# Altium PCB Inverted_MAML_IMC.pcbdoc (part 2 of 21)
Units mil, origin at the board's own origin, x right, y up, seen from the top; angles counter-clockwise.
Board outline 7677.1 x 6771.6 mil, 6 copper layers (Top Layer, Inner1, Inner2, Inner3, Inner4, Bottom Layer), stack 60.7 mil thick; 2732 components, 1531 nets, 7765 pads, 3699 vias.

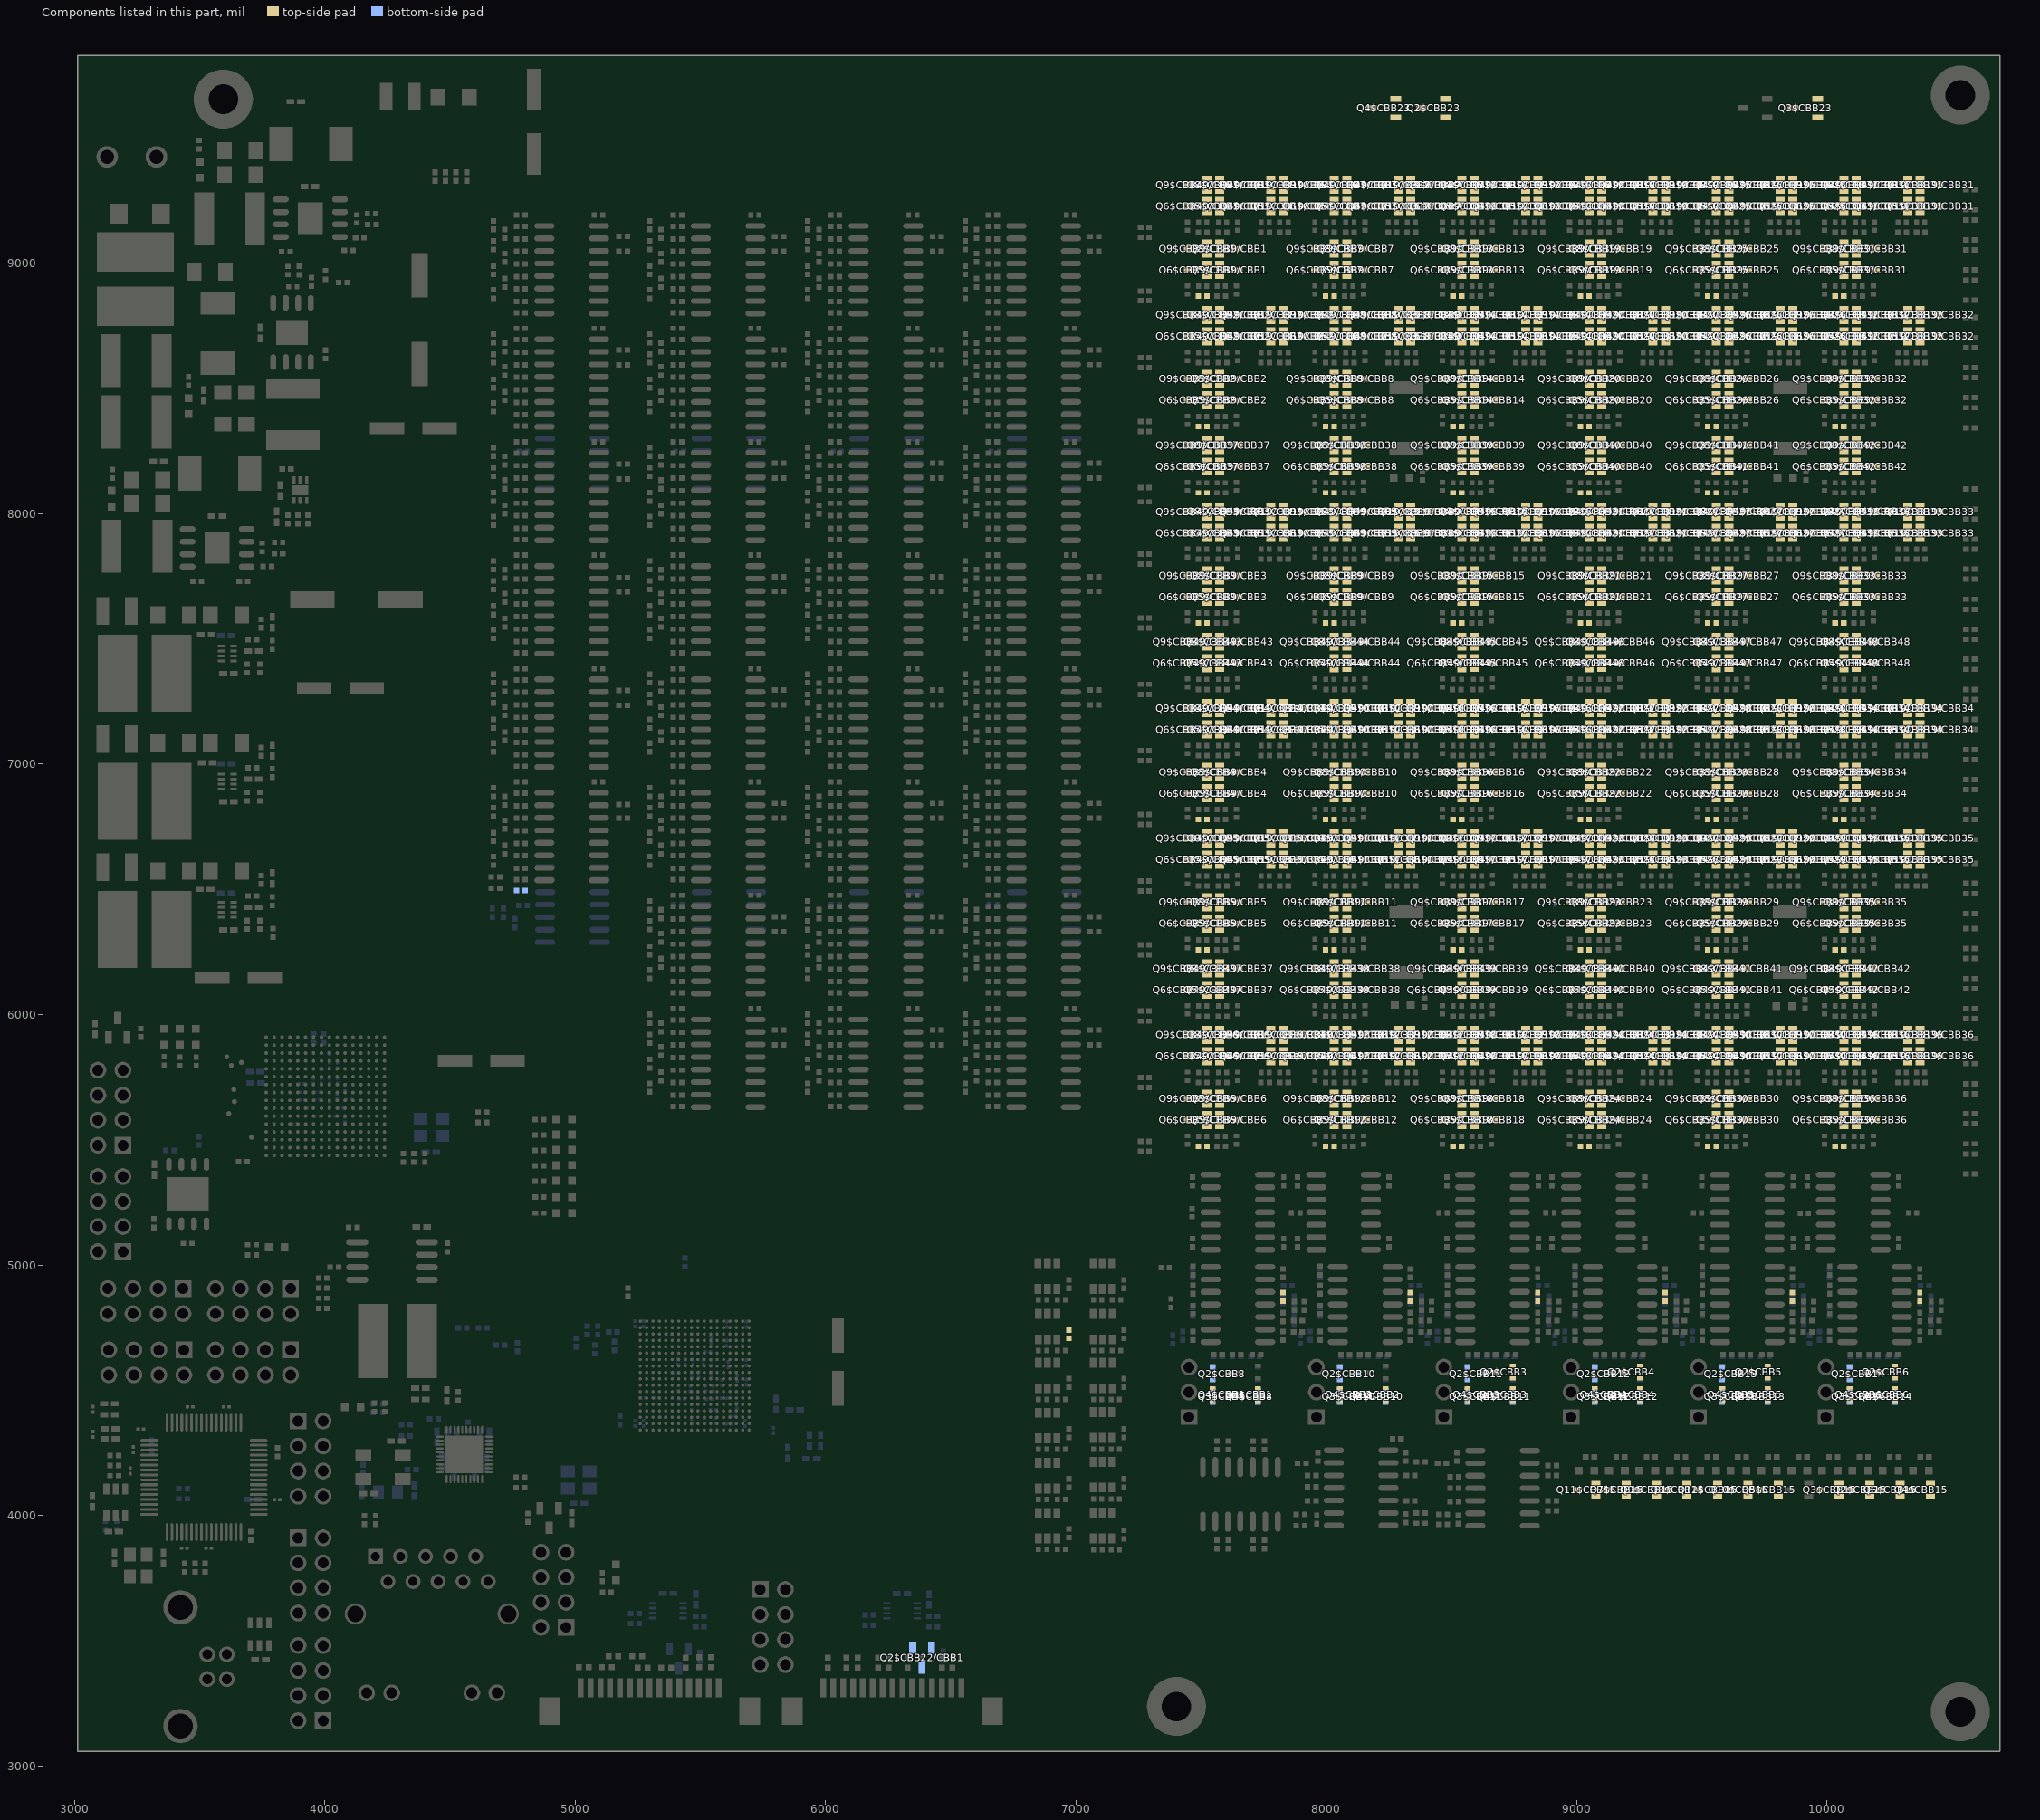
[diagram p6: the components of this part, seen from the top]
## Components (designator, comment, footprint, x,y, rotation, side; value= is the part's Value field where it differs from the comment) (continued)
Q2$CBB3 "MMBT3904WT1G" SC-70-3_L2.1-W1.3-P1.30-LS2.1-BR#2 8709.3,4572.2 r0 top
Q2$CBB4 "MMBT3904WT1G" SC-70-3_L2.1-W1.3-P1.30-LS2.1-BR#2 9218,4572.2 r0 top
Q2$CBB5 "MMBT3904WT1G" SC-70-3_L2.1-W1.3-P1.30-LS2.1-BR#2 9726.7,4572.2 r0 top
Q2$CBB6 "MMBT3904WT1G" SC-70-3_L2.1-W1.3-P1.30-LS2.1-BR#2 10235.4,4572.2 r0 top
Q2$CBB8 "MMBT3904WT1G" SC-70-3_L2.1-W1.3-P1.30-LS2.1-BR#3 7581.9,4565.4 r180 bottom
Q2$CBB10 "MMBT3904WT1G" SC-70-3_L2.1-W1.3-P1.30-LS2.1-BR#3 8090.6,4565.4 r180 bottom
Q2$CBB11 "MMBT3904WT1G" SC-70-3_L2.1-W1.3-P1.30-LS2.1-BR#3 8599.3,4565.4 r180 bottom
Q2$CBB12 "MMBT3904WT1G" SC-70-3_L2.1-W1.3-P1.30-LS2.1-BR#3 9108,4565.4 r180 bottom
Q2$CBB13 "MMBT3904WT1G" SC-70-3_L2.1-W1.3-P1.30-LS2.1-BR#3 9616.7,4565.4 r180 bottom
Q2$CBB14 "MMBT3904WT1G" SC-70-3_L2.1-W1.3-P1.30-LS2.1-BR#3 10125.4,4565.4 r180 bottom
Q2$CBB15 "DOX3134A" SOT-323-3_L2.1-W1.3-P1.30-LS2.3-BR#1 10132.5,4101.7 r0 top
Q2$CBB22/CBB1 "BSS138" SOT-23-3_L2.9-W1.3-P1.90-LS2.4-BR-1#2 6386.1,3431.7 r90 bottom
Q2$CBB23 "DO2320AA" SOT-23-3_L2.9-W1.6-P1.90-LS2.8-BR#2 8428.1,9619.9 r0 top
Q3$CBB1 "MMBT3904WT1G" SC-70-3_L2.1-W1.3-P1.30-LS2.1-BR#2 7691.9,4482.2 r0 top
Q3$CBB2 "MMBT3904WT1G" SC-70-3_L2.1-W1.3-P1.30-LS2.1-BR#2 8200.6,4482.2 r0 top
Q3$CBB3 "MMBT3904WT1G" SC-70-3_L2.1-W1.3-P1.30-LS2.1-BR#2 8709.3,4482.2 r0 top
Q3$CBB4 "MMBT3904WT1G" SC-70-3_L2.1-W1.3-P1.30-LS2.1-BR#2 9218,4482.2 r0 top
Q3$CBB5 "MMBT3904WT1G" SC-70-3_L2.1-W1.3-P1.30-LS2.1-BR#2 9726.7,4482.2 r0 top
Q3$CBB6 "MMBT3904WT1G" SC-70-3_L2.1-W1.3-P1.30-LS2.1-BR#2 10235.4,4482.2 r0 top
Q3$CBB8 "MMBT3904WT1G" SC-70-3_L2.1-W1.3-P1.30-LS2.1-BR#3 7581.9,4475.4 r180 bottom
Q3$CBB10 "MMBT3904WT1G" SC-70-3_L2.1-W1.3-P1.30-LS2.1-BR#3 8090.6,4475.4 r180 bottom
Q3$CBB11 "MMBT3904WT1G" SC-70-3_L2.1-W1.3-P1.30-LS2.1-BR#3 8599.3,4475.4 r180 bottom
Q3$CBB12 "MMBT3904WT1G" SC-70-3_L2.1-W1.3-P1.30-LS2.1-BR#3 9108,4475.4 r180 bottom
Q3$CBB13 "MMBT3904WT1G" SC-70-3_L2.1-W1.3-P1.30-LS2.1-BR#3 9616.7,4475.4 r180 bottom
Q3$CBB14 "MMBT3904WT1G" SC-70-3_L2.1-W1.3-P1.30-LS2.1-BR#3 10125.4,4475.4 r180 bottom
Q3$CBB15 "DOX3134A" SOT-323-3_L2.1-W1.3-P1.30-LS2.3-BR#1 10011,4101.7 r0 top
Q3$CBB23 "DO2320AA" SOT-23-3_L2.9-W1.6-P1.90-LS2.8-BR#1 9913.9,9619.9 r0 top
Q4$CBB1 "MMBT3904WT1G" SC-70-3_L2.1-W1.3-P1.30-LS2.1-BR#1 7582.4,4482.2 r180 top
Q4$CBB2 "MMBT3904WT1G" SC-70-3_L2.1-W1.3-P1.30-LS2.1-BR#1 8091.1,4482.2 r180 top
Q4$CBB3 "MMBT3904WT1G" SC-70-3_L2.1-W1.3-P1.30-LS2.1-BR#1 8599.8,4482.2 r180 top
Q4$CBB4 "MMBT3904WT1G" SC-70-3_L2.1-W1.3-P1.30-LS2.1-BR#1 9108.5,4482.2 r180 top
Q4$CBB5 "MMBT3904WT1G" SC-70-3_L2.1-W1.3-P1.30-LS2.1-BR#1 9617.2,4482.2 r180 top
Q4$CBB6 "MMBT3904WT1G" SC-70-3_L2.1-W1.3-P1.30-LS2.1-BR#1 10125.9,4482.2 r180 top
Q4$CBB8 "MMBT3904WT1G" SC-70-3_L2.1-W1.3-P1.30-LS2.1-BR#1 7691.9,4475.4 r0 bottom
Q4$CBB10 "MMBT3904WT1G" SC-70-3_L2.1-W1.3-P1.30-LS2.1-BR#1 8200.6,4475.4 r0 bottom
Q4$CBB11 "MMBT3904WT1G" SC-70-3_L2.1-W1.3-P1.30-LS2.1-BR#1 8709.3,4475.4 r0 bottom
Q4$CBB12 "MMBT3904WT1G" SC-70-3_L2.1-W1.3-P1.30-LS2.1-BR#1 9218,4475.4 r0 bottom
Q4$CBB13 "MMBT3904WT1G" SC-70-3_L2.1-W1.3-P1.30-LS2.1-BR#1 9726.7,4475.4 r0 bottom
Q4$CBB14 "MMBT3904WT1G" SC-70-3_L2.1-W1.3-P1.30-LS2.1-BR#1 10235.4,4475.4 r0 bottom
Q4$CBB15 "DOX3134A" SOT-323-3_L2.1-W1.3-P1.30-LS2.3-BR#1 10375.4,4101.7 r0 top
Q4$CBB23 "DO2320AA" SOT-23-3_L2.9-W1.6-P1.90-LS2.8-BR#2 8229.3,9619.9 r0 top
Q5$CBB9/CBB1 "DOX3134A" SOT-323-3_L2.1-W1.3-P1.30-LS2.3-BR#2 7611.2,8973.7 r180 top
Q5$CBB9/CBB2 "DOX3134A" SOT-323-3_L2.1-W1.3-P1.30-LS2.3-BR#2 7611.2,8453.7 r180 top
Q5$CBB9/CBB3 "DOX3134A" SOT-323-3_L2.1-W1.3-P1.30-LS2.3-BR#2 7611.2,7668.7 r180 top
Q5$CBB9/CBB4 "DOX3134A" SOT-323-3_L2.1-W1.3-P1.30-LS2.3-BR#2 7611.2,6883.7 r180 top
Q5$CBB9/CBB5 "DOX3134A" SOT-323-3_L2.1-W1.3-P1.30-LS2.3-BR#2 7611.2,6363.7 r180 top
Q5$CBB9/CBB6 "DOX3134A" SOT-323-3_L2.1-W1.3-P1.30-LS2.3-BR#2 7611.2,5578.7 r180 top
Q5$CBB9/CBB7 "DOX3134A" SOT-323-3_L2.1-W1.3-P1.30-LS2.3-BR#2 8119.9,8973.7 r180 top
Q5$CBB9/CBB8 "DOX3134A" SOT-323-3_L2.1-W1.3-P1.30-LS2.3-BR#2 8119.9,8453.7 r180 top
Q5$CBB9/CBB9 "DOX3134A" SOT-323-3_L2.1-W1.3-P1.30-LS2.3-BR#2 8119.9,7668.7 r180 top
Q5$CBB9/CBB10 "DOX3134A" SOT-323-3_L2.1-W1.3-P1.30-LS2.3-BR#2 8119.9,6883.7 r180 top
Q5$CBB9/CBB11 "DOX3134A" SOT-323-3_L2.1-W1.3-P1.30-LS2.3-BR#2 8119.9,6363.7 r180 top
Q5$CBB9/CBB12 "DOX3134A" SOT-323-3_L2.1-W1.3-P1.30-LS2.3-BR#2 8119.9,5578.7 r180 top
Q5$CBB9/CBB13 "DOX3134A" SOT-323-3_L2.1-W1.3-P1.30-LS2.3-BR#2 8628.6,8973.7 r180 top
Q5$CBB9/CBB14 "DOX3134A" SOT-323-3_L2.1-W1.3-P1.30-LS2.3-BR#2 8628.6,8453.7 r180 top
Q5$CBB9/CBB15 "DOX3134A" SOT-323-3_L2.1-W1.3-P1.30-LS2.3-BR#2 8628.6,7668.7 r180 top
Q5$CBB9/CBB16 "DOX3134A" SOT-323-3_L2.1-W1.3-P1.30-LS2.3-BR#2 8628.6,6883.7 r180 top
Q5$CBB9/CBB17 "DOX3134A" SOT-323-3_L2.1-W1.3-P1.30-LS2.3-BR#2 8628.6,6363.7 r180 top
Q5$CBB9/CBB18 "DOX3134A" SOT-323-3_L2.1-W1.3-P1.30-LS2.3-BR#2 8628.6,5578.7 r180 top
Q5$CBB9/CBB19 "DOX3134A" SOT-323-3_L2.1-W1.3-P1.30-LS2.3-BR#2 9137.3,8973.7 r180 top
Q5$CBB9/CBB20 "DOX3134A" SOT-323-3_L2.1-W1.3-P1.30-LS2.3-BR#2 9137.3,8453.7 r180 top
Q5$CBB9/CBB21 "DOX3134A" SOT-323-3_L2.1-W1.3-P1.30-LS2.3-BR#2 9137.3,7668.7 r180 top
Q5$CBB9/CBB22 "DOX3134A" SOT-323-3_L2.1-W1.3-P1.30-LS2.3-BR#2 9137.3,6883.7 r180 top
Q5$CBB9/CBB23 "DOX3134A" SOT-323-3_L2.1-W1.3-P1.30-LS2.3-BR#2 9137.3,6363.7 r180 top
Q5$CBB9/CBB24 "DOX3134A" SOT-323-3_L2.1-W1.3-P1.30-LS2.3-BR#2 9137.3,5578.7 r180 top
Q5$CBB9/CBB25 "DOX3134A" SOT-323-3_L2.1-W1.3-P1.30-LS2.3-BR#2 9646,8973.7 r180 top
Q5$CBB9/CBB26 "DOX3134A" SOT-323-3_L2.1-W1.3-P1.30-LS2.3-BR#2 9646,8453.7 r180 top
Q5$CBB9/CBB27 "DOX3134A" SOT-323-3_L2.1-W1.3-P1.30-LS2.3-BR#2 9646,7668.7 r180 top
Q5$CBB9/CBB28 "DOX3134A" SOT-323-3_L2.1-W1.3-P1.30-LS2.3-BR#2 9646,6883.7 r180 top
Q5$CBB9/CBB29 "DOX3134A" SOT-323-3_L2.1-W1.3-P1.30-LS2.3-BR#2 9646,6363.7 r180 top
Q5$CBB9/CBB30 "DOX3134A" SOT-323-3_L2.1-W1.3-P1.30-LS2.3-BR#2 9646,5578.7 r180 top
Q5$CBB9/CBB31 "DOX3134A" SOT-323-3_L2.1-W1.3-P1.30-LS2.3-BR#2 10154.7,8973.7 r180 top
Q5$CBB9/CBB32 "DOX3134A" SOT-323-3_L2.1-W1.3-P1.30-LS2.3-BR#2 10154.7,8453.7 r180 top
Q5$CBB9/CBB33 "DOX3134A" SOT-323-3_L2.1-W1.3-P1.30-LS2.3-BR#2 10154.7,7668.7 r180 top
Q5$CBB9/CBB34 "DOX3134A" SOT-323-3_L2.1-W1.3-P1.30-LS2.3-BR#2 10154.7,6883.7 r180 top
Q5$CBB9/CBB35 "DOX3134A" SOT-323-3_L2.1-W1.3-P1.30-LS2.3-BR#2 10154.7,6363.7 r180 top
Q5$CBB9/CBB36 "DOX3134A" SOT-323-3_L2.1-W1.3-P1.30-LS2.3-BR#2 10154.7,5578.7 r180 top
Q5$CBB9/CBB37 "DOX3134A" SOT-323-3_L2.1-W1.3-P1.30-LS2.3-BR#2 7611.2,8188.7 r180 top
Q5$CBB9/CBB38 "DOX3134A" SOT-323-3_L2.1-W1.3-P1.30-LS2.3-BR#2 8119.9,8188.7 r180 top
Q5$CBB9/CBB39 "DOX3134A" SOT-323-3_L2.1-W1.3-P1.30-LS2.3-BR#2 8628.6,8188.7 r180 top
Q5$CBB9/CBB40 "DOX3134A" SOT-323-3_L2.1-W1.3-P1.30-LS2.3-BR#2 9137.3,8188.7 r180 top
Q5$CBB9/CBB41 "DOX3134A" SOT-323-3_L2.1-W1.3-P1.30-LS2.3-BR#2 9646,8188.7 r180 top
Q5$CBB9/CBB42 "DOX3134A" SOT-323-3_L2.1-W1.3-P1.30-LS2.3-BR#2 10154.7,8188.7 r180 top
Q5$CBB15 "DOX3134A" SOT-323-3_L2.1-W1.3-P1.30-LS2.3-BR#1 9768.1,4101.7 r0 top
Q5$CBB19/CBB1 "DOX3134A" SOT-323-3_L2.1-W1.3-P1.30-LS2.3-BR#2 7866.2,9228.7 r180 top
Q5$CBB19/CBB2 "DOX3134A" SOT-323-3_L2.1-W1.3-P1.30-LS2.3-BR#1 7866.2,8708.7 r180 top
Q5$CBB19/CBB3 "DOX3134A" SOT-323-3_L2.1-W1.3-P1.30-LS2.3-BR#1 7866.2,7923.7 r180 top
Q5$CBB19/CBB4 "DOX3134A" SOT-323-3_L2.1-W1.3-P1.30-LS2.3-BR#1 7866.2,7138.7 r180 top
Q5$CBB19/CBB5 "DOX3134A" SOT-323-3_L2.1-W1.3-P1.30-LS2.3-BR#1 7866.2,6618.7 r180 top
Q5$CBB19/CBB6 "DOX3134A" SOT-323-3_L2.1-W1.3-P1.30-LS2.3-BR#1 7866.2,5833.7 r180 top
Q5$CBB19/CBB7 "DOX3134A" SOT-323-3_L2.1-W1.3-P1.30-LS2.3-BR#1 8374.9,9228.7 r180 top
Q5$CBB19/CBB8 "DOX3134A" SOT-323-3_L2.1-W1.3-P1.30-LS2.3-BR#1 8374.9,8708.7 r180 top
Q5$CBB19/CBB9 "DOX3134A" SOT-323-3_L2.1-W1.3-P1.30-LS2.3-BR#1 8374.9,7923.7 r180 top
Q5$CBB19/CBB10 "DOX3134A" SOT-323-3_L2.1-W1.3-P1.30-LS2.3-BR#1 8374.9,7138.7 r180 top
Q5$CBB19/CBB11 "DOX3134A" SOT-323-3_L2.1-W1.3-P1.30-LS2.3-BR#1 8374.9,6618.7 r180 top
Q5$CBB19/CBB12 "DOX3134A" SOT-323-3_L2.1-W1.3-P1.30-LS2.3-BR#1 8374.9,5833.7 r180 top
Q5$CBB19/CBB13 "DOX3134A" SOT-323-3_L2.1-W1.3-P1.30-LS2.3-BR#1 8883.6,9228.7 r180 top
Q5$CBB19/CBB14 "DOX3134A" SOT-323-3_L2.1-W1.3-P1.30-LS2.3-BR#1 8883.6,8708.7 r180 top
Q5$CBB19/CBB15 "DOX3134A" SOT-323-3_L2.1-W1.3-P1.30-LS2.3-BR#1 8883.6,7923.7 r180 top
Q5$CBB19/CBB16 "DOX3134A" SOT-323-3_L2.1-W1.3-P1.30-LS2.3-BR#1 8883.6,7138.7 r180 top
Q5$CBB19/CBB17 "DOX3134A" SOT-323-3_L2.1-W1.3-P1.30-LS2.3-BR#1 8883.6,6618.7 r180 top
Q5$CBB19/CBB18 "DOX3134A" SOT-323-3_L2.1-W1.3-P1.30-LS2.3-BR#1 8883.6,5833.7 r180 top
Q5$CBB19/CBB19 "DOX3134A" SOT-323-3_L2.1-W1.3-P1.30-LS2.3-BR#1 9392.3,9228.7 r180 top
Q5$CBB19/CBB20 "DOX3134A" SOT-323-3_L2.1-W1.3-P1.30-LS2.3-BR#1 9392.3,8708.7 r180 top
Q5$CBB19/CBB21 "DOX3134A" SOT-323-3_L2.1-W1.3-P1.30-LS2.3-BR#1 9392.3,7923.7 r180 top
Q5$CBB19/CBB22 "DOX3134A" SOT-323-3_L2.1-W1.3-P1.30-LS2.3-BR#1 9392.3,7138.7 r180 top
Q5$CBB19/CBB23 "DOX3134A" SOT-323-3_L2.1-W1.3-P1.30-LS2.3-BR#1 9392.3,6618.7 r180 top
Q5$CBB19/CBB24 "DOX3134A" SOT-323-3_L2.1-W1.3-P1.30-LS2.3-BR#1 9392.3,5833.7 r180 top
Q5$CBB19/CBB25 "DOX3134A" SOT-323-3_L2.1-W1.3-P1.30-LS2.3-BR#1 9901,9228.7 r180 top
Q5$CBB19/CBB26 "DOX3134A" SOT-323-3_L2.1-W1.3-P1.30-LS2.3-BR#1 9901,8708.7 r180 top
Q5$CBB19/CBB27 "DOX3134A" SOT-323-3_L2.1-W1.3-P1.30-LS2.3-BR#1 9901,7923.7 r180 top
Q5$CBB19/CBB28 "DOX3134A" SOT-323-3_L2.1-W1.3-P1.30-LS2.3-BR#1 9901,7138.7 r180 top
Q5$CBB19/CBB29 "DOX3134A" SOT-323-3_L2.1-W1.3-P1.30-LS2.3-BR#1 9901,6618.7 r180 top
Q5$CBB19/CBB30 "DOX3134A" SOT-323-3_L2.1-W1.3-P1.30-LS2.3-BR#1 9901,5833.7 r180 top
Q5$CBB19/CBB31 "DOX3134A" SOT-323-3_L2.1-W1.3-P1.30-LS2.3-BR#1 10409.7,9228.7 r180 top
Q5$CBB19/CBB32 "DOX3134A" SOT-323-3_L2.1-W1.3-P1.30-LS2.3-BR#1 10409.7,8708.7 r180 top
Q5$CBB19/CBB33 "DOX3134A" SOT-323-3_L2.1-W1.3-P1.30-LS2.3-BR#1 10409.7,7923.7 r180 top
Q5$CBB19/CBB34 "DOX3134A" SOT-323-3_L2.1-W1.3-P1.30-LS2.3-BR#1 10409.7,7138.7 r180 top
Q5$CBB19/CBB35 "DOX3134A" SOT-323-3_L2.1-W1.3-P1.30-LS2.3-BR#1 10409.7,6618.7 r180 top
Q5$CBB19/CBB36 "DOX3134A" SOT-323-3_L2.1-W1.3-P1.30-LS2.3-BR#1 10409.7,5833.7 r180 top
Q5$CBB49/CBB1 "DOX3134A" SOT-323-3_L2.1-W1.3-P1.30-LS2.3-BR#2 7611.2,9228.7 r180 top
Q5$CBB49/CBB2 "DOX3134A" SOT-323-3_L2.1-W1.3-P1.30-LS2.3-BR#2 7611.2,8708.7 r180 top
Q5$CBB49/CBB3 "DOX3134A" SOT-323-3_L2.1-W1.3-P1.30-LS2.3-BR#2 7611.2,7923.7 r180 top
Q5$CBB49/CBB4 "DOX3134A" SOT-323-3_L2.1-W1.3-P1.30-LS2.3-BR#2 7611.2,7138.7 r180 top
Q5$CBB49/CBB5 "DOX3134A" SOT-323-3_L2.1-W1.3-P1.30-LS2.3-BR#2 7611.2,6618.7 r180 top
Q5$CBB49/CBB6 "DOX3134A" SOT-323-3_L2.1-W1.3-P1.30-LS2.3-BR#2 7611.2,5833.7 r180 top
Q5$CBB49/CBB7 "DOX3134A" SOT-323-3_L2.1-W1.3-P1.30-LS2.3-BR#2 8119.9,9228.7 r180 top
Q5$CBB49/CBB8 "DOX3134A" SOT-323-3_L2.1-W1.3-P1.30-LS2.3-BR#2 8119.9,8708.7 r180 top
Q5$CBB49/CBB9 "DOX3134A" SOT-323-3_L2.1-W1.3-P1.30-LS2.3-BR#2 8119.9,7923.7 r180 top
Q5$CBB49/CBB10 "DOX3134A" SOT-323-3_L2.1-W1.3-P1.30-LS2.3-BR#2 8119.9,7138.7 r180 top
Q5$CBB49/CBB11 "DOX3134A" SOT-323-3_L2.1-W1.3-P1.30-LS2.3-BR#2 8119.9,6618.7 r180 top
Q5$CBB49/CBB12 "DOX3134A" SOT-323-3_L2.1-W1.3-P1.30-LS2.3-BR#2 8119.9,5833.7 r180 top
Q5$CBB49/CBB13 "DOX3134A" SOT-323-3_L2.1-W1.3-P1.30-LS2.3-BR#2 8628.6,9228.7 r180 top
Q5$CBB49/CBB14 "DOX3134A" SOT-323-3_L2.1-W1.3-P1.30-LS2.3-BR#2 8628.6,8708.7 r180 top
Q5$CBB49/CBB15 "DOX3134A" SOT-323-3_L2.1-W1.3-P1.30-LS2.3-BR#2 8628.6,7923.7 r180 top
Q5$CBB49/CBB16 "DOX3134A" SOT-323-3_L2.1-W1.3-P1.30-LS2.3-BR#2 8628.6,7138.7 r180 top
Q5$CBB49/CBB17 "DOX3134A" SOT-323-3_L2.1-W1.3-P1.30-LS2.3-BR#2 8628.6,6618.7 r180 top
Q5$CBB49/CBB18 "DOX3134A" SOT-323-3_L2.1-W1.3-P1.30-LS2.3-BR#2 8628.6,5833.7 r180 top
Q5$CBB49/CBB19 "DOX3134A" SOT-323-3_L2.1-W1.3-P1.30-LS2.3-BR#2 9137.3,9228.7 r180 top
Q5$CBB49/CBB20 "DOX3134A" SOT-323-3_L2.1-W1.3-P1.30-LS2.3-BR#2 9137.3,8708.7 r180 top
Q5$CBB49/CBB21 "DOX3134A" SOT-323-3_L2.1-W1.3-P1.30-LS2.3-BR#2 9137.3,7923.7 r180 top
Q5$CBB49/CBB22 "DOX3134A" SOT-323-3_L2.1-W1.3-P1.30-LS2.3-BR#2 9137.3,7138.7 r180 top
Q5$CBB49/CBB23 "DOX3134A" SOT-323-3_L2.1-W1.3-P1.30-LS2.3-BR#2 9137.3,6618.7 r180 top
Q5$CBB49/CBB24 "DOX3134A" SOT-323-3_L2.1-W1.3-P1.30-LS2.3-BR#2 9137.3,5833.7 r180 top
Q5$CBB49/CBB25 "DOX3134A" SOT-323-3_L2.1-W1.3-P1.30-LS2.3-BR#2 9646,9228.7 r180 top
Q5$CBB49/CBB26 "DOX3134A" SOT-323-3_L2.1-W1.3-P1.30-LS2.3-BR#2 9646,8708.7 r180 top
Q5$CBB49/CBB27 "DOX3134A" SOT-323-3_L2.1-W1.3-P1.30-LS2.3-BR#2 9646,7923.7 r180 top
Q5$CBB49/CBB28 "DOX3134A" SOT-323-3_L2.1-W1.3-P1.30-LS2.3-BR#2 9646,7138.7 r180 top
Q5$CBB49/CBB29 "DOX3134A" SOT-323-3_L2.1-W1.3-P1.30-LS2.3-BR#2 9646,6618.7 r180 top
Q5$CBB49/CBB30 "DOX3134A" SOT-323-3_L2.1-W1.3-P1.30-LS2.3-BR#2 9646,5833.7 r180 top
Q5$CBB49/CBB31 "DOX3134A" SOT-323-3_L2.1-W1.3-P1.30-LS2.3-BR#2 10154.7,9228.7 r180 top
Q5$CBB49/CBB32 "DOX3134A" SOT-323-3_L2.1-W1.3-P1.30-LS2.3-BR#2 10154.7,8708.7 r180 top
Q5$CBB49/CBB33 "DOX3134A" SOT-323-3_L2.1-W1.3-P1.30-LS2.3-BR#2 10154.7,7923.7 r180 top
Q5$CBB49/CBB34 "DOX3134A" SOT-323-3_L2.1-W1.3-P1.30-LS2.3-BR#2 10154.7,7138.7 r180 top
Q5$CBB49/CBB35 "DOX3134A" SOT-323-3_L2.1-W1.3-P1.30-LS2.3-BR#2 10154.7,6618.7 r180 top
Q5$CBB49/CBB36 "DOX3134A" SOT-323-3_L2.1-W1.3-P1.30-LS2.3-BR#2 10154.7,5833.7 r180 top
Q5$CBB49/CBB37 "DOX3134A" SOT-323-3_L2.1-W1.3-P1.30-LS2.3-BR#2 7611.2,6098.7 r180 top
Q5$CBB49/CBB38 "DOX3134A" SOT-323-3_L2.1-W1.3-P1.30-LS2.3-BR#2 8119.9,6098.7 r180 top
Q5$CBB49/CBB39 "DOX3134A" SOT-323-3_L2.1-W1.3-P1.30-LS2.3-BR#2 8628.6,6098.7 r180 top
Q5$CBB49/CBB40 "DOX3134A" SOT-323-3_L2.1-W1.3-P1.30-LS2.3-BR#2 9137.3,6098.7 r180 top
Q5$CBB49/CBB41 "DOX3134A" SOT-323-3_L2.1-W1.3-P1.30-LS2.3-BR#2 9646,6098.7 r180 top
Q5$CBB49/CBB42 "DOX3134A" SOT-323-3_L2.1-W1.3-P1.30-LS2.3-BR#2 10154.7,6098.7 r180 top
Q5$CBB49/CBB43 "DOX3134A" SOT-323-3_L2.1-W1.3-P1.30-LS2.3-BR#2 7611.2,7403.7 r180 top
Q5$CBB49/CBB44 "DOX3134A" SOT-323-3_L2.1-W1.3-P1.30-LS2.3-BR#2 8119.9,7403.7 r180 top
Q5$CBB49/CBB45 "DOX3134A" SOT-323-3_L2.1-W1.3-P1.30-LS2.3-BR#2 8628.6,7403.7 r180 top
Q5$CBB49/CBB46 "DOX3134A" SOT-323-3_L2.1-W1.3-P1.30-LS2.3-BR#2 9137.3,7403.7 r180 top
Q5$CBB49/CBB47 "DOX3134A" SOT-323-3_L2.1-W1.3-P1.30-LS2.3-BR#2 9646,7403.7 r180 top
Q5$CBB49/CBB48 "DOX3134A" SOT-323-3_L2.1-W1.3-P1.30-LS2.3-BR#2 10154.7,7403.7 r180 top
Q6$CBB9/CBB1 "DOX3134A" SOT-323-3_L2.1-W1.3-P1.30-LS2.3-BR#1 7486.2,8973.7 r0 top
Q6$CBB9/CBB2 "DOX3134A" SOT-323-3_L2.1-W1.3-P1.30-LS2.3-BR#1 7486.2,8453.7 r0 top
Q6$CBB9/CBB3 "DOX3134A" SOT-323-3_L2.1-W1.3-P1.30-LS2.3-BR#1 7486.2,7668.7 r0 top
Q6$CBB9/CBB4 "DOX3134A" SOT-323-3_L2.1-W1.3-P1.30-LS2.3-BR#1 7486.2,6883.7 r0 top
Q6$CBB9/CBB5 "DOX3134A" SOT-323-3_L2.1-W1.3-P1.30-LS2.3-BR#1 7486.2,6363.7 r0 top
Q6$CBB9/CBB6 "DOX3134A" SOT-323-3_L2.1-W1.3-P1.30-LS2.3-BR#1 7486.2,5578.7 r0 top
Q6$CBB9/CBB7 "DOX3134A" SOT-323-3_L2.1-W1.3-P1.30-LS2.3-BR#1 7994.9,8973.7 r0 top
Q6$CBB9/CBB8 "DOX3134A" SOT-323-3_L2.1-W1.3-P1.30-LS2.3-BR#1 7994.9,8453.7 r0 top
Q6$CBB9/CBB9 "DOX3134A" SOT-323-3_L2.1-W1.3-P1.30-LS2.3-BR#1 7994.9,7668.7 r0 top
Q6$CBB9/CBB10 "DOX3134A" SOT-323-3_L2.1-W1.3-P1.30-LS2.3-BR#1 7994.9,6883.7 r0 top
Q6$CBB9/CBB11 "DOX3134A" SOT-323-3_L2.1-W1.3-P1.30-LS2.3-BR#1 7994.9,6363.7 r0 top
Q6$CBB9/CBB12 "DOX3134A" SOT-323-3_L2.1-W1.3-P1.30-LS2.3-BR#1 7994.9,5578.7 r0 top
Q6$CBB9/CBB13 "DOX3134A" SOT-323-3_L2.1-W1.3-P1.30-LS2.3-BR#1 8503.6,8973.7 r0 top
Q6$CBB9/CBB14 "DOX3134A" SOT-323-3_L2.1-W1.3-P1.30-LS2.3-BR#1 8503.6,8453.7 r0 top
Q6$CBB9/CBB15 "DOX3134A" SOT-323-3_L2.1-W1.3-P1.30-LS2.3-BR#1 8503.6,7668.7 r0 top
Q6$CBB9/CBB16 "DOX3134A" SOT-323-3_L2.1-W1.3-P1.30-LS2.3-BR#1 8503.6,6883.7 r0 top
Q6$CBB9/CBB17 "DOX3134A" SOT-323-3_L2.1-W1.3-P1.30-LS2.3-BR#1 8503.6,6363.7 r0 top
Q6$CBB9/CBB18 "DOX3134A" SOT-323-3_L2.1-W1.3-P1.30-LS2.3-BR#1 8503.6,5578.7 r0 top
Q6$CBB9/CBB19 "DOX3134A" SOT-323-3_L2.1-W1.3-P1.30-LS2.3-BR#1 9012.3,8973.7 r0 top
Q6$CBB9/CBB20 "DOX3134A" SOT-323-3_L2.1-W1.3-P1.30-LS2.3-BR#1 9012.3,8453.7 r0 top
Q6$CBB9/CBB21 "DOX3134A" SOT-323-3_L2.1-W1.3-P1.30-LS2.3-BR#1 9012.3,7668.7 r0 top
Q6$CBB9/CBB22 "DOX3134A" SOT-323-3_L2.1-W1.3-P1.30-LS2.3-BR#1 9012.3,6883.7 r0 top
Q6$CBB9/CBB23 "DOX3134A" SOT-323-3_L2.1-W1.3-P1.30-LS2.3-BR#1 9012.3,6363.7 r0 top
Q6$CBB9/CBB24 "DOX3134A" SOT-323-3_L2.1-W1.3-P1.30-LS2.3-BR#1 9012.3,5578.7 r0 top
Q6$CBB9/CBB25 "DOX3134A" SOT-323-3_L2.1-W1.3-P1.30-LS2.3-BR#1 9521,8973.7 r0 top
Q6$CBB9/CBB26 "DOX3134A" SOT-323-3_L2.1-W1.3-P1.30-LS2.3-BR#1 9521,8453.7 r0 top
Q6$CBB9/CBB27 "DOX3134A" SOT-323-3_L2.1-W1.3-P1.30-LS2.3-BR#1 9521,7668.7 r0 top
Q6$CBB9/CBB28 "DOX3134A" SOT-323-3_L2.1-W1.3-P1.30-LS2.3-BR#1 9521,6883.7 r0 top
Q6$CBB9/CBB29 "DOX3134A" SOT-323-3_L2.1-W1.3-P1.30-LS2.3-BR#1 9521,6363.7 r0 top
Q6$CBB9/CBB30 "DOX3134A" SOT-323-3_L2.1-W1.3-P1.30-LS2.3-BR#1 9521,5578.7 r0 top
Q6$CBB9/CBB31 "DOX3134A" SOT-323-3_L2.1-W1.3-P1.30-LS2.3-BR#1 10029.7,8973.7 r0 top
Q6$CBB9/CBB32 "DOX3134A" SOT-323-3_L2.1-W1.3-P1.30-LS2.3-BR#1 10029.7,8453.7 r0 top
Q6$CBB9/CBB33 "DOX3134A" SOT-323-3_L2.1-W1.3-P1.30-LS2.3-BR#1 10029.7,7668.7 r0 top
Q6$CBB9/CBB34 "DOX3134A" SOT-323-3_L2.1-W1.3-P1.30-LS2.3-BR#1 10029.7,6883.7 r0 top
Q6$CBB9/CBB35 "DOX3134A" SOT-323-3_L2.1-W1.3-P1.30-LS2.3-BR#1 10029.7,6363.7 r0 top
Q6$CBB9/CBB36 "DOX3134A" SOT-323-3_L2.1-W1.3-P1.30-LS2.3-BR#1 10029.7,5578.7 r0 top
Q6$CBB9/CBB37 "DOX3134A" SOT-323-3_L2.1-W1.3-P1.30-LS2.3-BR#1 7486.2,8188.7 r0 top
Q6$CBB9/CBB38 "DOX3134A" SOT-323-3_L2.1-W1.3-P1.30-LS2.3-BR#1 7994.9,8188.7 r0 top
Q6$CBB9/CBB39 "DOX3134A" SOT-323-3_L2.1-W1.3-P1.30-LS2.3-BR#1 8503.6,8188.7 r0 top
Q6$CBB9/CBB40 "DOX3134A" SOT-323-3_L2.1-W1.3-P1.30-LS2.3-BR#1 9012.3,8188.7 r0 top
Q6$CBB9/CBB41 "DOX3134A" SOT-323-3_L2.1-W1.3-P1.30-LS2.3-BR#1 9521,8188.7 r0 top
Q6$CBB9/CBB42 "DOX3134A" SOT-323-3_L2.1-W1.3-P1.30-LS2.3-BR#1 10029.7,8188.7 r0 top
Q6$CBB15 "DOX3134A" SOT-323-3_L2.1-W1.3-P1.30-LS2.3-BR#1 10253.9,4101.7 r0 top
Q6$CBB19/CBB1 "DOX3134A" SOT-323-3_L2.1-W1.3-P1.30-LS2.3-BR#1 7741.2,9228.7 r0 top
Q6$CBB19/CBB2 "DOX3134A" SOT-323-3_L2.1-W1.3-P1.30-LS2.3-BR#1 7741.2,8708.7 r0 top
Q6$CBB19/CBB3 "DOX3134A" SOT-323-3_L2.1-W1.3-P1.30-LS2.3-BR#1 7741.2,7923.7 r0 top
Q6$CBB19/CBB4 "DOX3134A" SOT-323-3_L2.1-W1.3-P1.30-LS2.3-BR#1 7741.2,7138.7 r0 top
Q6$CBB19/CBB5 "DOX3134A" SOT-323-3_L2.1-W1.3-P1.30-LS2.3-BR#1 7741.2,6618.7 r0 top
Q6$CBB19/CBB6 "DOX3134A" SOT-323-3_L2.1-W1.3-P1.30-LS2.3-BR#1 7741.2,5833.7 r0 top
Q6$CBB19/CBB7 "DOX3134A" SOT-323-3_L2.1-W1.3-P1.30-LS2.3-BR#1 8249.9,9228.7 r0 top
Q6$CBB19/CBB8 "DOX3134A" SOT-323-3_L2.1-W1.3-P1.30-LS2.3-BR#1 8249.9,8708.7 r0 top
Q6$CBB19/CBB9 "DOX3134A" SOT-323-3_L2.1-W1.3-P1.30-LS2.3-BR#1 8249.9,7923.7 r0 top
Q6$CBB19/CBB10 "DOX3134A" SOT-323-3_L2.1-W1.3-P1.30-LS2.3-BR#1 8249.9,7138.7 r0 top
Q6$CBB19/CBB11 "DOX3134A" SOT-323-3_L2.1-W1.3-P1.30-LS2.3-BR#1 8249.9,6618.7 r0 top
Q6$CBB19/CBB12 "DOX3134A" SOT-323-3_L2.1-W1.3-P1.30-LS2.3-BR#1 8249.9,5833.7 r0 top
Q6$CBB19/CBB13 "DOX3134A" SOT-323-3_L2.1-W1.3-P1.30-LS2.3-BR#1 8758.6,9228.7 r0 top
Q6$CBB19/CBB14 "DOX3134A" SOT-323-3_L2.1-W1.3-P1.30-LS2.3-BR#1 8758.6,8708.7 r0 top
Q6$CBB19/CBB15 "DOX3134A" SOT-323-3_L2.1-W1.3-P1.30-LS2.3-BR#1 8758.6,7923.7 r0 top
Q6$CBB19/CBB16 "DOX3134A" SOT-323-3_L2.1-W1.3-P1.30-LS2.3-BR#1 8758.6,7138.7 r0 top
Q6$CBB19/CBB17 "DOX3134A" SOT-323-3_L2.1-W1.3-P1.30-LS2.3-BR#1 8758.6,6618.7 r0 top
Q6$CBB19/CBB18 "DOX3134A" SOT-323-3_L2.1-W1.3-P1.30-LS2.3-BR#1 8758.6,5833.7 r0 top
Q6$CBB19/CBB19 "DOX3134A" SOT-323-3_L2.1-W1.3-P1.30-LS2.3-BR#1 9267.3,9228.7 r0 top
Q6$CBB19/CBB20 "DOX3134A" SOT-323-3_L2.1-W1.3-P1.30-LS2.3-BR#1 9267.3,8708.7 r0 top
Q6$CBB19/CBB21 "DOX3134A" SOT-323-3_L2.1-W1.3-P1.30-LS2.3-BR#1 9267.3,7923.7 r0 top
Q6$CBB19/CBB22 "DOX3134A" SOT-323-3_L2.1-W1.3-P1.30-LS2.3-BR#1 9267.3,7138.7 r0 top
Q6$CBB19/CBB23 "DOX3134A" SOT-323-3_L2.1-W1.3-P1.30-LS2.3-BR#1 9267.3,6618.7 r0 top
Q6$CBB19/CBB24 "DOX3134A" SOT-323-3_L2.1-W1.3-P1.30-LS2.3-BR#1 9267.3,5833.7 r0 top
Q6$CBB19/CBB25 "DOX3134A" SOT-323-3_L2.1-W1.3-P1.30-LS2.3-BR#1 9776,9228.7 r0 top
Q6$CBB19/CBB26 "DOX3134A" SOT-323-3_L2.1-W1.3-P1.30-LS2.3-BR#1 9776,8708.7 r0 top
Q6$CBB19/CBB27 "DOX3134A" SOT-323-3_L2.1-W1.3-P1.30-LS2.3-BR#1 9776,7923.7 r0 top
Q6$CBB19/CBB28 "DOX3134A" SOT-323-3_L2.1-W1.3-P1.30-LS2.3-BR#1 9776,7138.7 r0 top
Q6$CBB19/CBB29 "DOX3134A" SOT-323-3_L2.1-W1.3-P1.30-LS2.3-BR#1 9776,6618.7 r0 top
Q6$CBB19/CBB30 "DOX3134A" SOT-323-3_L2.1-W1.3-P1.30-LS2.3-BR#1 9776,5833.7 r0 top
Q6$CBB19/CBB31 "DOX3134A" SOT-323-3_L2.1-W1.3-P1.30-LS2.3-BR#1 10284.7,9228.7 r0 top
Q6$CBB19/CBB32 "DOX3134A" SOT-323-3_L2.1-W1.3-P1.30-LS2.3-BR#1 10284.7,8708.7 r0 top
Q6$CBB19/CBB33 "DOX3134A" SOT-323-3_L2.1-W1.3-P1.30-LS2.3-BR#1 10284.7,7923.7 r0 top
Q6$CBB19/CBB34 "DOX3134A" SOT-323-3_L2.1-W1.3-P1.30-LS2.3-BR#1 10284.7,7138.7 r0 top
Q6$CBB19/CBB35 "DOX3134A" SOT-323-3_L2.1-W1.3-P1.30-LS2.3-BR#1 10284.7,6618.7 r0 top
Q6$CBB19/CBB36 "DOX3134A" SOT-323-3_L2.1-W1.3-P1.30-LS2.3-BR#1 10284.7,5833.7 r0 top
Q6$CBB49/CBB1 "DOX3134A" SOT-323-3_L2.1-W1.3-P1.30-LS2.3-BR#1 7486.2,9228.7 r0 top
Q6$CBB49/CBB2 "DOX3134A" SOT-323-3_L2.1-W1.3-P1.30-LS2.3-BR#1 7486.2,8708.7 r0 top
Q6$CBB49/CBB3 "DOX3134A" SOT-323-3_L2.1-W1.3-P1.30-LS2.3-BR#1 7486.2,7923.7 r0 top
Q6$CBB49/CBB4 "DOX3134A" SOT-323-3_L2.1-W1.3-P1.30-LS2.3-BR#1 7486.2,7138.7 r0 top
Q6$CBB49/CBB5 "DOX3134A" SOT-323-3_L2.1-W1.3-P1.30-LS2.3-BR#1 7486.2,6618.7 r0 top
Q6$CBB49/CBB6 "DOX3134A" SOT-323-3_L2.1-W1.3-P1.30-LS2.3-BR#1 7486.2,5833.7 r0 top
Q6$CBB49/CBB7 "DOX3134A" SOT-323-3_L2.1-W1.3-P1.30-LS2.3-BR#1 7994.9,9228.7 r0 top
Q6$CBB49/CBB8 "DOX3134A" SOT-323-3_L2.1-W1.3-P1.30-LS2.3-BR#1 7994.9,8708.7 r0 top
Q6$CBB49/CBB9 "DOX3134A" SOT-323-3_L2.1-W1.3-P1.30-LS2.3-BR#1 7994.9,7923.7 r0 top
Q6$CBB49/CBB10 "DOX3134A" SOT-323-3_L2.1-W1.3-P1.30-LS2.3-BR#1 7994.9,7138.7 r0 top
Q6$CBB49/CBB11 "DOX3134A" SOT-323-3_L2.1-W1.3-P1.30-LS2.3-BR#1 7994.9,6618.7 r0 top
Q6$CBB49/CBB12 "DOX3134A" SOT-323-3_L2.1-W1.3-P1.30-LS2.3-BR#1 7994.9,5833.7 r0 top
Q6$CBB49/CBB13 "DOX3134A" SOT-323-3_L2.1-W1.3-P1.30-LS2.3-BR#1 8503.6,9228.7 r0 top
Q6$CBB49/CBB14 "DOX3134A" SOT-323-3_L2.1-W1.3-P1.30-LS2.3-BR#1 8503.6,8708.7 r0 top
Q6$CBB49/CBB15 "DOX3134A" SOT-323-3_L2.1-W1.3-P1.30-LS2.3-BR#1 8503.6,7923.7 r0 top
Q6$CBB49/CBB16 "DOX3134A" SOT-323-3_L2.1-W1.3-P1.30-LS2.3-BR#1 8503.6,7138.7 r0 top
Q6$CBB49/CBB17 "DOX3134A" SOT-323-3_L2.1-W1.3-P1.30-LS2.3-BR#1 8503.6,6618.7 r0 top
Q6$CBB49/CBB18 "DOX3134A" SOT-323-3_L2.1-W1.3-P1.30-LS2.3-BR#1 8503.6,5833.7 r0 top
Q6$CBB49/CBB19 "DOX3134A" SOT-323-3_L2.1-W1.3-P1.30-LS2.3-BR#1 9012.3,9228.7 r0 top
Q6$CBB49/CBB20 "DOX3134A" SOT-323-3_L2.1-W1.3-P1.30-LS2.3-BR#1 9012.3,8708.7 r0 top
Q6$CBB49/CBB21 "DOX3134A" SOT-323-3_L2.1-W1.3-P1.30-LS2.3-BR#1 9012.3,7923.7 r0 top
Q6$CBB49/CBB22 "DOX3134A" SOT-323-3_L2.1-W1.3-P1.30-LS2.3-BR#1 9012.3,7138.7 r0 top
Q6$CBB49/CBB23 "DOX3134A" SOT-323-3_L2.1-W1.3-P1.30-LS2.3-BR#1 9012.3,6618.7 r0 top
Q6$CBB49/CBB24 "DOX3134A" SOT-323-3_L2.1-W1.3-P1.30-LS2.3-BR#1 9012.3,5833.7 r0 top
Q6$CBB49/CBB25 "DOX3134A" SOT-323-3_L2.1-W1.3-P1.30-LS2.3-BR#1 9521,9228.7 r0 top
Q6$CBB49/CBB26 "DOX3134A" SOT-323-3_L2.1-W1.3-P1.30-LS2.3-BR#1 9521,8708.7 r0 top
Q6$CBB49/CBB27 "DOX3134A" SOT-323-3_L2.1-W1.3-P1.30-LS2.3-BR#1 9521,7923.7 r0 top
Q6$CBB49/CBB28 "DOX3134A" SOT-323-3_L2.1-W1.3-P1.30-LS2.3-BR#1 9521,7138.7 r0 top
Q6$CBB49/CBB29 "DOX3134A" SOT-323-3_L2.1-W1.3-P1.30-LS2.3-BR#1 9521,6618.7 r0 top
Q6$CBB49/CBB30 "DOX3134A" SOT-323-3_L2.1-W1.3-P1.30-LS2.3-BR#1 9521,5833.7 r0 top
Q6$CBB49/CBB31 "DOX3134A" SOT-323-3_L2.1-W1.3-P1.30-LS2.3-BR#1 10029.7,9228.7 r0 top
Q6$CBB49/CBB32 "DOX3134A" SOT-323-3_L2.1-W1.3-P1.30-LS2.3-BR#1 10029.7,8708.7 r0 top
Q6$CBB49/CBB33 "DOX3134A" SOT-323-3_L2.1-W1.3-P1.30-LS2.3-BR#1 10029.7,7923.7 r0 top
Q6$CBB49/CBB34 "DOX3134A" SOT-323-3_L2.1-W1.3-P1.30-LS2.3-BR#1 10029.7,7138.7 r0 top
Q6$CBB49/CBB35 "DOX3134A" SOT-323-3_L2.1-W1.3-P1.30-LS2.3-BR#1 10029.7,6618.7 r0 top
Q6$CBB49/CBB36 "DOX3134A" SOT-323-3_L2.1-W1.3-P1.30-LS2.3-BR#1 10029.7,5833.7 r0 top
Q6$CBB49/CBB37 "DOX3134A" SOT-323-3_L2.1-W1.3-P1.30-LS2.3-BR#1 7486.2,6098.7 r0 top
Q6$CBB49/CBB38 "DOX3134A" SOT-323-3_L2.1-W1.3-P1.30-LS2.3-BR#1 7994.9,6098.7 r0 top
Q6$CBB49/CBB39 "DOX3134A" SOT-323-3_L2.1-W1.3-P1.30-LS2.3-BR#1 8503.6,6098.7 r0 top
Q6$CBB49/CBB40 "DOX3134A" SOT-323-3_L2.1-W1.3-P1.30-LS2.3-BR#1 9012.3,6098.7 r0 top
Q6$CBB49/CBB41 "DOX3134A" SOT-323-3_L2.1-W1.3-P1.30-LS2.3-BR#1 9521,6098.7 r0 top
Q6$CBB49/CBB42 "DOX3134A" SOT-323-3_L2.1-W1.3-P1.30-LS2.3-BR#1 10029.7,6098.7 r0 top
Q6$CBB49/CBB43 "DOX3134A" SOT-323-3_L2.1-W1.3-P1.30-LS2.3-BR#1 7486.2,7403.7 r0 top
Q6$CBB49/CBB44 "DOX3134A" SOT-323-3_L2.1-W1.3-P1.30-LS2.3-BR#1 7994.9,7403.7 r0 top
Q6$CBB49/CBB45 "DOX3134A" SOT-323-3_L2.1-W1.3-P1.30-LS2.3-BR#1 8503.6,7403.7 r0 top
Q6$CBB49/CBB46 "DOX3134A" SOT-323-3_L2.1-W1.3-P1.30-LS2.3-BR#1 9012.3,7403.7 r0 top
Q6$CBB49/CBB47 "DOX3134A" SOT-323-3_L2.1-W1.3-P1.30-LS2.3-BR#1 9521,7403.7 r0 top
Q6$CBB49/CBB48 "DOX3134A" SOT-323-3_L2.1-W1.3-P1.30-LS2.3-BR#1 10029.7,7403.7 r0 top
Q7$CBB15 "DOX3134A" SOT-323-3_L2.1-W1.3-P1.30-LS2.3-BR#1 9160.8,4101.7 r0 top
Q8$CBB9/CBB1 "DOX3134A" SOT-323-3_L2.1-W1.3-P1.30-LS2.3-BR#2 7611.2,9058.7 r180 top
Q8$CBB9/CBB2 "DOX3134A" SOT-323-3_L2.1-W1.3-P1.30-LS2.3-BR#2 7611.2,8538.7 r180 top
Q8$CBB9/CBB3 "DOX3134A" SOT-323-3_L2.1-W1.3-P1.30-LS2.3-BR#2 7611.2,7753.7 r180 top
Q8$CBB9/CBB4 "DOX3134A" SOT-323-3_L2.1-W1.3-P1.30-LS2.3-BR#2 7611.2,6968.7 r180 top
Q8$CBB9/CBB5 "DOX3134A" SOT-323-3_L2.1-W1.3-P1.30-LS2.3-BR#2 7611.2,6448.7 r180 top
Q8$CBB9/CBB6 "DOX3134A" SOT-323-3_L2.1-W1.3-P1.30-LS2.3-BR#2 7611.2,5663.7 r180 top
Q8$CBB9/CBB7 "DOX3134A" SOT-323-3_L2.1-W1.3-P1.30-LS2.3-BR#2 8119.9,9058.7 r180 top
Q8$CBB9/CBB8 "DOX3134A" SOT-323-3_L2.1-W1.3-P1.30-LS2.3-BR#2 8119.9,8538.7 r180 top
Q8$CBB9/CBB9 "DOX3134A" SOT-323-3_L2.1-W1.3-P1.30-LS2.3-BR#2 8119.9,7753.7 r180 top
Q8$CBB9/CBB10 "DOX3134A" SOT-323-3_L2.1-W1.3-P1.30-LS2.3-BR#2 8119.9,6968.7 r180 top
Q8$CBB9/CBB11 "DOX3134A" SOT-323-3_L2.1-W1.3-P1.30-LS2.3-BR#2 8119.9,6448.7 r180 top
Q8$CBB9/CBB12 "DOX3134A" SOT-323-3_L2.1-W1.3-P1.30-LS2.3-BR#2 8119.9,5663.7 r180 top
Q8$CBB9/CBB13 "DOX3134A" SOT-323-3_L2.1-W1.3-P1.30-LS2.3-BR#2 8628.6,9058.7 r180 top
Q8$CBB9/CBB14 "DOX3134A" SOT-323-3_L2.1-W1.3-P1.30-LS2.3-BR#2 8628.6,8538.7 r180 top
Q8$CBB9/CBB15 "DOX3134A" SOT-323-3_L2.1-W1.3-P1.30-LS2.3-BR#2 8628.6,7753.7 r180 top
Q8$CBB9/CBB16 "DOX3134A" SOT-323-3_L2.1-W1.3-P1.30-LS2.3-BR#2 8628.6,6968.7 r180 top
Q8$CBB9/CBB17 "DOX3134A" SOT-323-3_L2.1-W1.3-P1.30-LS2.3-BR#2 8628.6,6448.7 r180 top
Q8$CBB9/CBB18 "DOX3134A" SOT-323-3_L2.1-W1.3-P1.30-LS2.3-BR#2 8628.6,5663.7 r180 top
Q8$CBB9/CBB19 "DOX3134A" SOT-323-3_L2.1-W1.3-P1.30-LS2.3-BR#2 9137.3,9058.7 r180 top
Q8$CBB9/CBB20 "DOX3134A" SOT-323-3_L2.1-W1.3-P1.30-LS2.3-BR#2 9137.3,8538.7 r180 top
Q8$CBB9/CBB21 "DOX3134A" SOT-323-3_L2.1-W1.3-P1.30-LS2.3-BR#2 9137.3,7753.7 r180 top
Q8$CBB9/CBB22 "DOX3134A" SOT-323-3_L2.1-W1.3-P1.30-LS2.3-BR#2 9137.3,6968.7 r180 top
Q8$CBB9/CBB23 "DOX3134A" SOT-323-3_L2.1-W1.3-P1.30-LS2.3-BR#2 9137.3,6448.7 r180 top
Q8$CBB9/CBB24 "DOX3134A" SOT-323-3_L2.1-W1.3-P1.30-LS2.3-BR#2 9137.3,5663.7 r180 top
Q8$CBB9/CBB25 "DOX3134A" SOT-323-3_L2.1-W1.3-P1.30-LS2.3-BR#2 9646,9058.7 r180 top
Q8$CBB9/CBB26 "DOX3134A" SOT-323-3_L2.1-W1.3-P1.30-LS2.3-BR#2 9646,8538.7 r180 top
Q8$CBB9/CBB27 "DOX3134A" SOT-323-3_L2.1-W1.3-P1.30-LS2.3-BR#2 9646,7753.7 r180 top
Q8$CBB9/CBB28 "DOX3134A" SOT-323-3_L2.1-W1.3-P1.30-LS2.3-BR#2 9646,6968.7 r180 top
Q8$CBB9/CBB29 "DOX3134A" SOT-323-3_L2.1-W1.3-P1.30-LS2.3-BR#2 9646,6448.7 r180 top
Q8$CBB9/CBB30 "DOX3134A" SOT-323-3_L2.1-W1.3-P1.30-LS2.3-BR#2 9646,5663.7 r180 top
Q8$CBB9/CBB31 "DOX3134A" SOT-323-3_L2.1-W1.3-P1.30-LS2.3-BR#2 10154.7,9058.7 r180 top
Q8$CBB9/CBB32 "DOX3134A" SOT-323-3_L2.1-W1.3-P1.30-LS2.3-BR#2 10154.7,8538.7 r180 top
Q8$CBB9/CBB33 "DOX3134A" SOT-323-3_L2.1-W1.3-P1.30-LS2.3-BR#2 10154.7,7753.7 r180 top
Q8$CBB9/CBB34 "DOX3134A" SOT-323-3_L2.1-W1.3-P1.30-LS2.3-BR#2 10154.7,6968.7 r180 top
Q8$CBB9/CBB35 "DOX3134A" SOT-323-3_L2.1-W1.3-P1.30-LS2.3-BR#2 10154.7,6448.7 r180 top
Q8$CBB9/CBB36 "DOX3134A" SOT-323-3_L2.1-W1.3-P1.30-LS2.3-BR#2 10154.7,5663.7 r180 top
Q8$CBB9/CBB37 "DOX3134A" SOT-323-3_L2.1-W1.3-P1.30-LS2.3-BR#2 7611.2,8273.7 r180 top
Q8$CBB9/CBB38 "DOX3134A" SOT-323-3_L2.1-W1.3-P1.30-LS2.3-BR#2 8119.9,8273.7 r180 top
Q8$CBB9/CBB39 "DOX3134A" SOT-323-3_L2.1-W1.3-P1.30-LS2.3-BR#2 8628.6,8273.7 r180 top
Q8$CBB9/CBB40 "DOX3134A" SOT-323-3_L2.1-W1.3-P1.30-LS2.3-BR#2 9137.3,8273.7 r180 top
Q8$CBB9/CBB41 "DOX3134A" SOT-323-3_L2.1-W1.3-P1.30-LS2.3-BR#2 9646,8273.7 r180 top
Q8$CBB9/CBB42 "DOX3134A" SOT-323-3_L2.1-W1.3-P1.30-LS2.3-BR#2 10154.7,8273.7 r180 top
Q8$CBB15 "DOX3134A" SOT-323-3_L2.1-W1.3-P1.30-LS2.3-BR#1 9403.7,4101.7 r0 top
Q8$CBB19/CBB1 "DOX3134A" SOT-323-3_L2.1-W1.3-P1.30-LS2.3-BR#2 7866.2,9313.7 r180 top
Q8$CBB19/CBB2 "DOX3134A" SOT-323-3_L2.1-W1.3-P1.30-LS2.3-BR#1 7866.2,8793.7 r180 top
Q8$CBB19/CBB3 "DOX3134A" SOT-323-3_L2.1-W1.3-P1.30-LS2.3-BR#1 7866.2,8008.7 r180 top
Q8$CBB19/CBB4 "DOX3134A" SOT-323-3_L2.1-W1.3-P1.30-LS2.3-BR#1 7866.2,7223.7 r180 top
Q8$CBB19/CBB5 "DOX3134A" SOT-323-3_L2.1-W1.3-P1.30-LS2.3-BR#1 7866.2,6703.7 r180 top
Q8$CBB19/CBB6 "DOX3134A" SOT-323-3_L2.1-W1.3-P1.30-LS2.3-BR#1 7866.2,5918.7 r180 top
Q8$CBB19/CBB7 "DOX3134A" SOT-323-3_L2.1-W1.3-P1.30-LS2.3-BR#1 8374.9,9313.7 r180 top
Q8$CBB19/CBB8 "DOX3134A" SOT-323-3_L2.1-W1.3-P1.30-LS2.3-BR#1 8374.9,8793.7 r180 top
Q8$CBB19/CBB9 "DOX3134A" SOT-323-3_L2.1-W1.3-P1.30-LS2.3-BR#1 8374.9,8008.7 r180 top
Q8$CBB19/CBB10 "DOX3134A" SOT-323-3_L2.1-W1.3-P1.30-LS2.3-BR#1 8374.9,7223.7 r180 top
Q8$CBB19/CBB11 "DOX3134A" SOT-323-3_L2.1-W1.3-P1.30-LS2.3-BR#1 8374.9,6703.7 r180 top
Q8$CBB19/CBB12 "DOX3134A" SOT-323-3_L2.1-W1.3-P1.30-LS2.3-BR#1 8374.9,5918.7 r180 top
Q8$CBB19/CBB13 "DOX3134A" SOT-323-3_L2.1-W1.3-P1.30-LS2.3-BR#1 8883.6,9313.7 r180 top
Q8$CBB19/CBB14 "DOX3134A" SOT-323-3_L2.1-W1.3-P1.30-LS2.3-BR#1 8883.6,8793.7 r180 top
Q8$CBB19/CBB15 "DOX3134A" SOT-323-3_L2.1-W1.3-P1.30-LS2.3-BR#1 8883.6,8008.7 r180 top
Q8$CBB19/CBB16 "DOX3134A" SOT-323-3_L2.1-W1.3-P1.30-LS2.3-BR#1 8883.6,7223.7 r180 top
Q8$CBB19/CBB17 "DOX3134A" SOT-323-3_L2.1-W1.3-P1.30-LS2.3-BR#1 8883.6,6703.7 r180 top
Q8$CBB19/CBB18 "DOX3134A" SOT-323-3_L2.1-W1.3-P1.30-LS2.3-BR#1 8883.6,5918.7 r180 top
Q8$CBB19/CBB19 "DOX3134A" SOT-323-3_L2.1-W1.3-P1.30-LS2.3-BR#1 9392.3,9313.7 r180 top
Q8$CBB19/CBB20 "DOX3134A" SOT-323-3_L2.1-W1.3-P1.30-LS2.3-BR#1 9392.3,8793.7 r180 top
Q8$CBB19/CBB21 "DOX3134A" SOT-323-3_L2.1-W1.3-P1.30-LS2.3-BR#1 9392.3,8008.7 r180 top
Q8$CBB19/CBB22 "DOX3134A" SOT-323-3_L2.1-W1.3-P1.30-LS2.3-BR#1 9392.3,7223.7 r180 top
Q8$CBB19/CBB23 "DOX3134A" SOT-323-3_L2.1-W1.3-P1.30-LS2.3-BR#1 9392.3,6703.7 r180 top
Q8$CBB19/CBB24 "DOX3134A" SOT-323-3_L2.1-W1.3-P1.30-LS2.3-BR#1 9392.3,5918.7 r180 top
Q8$CBB19/CBB25 "DOX3134A" SOT-323-3_L2.1-W1.3-P1.30-LS2.3-BR#1 9901,9313.7 r180 top
Q8$CBB19/CBB26 "DOX3134A" SOT-323-3_L2.1-W1.3-P1.30-LS2.3-BR#1 9901,8793.7 r180 top
Q8$CBB19/CBB27 "DOX3134A" SOT-323-3_L2.1-W1.3-P1.30-LS2.3-BR#1 9901,8008.7 r180 top
Q8$CBB19/CBB28 "DOX3134A" SOT-323-3_L2.1-W1.3-P1.30-LS2.3-BR#1 9901,7223.7 r180 top
Q8$CBB19/CBB29 "DOX3134A" SOT-323-3_L2.1-W1.3-P1.30-LS2.3-BR#1 9901,6703.7 r180 top
Q8$CBB19/CBB30 "DOX3134A" SOT-323-3_L2.1-W1.3-P1.30-LS2.3-BR#1 9901,5918.7 r180 top
Q8$CBB19/CBB31 "DOX3134A" SOT-323-3_L2.1-W1.3-P1.30-LS2.3-BR#1 10409.7,9313.7 r180 top
Q8$CBB19/CBB32 "DOX3134A" SOT-323-3_L2.1-W1.3-P1.30-LS2.3-BR#1 10409.7,8793.7 r180 top
Q8$CBB19/CBB33 "DOX3134A" SOT-323-3_L2.1-W1.3-P1.30-LS2.3-BR#1 10409.7,8008.7 r180 top
Q8$CBB19/CBB34 "DOX3134A" SOT-323-3_L2.1-W1.3-P1.30-LS2.3-BR#1 10409.7,7223.7 r180 top
Q8$CBB19/CBB35 "DOX3134A" SOT-323-3_L2.1-W1.3-P1.30-LS2.3-BR#1 10409.7,6703.7 r180 top
Q8$CBB19/CBB36 "DOX3134A" SOT-323-3_L2.1-W1.3-P1.30-LS2.3-BR#1 10409.7,5918.7 r180 top
Q8$CBB49/CBB1 "DOX3134A" SOT-323-3_L2.1-W1.3-P1.30-LS2.3-BR#2 7611.2,9313.7 r180 top
Q8$CBB49/CBB2 "DOX3134A" SOT-323-3_L2.1-W1.3-P1.30-LS2.3-BR#2 7611.2,8793.7 r180 top
Q8$CBB49/CBB3 "DOX3134A" SOT-323-3_L2.1-W1.3-P1.30-LS2.3-BR#2 7611.2,8008.7 r180 top
Q8$CBB49/CBB4 "DOX3134A" SOT-323-3_L2.1-W1.3-P1.30-LS2.3-BR#2 7611.2,7223.7 r180 top
Q8$CBB49/CBB5 "DOX3134A" SOT-323-3_L2.1-W1.3-P1.30-LS2.3-BR#2 7611.2,6703.7 r180 top
Q8$CBB49/CBB6 "DOX3134A" SOT-323-3_L2.1-W1.3-P1.30-LS2.3-BR#2 7611.2,5918.7 r180 top
Q8$CBB49/CBB7 "DOX3134A" SOT-323-3_L2.1-W1.3-P1.30-LS2.3-BR#2 8119.9,9313.7 r180 top
Q8$CBB49/CBB8 "DOX3134A" SOT-323-3_L2.1-W1.3-P1.30-LS2.3-BR#2 8119.9,8793.7 r180 top
Q8$CBB49/CBB9 "DOX3134A" SOT-323-3_L2.1-W1.3-P1.30-LS2.3-BR#2 8119.9,8008.7 r180 top
Q8$CBB49/CBB10 "DOX3134A" SOT-323-3_L2.1-W1.3-P1.30-LS2.3-BR#2 8119.9,7223.7 r180 top
Q8$CBB49/CBB11 "DOX3134A" SOT-323-3_L2.1-W1.3-P1.30-LS2.3-BR#2 8119.9,6703.7 r180 top
Q8$CBB49/CBB12 "DOX3134A" SOT-323-3_L2.1-W1.3-P1.30-LS2.3-BR#2 8119.9,5918.7 r180 top
Q8$CBB49/CBB13 "DOX3134A" SOT-323-3_L2.1-W1.3-P1.30-LS2.3-BR#2 8628.6,9313.7 r180 top
Q8$CBB49/CBB14 "DOX3134A" SOT-323-3_L2.1-W1.3-P1.30-LS2.3-BR#2 8628.6,8793.7 r180 top
Q8$CBB49/CBB15 "DOX3134A" SOT-323-3_L2.1-W1.3-P1.30-LS2.3-BR#2 8628.6,8008.7 r180 top
Q8$CBB49/CBB16 "DOX3134A" SOT-323-3_L2.1-W1.3-P1.30-LS2.3-BR#2 8628.6,7223.7 r180 top
Q8$CBB49/CBB17 "DOX3134A" SOT-323-3_L2.1-W1.3-P1.30-LS2.3-BR#2 8628.6,6703.7 r180 top
Q8$CBB49/CBB18 "DOX3134A" SOT-323-3_L2.1-W1.3-P1.30-LS2.3-BR#2 8628.6,5918.7 r180 top
Q8$CBB49/CBB19 "DOX3134A" SOT-323-3_L2.1-W1.3-P1.30-LS2.3-BR#2 9137.3,9313.7 r180 top
Q8$CBB49/CBB20 "DOX3134A" SOT-323-3_L2.1-W1.3-P1.30-LS2.3-BR#2 9137.3,8793.7 r180 top
Q8$CBB49/CBB21 "DOX3134A" SOT-323-3_L2.1-W1.3-P1.30-LS2.3-BR#2 9137.3,8008.7 r180 top
Q8$CBB49/CBB22 "DOX3134A" SOT-323-3_L2.1-W1.3-P1.30-LS2.3-BR#2 9137.3,7223.7 r180 top
Q8$CBB49/CBB23 "DOX3134A" SOT-323-3_L2.1-W1.3-P1.30-LS2.3-BR#2 9137.3,6703.7 r180 top
Q8$CBB49/CBB24 "DOX3134A" SOT-323-3_L2.1-W1.3-P1.30-LS2.3-BR#2 9137.3,5918.7 r180 top
Q8$CBB49/CBB25 "DOX3134A" SOT-323-3_L2.1-W1.3-P1.30-LS2.3-BR#2 9646,9313.7 r180 top
Q8$CBB49/CBB26 "DOX3134A" SOT-323-3_L2.1-W1.3-P1.30-LS2.3-BR#2 9646,8793.7 r180 top
Q8$CBB49/CBB27 "DOX3134A" SOT-323-3_L2.1-W1.3-P1.30-LS2.3-BR#2 9646,8008.7 r180 top
Q8$CBB49/CBB28 "DOX3134A" SOT-323-3_L2.1-W1.3-P1.30-LS2.3-BR#2 9646,7223.7 r180 top
Q8$CBB49/CBB29 "DOX3134A" SOT-323-3_L2.1-W1.3-P1.30-LS2.3-BR#2 9646,6703.7 r180 top
Q8$CBB49/CBB30 "DOX3134A" SOT-323-3_L2.1-W1.3-P1.30-LS2.3-BR#2 9646,5918.7 r180 top
Q8$CBB49/CBB31 "DOX3134A" SOT-323-3_L2.1-W1.3-P1.30-LS2.3-BR#2 10154.7,9313.7 r180 top
Q8$CBB49/CBB32 "DOX3134A" SOT-323-3_L2.1-W1.3-P1.30-LS2.3-BR#2 10154.7,8793.7 r180 top
Q8$CBB49/CBB33 "DOX3134A" SOT-323-3_L2.1-W1.3-P1.30-LS2.3-BR#2 10154.7,8008.7 r180 top
Q8$CBB49/CBB34 "DOX3134A" SOT-323-3_L2.1-W1.3-P1.30-LS2.3-BR#2 10154.7,7223.7 r180 top
Q8$CBB49/CBB35 "DOX3134A" SOT-323-3_L2.1-W1.3-P1.30-LS2.3-BR#2 10154.7,6703.7 r180 top
Q8$CBB49/CBB36 "DOX3134A" SOT-323-3_L2.1-W1.3-P1.30-LS2.3-BR#2 10154.7,5918.7 r180 top
Q8$CBB49/CBB37 "DOX3134A" SOT-323-3_L2.1-W1.3-P1.30-LS2.3-BR#2 7611.2,6183.7 r180 top
Q8$CBB49/CBB38 "DOX3134A" SOT-323-3_L2.1-W1.3-P1.30-LS2.3-BR#2 8119.9,6183.7 r180 top
Q8$CBB49/CBB39 "DOX3134A" SOT-323-3_L2.1-W1.3-P1.30-LS2.3-BR#2 8628.6,6183.7 r180 top
Q8$CBB49/CBB40 "DOX3134A" SOT-323-3_L2.1-W1.3-P1.30-LS2.3-BR#2 9137.3,6183.7 r180 top
Q8$CBB49/CBB41 "DOX3134A" SOT-323-3_L2.1-W1.3-P1.30-LS2.3-BR#2 9646,6183.7 r180 top
Q8$CBB49/CBB42 "DOX3134A" SOT-323-3_L2.1-W1.3-P1.30-LS2.3-BR#2 10154.7,6183.7 r180 top
Q8$CBB49/CBB43 "DOX3134A" SOT-323-3_L2.1-W1.3-P1.30-LS2.3-BR#2 7611.2,7488.7 r180 top
Q8$CBB49/CBB44 "DOX3134A" SOT-323-3_L2.1-W1.3-P1.30-LS2.3-BR#2 8119.9,7488.7 r180 top
Q8$CBB49/CBB45 "DOX3134A" SOT-323-3_L2.1-W1.3-P1.30-LS2.3-BR#2 8628.6,7488.7 r180 top
Q8$CBB49/CBB46 "DOX3134A" SOT-323-3_L2.1-W1.3-P1.30-LS2.3-BR#2 9137.3,7488.7 r180 top
Q8$CBB49/CBB47 "DOX3134A" SOT-323-3_L2.1-W1.3-P1.30-LS2.3-BR#2 9646,7488.7 r180 top
Q8$CBB49/CBB48 "DOX3134A" SOT-323-3_L2.1-W1.3-P1.30-LS2.3-BR#2 10154.7,7488.7 r180 top
Q9$CBB9/CBB1 "DOX3134A" SOT-323-3_L2.1-W1.3-P1.30-LS2.3-BR#1 7486.2,9058.7 r0 top
Q9$CBB9/CBB2 "DOX3134A" SOT-323-3_L2.1-W1.3-P1.30-LS2.3-BR#1 7486.2,8538.7 r0 top
Q9$CBB9/CBB3 "DOX3134A" SOT-323-3_L2.1-W1.3-P1.30-LS2.3-BR#1 7486.2,7753.7 r0 top
Q9$CBB9/CBB4 "DOX3134A" SOT-323-3_L2.1-W1.3-P1.30-LS2.3-BR#1 7486.2,6968.7 r0 top
Q9$CBB9/CBB5 "DOX3134A" SOT-323-3_L2.1-W1.3-P1.30-LS2.3-BR#1 7486.2,6448.7 r0 top
Q9$CBB9/CBB6 "DOX3134A" SOT-323-3_L2.1-W1.3-P1.30-LS2.3-BR#1 7486.2,5663.7 r0 top
Q9$CBB9/CBB7 "DOX3134A" SOT-323-3_L2.1-W1.3-P1.30-LS2.3-BR#1 7994.9,9058.7 r0 top
Q9$CBB9/CBB8 "DOX3134A" SOT-323-3_L2.1-W1.3-P1.30-LS2.3-BR#1 7994.9,8538.7 r0 top
Q9$CBB9/CBB9 "DOX3134A" SOT-323-3_L2.1-W1.3-P1.30-LS2.3-BR#1 7994.9,7753.7 r0 top
Q9$CBB9/CBB10 "DOX3134A" SOT-323-3_L2.1-W1.3-P1.30-LS2.3-BR#1 7994.9,6968.7 r0 top
Q9$CBB9/CBB11 "DOX3134A" SOT-323-3_L2.1-W1.3-P1.30-LS2.3-BR#1 7994.9,6448.7 r0 top
Q9$CBB9/CBB12 "DOX3134A" SOT-323-3_L2.1-W1.3-P1.30-LS2.3-BR#1 7994.9,5663.7 r0 top
Q9$CBB9/CBB13 "DOX3134A" SOT-323-3_L2.1-W1.3-P1.30-LS2.3-BR#1 8503.6,9058.7 r0 top
Q9$CBB9/CBB14 "DOX3134A" SOT-323-3_L2.1-W1.3-P1.30-LS2.3-BR#1 8503.6,8538.7 r0 top
Q9$CBB9/CBB15 "DOX3134A" SOT-323-3_L2.1-W1.3-P1.30-LS2.3-BR#1 8503.6,7753.7 r0 top
Q9$CBB9/CBB16 "DOX3134A" SOT-323-3_L2.1-W1.3-P1.30-LS2.3-BR#1 8503.6,6968.7 r0 top
Q9$CBB9/CBB17 "DOX3134A" SOT-323-3_L2.1-W1.3-P1.30-LS2.3-BR#1 8503.6,6448.7 r0 top
Q9$CBB9/CBB18 "DOX3134A" SOT-323-3_L2.1-W1.3-P1.30-LS2.3-BR#1 8503.6,5663.7 r0 top
Q9$CBB9/CBB19 "DOX3134A" SOT-323-3_L2.1-W1.3-P1.30-LS2.3-BR#1 9012.3,9058.7 r0 top
Q9$CBB9/CBB20 "DOX3134A" SOT-323-3_L2.1-W1.3-P1.30-LS2.3-BR#1 9012.3,8538.7 r0 top
Q9$CBB9/CBB21 "DOX3134A" SOT-323-3_L2.1-W1.3-P1.30-LS2.3-BR#1 9012.3,7753.7 r0 top
Q9$CBB9/CBB22 "DOX3134A" SOT-323-3_L2.1-W1.3-P1.30-LS2.3-BR#1 9012.3,6968.7 r0 top
Q9$CBB9/CBB23 "DOX3134A" SOT-323-3_L2.1-W1.3-P1.30-LS2.3-BR#1 9012.3,6448.7 r0 top
Q9$CBB9/CBB24 "DOX3134A" SOT-323-3_L2.1-W1.3-P1.30-LS2.3-BR#1 9012.3,5663.7 r0 top
Q9$CBB9/CBB25 "DOX3134A" SOT-323-3_L2.1-W1.3-P1.30-LS2.3-BR#1 9521,9058.7 r0 top
Q9$CBB9/CBB26 "DOX3134A" SOT-323-3_L2.1-W1.3-P1.30-LS2.3-BR#1 9521,8538.7 r0 top
Q9$CBB9/CBB27 "DOX3134A" SOT-323-3_L2.1-W1.3-P1.30-LS2.3-BR#1 9521,7753.7 r0 top
Q9$CBB9/CBB28 "DOX3134A" SOT-323-3_L2.1-W1.3-P1.30-LS2.3-BR#1 9521,6968.7 r0 top
Q9$CBB9/CBB29 "DOX3134A" SOT-323-3_L2.1-W1.3-P1.30-LS2.3-BR#1 9521,6448.7 r0 top
Q9$CBB9/CBB30 "DOX3134A" SOT-323-3_L2.1-W1.3-P1.30-LS2.3-BR#1 9521,5663.7 r0 top
Q9$CBB9/CBB31 "DOX3134A" SOT-323-3_L2.1-W1.3-P1.30-LS2.3-BR#1 10029.7,9058.7 r0 top
Q9$CBB9/CBB32 "DOX3134A" SOT-323-3_L2.1-W1.3-P1.30-LS2.3-BR#1 10029.7,8538.7 r0 top
Q9$CBB9/CBB33 "DOX3134A" SOT-323-3_L2.1-W1.3-P1.30-LS2.3-BR#1 10029.7,7753.7 r0 top
Q9$CBB9/CBB34 "DOX3134A" SOT-323-3_L2.1-W1.3-P1.30-LS2.3-BR#1 10029.7,6968.7 r0 top
Q9$CBB9/CBB35 "DOX3134A" SOT-323-3_L2.1-W1.3-P1.30-LS2.3-BR#1 10029.7,6448.7 r0 top
Q9$CBB9/CBB36 "DOX3134A" SOT-323-3_L2.1-W1.3-P1.30-LS2.3-BR#1 10029.7,5663.7 r0 top
Q9$CBB9/CBB37 "DOX3134A" SOT-323-3_L2.1-W1.3-P1.30-LS2.3-BR#1 7486.2,8273.7 r0 top
Q9$CBB9/CBB38 "DOX3134A" SOT-323-3_L2.1-W1.3-P1.30-LS2.3-BR#1 7994.9,8273.7 r0 top
Q9$CBB9/CBB39 "DOX3134A" SOT-323-3_L2.1-W1.3-P1.30-LS2.3-BR#1 8503.6,8273.7 r0 top
Q9$CBB9/CBB40 "DOX3134A" SOT-323-3_L2.1-W1.3-P1.30-LS2.3-BR#1 9012.3,8273.7 r0 top
Q9$CBB9/CBB41 "DOX3134A" SOT-323-3_L2.1-W1.3-P1.30-LS2.3-BR#1 9521,8273.7 r0 top
Q9$CBB9/CBB42 "DOX3134A" SOT-323-3_L2.1-W1.3-P1.30-LS2.3-BR#1 10029.7,8273.7 r0 top
Q9$CBB15 "DOX3134A" SOT-323-3_L2.1-W1.3-P1.30-LS2.3-BR#1 9282.2,4101.7 r0 top
Q9$CBB19/CBB1 "DOX3134A" SOT-323-3_L2.1-W1.3-P1.30-LS2.3-BR#1 7741.2,9313.7 r0 top
Q9$CBB19/CBB2 "DOX3134A" SOT-323-3_L2.1-W1.3-P1.30-LS2.3-BR#1 7741.2,8793.7 r0 top
Q9$CBB19/CBB3 "DOX3134A" SOT-323-3_L2.1-W1.3-P1.30-LS2.3-BR#1 7741.2,8008.7 r0 top
Q9$CBB19/CBB4 "DOX3134A" SOT-323-3_L2.1-W1.3-P1.30-LS2.3-BR#1 7741.2,7223.7 r0 top
Q9$CBB19/CBB5 "DOX3134A" SOT-323-3_L2.1-W1.3-P1.30-LS2.3-BR#1 7741.2,6703.7 r0 top
Q9$CBB19/CBB6 "DOX3134A" SOT-323-3_L2.1-W1.3-P1.30-LS2.3-BR#1 7741.2,5918.7 r0 top
Q9$CBB19/CBB7 "DOX3134A" SOT-323-3_L2.1-W1.3-P1.30-LS2.3-BR#1 8249.9,9313.7 r0 top
Q9$CBB19/CBB8 "DOX3134A" SOT-323-3_L2.1-W1.3-P1.30-LS2.3-BR#1 8249.9,8793.7 r0 top
Q9$CBB19/CBB9 "DOX3134A" SOT-323-3_L2.1-W1.3-P1.30-LS2.3-BR#1 8249.9,8008.7 r0 top
Q9$CBB19/CBB10 "DOX3134A" SOT-323-3_L2.1-W1.3-P1.30-LS2.3-BR#1 8249.9,7223.7 r0 top
Q9$CBB19/CBB11 "DOX3134A" SOT-323-3_L2.1-W1.3-P1.30-LS2.3-BR#1 8249.9,6703.7 r0 top
Q9$CBB19/CBB12 "DOX3134A" SOT-323-3_L2.1-W1.3-P1.30-LS2.3-BR#1 8249.9,5918.7 r0 top
Q9$CBB19/CBB13 "DOX3134A" SOT-323-3_L2.1-W1.3-P1.30-LS2.3-BR#1 8758.6,9313.7 r0 top
Q9$CBB19/CBB14 "DOX3134A" SOT-323-3_L2.1-W1.3-P1.30-LS2.3-BR#1 8758.6,8793.7 r0 top
Q9$CBB19/CBB15 "DOX3134A" SOT-323-3_L2.1-W1.3-P1.30-LS2.3-BR#1 8758.6,8008.7 r0 top
Q9$CBB19/CBB16 "DOX3134A" SOT-323-3_L2.1-W1.3-P1.30-LS2.3-BR#1 8758.6,7223.7 r0 top
Q9$CBB19/CBB17 "DOX3134A" SOT-323-3_L2.1-W1.3-P1.30-LS2.3-BR#1 8758.6,6703.7 r0 top
Q9$CBB19/CBB18 "DOX3134A" SOT-323-3_L2.1-W1.3-P1.30-LS2.3-BR#1 8758.6,5918.7 r0 top
Q9$CBB19/CBB19 "DOX3134A" SOT-323-3_L2.1-W1.3-P1.30-LS2.3-BR#1 9267.3,9313.7 r0 top
Q9$CBB19/CBB20 "DOX3134A" SOT-323-3_L2.1-W1.3-P1.30-LS2.3-BR#1 9267.3,8793.7 r0 top
Q9$CBB19/CBB21 "DOX3134A" SOT-323-3_L2.1-W1.3-P1.30-LS2.3-BR#1 9267.3,8008.7 r0 top
Q9$CBB19/CBB22 "DOX3134A" SOT-323-3_L2.1-W1.3-P1.30-LS2.3-BR#1 9267.3,7223.7 r0 top
Q9$CBB19/CBB23 "DOX3134A" SOT-323-3_L2.1-W1.3-P1.30-LS2.3-BR#1 9267.3,6703.7 r0 top
Q9$CBB19/CBB24 "DOX3134A" SOT-323-3_L2.1-W1.3-P1.30-LS2.3-BR#1 9267.3,5918.7 r0 top
Q9$CBB19/CBB25 "DOX3134A" SOT-323-3_L2.1-W1.3-P1.30-LS2.3-BR#1 9776,9313.7 r0 top
Q9$CBB19/CBB26 "DOX3134A" SOT-323-3_L2.1-W1.3-P1.30-LS2.3-BR#1 9776,8793.7 r0 top
Q9$CBB19/CBB27 "DOX3134A" SOT-323-3_L2.1-W1.3-P1.30-LS2.3-BR#1 9776,8008.7 r0 top
Q9$CBB19/CBB28 "DOX3134A" SOT-323-3_L2.1-W1.3-P1.30-LS2.3-BR#1 9776,7223.7 r0 top
Q9$CBB19/CBB29 "DOX3134A" SOT-323-3_L2.1-W1.3-P1.30-LS2.3-BR#1 9776,6703.7 r0 top
Q9$CBB19/CBB30 "DOX3134A" SOT-323-3_L2.1-W1.3-P1.30-LS2.3-BR#1 9776,5918.7 r0 top
Q9$CBB19/CBB31 "DOX3134A" SOT-323-3_L2.1-W1.3-P1.30-LS2.3-BR#1 10284.7,9313.7 r0 top
Q9$CBB19/CBB32 "DOX3134A" SOT-323-3_L2.1-W1.3-P1.30-LS2.3-BR#1 10284.7,8793.7 r0 top
Q9$CBB19/CBB33 "DOX3134A" SOT-323-3_L2.1-W1.3-P1.30-LS2.3-BR#1 10284.7,8008.7 r0 top
Q9$CBB19/CBB34 "DOX3134A" SOT-323-3_L2.1-W1.3-P1.30-LS2.3-BR#1 10284.7,7223.7 r0 top
Q9$CBB19/CBB35 "DOX3134A" SOT-323-3_L2.1-W1.3-P1.30-LS2.3-BR#1 10284.7,6703.7 r0 top
Q9$CBB19/CBB36 "DOX3134A" SOT-323-3_L2.1-W1.3-P1.30-LS2.3-BR#1 10284.7,5918.7 r0 top
Q9$CBB49/CBB1 "DOX3134A" SOT-323-3_L2.1-W1.3-P1.30-LS2.3-BR#1 7486.2,9313.7 r0 top
Q9$CBB49/CBB2 "DOX3134A" SOT-323-3_L2.1-W1.3-P1.30-LS2.3-BR#1 7486.2,8793.7 r0 top
Q9$CBB49/CBB3 "DOX3134A" SOT-323-3_L2.1-W1.3-P1.30-LS2.3-BR#1 7486.2,8008.7 r0 top
Q9$CBB49/CBB4 "DOX3134A" SOT-323-3_L2.1-W1.3-P1.30-LS2.3-BR#1 7486.2,7223.7 r0 top
Q9$CBB49/CBB5 "DOX3134A" SOT-323-3_L2.1-W1.3-P1.30-LS2.3-BR#1 7486.2,6703.7 r0 top
Q9$CBB49/CBB6 "DOX3134A" SOT-323-3_L2.1-W1.3-P1.30-LS2.3-BR#1 7486.2,5918.7 r0 top
Q9$CBB49/CBB7 "DOX3134A" SOT-323-3_L2.1-W1.3-P1.30-LS2.3-BR#1 7994.9,9313.7 r0 top
Q9$CBB49/CBB8 "DOX3134A" SOT-323-3_L2.1-W1.3-P1.30-LS2.3-BR#1 7994.9,8793.7 r0 top
Q9$CBB49/CBB9 "DOX3134A" SOT-323-3_L2.1-W1.3-P1.30-LS2.3-BR#1 7994.9,8008.7 r0 top
Q9$CBB49/CBB10 "DOX3134A" SOT-323-3_L2.1-W1.3-P1.30-LS2.3-BR#1 7994.9,7223.7 r0 top
Q9$CBB49/CBB11 "DOX3134A" SOT-323-3_L2.1-W1.3-P1.30-LS2.3-BR#1 7994.9,6703.7 r0 top
Q9$CBB49/CBB12 "DOX3134A" SOT-323-3_L2.1-W1.3-P1.30-LS2.3-BR#1 7994.9,5918.7 r0 top
Q9$CBB49/CBB13 "DOX3134A" SOT-323-3_L2.1-W1.3-P1.30-LS2.3-BR#1 8503.6,9313.7 r0 top
Q9$CBB49/CBB14 "DOX3134A" SOT-323-3_L2.1-W1.3-P1.30-LS2.3-BR#1 8503.6,8793.7 r0 top
Q9$CBB49/CBB15 "DOX3134A" SOT-323-3_L2.1-W1.3-P1.30-LS2.3-BR#1 8503.6,8008.7 r0 top
Q9$CBB49/CBB16 "DOX3134A" SOT-323-3_L2.1-W1.3-P1.30-LS2.3-BR#1 8503.6,7223.7 r0 top
Q9$CBB49/CBB17 "DOX3134A" SOT-323-3_L2.1-W1.3-P1.30-LS2.3-BR#1 8503.6,6703.7 r0 top
Q9$CBB49/CBB18 "DOX3134A" SOT-323-3_L2.1-W1.3-P1.30-LS2.3-BR#1 8503.6,5918.7 r0 top
Q9$CBB49/CBB19 "DOX3134A" SOT-323-3_L2.1-W1.3-P1.30-LS2.3-BR#1 9012.3,9313.7 r0 top
Q9$CBB49/CBB20 "DOX3134A" SOT-323-3_L2.1-W1.3-P1.30-LS2.3-BR#1 9012.3,8793.7 r0 top
Q9$CBB49/CBB21 "DOX3134A" SOT-323-3_L2.1-W1.3-P1.30-LS2.3-BR#1 9012.3,8008.7 r0 top
Q9$CBB49/CBB22 "DOX3134A" SOT-323-3_L2.1-W1.3-P1.30-LS2.3-BR#1 9012.3,7223.7 r0 top
Q9$CBB49/CBB23 "DOX3134A" SOT-323-3_L2.1-W1.3-P1.30-LS2.3-BR#1 9012.3,6703.7 r0 top
Q9$CBB49/CBB24 "DOX3134A" SOT-323-3_L2.1-W1.3-P1.30-LS2.3-BR#1 9012.3,5918.7 r0 top
Q9$CBB49/CBB25 "DOX3134A" SOT-323-3_L2.1-W1.3-P1.30-LS2.3-BR#1 9521,9313.7 r0 top
Q9$CBB49/CBB26 "DOX3134A" SOT-323-3_L2.1-W1.3-P1.30-LS2.3-BR#1 9521,8793.7 r0 top
Q9$CBB49/CBB27 "DOX3134A" SOT-323-3_L2.1-W1.3-P1.30-LS2.3-BR#1 9521,8008.7 r0 top
Q9$CBB49/CBB28 "DOX3134A" SOT-323-3_L2.1-W1.3-P1.30-LS2.3-BR#1 9521,7223.7 r0 top
Q9$CBB49/CBB29 "DOX3134A" SOT-323-3_L2.1-W1.3-P1.30-LS2.3-BR#1 9521,6703.7 r0 top
Q9$CBB49/CBB30 "DOX3134A" SOT-323-3_L2.1-W1.3-P1.30-LS2.3-BR#1 9521,5918.7 r0 top
Q9$CBB49/CBB31 "DOX3134A" SOT-323-3_L2.1-W1.3-P1.30-LS2.3-BR#1 10029.7,9313.7 r0 top
Q9$CBB49/CBB32 "DOX3134A" SOT-323-3_L2.1-W1.3-P1.30-LS2.3-BR#1 10029.7,8793.7 r0 top
Q9$CBB49/CBB33 "DOX3134A" SOT-323-3_L2.1-W1.3-P1.30-LS2.3-BR#1 10029.7,8008.7 r0 top
Q9$CBB49/CBB34 "DOX3134A" SOT-323-3_L2.1-W1.3-P1.30-LS2.3-BR#1 10029.7,7223.7 r0 top
Q9$CBB49/CBB35 "DOX3134A" SOT-323-3_L2.1-W1.3-P1.30-LS2.3-BR#1 10029.7,6703.7 r0 top
Q9$CBB49/CBB36 "DOX3134A" SOT-323-3_L2.1-W1.3-P1.30-LS2.3-BR#1 10029.7,5918.7 r0 top
Q9$CBB49/CBB37 "DOX3134A" SOT-323-3_L2.1-W1.3-P1.30-LS2.3-BR#1 7486.2,6183.7 r0 top
Q9$CBB49/CBB38 "DOX3134A" SOT-323-3_L2.1-W1.3-P1.30-LS2.3-BR#1 7994.9,6183.7 r0 top
Q9$CBB49/CBB39 "DOX3134A" SOT-323-3_L2.1-W1.3-P1.30-LS2.3-BR#1 8503.6,6183.7 r0 top
Q9$CBB49/CBB40 "DOX3134A" SOT-323-3_L2.1-W1.3-P1.30-LS2.3-BR#1 9012.3,6183.7 r0 top
Q9$CBB49/CBB41 "DOX3134A" SOT-323-3_L2.1-W1.3-P1.30-LS2.3-BR#1 9521,6183.7 r0 top
Q9$CBB49/CBB42 "DOX3134A" SOT-323-3_L2.1-W1.3-P1.30-LS2.3-BR#1 10029.7,6183.7 r0 top
Q9$CBB49/CBB43 "DOX3134A" SOT-323-3_L2.1-W1.3-P1.30-LS2.3-BR#1 7486.2,7488.7 r0 top
Q9$CBB49/CBB44 "DOX3134A" SOT-323-3_L2.1-W1.3-P1.30-LS2.3-BR#1 7994.9,7488.7 r0 top
Q9$CBB49/CBB45 "DOX3134A" SOT-323-3_L2.1-W1.3-P1.30-LS2.3-BR#1 8503.6,7488.7 r0 top
Q9$CBB49/CBB46 "DOX3134A" SOT-323-3_L2.1-W1.3-P1.30-LS2.3-BR#1 9012.3,7488.7 r0 top
Q9$CBB49/CBB47 "DOX3134A" SOT-323-3_L2.1-W1.3-P1.30-LS2.3-BR#1 9521,7488.7 r0 top
Q9$CBB49/CBB48 "DOX3134A" SOT-323-3_L2.1-W1.3-P1.30-LS2.3-BR#1 10029.7,7488.7 r0 top
Q10$CBB15 "DOX3134A" SOT-323-3_L2.1-W1.3-P1.30-LS2.3-BR#1 9646.6,4101.7 r0 top
Q11$CBB15 "DOX3134A" SOT-323-3_L2.1-W1.3-P1.30-LS2.3-BR#1 9039.3,4101.7 r0 top
Q12$CBB15 "DOX3134A" SOT-323-3_L2.1-W1.3-P1.30-LS2.3-BR#1 9525.2,4101.7 r0 top
R1 "20kΩ" R0402#1 4783.8,6495.7 r180 bottom
R1$CBB1 "300Ω" R0402#1 7827.1,4872.2 r90 top
R1$CBB2 "300Ω" R0402#1 8335.8,4872.2 r90 top
R1$CBB3 "300Ω" R0402#1 8844.5,4872.2 r90 top
R1$CBB4 "300Ω" R0402#1 9353.2,4872.2 r90 top
R1$CBB5 "300Ω" R0402#1 9861.9,4872.2 r90 top
R1$CBB6 "300Ω" R0402#1 10370.6,4872.2 r90 top
R1$CBB7 "100Ω" R0402#2 6972.1,4723.7 r90 top
R1$CBB9/CBB1 "1MΩ" R0402#2 7506.2,8868.7 r180 top
R1$CBB9/CBB2 "1MΩ" R0402#2 7506.2,8348.7 r180 top
R1$CBB9/CBB3 "1MΩ" R0402#2 7506.2,7563.7 r180 top
R1$CBB9/CBB4 "1MΩ" R0402#2 7506.2,6778.7 r180 top
R1$CBB9/CBB5 "1MΩ" R0402#2 7506.2,6258.7 r180 top
R1$CBB9/CBB6 "1MΩ" R0402#2 7506.2,5473.7 r180 top
R1$CBB9/CBB7 "1MΩ" R0402#2 8014.9,8868.7 r180 top
R1$CBB9/CBB8 "1MΩ" R0402#2 8014.9,8348.7 r180 top
R1$CBB9/CBB9 "1MΩ" R0402#2 8014.9,7563.7 r180 top
R1$CBB9/CBB10 "1MΩ" R0402#2 8014.9,6778.7 r180 top
R1$CBB9/CBB11 "1MΩ" R0402#2 8014.9,6258.7 r180 top
R1$CBB9/CBB12 "1MΩ" R0402#2 8014.9,5473.7 r180 top
R1$CBB9/CBB13 "1MΩ" R0402#2 8523.6,8868.7 r180 top
R1$CBB9/CBB14 "1MΩ" R0402#2 8523.6,8348.7 r180 top
R1$CBB9/CBB15 "1MΩ" R0402#2 8523.6,7563.7 r180 top
R1$CBB9/CBB16 "1MΩ" R0402#2 8523.6,6778.7 r180 top
R1$CBB9/CBB17 "1MΩ" R0402#2 8523.6,6258.7 r180 top
R1$CBB9/CBB18 "1MΩ" R0402#2 8523.6,5473.7 r180 top
R1$CBB9/CBB19 "1MΩ" R0402#2 9032.3,8868.7 r180 top
R1$CBB9/CBB20 "1MΩ" R0402#2 9032.3,8348.7 r180 top
R1$CBB9/CBB21 "1MΩ" R0402#2 9032.3,7563.7 r180 top
R1$CBB9/CBB22 "1MΩ" R0402#2 9032.3,6778.7 r180 top
R1$CBB9/CBB23 "1MΩ" R0402#2 9032.3,6258.7 r180 top
R1$CBB9/CBB24 "1MΩ" R0402#2 9032.3,5473.7 r180 top
R1$CBB9/CBB25 "1MΩ" R0402#2 9541,8868.7 r180 top
R1$CBB9/CBB26 "1MΩ" R0402#2 9541,8348.7 r180 top
R1$CBB9/CBB27 "1MΩ" R0402#2 9541,7563.7 r180 top
R1$CBB9/CBB28 "1MΩ" R0402#2 9541,6778.7 r180 top
R1$CBB9/CBB29 "1MΩ" R0402#2 9541,6258.7 r180 top
R1$CBB9/CBB30 "1MΩ" R0402#2 9541,5473.7 r180 top
R1$CBB9/CBB31 "1MΩ" R0402#2 10049.7,8868.7 r180 top
R1$CBB9/CBB32 "1MΩ" R0402#2 10049.7,8348.7 r180 top
R1$CBB9/CBB33 "1MΩ" R0402#2 10049.7,7563.7 r180 top
R1$CBB9/CBB34 "1MΩ" R0402#2 10049.7,6778.7 r180 top
R1$CBB9/CBB35 "1MΩ" R0402#2 10049.7,6258.7 r180 top
R1$CBB9/CBB36 "1MΩ" R0402#2 10049.7,5473.7 r180 top
R1$CBB9/CBB37 "1MΩ" R0402#2 7506.2,8083.7 r180 top
R1$CBB9/CBB38 "1MΩ" R0402#2 8014.9,8083.7 r180 top
R1$CBB9/CBB39 "1MΩ" R0402#2 8523.6,8083.7 r180 top
R1$CBB9/CBB40 "1MΩ" R0402#2 9032.3,8083.7 r180 top
R1$CBB9/CBB41 "1MΩ" R0402#2 9541,8083.7 r180 top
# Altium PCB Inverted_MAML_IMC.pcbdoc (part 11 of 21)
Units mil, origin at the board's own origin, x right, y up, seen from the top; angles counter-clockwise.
Board outline 7677.1 x 6771.6 mil, 6 copper layers (Top Layer, Inner1, Inner2, Inner3, Inner4, Bottom Layer), stack 60.7 mil thick; 2732 components, 1531 nets, 7765 pads, 3699 vias.

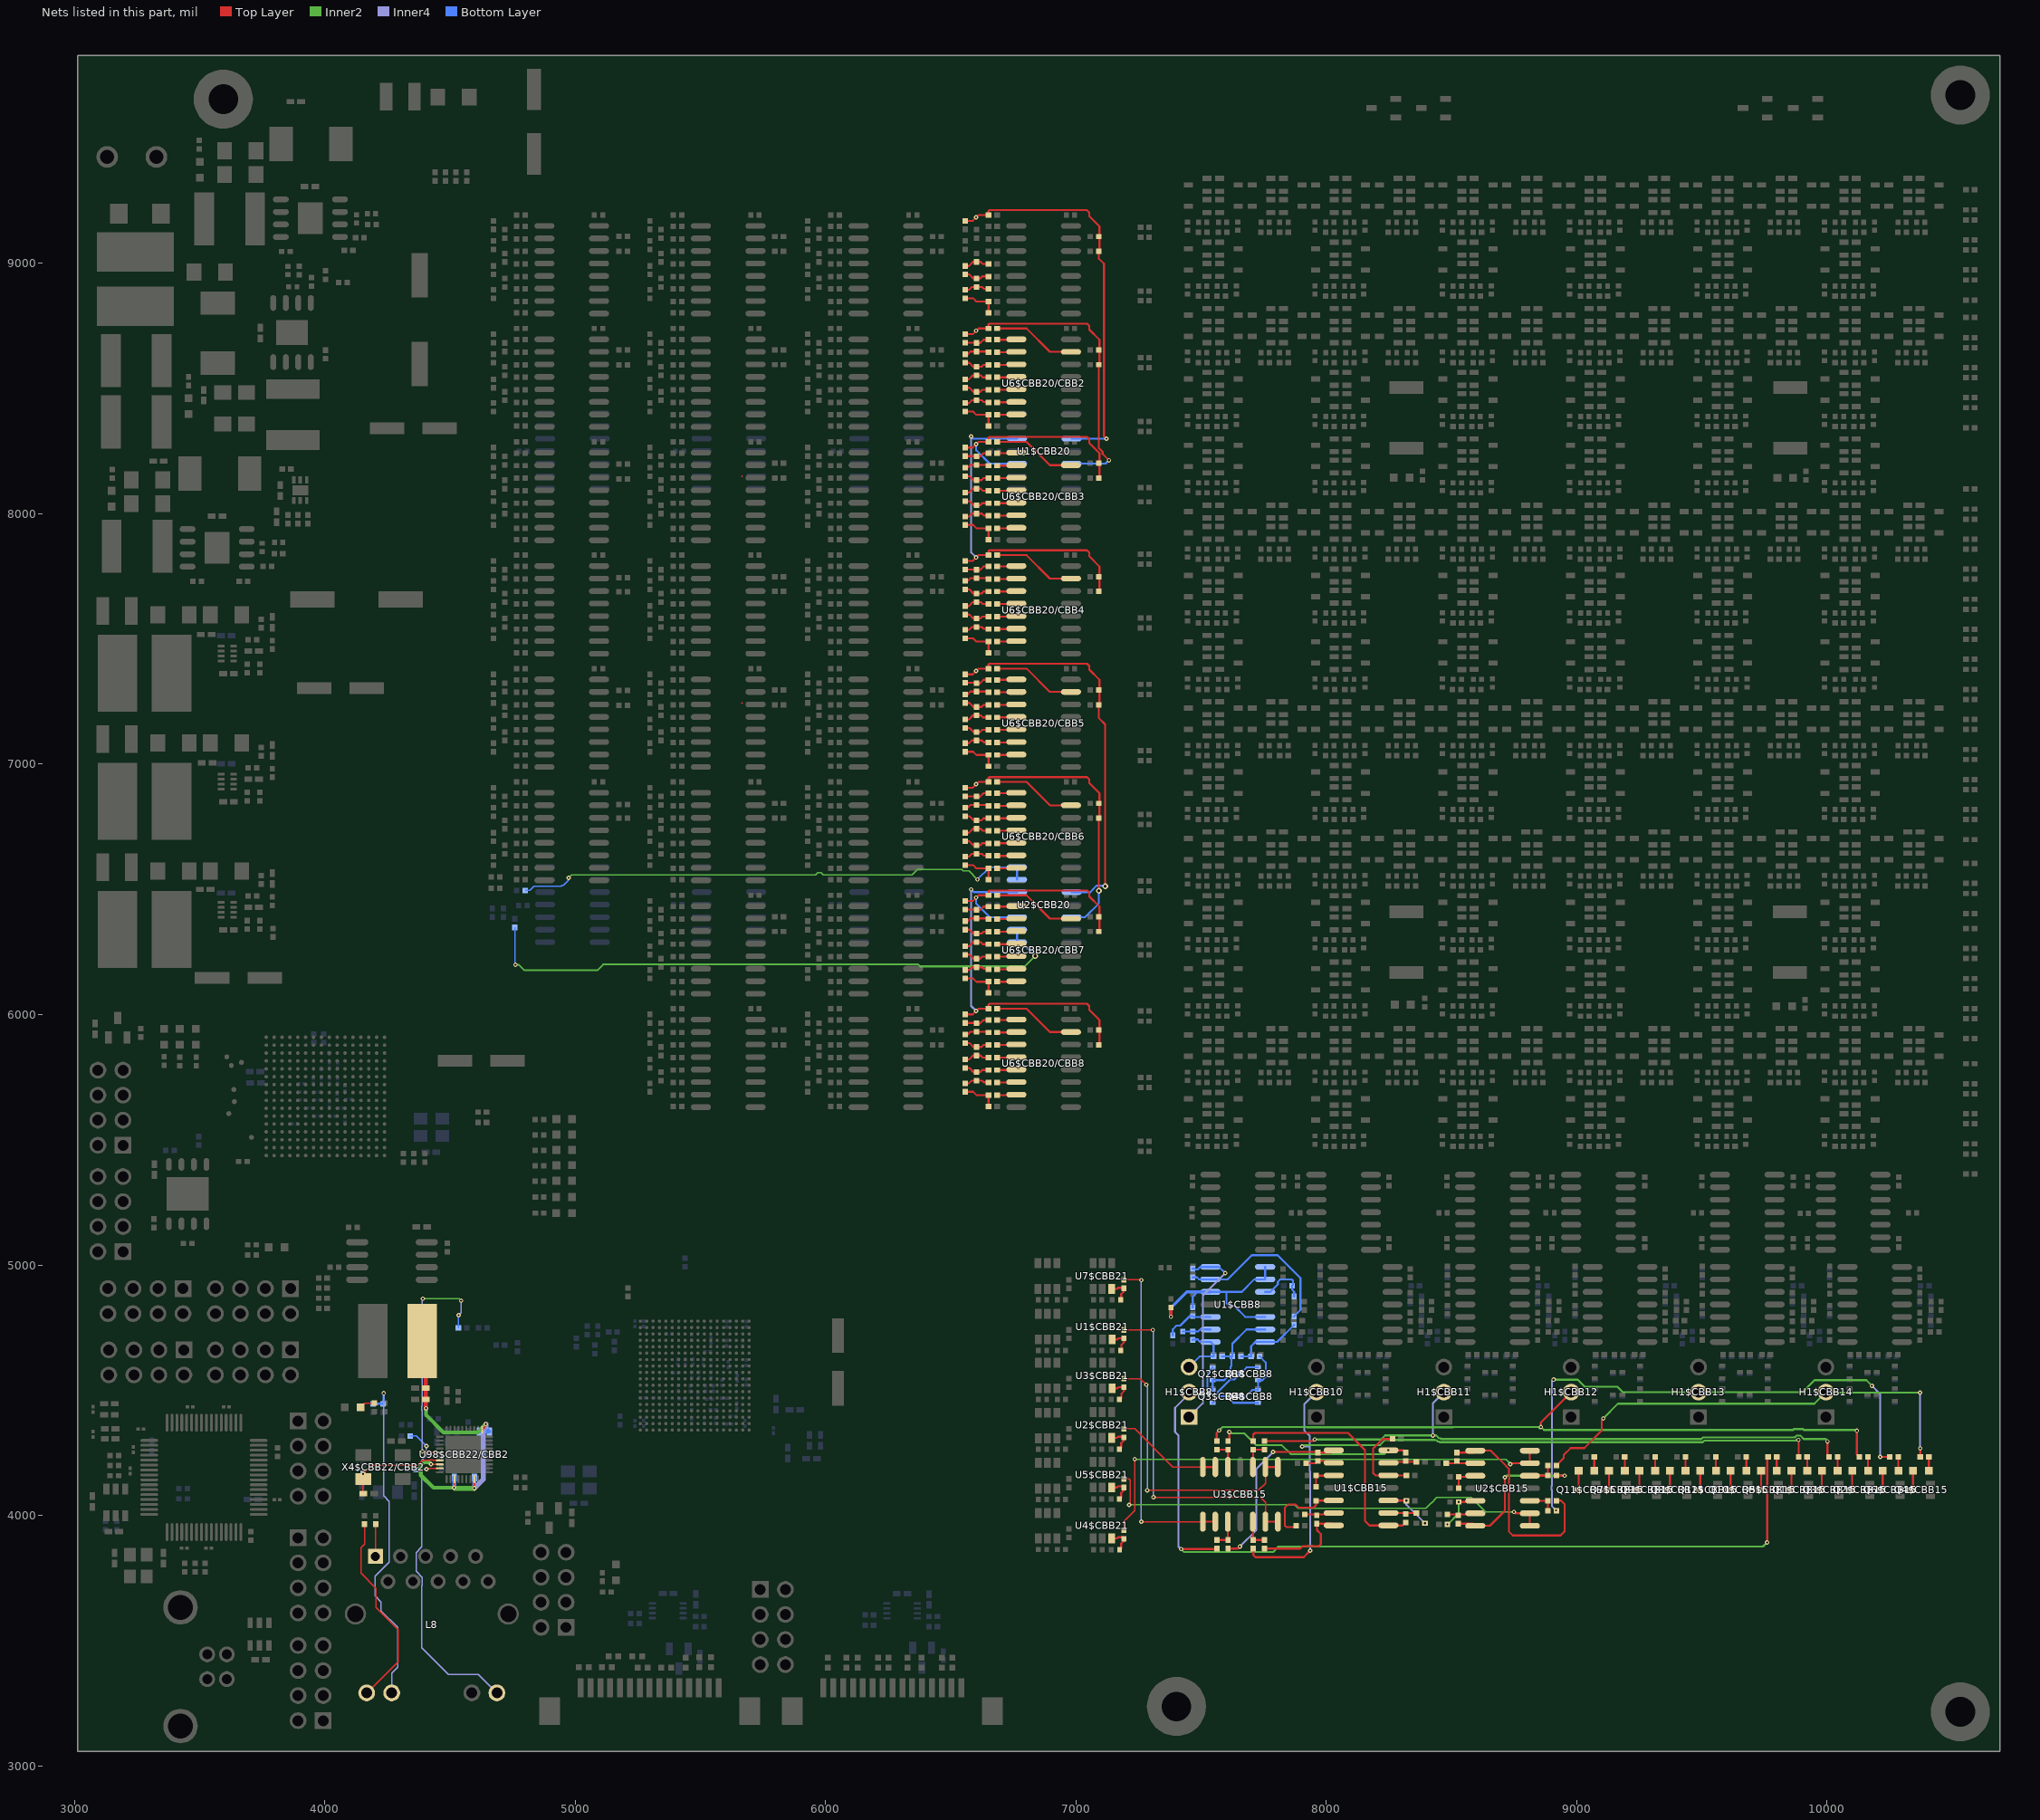
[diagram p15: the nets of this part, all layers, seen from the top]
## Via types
v1: diameter 17.7, hole 7.9, Top Layer to Bottom Layer, 3367 vias
v2: diameter 13.8, hole 7.9, Top Layer to Bottom Layer, 287 vias
v3: diameter 23.6, hole 11.8, Top Layer to Bottom Layer, 45 vias

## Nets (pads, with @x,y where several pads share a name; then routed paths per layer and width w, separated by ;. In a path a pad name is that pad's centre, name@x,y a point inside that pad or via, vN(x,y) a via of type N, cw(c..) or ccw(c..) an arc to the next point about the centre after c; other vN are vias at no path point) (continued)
$1I38\$1I15\$1N14: R4$CBB20/CBB1.2 R13$CBB20/CBB1.1 R14$CBB20/CBB1.2 | length 102.8
  Top Layer w7.9: R13$CBB20/CBB1.1@6558.6,8955.8 6574.9,8955.8 6590.8,8939.9 R14$CBB20/CBB1.2@6603.6,8939.9 6618.1,8939.9 6626.1,8947.8 R4$CBB20/CBB1.2@6651.6,8947.8
$1I38\$1I15\$1N15: R5$CBB20/CBB1.2 R12$CBB20/CBB1.1 R13$CBB20/CBB1.2 | length 102.9
  Top Layer w7.9: R13$CBB20/CBB1.2@6558.6,8989.9 6573.1,8989.9 6589,9005.8 R12$CBB20/CBB1.1@6603.6,9005.8 6619.9,9005.8 6627.9,8997.8 R5$CBB20/CBB1.2@6651.6,8997.8
$1I38\$1I15\$1N16: R1$CBB20/CBB1.2 R15$CBB20/CBB1.1 R16$CBB20/CBB1.2 | length 143.4
  Top Layer w7.9: R15$CBB20/CBB1.1@6558.6,8860.8 6589.9,8860.8 6602.9,8847.8 R1$CBB20/CBB1.2@6651.6,8847.8 R16$CBB20/CBB1.2@6651.6,8802.8
$1I38\$1I15\$1N17: R3$CBB20/CBB1.2 R14$CBB20/CBB1.1 R15$CBB20/CBB1.2 | length 100.8
  Top Layer w7.9: R15$CBB20/CBB1.2@6558.6,8894.9 6573.1,8894.9 6584,8905.8 R14$CBB20/CBB1.1@6603.6,8905.8 6624.9,8905.8 6632,8898.7 6650.7,8898.7 R3$CBB20/CBB1.2@6651.6,8897.8
$1I38\$1I15\DAC_LAD_OUT: R2$CBB20/CBB1.2 R9$CBB20/CBB1.2 R16$CBB20.1 R32$CBB20.2 U1$CBB20.3 | length 1596.8
  Top Layer w7.9: R2$CBB20/CBB1.2@6558.6,9169.9 6588.1,9169.9 v1(6602,9183.7) 6611.1,9192.8 R9$CBB20/CBB1.2@6651.6,9192.8 6651.6,9209.4 6654.6,9212.4 7044.3,9212.4 7053.3,9203.4 7053.3,9188.4 7094,9147.7 R32$CBB20.2@7094,9048.7 ; R32$CBB20.2@7091.8,9048.1 7092.1,9047.9 7092.1,9018.7 7112.1,8998.7 7112.1,8310.1 v1(7122.1,8300.1)
  Bottom Layer w7.9: U1$CBB20.3@6983.2,8300.1 v1(7122.1,8300.1)
$1I38\$1I19\$1N1: R9$CBB20/CBB2.1 U6$CBB20/CBB2.15 | length 333.5
  Top Layer w7.9: R9$CBB20/CBB2.1@6685.7,8740.1 6802.9,8740.1 6896.1,8646.8 U6$CBB20/CBB2.15@6980.5,8646.8
$1I38\$1I19\$1N2: R8$CBB20/CBB2.1 U6$CBB20/CBB2.1 | length 77.5
  Top Layer w7.9: R8$CBB20/CBB2.1@6685.7,8695.1 6760.7,8695.1 U6$CBB20/CBB2.1@6762.5,8696.8
$1I38\$1I19\$1N3: R7$CBB20/CBB2.1 U6$CBB20/CBB2.2 | length 77.5
  Top Layer w7.9: R7$CBB20/CBB2.1@6685.7,8645.1 6760.7,8645.1 U6$CBB20/CBB2.2@6762.5,8646.8
$1I38\$1I19\$1N4: R6$CBB20/CBB2.1 U6$CBB20/CBB2.3 | length 77.5
  Top Layer w7.9: R6$CBB20/CBB2.1@6685.7,8595.1 6760.7,8595.1 U6$CBB20/CBB2.3@6762.5,8596.8
$1I38\$1I19\$1N5: R5$CBB20/CBB2.1 U6$CBB20/CBB2.4 | length 77.5
  Top Layer w7.9: R5$CBB20/CBB2.1@6685.7,8545.1 6760.7,8545.1 U6$CBB20/CBB2.4@6762.5,8546.8
$1I38\$1I19\$1N6: R4$CBB20/CBB2.1 U6$CBB20/CBB2.5 | length 77.5
  Top Layer w7.9: R4$CBB20/CBB2.1@6685.7,8495.1 6760.7,8495.1 U6$CBB20/CBB2.5@6762.5,8496.8
$1I38\$1I19\$1N7: R3$CBB20/CBB2.1 U6$CBB20/CBB2.6 | length 77.5
  Top Layer w7.9: R3$CBB20/CBB2.1@6685.7,8445.1 6760.7,8445.1 U6$CBB20/CBB2.6@6762.5,8446.8
$1I38\$1I19\$1N8: R1$CBB20/CBB2.1 U6$CBB20/CBB2.7 | length 77.5
  Top Layer w7.9: R1$CBB20/CBB2.1@6685.7,8395.1 6760.7,8395.1 U6$CBB20/CBB2.7@6762.5,8396.8
$1I38\$1I19\$1N11: R2$CBB20/CBB2.1 R8$CBB20/CBB2.2 R10$CBB20/CBB2.2 | length 99.6
  Top Layer w7.9: R2$CBB20/CBB2.1@6558.6,8683 6602.7,8683 R10$CBB20/CBB2.2@6603.6,8682.1 6604.8,8681 6617,8681 6631.1,8695.1 R8$CBB20/CBB2.2@6651.6,8695.1
$1I38\$1I19\$1N12: R6$CBB20/CBB2.2 R11$CBB20/CBB2.1 R12$CBB20/CBB2.2 | length 102.9
  Top Layer w7.9: R11$CBB20/CBB2.1@6558.6,8603 6574.9,8603 6590.8,8587.1 R12$CBB20/CBB2.2@6603.6,8587.1 6623.1,8587.1 6631.1,8595.1 R6$CBB20/CBB2.2@6651.6,8595.1
$1I38\$1I19\$1N13: R7$CBB20/CBB2.2 R10$CBB20/CBB2.1 R11$CBB20/CBB2.2 | length 98.7
  Top Layer w7.9: R11$CBB20/CBB2.2@6558.6,8637.1 6568.1,8637.1 6579,8648 R10$CBB20/CBB2.1@6603.6,8648 6648.6,8648 R7$CBB20/CBB2.2@6651.6,8645.1
$1I38\$1I19\$1N14: R4$CBB20/CBB2.2 R13$CBB20/CBB2.1 R14$CBB20/CBB2.2 | length 102.9
  Top Layer w7.9: R13$CBB20/CBB2.1@6558.6,8503 6574.9,8503 6590.8,8487.1 R14$CBB20/CBB2.2@6603.6,8487.1 6618.1,8487.1 6626.1,8495.1 R4$CBB20/CBB2.2@6651.6,8495.1
$1I38\$1I19\$1N15: R5$CBB20/CBB2.2 R12$CBB20/CBB2.1 R13$CBB20/CBB2.2 | length 102.8
  Top Layer w7.9: R13$CBB20/CBB2.2@6558.6,8537.1 6573.1,8537.1 6589,8553 R12$CBB20/CBB2.1@6603.6,8553 6619.9,8553 6627.9,8545.1 R5$CBB20/CBB2.2@6651.6,8545.1
$1I38\$1I19\$1N16: R1$CBB20/CBB2.2 R15$CBB20/CBB2.1 R16$CBB20/CBB2.2 | length 143.3
  Top Layer w7.9: R15$CBB20/CBB2.1@6558.6,8408 6589.9,8408 6602.9,8395.1 R1$CBB20/CBB2.2@6651.6,8395.1 R16$CBB20/CBB2.2@6651.6,8350.1
$1I38\$1I19\$1N17: R3$CBB20/CBB2.2 R14$CBB20/CBB2.1 R15$CBB20/CBB2.2 | length 100.8
  Top Layer w7.9: R15$CBB20/CBB2.2@6558.6,8442.1 6573.1,8442.1 6584,8453 R14$CBB20/CBB2.1@6603.6,8453 6624.9,8453 6632,8446 6650.7,8446 R3$CBB20/CBB2.2@6651.6,8445.1
$1I38\$1I19\DAC_LAD_OUT: R2$CBB20/CBB2.2 R9$CBB20/CBB2.2 R48$CBB20.1 R64$CBB20.2 U1$CBB20.5 | length 1250.1
  Top Layer w7.9: R2$CBB20/CBB2.2@6558.6,8717.1 6588.1,8717.1 v1(6602,8731) 6611.1,8740.1 R9$CBB20/CBB2.2@6651.6,8740.1 6651.6,8756.6 6654.6,8759.6 7044.3,8759.6 7053.3,8750.7 7053.3,8735.7 7094,8695 R64$CBB20.2@7094,8596 ; R64$CBB20.2@7091.8,8595.4 7091.8,8262.6 7106.9,8247.5 7106.9,8239 v1(7132.1,8213.7)
  Bottom Layer w7.9: U1$CBB20.5@6983.2,8200.1 7118.5,8200.1 v1(7132.1,8213.7)
$1I38\$1I21\$1N1: R9$CBB20/CBB3.1 U6$CBB20/CBB3.15 | length 333.4
  Top Layer w7.9: R9$CBB20/CBB3.1@6685.7,8287.3 6802.9,8287.3 6896.1,8194.1 U6$CBB20/CBB3.15@6980.5,8194.1
$1I38\$1I21\$1N2: R8$CBB20/CBB3.1 U6$CBB20/CBB3.1 | length 77.5
  Top Layer w7.9: R8$CBB20/CBB3.1@6685.7,8242.3 6760.7,8242.3 U6$CBB20/CBB3.1@6762.5,8244.1
$1I38\$1I21\$1N3: R7$CBB20/CBB3.1 U6$CBB20/CBB3.2 | length 77.5
  Top Layer w7.9: R7$CBB20/CBB3.1@6685.7,8192.3 6760.7,8192.3 U6$CBB20/CBB3.2@6762.5,8194.1
$1I38\$1I21\$1N4: R6$CBB20/CBB3.1 U6$CBB20/CBB3.3 | length 77.5
  Top Layer w7.9: R6$CBB20/CBB3.1@6685.7,8142.3 6760.7,8142.3 U6$CBB20/CBB3.3@6762.5,8144.1
$1I38\$1I21\$1N5: R5$CBB20/CBB3.1 U6$CBB20/CBB3.4 | length 77.5
  Top Layer w7.9: R5$CBB20/CBB3.1@6685.7,8092.3 6760.7,8092.3 U6$CBB20/CBB3.4@6762.5,8094.1
$1I38\$1I21\$1N6: R4$CBB20/CBB3.1 U6$CBB20/CBB3.5 | length 77.5
  Top Layer w7.9: R4$CBB20/CBB3.1@6685.7,8042.3 6760.7,8042.3 U6$CBB20/CBB3.5@6762.5,8044.1
$1I38\$1I21\$1N7: R3$CBB20/CBB3.1 U6$CBB20/CBB3.6 | length 77.5
  Top Layer w7.9: R3$CBB20/CBB3.1@6685.7,7992.3 6760.7,7992.3 U6$CBB20/CBB3.6@6762.5,7994.1
$1I38\$1I21\$1N8: R1$CBB20/CBB3.1 U6$CBB20/CBB3.7 | length 77.5
  Top Layer w7.9: R1$CBB20/CBB3.1@6685.7,7942.3 6760.7,7942.3 U6$CBB20/CBB3.7@6762.5,7944.1
$1I38\$1I21\$1N11: R2$CBB20/CBB3.1 R8$CBB20/CBB3.2 R10$CBB20/CBB3.2 | length 99.7
  Top Layer w7.9: R2$CBB20/CBB3.1@6558.6,8230.3 6602.7,8230.3 R10$CBB20/CBB3.2@6603.6,8229.4 6604.8,8228.2 6617,8228.2 6631.1,8242.3 R8$CBB20/CBB3.2@6651.6,8242.3
$1I38\$1I21\$1N12: R6$CBB20/CBB3.2 R11$CBB20/CBB3.1 R12$CBB20/CBB3.2 | length 102.8
  Top Layer w7.9: R11$CBB20/CBB3.1@6558.6,8150.3 6574.9,8150.3 6590.8,8134.4 R12$CBB20/CBB3.2@6603.6,8134.4 6623.1,8134.4 6631.1,8142.3 R6$CBB20/CBB3.2@6651.6,8142.3
$1I38\$1I21\$1N13: R7$CBB20/CBB3.2 R10$CBB20/CBB3.1 R11$CBB20/CBB3.2 | length 98.8
  Top Layer w7.9: R11$CBB20/CBB3.2@6558.6,8184.4 6568.1,8184.4 6579,8195.3 R10$CBB20/CBB3.1@6603.6,8195.3 6648.6,8195.3 R7$CBB20/CBB3.2@6651.6,8192.3
$1I38\$1I21\$1N14: R4$CBB20/CBB3.2 R13$CBB20/CBB3.1 R14$CBB20/CBB3.2 | length 102.8
  Top Layer w7.9: R13$CBB20/CBB3.1@6558.6,8050.3 6574.9,8050.3 6590.8,8034.4 R14$CBB20/CBB3.2@6603.6,8034.4 6618.1,8034.4 6626.1,8042.3 R4$CBB20/CBB3.2@6651.6,8042.3
$1I38\$1I21\$1N15: R5$CBB20/CBB3.2 R12$CBB20/CBB3.1 R13$CBB20/CBB3.2 | length 102.9
  Top Layer w7.9: R13$CBB20/CBB3.2@6558.6,8084.4 6573.1,8084.4 6589,8100.3 R12$CBB20/CBB3.1@6603.6,8100.3 6619.9,8100.3 6627.9,8092.3 R5$CBB20/CBB3.2@6651.6,8092.3
$1I38\$1I21\$1N16: R1$CBB20/CBB3.2 R15$CBB20/CBB3.1 R16$CBB20/CBB3.2 | length 143.4
  Top Layer w7.9: R15$CBB20/CBB3.1@6558.6,7955.3 6589.9,7955.3 6602.9,7942.3 R1$CBB20/CBB3.2@6651.6,7942.3 R16$CBB20/CBB3.2@6651.6,7897.3
$1I38\$1I21\$1N17: R3$CBB20/CBB3.2 R14$CBB20/CBB3.1 R15$CBB20/CBB3.2 | length 100.8
  Top Layer w7.9: R15$CBB20/CBB3.2@6558.6,7989.4 6573.1,7989.4 6584,8000.3 R14$CBB20/CBB3.1@6603.6,8000.3 6624.9,8000.3 6632,7993.2 6650.7,7993.2 R3$CBB20/CBB3.2@6651.6,7992.3
$1I38\$1I21\DAC_LAD_OUT: R2$CBB20/CBB3.2 R9$CBB20/CBB3.2 R80$CBB20.1 R96$CBB20.2 U1$CBB20.10 | length 907.2
  Top Layer w7.9: R2$CBB20/CBB3.2@6558.6,8264.4 6588.1,8264.4 v1(6602,8278.2) 6611.1,8287.3 R9$CBB20/CBB3.2@6651.6,8287.3 6651.6,8303.9 6654.6,8306.9 7044.3,8306.9 7053.3,8297.9 7053.3,8282.9 7094,8242.2 R96$CBB20.2@7094,8143.2
  Bottom Layer w7.9: v1(6602,8278.2) 6602,8253.7 6655.6,8200.1 U1$CBB20.10@6765.2,8200.1
$1I38\$1I23\$1N1: R9$CBB20/CBB4.1 U6$CBB20/CBB4.15 | length 333.5
  Top Layer w7.9: R9$CBB20/CBB4.1@6685.7,7834.6 6802.9,7834.6 6896.1,7741.3 U6$CBB20/CBB4.15@6980.5,7741.3
$1I38\$1I23\$1N2: R8$CBB20/CBB4.1 U6$CBB20/CBB4.1 | length 77.5
  Top Layer w7.9: R8$CBB20/CBB4.1@6685.7,7789.6 6760.7,7789.6 U6$CBB20/CBB4.1@6762.5,7791.3
$1I38\$1I23\$1N3: R7$CBB20/CBB4.1 U6$CBB20/CBB4.2 | length 77.5
  Top Layer w7.9: R7$CBB20/CBB4.1@6685.7,7739.6 6760.7,7739.6 U6$CBB20/CBB4.2@6762.5,7741.3
$1I38\$1I23\$1N4: R6$CBB20/CBB4.1 U6$CBB20/CBB4.3 | length 77.5
  Top Layer w7.9: R6$CBB20/CBB4.1@6685.7,7689.6 6760.7,7689.6 U6$CBB20/CBB4.3@6762.5,7691.3
$1I38\$1I23\$1N5: R5$CBB20/CBB4.1 U6$CBB20/CBB4.4 | length 77.5
  Top Layer w7.9: R5$CBB20/CBB4.1@6685.7,7639.6 6760.7,7639.6 U6$CBB20/CBB4.4@6762.5,7641.3
$1I38\$1I23\$1N6: R4$CBB20/CBB4.1 U6$CBB20/CBB4.5 | length 77.5
  Top Layer w7.9: R4$CBB20/CBB4.1@6685.7,7589.6 6760.7,7589.6 U6$CBB20/CBB4.5@6762.5,7591.3
$1I38\$1I23\$1N7: R3$CBB20/CBB4.1 U6$CBB20/CBB4.6 | length 77.5
  Top Layer w7.9: R3$CBB20/CBB4.1@6685.7,7539.6 6760.7,7539.6 U6$CBB20/CBB4.6@6762.5,7541.3
$1I38\$1I23\$1N8: R1$CBB20/CBB4.1 U6$CBB20/CBB4.7 | length 77.5
  Top Layer w7.9: R1$CBB20/CBB4.1@6685.7,7489.6 6760.7,7489.6 U6$CBB20/CBB4.7@6762.5,7491.3
$1I38\$1I23\$1N11: R2$CBB20/CBB4.1 R8$CBB20/CBB4.2 R10$CBB20/CBB4.2 | length 99.6
  Top Layer w7.9: R2$CBB20/CBB4.1@6558.6,7777.5 6602.7,7777.5 R10$CBB20/CBB4.2@6603.6,7776.6 6604.8,7775.5 6617,7775.5 6631.1,7789.6 R8$CBB20/CBB4.2@6651.6,7789.6
$1I38\$1I23\$1N12: R6$CBB20/CBB4.2 R11$CBB20/CBB4.1 R12$CBB20/CBB4.2 | length 102.9
  Top Layer w7.9: R11$CBB20/CBB4.1@6558.6,7697.5 6574.9,7697.5 6590.8,7681.6 R12$CBB20/CBB4.2@6603.6,7681.6 6623.1,7681.6 6631.1,7689.6 R6$CBB20/CBB4.2@6651.6,7689.6
$1I38\$1I23\$1N13: R7$CBB20/CBB4.2 R10$CBB20/CBB4.1 R11$CBB20/CBB4.2 | length 98.7
  Top Layer w7.9: R11$CBB20/CBB4.2@6558.6,7731.6 6568.1,7731.6 6579,7742.5 R10$CBB20/CBB4.1@6603.6,7742.5 6648.6,7742.5 R7$CBB20/CBB4.2@6651.6,7739.6
$1I38\$1I23\$1N14: R4$CBB20/CBB4.2 R13$CBB20/CBB4.1 R14$CBB20/CBB4.2 | length 102.9
  Top Layer w7.9: R13$CBB20/CBB4.1@6558.6,7597.5 6574.9,7597.5 6590.8,7581.6 R14$CBB20/CBB4.2@6603.6,7581.6 6618.1,7581.6 6626.1,7589.6 R4$CBB20/CBB4.2@6651.6,7589.6
$1I38\$1I23\$1N15: R5$CBB20/CBB4.2 R12$CBB20/CBB4.1 R13$CBB20/CBB4.2 | length 102.8
  Top Layer w7.9: R13$CBB20/CBB4.2@6558.6,7631.6 6573.1,7631.6 6589,7647.5 R12$CBB20/CBB4.1@6603.6,7647.5 6619.9,7647.5 6627.9,7639.6 R5$CBB20/CBB4.2@6651.6,7639.6
$1I38\$1I23\$1N16: R1$CBB20/CBB4.2 R15$CBB20/CBB4.1 R16$CBB20/CBB4.2 | length 143.3
  Top Layer w7.9: R15$CBB20/CBB4.1@6558.6,7502.5 6589.9,7502.5 6602.9,7489.6 R1$CBB20/CBB4.2@6651.6,7489.6 R16$CBB20/CBB4.2@6651.6,7444.6
$1I38\$1I23\$1N17: R3$CBB20/CBB4.2 R14$CBB20/CBB4.1 R15$CBB20/CBB4.2 | length 100.8
  Top Layer w7.9: R15$CBB20/CBB4.2@6558.6,7536.6 6573.1,7536.6 6584,7547.5 R14$CBB20/CBB4.1@6603.6,7547.5 6624.9,7547.5 6632,7540.5 6650.7,7540.5 R3$CBB20/CBB4.2@6651.6,7539.6
$1I38\$1I23\DAC_LAD_OUT: R2$CBB20/CBB4.2 R9$CBB20/CBB4.2 R112$CBB20.1 R128$CBB20.2 U1$CBB20.12 | length 1375.5
  Top Layer w7.9: R2$CBB20/CBB4.2@6558.6,7811.6 6588.1,7811.6 v1(6602,7825.5) 6611.1,7834.6 R9$CBB20/CBB4.2@6651.6,7834.6 6651.6,7851.1 6654.6,7854.1 7044.3,7854.1 7053.3,7845.1 7053.3,7830.1 7094,7789.4 R128$CBB20.2@7094,7690.4
  Inner4 w7.9: v1(6582,8308.7) 6582.1,8308.6 6582.1,7845.3 v1(6602,7825.5)
  Bottom Layer w7.9: v1(6582,8308.7) 6590.6,8300.1 U1$CBB20.12@6765.2,8300.1
$1I38\$1I33\$1N1: R9$CBB20/CBB5.1 U6$CBB20/CBB5.15 | length 333.4
  Top Layer w7.9: R9$CBB20/CBB5.1@6685.7,7381.8 6802.9,7381.8 6896.1,7288.6 U6$CBB20/CBB5.15@6980.5,7288.6
$1I38\$1I33\$1N2: R8$CBB20/CBB5.1 U6$CBB20/CBB5.1 | length 77.5
  Top Layer w7.9: R8$CBB20/CBB5.1@6685.7,7336.8 6760.7,7336.8 U6$CBB20/CBB5.1@6762.5,7338.6
$1I38\$1I33\$1N3: R7$CBB20/CBB5.1 U6$CBB20/CBB5.2 | length 77.5
  Top Layer w7.9: R7$CBB20/CBB5.1@6685.7,7286.8 6760.7,7286.8 U6$CBB20/CBB5.2@6762.5,7288.6
$1I38\$1I33\$1N4: R6$CBB20/CBB5.1 U6$CBB20/CBB5.3 | length 77.5
  Top Layer w7.9: R6$CBB20/CBB5.1@6685.7,7236.8 6760.7,7236.8 U6$CBB20/CBB5.3@6762.5,7238.6
$1I38\$1I33\$1N5: R5$CBB20/CBB5.1 U6$CBB20/CBB5.4 | length 77.5
  Top Layer w7.9: R5$CBB20/CBB5.1@6685.7,7186.8 6760.7,7186.8 U6$CBB20/CBB5.4@6762.5,7188.6
$1I38\$1I33\$1N6: R4$CBB20/CBB5.1 U6$CBB20/CBB5.5 | length 77.5
  Top Layer w7.9: R4$CBB20/CBB5.1@6685.7,7136.8 6760.7,7136.8 U6$CBB20/CBB5.5@6762.5,7138.6
$1I38\$1I33\$1N7: R3$CBB20/CBB5.1 U6$CBB20/CBB5.6 | length 77.5
  Top Layer w7.9: R3$CBB20/CBB5.1@6685.7,7086.8 6760.7,7086.8 U6$CBB20/CBB5.6@6762.5,7088.6
$1I38\$1I33\$1N8: R1$CBB20/CBB5.1 U6$CBB20/CBB5.7 | length 77.5
  Top Layer w7.9: R1$CBB20/CBB5.1@6685.7,7036.8 6760.7,7036.8 U6$CBB20/CBB5.7@6762.5,7038.6
$1I38\$1I33\$1N11: R2$CBB20/CBB5.1 R8$CBB20/CBB5.2 R10$CBB20/CBB5.2 | length 99.7
  Top Layer w7.9: R2$CBB20/CBB5.1@6558.6,7324.8 6602.7,7324.8 R10$CBB20/CBB5.2@6603.6,7323.8 6604.8,7322.7 6617,7322.7 6631.1,7336.8 R8$CBB20/CBB5.2@6651.6,7336.8
$1I38\$1I33\$1N12: R6$CBB20/CBB5.2 R11$CBB20/CBB5.1 R12$CBB20/CBB5.2 | length 103
  Top Layer w7.9: R11$CBB20/CBB5.1@6558.6,7244.8 6574.9,7244.8 6590.8,7228.8 R12$CBB20/CBB5.2@6603.6,7228.8 6623.1,7228.8 6631.1,7236.8 R6$CBB20/CBB5.2@6651.6,7236.8
$1I38\$1I33\$1N13: R7$CBB20/CBB5.2 R10$CBB20/CBB5.1 R11$CBB20/CBB5.2 | length 98.8
  Top Layer w7.9: R11$CBB20/CBB5.2@6558.6,7278.8 6568.1,7278.8 6579,7289.8 R10$CBB20/CBB5.1@6603.6,7289.8 6648.6,7289.8 R7$CBB20/CBB5.2@6651.6,7286.8
$1I38\$1I33\$1N14: R4$CBB20/CBB5.2 R13$CBB20/CBB5.1 R14$CBB20/CBB5.2 | length 103
  Top Layer w7.9: R13$CBB20/CBB5.1@6558.6,7144.8 6574.9,7144.8 6590.8,7128.8 R14$CBB20/CBB5.2@6603.6,7128.8 6618.1,7128.8 6626.1,7136.8 R4$CBB20/CBB5.2@6651.6,7136.8
$1I38\$1I33\$1N15: R5$CBB20/CBB5.2 R12$CBB20/CBB5.1 R13$CBB20/CBB5.2 | length 103
  Top Layer w7.9: R13$CBB20/CBB5.2@6558.6,7178.8 6573.1,7178.8 6589,7194.8 R12$CBB20/CBB5.1@6603.6,7194.8 6619.9,7194.8 6627.9,7186.8 R5$CBB20/CBB5.2@6651.6,7186.8
$1I38\$1I33\$1N16: R1$CBB20/CBB5.2 R15$CBB20/CBB5.1 R16$CBB20/CBB5.2 | length 143.4
  Top Layer w7.9: R15$CBB20/CBB5.1@6558.6,7049.8 6589.9,7049.8 6602.9,7036.8 R1$CBB20/CBB5.2@6651.6,7036.8 R16$CBB20/CBB5.2@6651.6,6991.8
$1I38\$1I33\$1N17: R3$CBB20/CBB5.2 R14$CBB20/CBB5.1 R15$CBB20/CBB5.2 | length 100.9
  Top Layer w7.9: R15$CBB20/CBB5.2@6558.6,7083.8 6573.1,7083.8 6584,7094.8 R14$CBB20/CBB5.1@6603.6,7094.8 6624.9,7094.8 6632,7087.7 6650.7,7087.7 R3$CBB20/CBB5.2@6651.6,7086.8
$1I38\$1I33\DAC_LAD_OUT: R2$CBB20/CBB5.2 R9$CBB20/CBB5.2 R129$CBB20.1 R130$CBB20.2 U2$CBB20.3 | length 1578.8
  Top Layer w7.9: R2$CBB20/CBB5.2@6558.6,7358.8 6588.1,7358.8 v1(6602,7372.7) 6611.1,7381.8 R9$CBB20/CBB5.2@6651.6,7381.8 6651.6,7398.4 6654.6,7401.4 7044.3,7401.4 7053.3,7392.4 7053.3,7377.4 7094,7336.7 R130$CBB20.2@7094,7237.7 ; R130$CBB20.2@7091.8,7237.1 7092,7236.9 7092,7183.7 7117,7158.7 v3(7117,6512.6)
  Bottom Layer w7.9: U2$CBB20.3@6983.2,6489.1 7058,6489.1 7071.3,6502.3 7071.3,6503.4 7083.5,6515.5 7100.6,6515.5 7101.7,6514.5 7115.2,6514.5 v3(7117,6512.6)
$1I38\$1I34\$1N1: R9$CBB20/CBB6.1 U6$CBB20/CBB6.15 | length 333.4
  Top Layer w7.9: R9$CBB20/CBB6.1@6685.7,6929 6802.9,6929 6896.1,6835.8 U6$CBB20/CBB6.15@6980.5,6835.8
$1I38\$1I34\$1N2: R8$CBB20/CBB6.1 U6$CBB20/CBB6.1 | length 77.5
  Top Layer w7.9: R8$CBB20/CBB6.1@6685.7,6884 6760.7,6884 U6$CBB20/CBB6.1@6762.5,6885.8
$1I38\$1I34\$1N3: R7$CBB20/CBB6.1 U6$CBB20/CBB6.2 | length 77.5
  Top Layer w7.9: R7$CBB20/CBB6.1@6685.7,6834 6760.7,6834 U6$CBB20/CBB6.2@6762.5,6835.8
$1I38\$1I34\$1N4: R6$CBB20/CBB6.1 U6$CBB20/CBB6.3 | length 77.5
  Top Layer w7.9: R6$CBB20/CBB6.1@6685.7,6784 6760.7,6784 U6$CBB20/CBB6.3@6762.5,6785.8
$1I38\$1I34\$1N5: R5$CBB20/CBB6.1 U6$CBB20/CBB6.4 | length 77.5
  Top Layer w7.9: R5$CBB20/CBB6.1@6685.7,6734 6760.7,6734 U6$CBB20/CBB6.4@6762.5,6735.8
$1I38\$1I34\$1N6: R4$CBB20/CBB6.1 U6$CBB20/CBB6.5 | length 77.5
  Top Layer w7.9: R4$CBB20/CBB6.1@6685.7,6684 6760.7,6684 U6$CBB20/CBB6.5@6762.5,6685.8
$1I38\$1I34\$1N7: R3$CBB20/CBB6.1 U6$CBB20/CBB6.6 | length 77.5
  Top Layer w7.9: R3$CBB20/CBB6.1@6685.7,6634 6760.7,6634 U6$CBB20/CBB6.6@6762.5,6635.8
$1I38\$1I34\$1N8: R1$CBB20/CBB6.1 U6$CBB20/CBB6.7 | length 77.5
  Top Layer w7.9: R1$CBB20/CBB6.1@6685.7,6584 6760.7,6584 U6$CBB20/CBB6.7@6762.5,6585.8
$1I38\$1I34\$1N11: R2$CBB20/CBB6.1 R8$CBB20/CBB6.2 R10$CBB20/CBB6.2 | length 99.6
  Top Layer w7.9: R2$CBB20/CBB6.1@6558.6,6872 6602.7,6872 R10$CBB20/CBB6.2@6603.6,6871.1 6604.8,6870 6617,6870 6631.1,6884 R8$CBB20/CBB6.2@6651.6,6884
$1I38\$1I34\$1N12: R6$CBB20/CBB6.2 R11$CBB20/CBB6.1 R12$CBB20/CBB6.2 | length 102.8
  Top Layer w7.9: R11$CBB20/CBB6.1@6558.6,6792 6574.9,6792 6590.8,6776.1 R12$CBB20/CBB6.2@6603.6,6776.1 6623.1,6776.1 6631.1,6784 R6$CBB20/CBB6.2@6651.6,6784
$1I38\$1I34\$1N13: R7$CBB20/CBB6.2 R10$CBB20/CBB6.1 R11$CBB20/CBB6.2 | length 98.8
  Top Layer w7.9: R11$CBB20/CBB6.2@6558.6,6826.1 6568.1,6826.1 6579,6837 R10$CBB20/CBB6.1@6603.6,6837 6648.6,6837 R7$CBB20/CBB6.2@6651.6,6834
$1I38\$1I34\$1N14: R4$CBB20/CBB6.2 R13$CBB20/CBB6.1 R14$CBB20/CBB6.2 | length 102.8
  Top Layer w7.9: R13$CBB20/CBB6.1@6558.6,6692 6574.9,6692 6590.8,6676.1 R14$CBB20/CBB6.2@6603.6,6676.1 6618.1,6676.1 6626.1,6684 R4$CBB20/CBB6.2@6651.6,6684
$1I38\$1I34\$1N15: R5$CBB20/CBB6.2 R12$CBB20/CBB6.1 R13$CBB20/CBB6.2 | length 102.9
  Top Layer w7.9: R13$CBB20/CBB6.2@6558.6,6726.1 6573.1,6726.1 6589,6742 R12$CBB20/CBB6.1@6603.6,6742 6619.9,6742 6627.9,6734 R5$CBB20/CBB6.2@6651.6,6734
$1I38\$1I34\$1N16: R1$CBB20/CBB6.2 R15$CBB20/CBB6.1 R16$CBB20/CBB6.2 | length 143.4
  Top Layer w7.9: R15$CBB20/CBB6.1@6558.6,6597 6589.9,6597 6602.9,6584 R1$CBB20/CBB6.2@6651.6,6584 R16$CBB20/CBB6.2@6651.6,6539
$1I38\$1I34\$1N17: R3$CBB20/CBB6.2 R14$CBB20/CBB6.1 R15$CBB20/CBB6.2 | length 100.8
  Top Layer w7.9: R15$CBB20/CBB6.2@6558.6,6631.1 6573.1,6631.1 6584,6642 R14$CBB20/CBB6.1@6603.6,6642 6624.9,6642 6632,6635 6650.7,6635 R3$CBB20/CBB6.2@6651.6,6634
$1I38\$1I34\DAC_LAD_OUT: R2$CBB20/CBB6.2 R9$CBB20/CBB6.2 R131$CBB20.1 R132$CBB20.2 U2$CBB20.5 | length 1169.4
  Top Layer w7.9: R2$CBB20/CBB6.2@6558.6,6906.1 6588.1,6906.1 v1(6602,6920) 6611.1,6929 R9$CBB20/CBB6.2@6651.6,6929 6651.6,6945.6 6654.6,6948.6 7044.3,6948.6 7053.3,6939.6 7053.3,6924.6 7094,6883.9 R132$CBB20.2@7094,6785 ; R132$CBB20.2@7091.8,6784.4 7091.8,6495 v3(7092,6494.8)
  Bottom Layer w7.9: U2$CBB20.5@6983.2,6389.1 7037.4,6389.1 7092,6443.7 v3(7092,6494.8)
$1I38\$1I35\$1N1: R9$CBB20/CBB7.1 U6$CBB20/CBB7.15 | length 333.4
  Top Layer w7.9: R9$CBB20/CBB7.1@6685.7,6476.3 6802.9,6476.3 6896.1,6383.1 U6$CBB20/CBB7.15@6980.5,6383.1
$1I38\$1I35\$1N2: R8$CBB20/CBB7.1 U6$CBB20/CBB7.1 | length 77.5
  Top Layer w7.9: R8$CBB20/CBB7.1@6685.7,6431.3 6760.7,6431.3 U6$CBB20/CBB7.1@6762.5,6433.1
$1I38\$1I35\$1N3: R7$CBB20/CBB7.1 U6$CBB20/CBB7.2 | length 77.5
  Top Layer w7.9: R7$CBB20/CBB7.1@6685.7,6381.3 6760.7,6381.3 U6$CBB20/CBB7.2@6762.5,6383.1
$1I38\$1I35\$1N4: R6$CBB20/CBB7.1 U6$CBB20/CBB7.3 | length 77.5
  Top Layer w7.9: R6$CBB20/CBB7.1@6685.7,6331.3 6760.7,6331.3 U6$CBB20/CBB7.3@6762.5,6333.1
$1I38\$1I35\$1N5: R5$CBB20/CBB7.1 U6$CBB20/CBB7.4 | length 77.5
  Top Layer w7.9: R5$CBB20/CBB7.1@6685.7,6281.3 6760.7,6281.3 U6$CBB20/CBB7.4@6762.5,6283.1
$1I38\$1I35\$1N6: R4$CBB20/CBB7.1 U6$CBB20/CBB7.5 | length 77.5
  Top Layer w7.9: R4$CBB20/CBB7.1@6685.7,6231.3 6760.7,6231.3 U6$CBB20/CBB7.5@6762.5,6233.1
$1I38\$1I35\$1N7: R3$CBB20/CBB7.1 U6$CBB20/CBB7.6 | length 77.5
  Top Layer w7.9: R3$CBB20/CBB7.1@6685.7,6181.3 6760.7,6181.3 U6$CBB20/CBB7.6@6762.5,6183.1
$1I38\$1I35\$1N8: R1$CBB20/CBB7.1 U6$CBB20/CBB7.7 | length 77.5
  Top Layer w7.9: R1$CBB20/CBB7.1@6685.7,6131.3 6760.7,6131.3 U6$CBB20/CBB7.7@6762.5,6133.1
$1I38\$1I35\$1N11: R2$CBB20/CBB7.1 R8$CBB20/CBB7.2 R10$CBB20/CBB7.2 | length 99.6
  Top Layer w7.9: R2$CBB20/CBB7.1@6558.6,6419.2 6602.7,6419.2 R10$CBB20/CBB7.2@6603.6,6418.3 6604.8,6417.2 6617,6417.2 6631.1,6431.3 R8$CBB20/CBB7.2@6651.6,6431.3
$1I38\$1I35\$1N12: R6$CBB20/CBB7.2 R11$CBB20/CBB7.1 R12$CBB20/CBB7.2 | length 102.9
  Top Layer w7.9: R11$CBB20/CBB7.1@6558.6,6339.2 6574.9,6339.2 6590.8,6323.3 R12$CBB20/CBB7.2@6603.6,6323.3 6623.1,6323.3 6631.1,6331.3 R6$CBB20/CBB7.2@6651.6,6331.3
$1I38\$1I35\$1N13: R7$CBB20/CBB7.2 R10$CBB20/CBB7.1 R11$CBB20/CBB7.2 | length 98.7
  Top Layer w7.9: R11$CBB20/CBB7.2@6558.6,6373.3 6568.1,6373.3 6579,6384.2 R10$CBB20/CBB7.1@6603.6,6384.2 6648.6,6384.2 R7$CBB20/CBB7.2@6651.6,6381.3
$1I38\$1I35\$1N14: R4$CBB20/CBB7.2 R13$CBB20/CBB7.1 R14$CBB20/CBB7.2 | length 102.9
  Top Layer w7.9: R13$CBB20/CBB7.1@6558.6,6239.2 6574.9,6239.2 6590.8,6223.3 R14$CBB20/CBB7.2@6603.6,6223.3 6618.1,6223.3 6626.1,6231.3 R4$CBB20/CBB7.2@6651.6,6231.3
$1I38\$1I35\$1N15: R5$CBB20/CBB7.2 R12$CBB20/CBB7.1 R13$CBB20/CBB7.2 | length 102.8
  Top Layer w7.9: R13$CBB20/CBB7.2@6558.6,6273.3 6573.1,6273.3 6589,6289.2 R12$CBB20/CBB7.1@6603.6,6289.2 6619.9,6289.2 6627.9,6281.3 R5$CBB20/CBB7.2@6651.6,6281.3
$1I38\$1I35\$1N16: R1$CBB20/CBB7.2 R15$CBB20/CBB7.1 R16$CBB20/CBB7.2 | length 143.3
  Top Layer w7.9: R15$CBB20/CBB7.1@6558.6,6144.2 6589.9,6144.2 6602.9,6131.3 R1$CBB20/CBB7.2@6651.6,6131.3 R16$CBB20/CBB7.2@6651.6,6086.3
$1I38\$1I35\$1N17: R3$CBB20/CBB7.2 R14$CBB20/CBB7.1 R15$CBB20/CBB7.2 | length 100.8
  Top Layer w7.9: R15$CBB20/CBB7.2@6558.6,6178.3 6573.1,6178.3 6584,6189.2 R14$CBB20/CBB7.1@6603.6,6189.2 6624.9,6189.2 6632,6182.2 6650.7,6182.2 R3$CBB20/CBB7.2@6651.6,6181.3
$1I38\$1I35\DAC_LAD_OUT: R2$CBB20/CBB7.2 R9$CBB20/CBB7.2 R133$CBB20.1 R134$CBB20.2 U2$CBB20.10 | length 907.2
  Top Layer w7.9: R2$CBB20/CBB7.2@6558.6,6453.3 6588.1,6453.3 v1(6602,6467.2) 6611.1,6476.3 R9$CBB20/CBB7.2@6651.6,6476.3 6651.6,6492.8 6654.6,6495.9 7044.3,6495.9 7053.3,6486.9 7053.3,6471.9 7094,6431.2 R134$CBB20.2@7094,6332.2
  Bottom Layer w7.9: v1(6602,6467.2) 6602,6442.7 6655.6,6389.1 U2$CBB20.10@6765.2,6389.1
$1I38\$1I36\$1N1: R9$CBB20/CBB8.1 U6$CBB20/CBB8.15 | length 333.4
  Top Layer w7.9: R9$CBB20/CBB8.1@6685.7,6023.5 6802.9,6023.5 6896.1,5930.3 U6$CBB20/CBB8.15@6980.5,5930.3
$1I38\$1I36\$1N2: R8$CBB20/CBB8.1 U6$CBB20/CBB8.1 | length 77.5
  Top Layer w7.9: R8$CBB20/CBB8.1@6685.7,5978.5 6760.7,5978.5 U6$CBB20/CBB8.1@6762.5,5980.3
$1I38\$1I36\$1N3: R7$CBB20/CBB8.1 U6$CBB20/CBB8.2 | length 77.5
  Top Layer w7.9: R7$CBB20/CBB8.1@6685.7,5928.5 6760.7,5928.5 U6$CBB20/CBB8.2@6762.5,5930.3
$1I38\$1I36\$1N4: R6$CBB20/CBB8.1 U6$CBB20/CBB8.3 | length 77.5
  Top Layer w7.9: R6$CBB20/CBB8.1@6685.7,5878.5 6760.7,5878.5 U6$CBB20/CBB8.3@6762.5,5880.3
$1I38\$1I36\$1N5: R5$CBB20/CBB8.1 U6$CBB20/CBB8.4 | length 77.5
  Top Layer w7.9: R5$CBB20/CBB8.1@6685.7,5828.5 6760.7,5828.5 U6$CBB20/CBB8.4@6762.5,5830.3
$1I38\$1I36\$1N6: R4$CBB20/CBB8.1 U6$CBB20/CBB8.5 | length 77.5
  Top Layer w7.9: R4$CBB20/CBB8.1@6685.7,5778.5 6760.7,5778.5 U6$CBB20/CBB8.5@6762.5,5780.3
$1I38\$1I36\$1N7: R3$CBB20/CBB8.1 U6$CBB20/CBB8.6 | length 77.5
  Top Layer w7.9: R3$CBB20/CBB8.1@6685.7,5728.5 6760.7,5728.5 U6$CBB20/CBB8.6@6762.5,5730.3
$1I38\$1I36\$1N8: R1$CBB20/CBB8.1 U6$CBB20/CBB8.7 | length 77.5
  Top Layer w7.9: R1$CBB20/CBB8.1@6685.7,5678.5 6760.7,5678.5 U6$CBB20/CBB8.7@6762.5,5680.3
$1I38\$1I36\$1N11: R2$CBB20/CBB8.1 R8$CBB20/CBB8.2 R10$CBB20/CBB8.2 | length 99.7
  Top Layer w7.9: R2$CBB20/CBB8.1@6558.6,5966.5 6602.7,5966.5 R10$CBB20/CBB8.2@6603.6,5965.6 6604.8,5964.4 6617,5964.4 6631.1,5978.5 R8$CBB20/CBB8.2@6651.6,5978.5
$1I38\$1I36\$1N12: R6$CBB20/CBB8.2 R11$CBB20/CBB8.1 R12$CBB20/CBB8.2 | length 102.8
  Top Layer w7.9: R11$CBB20/CBB8.1@6558.6,5886.5 6574.9,5886.5 6590.8,5870.6 R12$CBB20/CBB8.2@6603.6,5870.6 6623.1,5870.6 6631.1,5878.5 R6$CBB20/CBB8.2@6651.6,5878.5
$1I38\$1I36\$1N13: R7$CBB20/CBB8.2 R10$CBB20/CBB8.1 R11$CBB20/CBB8.2 | length 98.8
  Top Layer w7.9: R11$CBB20/CBB8.2@6558.6,5920.6 6568.1,5920.6 6579,5931.5 R10$CBB20/CBB8.1@6603.6,5931.5 6648.6,5931.5 R7$CBB20/CBB8.2@6651.6,5928.5
$1I38\$1I36\$1N14: R4$CBB20/CBB8.2 R13$CBB20/CBB8.1 R14$CBB20/CBB8.2 | length 102.8
  Top Layer w7.9: R13$CBB20/CBB8.1@6558.6,5786.5 6574.9,5786.5 6590.8,5770.6 R14$CBB20/CBB8.2@6603.6,5770.6 6618.1,5770.6 6626.1,5778.5 R4$CBB20/CBB8.2@6651.6,5778.5
$1I38\$1I36\$1N15: R5$CBB20/CBB8.2 R12$CBB20/CBB8.1 R13$CBB20/CBB8.2 | length 102.9
  Top Layer w7.9: R13$CBB20/CBB8.2@6558.6,5820.6 6573.1,5820.6 6589,5836.5 R12$CBB20/CBB8.1@6603.6,5836.5 6619.9,5836.5 6627.9,5828.5 R5$CBB20/CBB8.2@6651.6,5828.5
$1I38\$1I36\$1N16: R1$CBB20/CBB8.2 R15$CBB20/CBB8.1 R16$CBB20/CBB8.2 | length 143.4
  Top Layer w7.9: R15$CBB20/CBB8.1@6558.6,5691.5 6589.9,5691.5 6602.9,5678.5 R1$CBB20/CBB8.2@6651.6,5678.5 R16$CBB20/CBB8.2@6651.6,5633.5
$1I38\$1I36\$1N17: R3$CBB20/CBB8.2 R14$CBB20/CBB8.1 R15$CBB20/CBB8.2 | length 100.8
  Top Layer w7.9: R15$CBB20/CBB8.2@6558.6,5725.6 6573.1,5725.6 6584,5736.5 R14$CBB20/CBB8.1@6603.6,5736.5 6624.9,5736.5 6632,5729.4 6650.7,5729.4 R3$CBB20/CBB8.2@6651.6,5728.5
$1I38\$1I36\DAC_LAD_OUT: R2$CBB20/CBB8.2 R9$CBB20/CBB8.2 R135$CBB20.1 R136$CBB20.2 U2$CBB20.12 | length 1378.7
  Top Layer w7.9: R2$CBB20/CBB8.2@6558.6,6000.6 6588.1,6000.6 v1(6602,6014.4) 6611.1,6023.5 R9$CBB20/CBB8.2@6651.6,6023.5 6651.6,6040.1 6654.6,6043.1 7044.3,6043.1 7053.3,6034.1 7053.3,6019.1 7094,5978.4 R136$CBB20.2@7094,5879.4
  Inner4 w7.9: v1(6581.9,6499.8) 6581.9,6034.5 v1(6602,6014.4)
  Bottom Layer w7.9: v1(6581.9,6499.8) 6592.6,6489.1 U2$CBB20.12@6765.2,6489.1
$1I38\DAC_W_ROW7: R64.1 U2$CBB20.8 U2$CBB20.9 | length 2409.6
  Inner2 w7.3: v1(4761.7,6198.5) 4775.8,6198.5 4797.9,6176.4 5089,6176.4 5112.4,6199.8 6370.7,6199.8 6378.1,6192.5 6795.9,6192.5 v3(6837.1,6233.7)
  Bottom Layer w4.7: R64.1@4759.7,6348.1 4759.7,6200.5 v1(4761.7,6198.5)
  Bottom Layer w7.9: U2$CBB20.9@6765.2,6339.1 U2$CBB20.8@6765.2,6289.1 6781.8,6289.1 v3(6837.1,6233.7)
$1I38\DAC_W_ROW8: R1.1 U2$CBB20.13 U2$CBB20.14 | length 2098.4
  Inner2 w4.7: v1(4974,6546) 4985.8,6557.9 5961.5,6557.9 5969.8,6566.1 5983.2,6566.1 5991.4,6557.9 6346.2,6557.9 6368,6579.7 6544.7,6579.7 6550.4,6574 6572.8,6574 v1(6607,6539.8)
  Bottom Layer w4.7: R1.1@4800.9,6495.7 4820,6495.7 4836,6511.7 4944.4,6511.7 4948.5,6515.7 4953.2,6515.7 4974,6536.5 v1(4974,6546) ; v1(6607,6539.8) 6656.2,6589.1 U2$CBB20.14@6765.2,6589.1
  Bottom Layer w7.9: U2$CBB20.13@6765.2,6539.1 U2$CBB20.14@6765.2,6589.1
$1I39\$1N22: C5$CBB21.2 R6$CBB21.1 U7$CBB21.3 | length 102.8
  Top Layer w7.9: U7$CBB21.3@7143.3,4904.5 7164.3,4904.5 7168.5,4908.6 7190.9,4908.6 7190.9,4892.9 7181.1,4883.2 7181.1,4864.4 C5$CBB21.2@7177.4,4860.7
$1I39\$1N27: C6$CBB21.2 R1$CBB21.1 U1$CBB21.3 | length 102.9
  Top Layer w7.9: U1$CBB21.3@7144.5,4702.5 7165.5,4702.5 7169.7,4706.7 R1$CBB21.1@7192.1,4706.7 7192.1,4691 7182.4,4681.2 7182.4,4662.4 C6$CBB21.2@7178.7,4658.7
$1I39\$1N36: C8$CBB21.2 R3$CBB21.1 U3$CBB21.3 | length 102.9
  Top Layer w7.9: U3$CBB21.3@7144.5,4507.5 7165.5,4507.5 7169.7,4511.7 R3$CBB21.1@7192.1,4511.7 7192.1,4496 7182.4,4486.2 7182.4,4467.4 C8$CBB21.2@7178.7,4463.7
$1I39\$1N38: C9$CBB21.2 R2$CBB21.1 U2$CBB21.3 | length 102.8
  Top Layer w7.9: U2$CBB21.3@7143.3,4309.8 7164.3,4309.8 7168.5,4313.9 7190.9,4313.9 7190.9,4298.2 7181.1,4288.4 7181.1,4269.7 C9$CBB21.2@7177.4,4266
$1I39\$1N48: C10$CBB21.2 R5$CBB21.1 U5$CBB21.3 | length 102.9
  Top Layer w7.9: U5$CBB21.3@7143.3,4111.5 7164.3,4111.5 7168.5,4115.7 7190.9,4115.7 7190.9,4100 7181.1,4090.2 7181.1,4071.4 C10$CBB21.2@7177.4,4067.7
$1I39\$1N50: C11$CBB21.2 R4$CBB21.1 U4$CBB21.3 | length 102.8
  Top Layer w7.9: U4$CBB21.3@7143.3,3908.3 7164.3,3908.3 7168.5,3912.4 7190.9,3912.4 7190.9,3896.7 7181.1,3887 7181.1,3868.2 C11$CBB21.2@7177.4,3864.5
$1I111\$1N292: R86$CBB15.1 R87$CBB15.2 U1$CBB15.2 | length 117.3
  Top Layer w7.9: R86$CBB15.1@7919.2,4208.7 7959.2,4208.7 R87$CBB15.2@7967.1,4216.7 8023.3,4216.7 U1$CBB15.2@8030.3,4209.7
$1I111\$1N297: R85$CBB15.1 R88$CBB15.2 U1$CBB15.3 | length 116.5
  Top Layer w7.9: R85$CBB15.1@7959.2,4113.7 R88$CBB15.2@7959.2,4158.7 8029.4,4158.7 U1$CBB15.3@8030.3,4159.7
$1I111\$1N300: R89$CBB15.1 R92$CBB15.2 U1$CBB15.5 | length 351.2
  Top Layer w7.9: R89$CBB15.1@7880.1,3958.7 7875,3953.7 7839.8,3953.7 7834.2,3959.3 7834.2,4030.5 7847.8,4044.1 7876.9,4044.1 7889.6,4031.3 7949.5,4031.3 7959.8,4041.6 7959.8,4058.1 R92$CBB15.2@7959.2,4058.7 8029.4,4058.7 U1$CBB15.5@8030.3,4059.7
$1I111\$1N301: R90$CBB15.1 R91$CBB15.2 U1$CBB15.6 | length 118.6
  Top Layer w7.9: R90$CBB15.1@7914.2,4003.7 8024.4,4003.7 U1$CBB15.6@8030.3,4009.7
$1I111\$1N308: R93$CBB15.1 R96$CBB15.2 U1$CBB15.10 | length 192.8
  Top Layer w7.9: U1$CBB15.10@8248.4,4059.7 8249.3,4058.7 v1(8320.1,4058.7)
  Inner4 w7.9: v1(8320.1,4058.7) 8320.1,4042.8 v1(8394.2,3968.7)
$1I111\$1N309: R94$CBB15.1 R95$CBB15.2 U1$CBB15.9 | length 112.1
  Top Layer w7.9: U1$CBB15.9@8248.4,4009.7 8249.3,4008.7 R94$CBB15.1@8360.1,4008.7
$1I111\$1N314: R97$CBB15.1 R100$CBB15.2 U1$CBB15.12 | length 328.5
  Top Layer w7.9: R97$CBB15.1@8264.5,4305.1 8225.3,4305.1 8187.2,4266.9 8187.2,4168.5 8196,4159.7 U1$CBB15.12@8248.4,4159.7 8319.1,4159.7 R100$CBB15.2@8320.1,4158.7
$1I111\$1N315: R98$CBB15.1 R99$CBB15.2 U1$CBB15.13 | length 113.4
  Top Layer w7.9: U1$CBB15.13@8248.4,4209.7 8252.4,4213.7 R98$CBB15.1@8360.1,4213.7
$1I111\$1N323: R8$CBB15.1 R113$CBB15.1 U2$CBB15.12 | length 111.8
  Top Layer w7.9: U2$CBB15.12@8813.4,4158.3 8884.6,4158.3 R113$CBB15.1@8885.1,4158.7 R8$CBB15.1@8885.1,4198.7
$1I111\$1N324: R105$CBB15.1 R108$CBB15.2 U2$CBB15.5 | length 176.7
  Top Layer w7.9: v1(8529.2,4053.7) 8590.8,4053.7 U2$CBB15.5@8595.3,4058.3
  Inner2 w7.9: v1(8484.2,3963.7) 8529.2,4008.7 v1(8529.2,4053.7)
$1I111\$1N325: R7$CBB15.1 R109$CBB15.1 U2$CBB15.10 | length 111.8
  Top Layer w7.9: U2$CBB15.10@8813.4,4058.3 8884.6,4058.3 R109$CBB15.1@8885.1,4058.7 R7$CBB15.1@8885.1,4018.7
$1I111\$1N326: R101$CBB15.1 R104$CBB15.2 U2$CBB15.3 | length 113
  Top Layer w7.9: R101$CBB15.1@8529.2,4108.7 R104$CBB15.2@8529.2,4153.7 8590.8,4153.7 U2$CBB15.3@8595.3,4158.3
$1I111\$1N327: R102$CBB15.1 R103$CBB15.2 U2$CBB15.2 | length 122.9
  Top Layer w7.9: R102$CBB15.1@8479.2,4208.7 8514.2,4208.7 R103$CBB15.2@8522.1,4216.7 8530.5,4208.3 U2$CBB15.2@8595.3,4208.3
$1I111\$1N328: R106$CBB15.1 R107$CBB15.2 U2$CBB15.6 | length 113
  Top Layer w7.9: R106$CBB15.1@8484.2,4003.7 8590.8,4003.7 U2$CBB15.6@8595.3,4008.3
$1I111\$1N353: R4$CBB15.1 R9$CBB15.1 U3$CBB15.10 | length 115
  Top Layer w7.9: U3$CBB15.10@7707,4192.9 7707.9,4193.8 R9$CBB15.1@7707.9,4262.5 R4$CBB15.1@7752.9,4262.5
$1I111\$1N354: R6$CBB15.1 R13$CBB15.1 U3$CBB15.12 | length 115
  Top Layer w7.9: R6$CBB15.1@7562.9,4262.5 R13$CBB15.1@7607.9,4262.5 7607.9,4193.8 U3$CBB15.12@7607,4192.9
$1I111\$1N355: R1$CBB15.1 R2$CBB15.1 U3$CBB15.3 | length 118.6
  Top Layer w7.9: R2$CBB15.1@7562.9,3901.6 R1$CBB15.1@7607.9,3901.6 7607,3902.5 U3$CBB15.3@7607,3974.8
$1I111\$1N356: R3$CBB15.1 R5$CBB15.1 U3$CBB15.5 | length 118.6
  Top Layer w7.9: U3$CBB15.5@7707,3974.8 7707.9,3973.9 R3$CBB15.1@7707.9,3901.6 R5$CBB15.1@7752.9,3901.6
$1I111\$1N385: LED1$CBB15.2 R20$CBB15.1 | length 55.1
  Top Layer w7.9: R20$CBB15.1@9798.9,4233.3 9799.3,4232.9 LED1$CBB15.2@9799.3,4178.4
$1I111\$1N388: LED1$CBB15.1 Q5$CBB15.3 | length 79
  Top Layer w7.9: Q5$CBB15.3@9730.4,4101.7 9736.3,4107.6 LED1$CBB15.1@9736.3,4178.3
$1I111\$1N389: LED2$CBB15.1 Q1$CBB15.3 | length 79.1
  Top Layer w7.9: Q1$CBB15.3@9851.8,4101.7 9857.8,4107.6 LED2$CBB15.1@9857.8,4178.3
$1I111\$1N391: LED2$CBB15.2 R10$CBB15.1 | length 55.1
  Top Layer w7.9: R10$CBB15.1@9920.3,4233.3 9920.7,4232.9 LED2$CBB15.2@9920.7,4178.4
$1I111\$1N397: LED3$CBB15.1 Q3$CBB15.3 | length 79
  Top Layer w7.9: Q3$CBB15.3@9973.3,4101.7 9979.2,4107.6 LED3$CBB15.1@9979.2,4178.3
$1I111\$1N398: LED4$CBB15.1 Q2$CBB15.3 | length 79
  Top Layer w7.9: Q2$CBB15.3@10094.8,4101.7 10100.7,4107.6 LED4$CBB15.1@10100.7,4178.3
$1I111\$1N401: LED3$CBB15.2 R12$CBB15.1 | length 55.1
  Top Layer w7.9: R12$CBB15.1@10041.8,4233.3 10042.2,4232.9 LED3$CBB15.2@10042.2,4178.4
$1I111\$1N402: LED4$CBB15.2 R11$CBB15.1 | length 55
  Top Layer w7.9: R11$CBB15.1@10163.3,4233.3 10163.6,4232.9 LED4$CBB15.2@10163.6,4178.4
$1I111\$1N405: LED5$CBB15.1 Q6$CBB15.3 | length 79
  Top Layer w7.9: Q6$CBB15.3@10216.2,4101.7 10222.1,4107.6 LED5$CBB15.1@10222.1,4178.3
$1I111\$1N406: LED6$CBB15.1 Q4$CBB15.3 | length 79
  Top Layer w7.9: Q4$CBB15.3@10337.7,4101.7 10343.6,4107.6 LED6$CBB15.1@10343.6,4178.3
$1I111\$1N409: LED5$CBB15.2 R15$CBB15.1 | length 55.1
  Top Layer w7.9: R15$CBB15.1@10284.7,4233.3 10285.1,4232.9 LED5$CBB15.2@10285.1,4178.4
$1I111\$1N410: LED6$CBB15.2 R14$CBB15.1 | length 55.1
  Top Layer w7.9: R14$CBB15.1@10406.2,4233.3 10406.6,4232.9 LED6$CBB15.2@10406.6,4178.4
$1I111\$1N424: LED7$CBB15.1 Q11$CBB15.3 | length 79.1
  Top Layer w7.9: Q11$CBB15.3@9001.9,4101.7 9007.9,4107.6 LED7$CBB15.1@9007.9,4178.3
$1I111\$1N425: LED9$CBB15.1 Q9$CBB15.3 | length 79.1
  Top Layer w7.9: Q9$CBB15.3@9244.8,4101.7 9250.8,4107.6 LED9$CBB15.1@9250.8,4178.3
$1I111\$1N426: LED11$CBB15.1 Q12$CBB15.3 | length 79
  Top Layer w7.9: Q12$CBB15.3@9487.5,4101.7 9493.4,4107.6 LED11$CBB15.1@9493.4,4178.3
$1I111\$1N427: LED10$CBB15.1 Q8$CBB15.3 | length 79
  Top Layer w7.9: Q8$CBB15.3@9366.3,4101.7 9372.2,4107.6 LED10$CBB15.1@9372.2,4178.3
$1I111\$1N428: LED8$CBB15.1 Q7$CBB15.3 | length 79
  Top Layer w7.9: Q7$CBB15.3@9123.4,4101.7 9129.3,4107.6 LED8$CBB15.1@9129.3,4178.3
$1I111\$1N429: LED12$CBB15.1 Q10$CBB15.3 | length 79.1
  Top Layer w7.9: Q10$CBB15.3@9608.9,4101.7 9614.9,4107.6 LED12$CBB15.1@9614.9,4178.3
$1I111\$1N436: LED7$CBB15.2 R22$CBB15.1 | length 55.1
  Top Layer w7.9: R22$CBB15.1@9070.4,4233.3 9070.8,4232.9 LED7$CBB15.2@9070.8,4178.4
$1I111\$1N437: LED12$CBB15.2 R19$CBB15.1 | length 55.1
  Top Layer w7.9: R19$CBB15.1@9677.4,4233.3 9677.8,4232.9 LED12$CBB15.2@9677.8,4178.4
$1I111\$1N438: LED11$CBB15.2 R21$CBB15.1 | length 55
  Top Layer w7.9: R21$CBB15.1@9556,4233.3 9556.3,4232.9 LED11$CBB15.2@9556.3,4178.4
$1I111\$1N439: LED8$CBB15.2 R16$CBB15.1 | length 55.1
  Top Layer w7.9: R16$CBB15.1@9191.9,4233.3 9192.3,4232.9 LED8$CBB15.2@9192.3,4178.4
$1I111\$1N440: LED10$CBB15.2 R17$CBB15.1 | length 55.1
  Top Layer w7.9: R17$CBB15.1@9434.8,4233.3 9435.2,4232.9 LED10$CBB15.2@9435.2,4178.4
$1I111\$1N441: LED9$CBB15.2 R18$CBB15.1 | length 55.1
  Top Layer w7.9: R18$CBB15.1@9313.3,4233.3 9313.7,4232.9 LED9$CBB15.2@9313.7,4178.4
$1I111\COLTIA1: R1$CBB15.2 R87$CBB15.1 U1$CBB15.1 | length 730.1
  Top Layer w7.9: R1$CBB15.2@7607.9,3867.5 7647.2,3867.5 v1(7655.1,3875.4) ; v1(7787.6,4252.9) 7965,4252.9 R87$CBB15.1@7967.1,4250.8 8021.4,4250.8 U1$CBB15.1@8030.3,4259.7
  Inner4 w7.9: v1(7655.1,3875.4) 7721.3,3941.7 7721.3,4186.6 v1(7787.6,4252.9)
$1I111\COLTIA2: R5$CBB15.2 R91$CBB15.1 U1$CBB15.7 | length 391.5
  Top Layer w7.9: R5$CBB15.2@7752.9,3867.5 7896.1,3867.5 7906.1,3877.4 7970.5,3877.4 7978.3,3885.3 7978.3,3925.6 7963.3,3940.6 R91$CBB15.1@7963.3,3966.7 ; R91$CBB15.1@7962.1,3966.7 R91$CBB15.1@7963.3,3966.7 ; U1$CBB15.7@8030.3,3959.7 8023.3,3966.7 R91$CBB15.1@7963.3,3966.7
$1I111\COLTIA3: R9$CBB15.2 R95$CBB15.1 U1$CBB15.8 | length 961.4
  Top Layer w7.9: R9$CBB15.2@7707.9,4296.6 7707.9,4321.8 7715.3,4329.2 8086.8,4329.2 8155,4260.9 8155,3977.8 8173.1,3959.7 U1$CBB15.8@8248.4,3959.7 8305.1,3959.7 R95$CBB15.1@8317.1,3971.7
$1I111\COLTIA4: R13$CBB15.2 R99$CBB15.1 U1$CBB15.14 | length 789.1
  Top Layer w7.9: R13$CBB15.2@7607.9,4296.6 7612.9,4301.6 v1(7612.9,4333.2) ; U1$CBB15.14@8248.4,4259.7 8308.2,4259.7 R99$CBB15.1@8317.1,4250.8
  Inner2 w7.9: v1(7612.9,4333.2) 7618.9,4327.2 7673.1,4327.2 7719.3,4281 7821.7,4281 7857.9,4244.8 8232.6,4244.8 v1(8247.9,4260.2)
$1I111\COLTIA7: R103$CBB15.1 R109$CBB15.2 U2$CBB15.1 | length 876
  Top Layer w7.9: R103$CBB15.1@8522.1,4250.8 8587.8,4250.8 U2$CBB15.1@8595.3,4258.3 8657.6,4258.3 8717.5,4198.4 8717.5,4197.3 8729.3,4185.5 8729.3,4161.6 8731,4159.9 8731,4145.1 8729.3,4143.4 8729.3,3935.6 8745.4,3919.6 8936.1,3919.6 8952.2,3935.6 8952.2,4044.1 8937.5,4058.7 R109$CBB15.2@8919.2,4058.7
$1I111\COLTIA8: R107$CBB15.1 R113$CBB15.2 U2$CBB15.7 | length 623.4
  Top Layer w7.9: R107$CBB15.1@8527.1,3966.7 8586.9,3966.7 U2$CBB15.7@8595.3,3958.3 8653.6,3958.3 8713.2,4018 v1(8713.2,4152.5) ; R113$CBB15.2@8919.2,4158.7 8951.9,4158.7 v1(8952.2,4158.5)
  Inner2 w7.9: v1(8713.2,4152.5) 8719.3,4158.5 v1(8952.2,4158.5)
$1I111\COMP_IN1: H1$CBB8.2 R2$CBB15.2 R20$CBB15.2 | length 3510.1
  Top Layer w7.9: v1(7420.2,3865.4) 7560.8,3865.4 R2$CBB15.2@7562.9,3867.5 ; v1(9760.9,3892) 9760.9,4158.5 9761.3,4158.9 9761.3,4197.8 9760.9,4198.1 9760.9,4229.5 R20$CBB15.2@9764.8,4233.3
  Inner2 w7.9: v1(7420.2,3865.4) 7432.2,3853.3 7787.6,3853.3 7809.7,3875.4 7927.1,3875.4 7928.8,3877.1 7943.6,3877.1 7945.3,3875.4 9744.3,3875.4 v1(9760.9,3892)
  Inner4 w7.9: v1@7420.2,3865.3 7410.1,3875.4 7410.1,4319.1 7396.1,4333.2 7396.1,4429.6 7452.1,4485.6 H1$CBB8.2@7452.1,4492.2
$1I111\COMP_IN2: H1$CBB10.2 R3$CBB15.2 R10$CBB15.2 | length 3029.3
  Top Layer w7.9: R3$CBB15.2@7707.9,3867.5 7709.3,3866.1 7709.3,3841.3 7717.3,3833.2 7910.1,3833.2 v1(7936.2,3859.3) ; v1(9885.8,4301.1) 9886.6,4300.3 R10$CBB15.2@9886.6,4233.3
  Inner2 w7.9: v1(7904.1,4275) 7910.1,4281 8215.3,4281 8235.4,4301.1 8432,4301.1 8432.3,4300.8 8439.2,4300.8 8445.5,4294.5 8451.8,4294.5 8454.1,4292.2 9503.4,4292.2 9509.3,4298.1 9875.9,4298.1 9878.9,4301.1 v1(9885.8,4301.1)
  Inner4 w7.9: v1(7904.1,4275) 7933.4,4275 7934.2,4275.7 ; v1(7936.2,3859.3) 7936.2,4174.6 7934.2,4176.6 7934.2,4275.7 ; H1$CBB10.2@7960.8,4492.2 7912.1,4443.4 7912.1,4339.2 7934.2,4317.1 7934.2,4275.7
$1I111\COMP_IN3: H1$CBB11.2 R4$CBB15.2 R12$CBB15.2 | length 2532.2
  Top Layer w7.9: R4$CBB15.2@7752.9,4296.6 7947.7,4296.6 v1(7954.3,4303.1) ; v1(10001.8,4295.6) 10001.8,4239.2 R12$CBB15.2@10007.7,4233.3
  Inner2 w7.9: v1(7954.3,4303.1) 8219.2,4303.1 8235.2,4319.1 v1(8426.1,4319.1) 8439.1,4319.1 8450.9,4307.4 8457.2,4307.4 8459.4,4305.1 9498.1,4305.1 9504,4311 9870.6,4311 9878.5,4318.9 9893.2,4318.9 9907,4305.1 9994.3,4305.1 v1@10000.3,4299.1
  Inner4 w7.9: v1(8426.1,4319.1) 8426.1,4447.6 8469.5,4491.1 H1$CBB11.2@8469.5,4492.2
$1I111\COMP_IN4: H1$CBB12.2 R6$CBB15.2 R11$CBB15.2 | length 2915.2
  Top Layer w7.9: R6$CBB15.2@7562.9,4296.6 7562.9,4329.4 v1(7572.8,4339.2) ; v1(8857.1,4353.3) 8857.1,4371.1 H1$CBB12.2@8978.2,4492.2 ; v1(10119.3,4337.7) 10119.3,4243.2 R11$CBB15.2@10129.2,4233.3
  Inner2 w7.9: v1(7572.8,4339.2) 7586.8,4353.3 7922.6,4353.3 7923.7,4352.2 8506.7,4352.2 8507.7,4353.3 v1(8857.1,4353.3) ; v1@8851.9,4348 v1(8857.1,4353.3) ; v1(10119.3,4337.7) 10115.8,4341.2 9907.2,4341.2 9903.9,4344.6 9867.8,4344.6 9864.4,4341.2 8869.8,4341.2 8857.1,4353.9 v1(8857.1,4353.3)
$1I111\COMP_IN5: H1$CBB13.2 R7$CBB15.2 R15$CBB15.2 | length 2191.4
  Top Layer w7.9: v1(8918,4020) R7$CBB15.2@8919.2,4018.8 ; v1(10212.6,4233.3) R15$CBB15.2@10250.6,4233.3
  Inner2 w7.9: v1(8908,4542) 9004.4,4542 9032.5,4513.9 9163,4513.9 9184.7,4492.2 H1$CBB13.2@9486.9,4492.2 9902.2,4492.2 9950.1,4540 10156.9,4540 v1(10179.2,4517.7)
  Inner4 w7.9: v1(8908,4542) 8902,4536 8902,4118.3 8900.2,4116.6 8900.2,4101.9 8902,4100.1 8902,4036 v1(8918,4020) ; v1(10179.2,4517.7) 10212.6,4484.2 v1(10212.6,4233.3)
$1I111\COMP_IN6: H1$CBB14.2 R8$CBB15.2 R14$CBB15.2 | length 1864.5
  Top Layer w7.9: R8$CBB15.2@8919.2,4198.7 8948.1,4227.7 8948.1,4240.8 8976.3,4268.9 9030.5,4268.9 9100.7,4339.2 9100.7,4381.4 v1(9106.8,4387.4) ; R14$CBB15.2@10372.1,4233.3 10372.2,4233.5 v1(10372.2,4267.5)
  Inner2 w7.9: v1(9106.8,4387.4) 9165,4445.6 9949.1,4445.6 H1$CBB14.2@9995.6,4492.2 9997.6,4490.2 v1(10371.7,4490.2)
  Inner4 w7.9: v1(10371.7,4490.2) 10371.7,4268 v1(10372.2,4267.5)
$1I111\SUM_1: R6$CBB21.2 U3$CBB15.1 U3$CBB15.2 | length 1330.2
  Top Layer w4.7: R6$CBB21.2@7192.1,4940.8 7260.3,4940.8 v1(7261.5,4939.6) ; v1(7261.5,3974.8) U3$CBB15.1@7507,3974.8
  Top Layer w7.9: U3$CBB15.1@7507,3974.8 U3$CBB15.2@7557,3974.8
  Inner4 w4.7: v1(7261.5,3974.8) v1(7261.5,4939.6)
$1I111\SUM_2: R1$CBB21.2 U3$CBB15.6 U3$CBB15.7 | length 1368.2
  Top Layer w4.7: R1$CBB21.2@7192.1,4740.8 v1(7307.7,4740.8) ; v1(7309.7,4072.2) 7737.4,4072.2 7757,4052.6 U3$CBB15.6@7757,3974.8
  Top Layer w7.9: U3$CBB15.6@7757,3974.8 U3$CBB15.7@7807,3974.8
  Inner4 w4.7: v1(7307.7,4740.8) 7309.7,4738.8 v1(7309.7,4072.2)
$1I111\SUM_3: R3$CBB21.2 U3$CBB15.8 U3$CBB15.9 | length 1120.5
  Top Layer w4.7: R3$CBB21.2@7192.1,4545.8 7257.8,4545.8 v1(7281.6,4521.9) ; v1(7285.6,4100.3) 7729.4,4100.3 7757,4127.9 U3$CBB15.9@7757,4192.9
  Top Layer w7.9: U3$CBB15.9@7757,4192.9 U3$CBB15.8@7807,4192.9
  Inner4 w4.7: v1(7281.6,4521.9) 7285.6,4517.9 v1(7285.6,4100.3)
$1I111\SUM_4: R2$CBB21.2 U3$CBB15.13 U3$CBB15.14 | length 428.2
  Top Layer w4.7: R2$CBB21.2@7192.1,4345.8 7234.9,4345.8 7387.8,4192.9 U3$CBB15.14@7507,4192.9
  Top Layer w7.9: U3$CBB15.14@7507,4192.9 U3$CBB15.13@7557,4192.9
$1I111\SUM_5: R5$CBB21.2 U2$CBB15.8 U2$CBB15.9 | length 1829.6
  Top Layer w4.7: R5$CBB21.2@7192.1,4145.8 7212,4145.8 7218.1,4139.7 7218.1,4046.8 v1(7213.3,4042)
  Top Layer w7.9: v1(8749.4,4013.9) 8755,4008.3 U2$CBB15.9@8813.4,4008.3 U2$CBB15.8@8813.4,3958.3
  Inner2 w4.7: v1(7213.3,4042) 7851,4042 7851.2,4042.2 7864.6,4042.2 7866.8,4040 7875.9,4040 7888,4028 8398,4028 8419.9,4049.9 8420.8,4049.9 8430.3,4059.4 8430.3,4060.3 8442.2,4072.2 8578.7,4072.2 8636.9,4013.9 v1(8749.4,4013.9)
$1I111\SUM_6: R4$CBB21.2 U2$CBB15.13 U2$CBB15.14 | length 1939.8
  Top Layer w4.7: R4$CBB21.2@7192.1,3940.8 7192.1,3976.7 7235.4,4020 v1(7235.4,4224.8)
  Top Layer w7.9: v1(8735.3,4204.7) 8738.9,4208.3 U2$CBB15.13@8813.4,4208.3 U2$CBB15.14@8813.4,4258.3
  Inner2 w4.7: v1(7235.4,4224.8) 7237.4,4222.8 8717.2,4222.8 v1(8735.3,4204.7)
$1I229\$1N1: Q3$CBB8.1 Q3$CBB8.3 Q4$CBB8.2 | length 210.9
  Bottom Layer w7.9: Q3$CBB8.1@7546.1,4449.8 7571.7,4475.4 Q3$CBB8.3@7617.8,4475.4 7617.8,4461.8 7629.8,4449.8 Q4$CBB8.2@7727.8,4449.8
$1I229\$1N2: Q1$CBB8.2 Q4$CBB8.1 Q4$CBB8.3 R10$CBB8.2 | length 249.9
  Bottom Layer w7.9: Q4$CBB8.3@7656.1,4475.4 7679.7,4475.4 7705.3,4501 Q4$CBB8.1@7727.8,4501 Q1$CBB8.2@7727.8,4539.8 7745.6,4539.8 7758.4,4552.6 7758.4,4610.9 R10$CBB8.2@7734,4635.4
$1I229\$1N3: Q2$CBB8.1 Q2$CBB8.3 Q3$CBB8.2 R2$CBB8.1 R9$CBB8.1 U1$CBB8.6 | length 439.8
  Bottom Layer w7.9: Q3$CBB8.2@7546.1,4501 Q2$CBB8.1@7546.1,4539.8 7592.2,4539.8 Q2$CBB8.3@7617.8,4565.4 7617.8,4593.5 7621.9,4597.6 7621.9,4632.4 R2$CBB8.1@7624.9,4635.4 ; R9$CBB8.1@7584,4635.4 R2$CBB8.1@7624.9,4635.4 ; U1$CBB8.6@7755.9,4742.6 7681.9,4742.6 7624.9,4685.6 R2$CBB8.1@7624.9,4635.4
$1I229\$1N4: Q1$CBB8.1 Q1$CBB8.3 Q2$CBB8.2 | length 362.2
  Bottom Layer w7.9: Q2$CBB8.2@7546.1,4591 7526.9,4571.8 7526.9,4552.9 7525.4,4551.4 7525.4,4489.4 7530.6,4484.2 7540.4,4484.2 7541.9,4482.6 7560.1,4482.6 7566.8,4489.4 7566.8,4492.6 7616.9,4542.6 7633.4,4542.6 Q1$CBB8.3@7656.1,4565.4 7681.7,4591 Q1$CBB8.1@7727.8,4591
$1I229\$1N10: R2$CBB8.2 R10$CBB8.1 R15$CBB8.1 U1$CBB8.7 | length 288.3
  Bottom Layer w7.9: R2$CBB8.2@7659,4635.4 R10$CBB8.1@7699.9,4635.4 7699.9,4675.6 7716.9,4692.6 7755.9,4692.6 7804,4692.6 R15$CBB8.1@7871.9,4760.6
$1I229\$1N13: R4$CBB8.1 R5$CBB8.2 U1$CBB8.3 | length 207.5
  Bottom Layer w7.9: U1$CBB8.3@7755.9,4892.6 7776.9,4892.6 7806.9,4922.6 7806.9,4932.6 7816.9,4942.6 7861.9,4942.6 7867.5,4937.1 7867.5,4921.2 R5$CBB8.2@7864,4917.6 7864,4900.6 7871.9,4892.6 R4$CBB8.1@7871.9,4874.7
$1I229\$1N15: R3$CBB8.1 R6$CBB8.1 U1$CBB8.9 | length 114.3
  Bottom Layer w7.9: R6$CBB8.1@7426.9,4734.7 R3$CBB8.1@7466.9,4734.7 7489,4734.7 7496.9,4742.6 U1$CBB8.9@7537.9,4742.6
$1I229\$1N16: R7$CBB8.1 R8$CBB8.1 U1$CBB8.10 | length 197.4
  Bottom Layer w7.9: R7$CBB8.1@7387.1,4719.2 7387.1,4742.6 7402.1,4757.6 7416.9,4757.6 7454.9,4795.6 R8$CBB8.1@7466.9,4795.6 7469.9,4792.6 U1$CBB8.10@7537.9,4792.6
$1I229\$1N22: R13$CBB8.1 R15$CBB8.2 U1$CBB8.13 | length 674.1
  Bottom Layer w7.9: R13$CBB8.1@7466.9,4950.6 7484,4950.6 7491.9,4942.6 U1$CBB8.13@7537.9,4942.6 7606.9,4942.6 7703,5038.7 7805.8,5038.7 7896.9,4947.6 7896.9,4819.7 R15$CBB8.2@7871.9,4794.7
$1I229\SIGM: H1$CBB8.1 R13$CBB8.2 U1$CBB8.14 | length 829
  Inner4 w7.9: H1$CBB8.1@7452.1,4392.2 7507.1,4447.2 7507.1,4877.2 v1(7597.1,4967.2)
  Bottom Layer w7.9: U1$CBB8.14@7537.9,4992.6 7496.9,4992.6 7496.4,4992.2 ; v1(7597.1,4967.2) 7572.1,4992.2 7496.4,4992.2 ; R13$CBB8.2@7469.9,4987.6 R13$CBB8.2@7466.9,4984.7 R13$CBB8.2@7469.9,4987.6 ; R13$CBB8.2@7469.9,4987.6 7475.4,4982.2 7486.4,4982.2 7496.4,4992.2
$1I229\SIGM_BYPAS: H1$CBB8.3 R3$CBB8.2 R9$CBB8.2 U1$CBB8.8 | length 253.8
  Bottom Layer w7.9: H1$CBB8.3@7452.1,4592.2 7495.4,4635.4 R9$CBB8.2@7549.9,4635.4 7549.9,4680.7 U1$CBB8.8@7537.9,4692.6 7496.9,4692.6 7486.9,4702.6 7469,4702.6 R3$CBB8.2@7466.9,4700.6
$1I229\VREF_OUT: R8$CBB8.2 R148.1 U1$CBB8.1 U1$CBB8.2 U1$CBB8.5 U1$CBB8.12 | length 840.2
  Top Layer w11.8: v1(7380,4793) R148.1@7380,4830.2
  Bottom Layer w7.9: R8$CBB8.2@7466.9,4829.7 7466.9,4872.6 7486.9,4892.6 ; U1$CBB8.12@7537.9,4892.6 7602.1,4892.6 ; U1$CBB8.2@7755.9,4942.6 U1$CBB8.1@7755.9,4992.6 ; U1$CBB8.5@7756,4792.6 7676.7,4792.6 7632.1,4837.2 7612.1,4837.2 7601.2,4848.1 7601.2,4891.7 7602.1,4892.6 ; U1$CBB8.2@7756,4942.6 7712.6,4942.6 7662.6,4892.6 7602.1,4892.6
  Bottom Layer w11.8: v1(7380,4793) 7380,4829.1 7443.5,4892.6 7486.9,4892.6 U1$CBB8.12@7537.9,4892.6
$4I2\$1I143359\1.0V_RTL8211: C46.1 C121$CBB22/CBB2.1 C127$CBB22/CBB2.1 C128$CBB22/CBB2.1 C315.1 C316.1 L12.2 U98$CBB22/CBB2.3 U98$CBB22/CBB2.8 U98$CBB22/CBB2.21 U98$CBB22/CBB2.38 | length 1478.7
  Top Layer w4.7: v1(4424.4,4204.7) 4425.3,4203.8 U98$CBB22/CBB2.38@4459.5,4203.8 ; v1(4517.4,4110.3) 4518.5,4111.4 U98$CBB22/CBB2.3@4518.5,4144.8
  Top Layer w7.9: U98$CBB22/CBB2.8@4597.3,4144.8 4597.3,4108.6 v1(4597.6,4108.3) ; U98$CBB22/CBB2.21@4628.8,4341.6 4644,4356.8 v1(4644,4364.4)
  Top Layer w15.7: L12.2@4389.1,4696.3 4404.3,4681 C46.1@4404.3,4508.2 C121$CBB22/CBB2.1@4404.3,4463.2 4404.3,4427.7 v1(4404.5,4427.6)
  Inner2 w15.7: v1(4404.5,4427.6) 4404.5,4401.3 4474.6,4331.2 4610.8,4331.2 v1(4644,4364.4) ; v1(4424.4,4204.7) 4417.3,4211.8 4395.4,4211.8 4384.3,4200.7 4384.3,4160.5 4434.4,4110.3 v1(4517.4,4110.3)
  Inner2 w19.7: v1(4517.4,4110.3) 4519.4,4108.3 v1(4597.6,4108.3)
  Inner4 w19.7: v1(4597.6,4108.3) 4633.2,4143.9 4633.2,4343.2 4644,4354 v1(4644,4364.4)
  Bottom Layer w15.7: v1(4517.4,4110.3) 4517.9,4110.8 C316.1@4517.9,4151.7 ; v1(4597.6,4108.3) 4597.6,4151.5 C315.1@4597.9,4151.7 ; C127$CBB22/CBB2.1@4617.9,4334.6 C128$CBB22/CBB2.1@4657.9,4334.6 4644,4348.5 v1(4644,4364.4)
$4I2\$1I143359\$1N116049: L8.P1 R45.2 | length 128.8
  Top Layer w4.7: L8.P1@4202.9,3836.2 4202.9,3964.1 R45.2@4203.5,3964.8
$4I2\$1I143359\$1N116207: C56$CBB22/CBB2.1 R48.1 U98$CBB22/CBB2.37 X4$CBB22/CBB2.1 | length 410.2
  Top Layer w4.7: C56$CBB22/CBB2.1@4154.9,4086.4 4152.9,4088.4 v1(4152.9,4165.9) 4187.7,4200.7 4372.2,4200.7 4391.1,4219.6 4416.4,4219.6 4417.7,4220.9 4431.1,4220.9 4432.4,4219.6 U98$CBB22/CBB2.37@4459.5,4219.6
$4I2\$1I143359\$1N117370: R46.1 U98$CBB22/CBB2.39 | length 96.6
  Top Layer w4.7: v1(4406.3,4184.6) 4409.8,4188.1 U98$CBB22/CBB2.39@4459.5,4188.1
  Bottom Layer w4.7: R46.1@4364.9,4183.2 4404.9,4183.2 v1(4406.3,4184.6)
$4I2\$1I143359\$1N117429: R47.1 U98$CBB22/CBB2.35 | length 953
  Top Layer w4.7: v1(4390.3,4254.9) 4406.3,4254.9 4410.1,4251.1 U98$CBB22/CBB2.35@4459.5,4251.1
  Inner2 w4.7: v1(4392.3,4865.3) 4536.9,4865.3 v1(4544.9,4857.2)
  Inner4 w4.7: v1(4390.3,4254.9) 4390.3,4270.1 4390.1,4270.2 4390.1,4283.7 4390.3,4283.8 4390.3,4418.7 4388.1,4420.8 4388.1,4434.3 4390.3,4436.4 4390.3,4863.3 v1(4392.3,4865.3) ; v1(4534.8,4799) 4544.9,4809.1 v1(4544.9,4857.2)
  Bottom Layer w4.7: R47.1@4533.9,4748.8 4534.8,4749.8 v1(4534.8,4799)
$4I2\$1I143359\$1N124065: L8.12 R50.1 R164$CBB22/CBB2.2 | length 1360.4
  Inner4 w4.7: v1(4235.7,4487.8) 4235.7,4078.2 4257.8,4056.1 4257.8,3813.1 4201.5,3756.9 4201.5,3678.6 4225.6,3654.5 4225.6,3618.4 4291.9,3552.1 4291.9,3393.5 4267.9,3369.5 L8.12@4267.9,3291
  Bottom Layer w7.9: R50.1@4192.6,4445.2 4193,4445.6 R164$CBB22/CBB2.2@4232.7,4445.6 4235.7,4448.6 v1(4235.7,4487.8)
$4I2\$1I143359\$1N124116: L8.11 R49.1 | length 794.2
  Top Layer w4.7: R49.1@4159.4,3964.8 4159.4,3885.4 4145.3,3871.4 4145.3,3769 4205.6,3708.7 4205.6,3632.4 4293.9,3544.1 4293.9,3415.6 4169.3,3291 L8.11@4167.9,3291
$4I2\$1I143359\$1N125378: L8.14 R166$CBB22/CBB2.1 | length 1289.6
  Inner4 w4.7: v1(4406.3,4277) 4406.3,4261.8 4406.5,4261.6 4406.5,4248.2 4406.3,4248 4406.3,4238.8 4388.3,4220.7 4388.3,3874.2 4365.5,3851.5 4365.5,3776.2 4390.2,3751.5 4390.2,3720.5 4388.3,3718.6 4388.3,3471.8 4494.7,3365.4 4613.5,3365.4 L8.14@4687.9,3291
  Bottom Layer w4.7: R166$CBB22/CBB2.1@4341.1,4317.1 4366.2,4317.1 v1(4406.3,4277)
$4I2\$1I143359\$1N125523: ETH-LED1.2 R168$CBB22/CBB2.1 | length 61.8
  Top Layer w4.7: ETH-LED1.2@4143.5,4431.6 4160.5,4448.6 R168$CBB22/CBB2.1@4198.3,4448.6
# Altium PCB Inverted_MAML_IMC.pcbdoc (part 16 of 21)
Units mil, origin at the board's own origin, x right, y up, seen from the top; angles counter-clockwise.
Board outline 7677.1 x 6771.6 mil, 6 copper layers (Top Layer, Inner1, Inner2, Inner3, Inner4, Bottom Layer), stack 60.7 mil thick; 2732 components, 1531 nets, 7765 pads, 3699 vias.

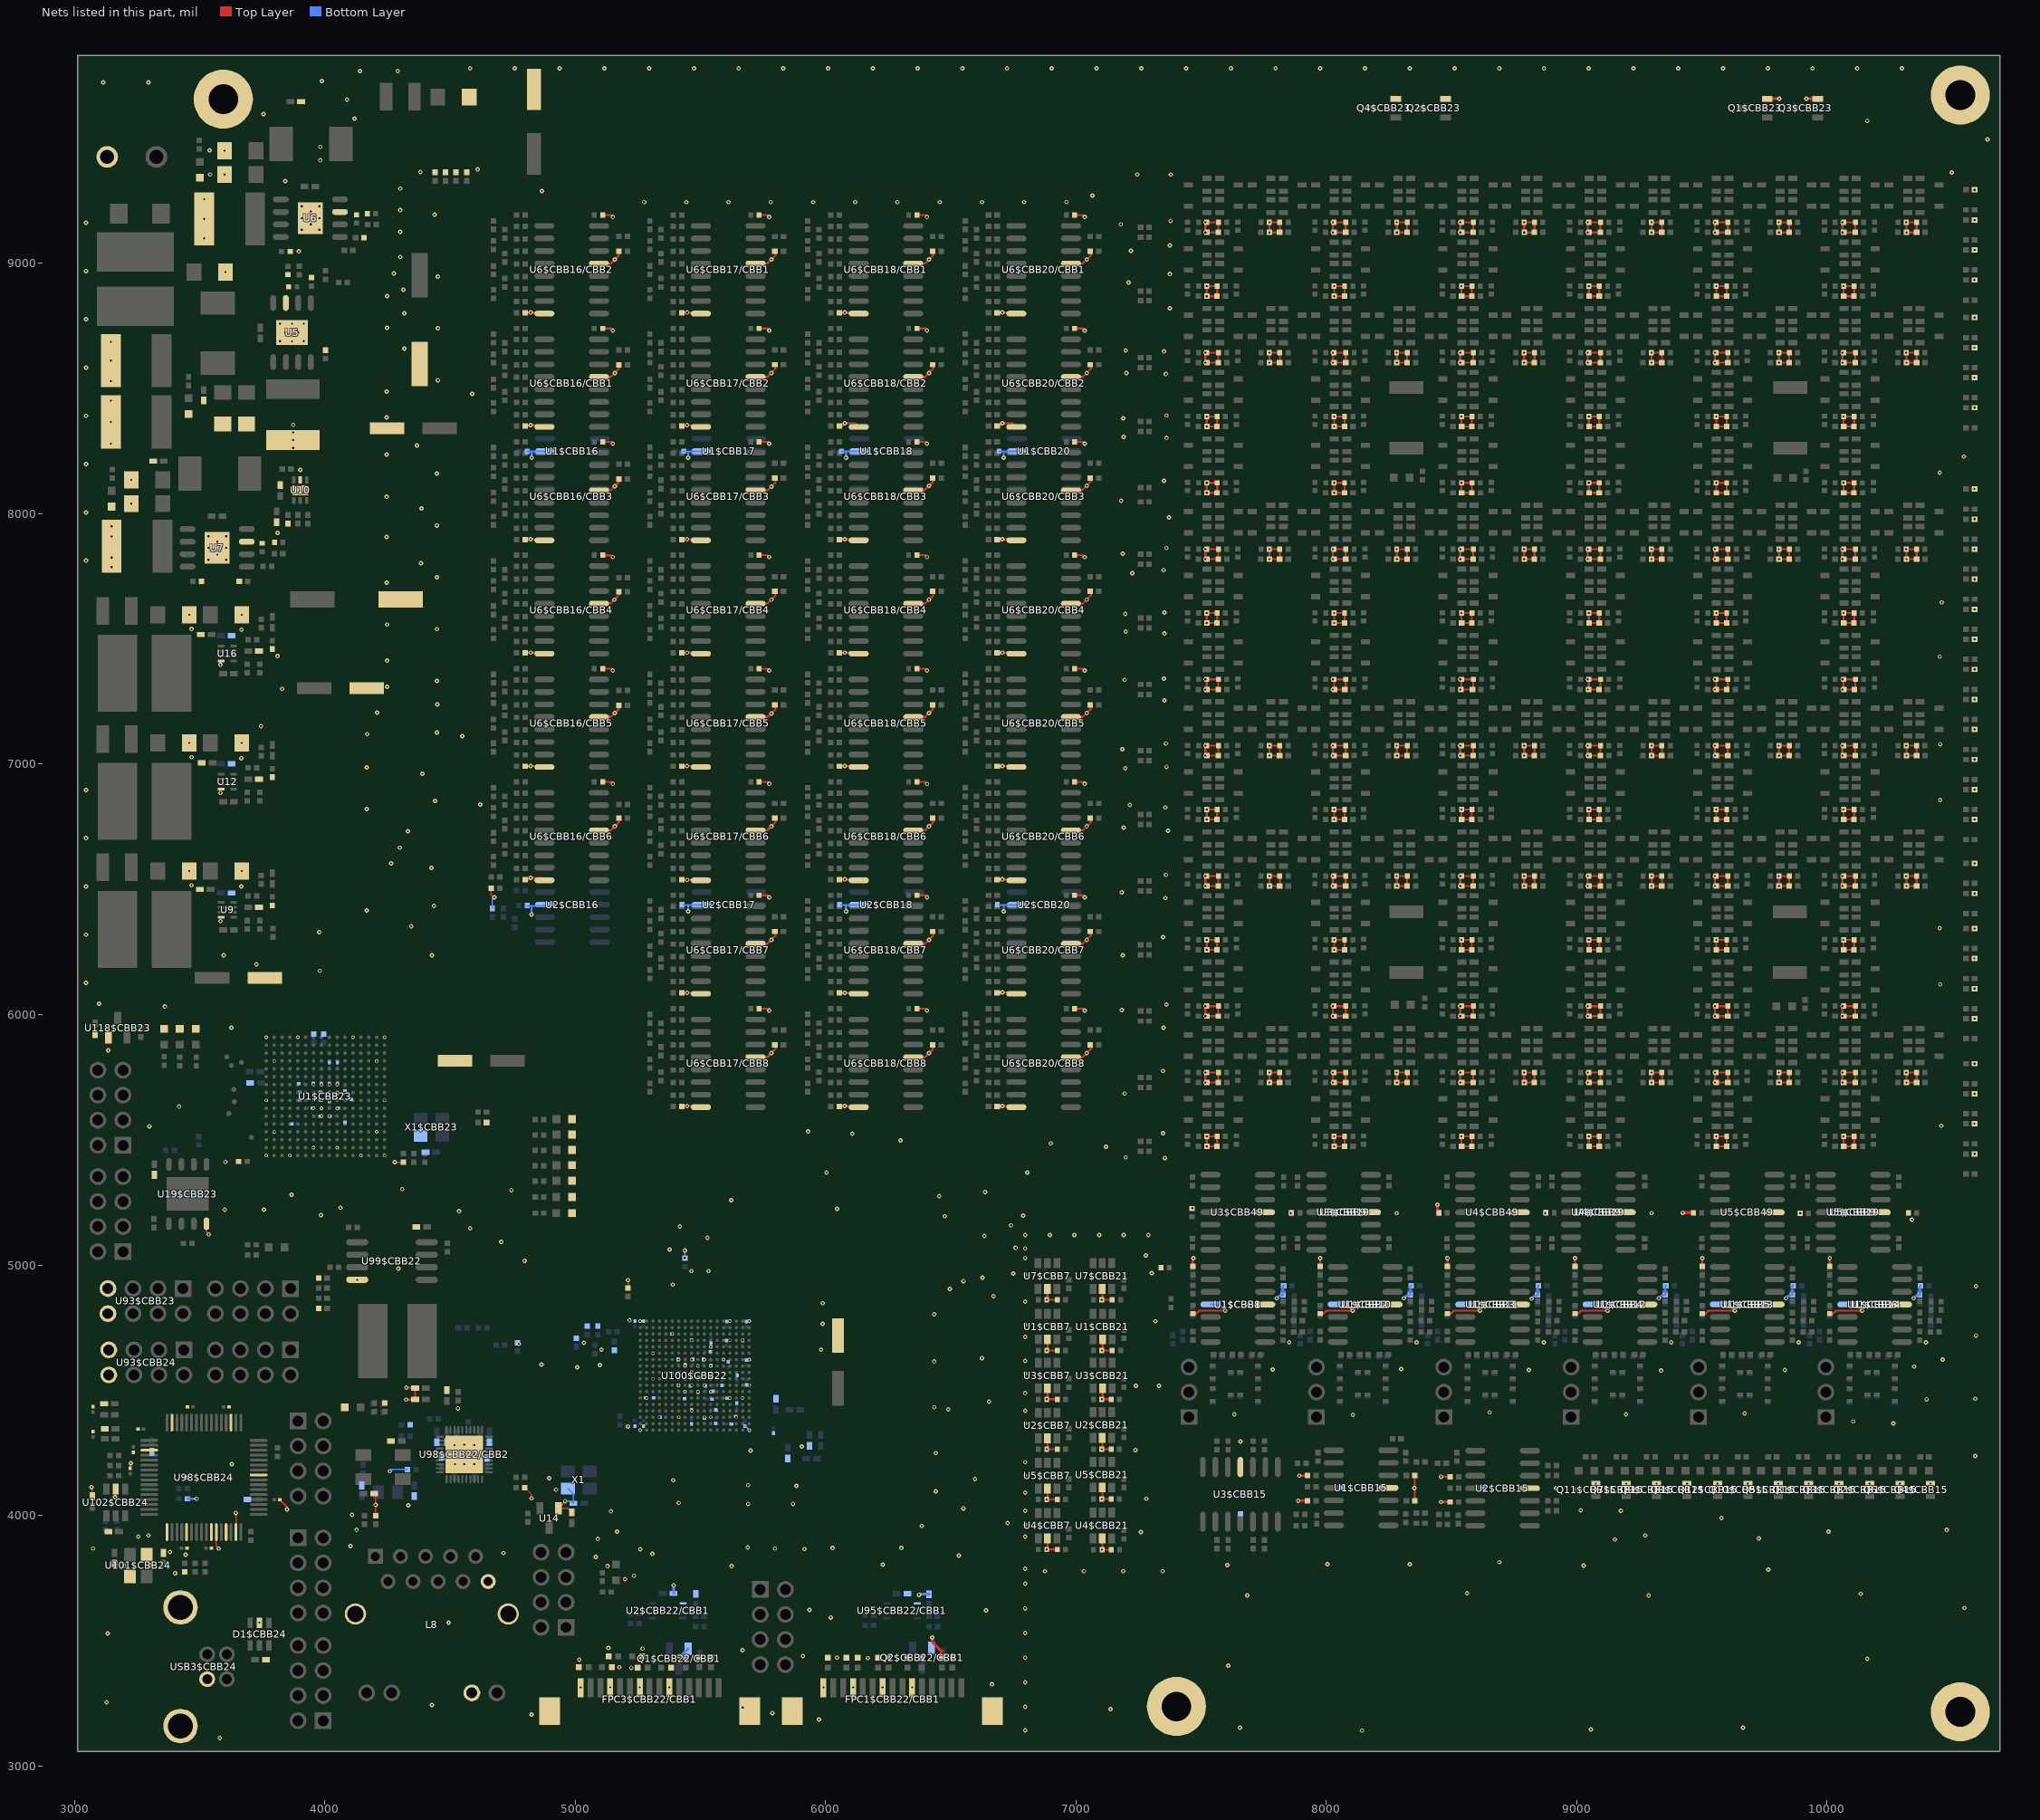
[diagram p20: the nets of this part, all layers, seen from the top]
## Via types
v1: diameter 17.7, hole 7.9, Top Layer to Bottom Layer, 3367 vias
v2: diameter 13.8, hole 7.9, Top Layer to Bottom Layer, 287 vias
v3: diameter 23.6, hole 11.8, Top Layer to Bottom Layer, 45 vias

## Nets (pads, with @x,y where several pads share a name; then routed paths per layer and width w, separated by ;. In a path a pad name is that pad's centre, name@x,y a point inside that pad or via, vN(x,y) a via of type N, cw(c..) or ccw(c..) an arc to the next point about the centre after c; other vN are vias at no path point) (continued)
GND: C1$CBB7.1 C1$CBB9/CBB1.1 C1$CBB9/CBB2.1 C1$CBB9/CBB3.1 C1$CBB9/CBB4.1 C1$CBB9/CBB5.1 C1$CBB9/CBB6.1 C1$CBB9/CBB7.1 C1$CBB9/CBB8.1 C1$CBB9/CBB9.1 C1$CBB9/CBB10.1 C1$CBB9/CBB11.1 C1$CBB9/CBB12.1 C1$CBB9/CBB13.1 C1$CBB9/CBB14.1 C1$CBB9/CBB15.1 C1$CBB9/CBB16.1 C1$CBB9/CBB17.1 C1$CBB9/CBB18.1 C1$CBB9/CBB19.1 C1$CBB9/CBB20.1 C1$CBB9/CBB21.1 C1$CBB9/CBB22.1 C1$CBB9/CBB23.1 C1$CBB9/CBB24.1 C1$CBB9/CBB25.1 C1$CBB9/CBB26.1 C1$CBB9/CBB27.1 C1$CBB9/CBB28.1 C1$CBB9/CBB29.1 C1$CBB9/CBB30.1 C1$CBB9/CBB31.1 C1$CBB9/CBB32.1 C1$CBB9/CBB33.1 C1$CBB9/CBB34.1 C1$CBB9/CBB35.1 C1$CBB9/CBB36.1 C1$CBB9/CBB37.1 C1$CBB9/CBB38.1 C1$CBB9/CBB39.1 C1$CBB9/CBB40.1 C1$CBB9/CBB41.1 C1$CBB9/CBB42.1 C1$CBB16.1 C1$CBB17.1 C1$CBB18.1 C1$CBB19/CBB1.1 C1$CBB19/CBB2.1 C1$CBB19/CBB3.1 C1$CBB19/CBB4.1 C1$CBB19/CBB5.1 C1$CBB19/CBB6.1 C1$CBB19/CBB7.1 C1$CBB19/CBB8.1 C1$CBB19/CBB9.1 C1$CBB19/CBB10.1 C1$CBB19/CBB11.1 C1$CBB19/CBB12.1 C1$CBB19/CBB13.1 C1$CBB19/CBB14.1 C1$CBB19/CBB15.1 C1$CBB19/CBB16.1 C1$CBB19/CBB17.1 C1$CBB19/CBB18.1 C1$CBB19/CBB19.1 C1$CBB19/CBB20.1 C1$CBB19/CBB21.1 C1$CBB19/CBB22.1 C1$CBB19/CBB23.1 C1$CBB19/CBB24.1 C1$CBB19/CBB25.1 C1$CBB19/CBB26.1 C1$CBB19/CBB27.1 C1$CBB19/CBB28.1 C1$CBB19/CBB29.1 C1$CBB19/CBB30.1 C1$CBB19/CBB31.1 C1$CBB19/CBB32.1 C1$CBB19/CBB33.1 C1$CBB19/CBB34.1 C1$CBB19/CBB35.1 C1$CBB19/CBB36.1 C1$CBB20.1 C1$CBB21.1 C1$CBB23.2 C1$CBB49/CBB1.1 C1$CBB49/CBB2.1 C1$CBB49/CBB3.1 C1$CBB49/CBB4.1 C1$CBB49/CBB5.1 C1$CBB49/CBB6.1 C1$CBB49/CBB7.1 C1$CBB49/CBB8.1 C1$CBB49/CBB9.1 C1$CBB49/CBB10.1 C1$CBB49/CBB11.1 C1$CBB49/CBB12.1 C1$CBB49/CBB13.1 C1$CBB49/CBB14.1 C1$CBB49/CBB15.1 C1$CBB49/CBB16.1 C1$CBB49/CBB17.1 C1$CBB49/CBB18.1 C1$CBB49/CBB19.1 C1$CBB49/CBB20.1 C1$CBB49/CBB21.1 C1$CBB49/CBB22.1 C1$CBB49/CBB23.1 C1$CBB49/CBB24.1 C1$CBB49/CBB25.1 C1$CBB49/CBB26.1 C1$CBB49/CBB27.1 C1$CBB49/CBB28.1 C1$CBB49/CBB29.1 C1$CBB49/CBB30.1 C1$CBB49/CBB31.1 C1$CBB49/CBB32.1 C1$CBB49/CBB33.1 C1$CBB49/CBB34.1 C1$CBB49/CBB35.1 C1$CBB49/CBB36.1 C1$CBB49/CBB37.1 C1$CBB49/CBB38.1 C1$CBB49/CBB39.1 C1$CBB49/CBB40.1 C1$CBB49/CBB41.1 C1$CBB49/CBB42.1 C1$CBB49/CBB43.1 C1$CBB49/CBB44.1 C1$CBB49/CBB45.1 C1$CBB49/CBB46.1 C1$CBB49/CBB47.1 C1$CBB49/CBB48.1 C1.1 C2$CBB7.1 C2$CBB15.1 C2$CBB21.1 C2$CBB23.2 C2.1 C3$CBB7.1 C3$CBB9/CBB1.1 C3$CBB9/CBB2.1 C3$CBB9/CBB3.1 C3$CBB9/CBB4.1 C3$CBB9/CBB5.1 C3$CBB9/CBB6.1 C3$CBB9/CBB7.1 C3$CBB9/CBB8.1 C3$CBB9/CBB9.1 C3$CBB9/CBB10.1 C3$CBB9/CBB11.1 C3$CBB9/CBB12.1 C3$CBB9/CBB13.1 C3$CBB9/CBB14.1 C3$CBB9/CBB15.1 C3$CBB9/CBB16.1 C3$CBB9/CBB17.1 C3$CBB9/CBB18.1 C3$CBB9/CBB19.1 C3$CBB9/CBB20.1 C3$CBB9/CBB21.1 C3$CBB9/CBB22.1 C3$CBB9/CBB23.1 C3$CBB9/CBB24.1 C3$CBB9/CBB25.1 C3$CBB9/CBB26.1 C3$CBB9/CBB27.1 C3$CBB9/CBB28.1 C3$CBB9/CBB29.1 C3$CBB9/CBB30.1 C3$CBB9/CBB31.1 C3$CBB9/CBB32.1 C3$CBB9/CBB33.1 C3$CBB9/CBB34.1 C3$CBB9/CBB35.1 C3$CBB9/CBB36.1 C3$CBB9/CBB37.1 C3$CBB9/CBB38.1 C3$CBB9/CBB39.1 C3$CBB9/CBB40.1 C3$CBB9/CBB41.1 C3$CBB9/CBB42.1 C3$CBB19/CBB1.1 C3$CBB19/CBB2.1 C3$CBB19/CBB3.1 C3$CBB19/CBB4.1 C3$CBB19/CBB5.1 C3$CBB19/CBB6.1 C3$CBB19/CBB7.1 C3$CBB19/CBB8.1 C3$CBB19/CBB9.1 C3$CBB19/CBB10.1 C3$CBB19/CBB11.1 C3$CBB19/CBB12.1 C3$CBB19/CBB13.1 C3$CBB19/CBB14.1 C3$CBB19/CBB15.1 C3$CBB19/CBB16.1 C3$CBB19/CBB17.1 C3$CBB19/CBB18.1 C3$CBB19/CBB19.1 C3$CBB19/CBB20.1 C3$CBB19/CBB21.1 C3$CBB19/CBB22.1 C3$CBB19/CBB23.1 C3$CBB19/CBB24.1 C3$CBB19/CBB25.1 C3$CBB19/CBB26.1 C3$CBB19/CBB27.1 C3$CBB19/CBB28.1 C3$CBB19/CBB29.1 C3$CBB19/CBB30.1 C3$CBB19/CBB31.1 C3$CBB19/CBB32.1 C3$CBB19/CBB33.1 C3$CBB19/CBB34.1 C3$CBB19/CBB35.1 C3$CBB19/CBB36.1 C3$CBB21.1 C3$CBB23.2 C3$CBB49/CBB1.1 C3$CBB49/CBB2.1 C3$CBB49/CBB3.1 C3$CBB49/CBB4.1 C3$CBB49/CBB5.1 C3$CBB49/CBB6.1 C3$CBB49/CBB7.1 C3$CBB49/CBB8.1 C3$CBB49/CBB9.1 C3$CBB49/CBB10.1 C3$CBB49/CBB11.1 C3$CBB49/CBB12.1 C3$CBB49/CBB13.1 C3$CBB49/CBB14.1 C3$CBB49/CBB15.1 C3$CBB49/CBB16.1 C3$CBB49/CBB17.1 C3$CBB49/CBB18.1 C3$CBB49/CBB19.1 C3$CBB49/CBB20.1 C3$CBB49/CBB21.1 C3$CBB49/CBB22.1 C3$CBB49/CBB23.1 C3$CBB49/CBB24.1 C3$CBB49/CBB25.1 C3$CBB49/CBB26.1 C3$CBB49/CBB27.1 C3$CBB49/CBB28.1 C3$CBB49/CBB29.1 C3$CBB49/CBB30.1 C3$CBB49/CBB31.1 C3$CBB49/CBB32.1 C3$CBB49/CBB33.1 C3$CBB49/CBB34.1 C3$CBB49/CBB35.1 C3$CBB49/CBB36.1 C3$CBB49/CBB37.1 C3$CBB49/CBB38.1 C3$CBB49/CBB39.1 C3$CBB49/CBB40.1 C3$CBB49/CBB41.1 C3$CBB49/CBB42.1 C3$CBB49/CBB43.1 C3$CBB49/CBB44.1 C3$CBB49/CBB45.1 C3$CBB49/CBB46.1 C3$CBB49/CBB47.1 C3$CBB49/CBB48.1 C3.1 C4$CBB7.1 C4$CBB21.1 C4$CBB23.2 C4.1 C5$CBB7.1 C5$CBB21.1 C5$CBB23.2 C5.2 C6$CBB7.1 C6$CBB21.1 C6$CBB23.2 C6.1 C7$CBB7.1 C7$CBB21.1 C7$CBB23.2 C7.1 C8$CBB7.1 C8$CBB21.1 C8$CBB23.2 C8.2 C9$CBB7.1 C9$CBB21.1 C9$CBB23.2 C9.2 C10$CBB7.1 C10$CBB21.1 C10$CBB23.2 C10.2 C11$CBB7.1 C11$CBB21.1 C11$CBB23.2 C11.2 C12$CBB23.2 C12.2 C13$CBB23.2 C13.2 C14$CBB23.2 C14.2 C15$CBB23.2 C15.2 C16$CBB23.2 C16.2 C17$CBB23.2 C17.2 C18$CBB23.2 C18.2 C19$CBB23.2 C19.2 C20$CBB23.2 C20.2 C21$CBB23.2 C21.2 C22$CBB22/CBB4.2 C22$CBB23.2 C22.2 C23$CBB22/CBB4.2 C23$CBB23.2 C23.2 C24$CBB22/CBB4.2 C24.2 C25$CBB22/CBB4.2 C25.2 C26.2 C27.2 C28.2 C29.1 C30.1 C31.1 C32$CBB23.1 C32.1 C33.1 C35.1 C37.1 C38.1 C39.1 C40.1 C42.2 C43$CBB22/CBB1.1 C43.2 C44.1 C45.1 C46.2 C47.2 C48.1 C50.1 C51.1 C52.2 C53.1 C54.1 C55$CBB22/CBB2.2 C56$CBB22/CBB2.2 C56.1 C57$CBB22.2 C58$CBB22/CBB1.1 C58.1 C59$CBB22/CBB1.1 C60.2 C61.1 C62.1 C63.2 C64.1 C66.1 C67.1 C68.1 C69.1 C71.1 C72.1 C73.1 C74.1 C75.2 C76.2 C77.2 C78.2 C79.2 C80.2 C81.2 C82.2 C83.2 C84.1 C121$CBB22/CBB2.2 C122$CBB22/CBB2.2 C123$CBB22/CBB2.2 C125$CBB22/CBB2.2 C126$CBB22/CBB2.2 C127$CBB22/CBB2.2 C128$CBB22/CBB2.2 C132$CBB22/CBB2.2 C133$CBB22/CBB2.2 C134$CBB22/CBB2.2 C136$CBB22/CBB2.2 C138$CBB22/CBB4.1 C142$CBB22/CBB4.1 C145$CBB15.1 C146$CBB15.1 C147$CBB22/CBB4.1 C147$CBB23.1 C168.1 C169.1 C170.1 C171.1 C172.1 C173.1 C174.1 C175.1 C176.1 C177.1 C178.1 C179.1 C180.1 C181.1 C183$CBB24.1 C184$CBB24.1 C185$CBB24.1 C186$CBB24.2 C188$CBB24.2 C193$CBB1.1 C193$CBB2.1 C193$CBB3.1 C193$CBB4.1 C193$CBB5.1 C193$CBB6.1 C193$CBB7.1 C193$CBB8.1 C193$CBB10.1 C193$CBB11.1 C193$CBB12.1 C193$CBB13.1 C193$CBB14.1 C193$CBB16.1 C193$CBB16/CBB1.1 C193$CBB16/CBB2.1 C193$CBB16/CBB3.1 C193$CBB16/CBB4.1 C193$CBB16/CBB5.1 C193$CBB16/CBB6.1 C193$CBB17.1 C193$CBB17/CBB1.1 C193$CBB17/CBB2.1 C193$CBB17/CBB3.1 C193$CBB17/CBB4.1 C193$CBB17/CBB5.1 C193$CBB17/CBB6.1 C193$CBB17/CBB7.1 C193$CBB17/CBB8.1 C193$CBB18.1 C193$CBB18/CBB1.1 C193$CBB18/CBB2.1 C193$CBB18/CBB3.1 C193$CBB18/CBB4.1 C193$CBB18/CBB5.1 C193$CBB18/CBB6.1 C193$CBB18/CBB7.1 C193$CBB18/CBB8.1 C193$CBB20.1 C193$CBB20/CBB1.1 C193$CBB20/CBB2.1 C193$CBB20/CBB3.1 C193$CBB20/CBB4.1 C193$CBB20/CBB5.1 C193$CBB20/CBB6.1 C193$CBB20/CBB7.1 C193$CBB20/CBB8.1 C193$CBB21.1 C194$CBB9.1 C194$CBB19.1 C195$CBB9.1 C195$CBB19.1 C195$CBB49.1 C196$CBB9.1 C196$CBB19.1 C196$CBB49.1 C197$CBB9.1 C197$CBB19.1 C197$CBB49.1 C212$CBB24.1 C213$CBB24.2 C214$CBB24.2 C215$CBB24.1 C217$CBB24.1 C218$CBB24.2 C219$CBB24.2 C220$CBB24.1 C221$CBB24.2 C222$CBB24.2 C223$CBB24.2 C224$CBB24.2 C225$CBB23.2 C226$CBB24.1 C227$CBB22.2 C248.2 C250.2 C258.2 C313.2 C314.2 C315.2 C316.2 D1$CBB24.2 D1.1 D2.1 D3.1 D4.1 D5.1 D6.1 D7.1 D8.1 D9.1 D10.1 D11.1 D12.1 D13.1 D14.1 D15.1 D16.1 D17.1 D18.1 ETH-LED1.1 FPC1$CBB22/CBB1.1 FPC1$CBB22/CBB1.4 FPC1$CBB22/CBB1.7 FPC1$CBB22/CBB1.10 FPC1$CBB22/CBB1.16 FPC1$CBB22/CBB1.17 FPC3$CBB22/CBB1.1 FPC3$CBB22/CBB1.4 FPC3$CBB22/CBB1.7 FPC3$CBB22/CBB1.10 FPC3$CBB22/CBB1.16 FPC3$CBB22/CBB1.17 L8.13 L8.P10 L8.SHIELD0 L8.SHIELD1 LED1$CBB22.1 LED1$CBB23.1 LED1.1 LED2$CBB23.1 LED2.1 LED3$CBB23.1 LED3.1 LED4$CBB23.1 LED5$CBB23.1 LED6$CBB23.1 LED7$CBB23.1 LED8$CBB23.1 LED9.1 pad.1 Q1$CBB15.2 Q1$CBB22/CBB1.2 Q1$CBB23.2 Q2$CBB15.2 Q2$CBB22/CBB1.2 Q2$CBB23.2 Q3$CBB15.2 Q3$CBB23.2 Q4$CBB15.2 Q4$CBB23.2 Q5$CBB15.2 Q6$CBB15.2 Q7$CBB15.2 Q8$CBB15.2 Q9$CBB15.2 Q10$CBB15.2 Q11$CBB15.2 Q12$CBB15.2 R1$CBB9/CBB1.1 R1$CBB9/CBB2.1 R1$CBB9/CBB3.1 R1$CBB9/CBB4.1 R1$CBB9/CBB5.1 R1$CBB9/CBB6.1 R1$CBB9/CBB7.1 R1$CBB9/CBB8.1 R1$CBB9/CBB9.1 R1$CBB9/CBB10.1 R1$CBB9/CBB11.1 R1$CBB9/CBB12.1 R1$CBB9/CBB13.1 R1$CBB9/CBB14.1 R1$CBB9/CBB15.1 R1$CBB9/CBB16.1 R1$CBB9/CBB17.1 R1$CBB9/CBB18.1 R1$CBB9/CBB19.1 R1$CBB9/CBB20.1 R1$CBB9/CBB21.1 R1$CBB9/CBB22.1 R1$CBB9/CBB23.1 R1$CBB9/CBB24.1 R1$CBB9/CBB25.1 R1$CBB9/CBB26.1 R1$CBB9/CBB27.1 R1$CBB9/CBB28.1 R1$CBB9/CBB29.1 R1$CBB9/CBB30.1 R1$CBB9/CBB31.1 R1$CBB9/CBB32.1 R1$CBB9/CBB33.1 R1$CBB9/CBB34.1 R1$CBB9/CBB35.1 R1$CBB9/CBB36.1 R1$CBB9/CBB37.1 R1$CBB9/CBB38.1 R1$CBB9/CBB39.1 R1$CBB9/CBB40.1 R1$CBB9/CBB41.1 R1$CBB9/CBB42.1 R1$CBB19/CBB1.1 R1$CBB19/CBB2.1 R1$CBB19/CBB3.1 R1$CBB19/CBB4.1 R1$CBB19/CBB5.1 R1$CBB19/CBB6.1 R1$CBB19/CBB7.1 R1$CBB19/CBB8.1 R1$CBB19/CBB9.1 R1$CBB19/CBB10.1 R1$CBB19/CBB11.1 R1$CBB19/CBB12.1 R1$CBB19/CBB13.1 R1$CBB19/CBB14.1 R1$CBB19/CBB15.1 R1$CBB19/CBB16.1 R1$CBB19/CBB17.1 R1$CBB19/CBB18.1 R1$CBB19/CBB19.1 R1$CBB19/CBB20.1 R1$CBB19/CBB21.1 R1$CBB19/CBB22.1 R1$CBB19/CBB23.1 R1$CBB19/CBB24.1 R1$CBB19/CBB25.1 R1$CBB19/CBB26.1 R1$CBB19/CBB27.1 R1$CBB19/CBB28.1 R1$CBB19/CBB29.1 R1$CBB19/CBB30.1 R1$CBB19/CBB31.1 R1$CBB19/CBB32.1 R1$CBB19/CBB33.1 R1$CBB19/CBB34.1 R1$CBB19/CBB35.1 R1$CBB19/CBB36.1 R1$CBB22/CBB2.2 R1$CBB49/CBB1.1 R1$CBB49/CBB2.1 R1$CBB49/CBB3.1 R1$CBB49/CBB4.1 R1$CBB49/CBB5.1 R1$CBB49/CBB6.1 R1$CBB49/CBB7.1 R1$CBB49/CBB8.1 R1$CBB49/CBB9.1 R1$CBB49/CBB10.1 R1$CBB49/CBB11.1 R1$CBB49/CBB12.1 R1$CBB49/CBB13.1 R1$CBB49/CBB14.1 R1$CBB49/CBB15.1 R1$CBB49/CBB16.1 R1$CBB49/CBB17.1 R1$CBB49/CBB18.1 R1$CBB49/CBB19.1 R1$CBB49/CBB20.1 R1$CBB49/CBB21.1 R1$CBB49/CBB22.1 R1$CBB49/CBB23.1 R1$CBB49/CBB24.1 R1$CBB49/CBB25.1 R1$CBB49/CBB26.1 R1$CBB49/CBB27.1 R1$CBB49/CBB28.1 R1$CBB49/CBB29.1 R1$CBB49/CBB30.1 R1$CBB49/CBB31.1 R1$CBB49/CBB32.1 R1$CBB49/CBB33.1 R1$CBB49/CBB34.1 R1$CBB49/CBB35.1 R1$CBB49/CBB36.1 R1$CBB49/CBB37.1 R1$CBB49/CBB38.1 R1$CBB49/CBB39.1 R1$CBB49/CBB40.1 R1$CBB49/CBB41.1 R1$CBB49/CBB42.1 R1$CBB49/CBB43.1 R1$CBB49/CBB44.1 R1$CBB49/CBB45.1 R1$CBB49/CBB46.1 R1$CBB49/CBB47.1 R1$CBB49/CBB48.1 R2$CBB9/CBB1.1 R2$CBB9/CBB2.1 R2$CBB9/CBB3.1 R2$CBB9/CBB4.1 R2$CBB9/CBB5.1 R2$CBB9/CBB6.1 R2$CBB9/CBB7.1 R2$CBB9/CBB8.1 R2$CBB9/CBB9.1 R2$CBB9/CBB10.1 R2$CBB9/CBB11.1 R2$CBB9/CBB12.1 R2$CBB9/CBB13.1 R2$CBB9/CBB14.1 R2$CBB9/CBB15.1 R2$CBB9/CBB16.1 R2$CBB9/CBB17.1 R2$CBB9/CBB18.1 R2$CBB9/CBB19.1 R2$CBB9/CBB20.1 R2$CBB9/CBB21.1 R2$CBB9/CBB22.1 R2$CBB9/CBB23.1 R2$CBB9/CBB24.1 R2$CBB9/CBB25.1 R2$CBB9/CBB26.1 R2$CBB9/CBB27.1 R2$CBB9/CBB28.1 R2$CBB9/CBB29.1 R2$CBB9/CBB30.1 R2$CBB9/CBB31.1 R2$CBB9/CBB32.1 R2$CBB9/CBB33.1 R2$CBB9/CBB34.1 R2$CBB9/CBB35.1 R2$CBB9/CBB36.1 R2$CBB9/CBB37.1 R2$CBB9/CBB38.1 R2$CBB9/CBB39.1 R2$CBB9/CBB40.1 R2$CBB9/CBB41.1 R2$CBB9/CBB42.1 R2$CBB19/CBB1.1 R2$CBB19/CBB2.1 R2$CBB19/CBB3.1 R2$CBB19/CBB4.1 R2$CBB19/CBB5.1 R2$CBB19/CBB6.1 R2$CBB19/CBB7.1 R2$CBB19/CBB8.1 R2$CBB19/CBB9.1 R2$CBB19/CBB10.1 R2$CBB19/CBB11.1 R2$CBB19/CBB12.1 R2$CBB19/CBB13.1 R2$CBB19/CBB14.1 R2$CBB19/CBB15.1 R2$CBB19/CBB16.1 R2$CBB19/CBB17.1 R2$CBB19/CBB18.1 R2$CBB19/CBB19.1 R2$CBB19/CBB20.1 R2$CBB19/CBB21.1 R2$CBB19/CBB22.1 R2$CBB19/CBB23.1 R2$CBB19/CBB24.1 R2$CBB19/CBB25.1 R2$CBB19/CBB26.1 R2$CBB19/CBB27.1 R2$CBB19/CBB28.1 R2$CBB19/CBB29.1 R2$CBB19/CBB30.1 R2$CBB19/CBB31.1 R2$CBB19/CBB32.1 R2$CBB19/CBB33.1 R2$CBB19/CBB34.1 R2$CBB19/CBB35.1 R2$CBB19/CBB36.1 R2$CBB49/CBB1.1 R2$CBB49/CBB2.1 R2$CBB49/CBB3.1 R2$CBB49/CBB4.1 R2$CBB49/CBB5.1 R2$CBB49/CBB6.1 R2$CBB49/CBB7.1 R2$CBB49/CBB8.1 R2$CBB49/CBB9.1 R2$CBB49/CBB10.1 R2$CBB49/CBB11.1 R2$CBB49/CBB12.1 R2$CBB49/CBB13.1 R2$CBB49/CBB14.1 R2$CBB49/CBB15.1 R2$CBB49/CBB16.1 R2$CBB49/CBB17.1 R2$CBB49/CBB18.1 R2$CBB49/CBB19.1 R2$CBB49/CBB20.1 R2$CBB49/CBB21.1 R2$CBB49/CBB22.1 R2$CBB49/CBB23.1 R2$CBB49/CBB24.1 R2$CBB49/CBB25.1 R2$CBB49/CBB26.1 R2$CBB49/CBB27.1 R2$CBB49/CBB28.1 R2$CBB49/CBB29.1 R2$CBB49/CBB30.1 R2$CBB49/CBB31.1 R2$CBB49/CBB32.1 R2$CBB49/CBB33.1 R2$CBB49/CBB34.1 R2$CBB49/CBB35.1 R2$CBB49/CBB36.1 R2$CBB49/CBB37.1 R2$CBB49/CBB38.1 R2$CBB49/CBB39.1 R2$CBB49/CBB40.1 R2$CBB49/CBB41.1 R2$CBB49/CBB42.1 R3$CBB49/CBB43.1 R3$CBB49/CBB44.1 R3$CBB49/CBB45.1 R3$CBB49/CBB46.1 R3$CBB49/CBB47.1 R3$CBB49/CBB48.1 R4.1 R5$CBB1.1 R5$CBB2.1 R5$CBB3.1 R5$CBB4.1 R5$CBB5.1 R5$CBB6.1 R5$CBB8.1 R5$CBB10.1 R5$CBB11.1 R5$CBB12.1 R5$CBB13.1 R5$CBB14.1 R7.1 R8$CBB23.1 R9$CBB23.1 R10$CBB23.1 R10.1 R13.1 R16$CBB16/CBB1.1 R16$CBB16/CBB2.1 R16$CBB16/CBB3.1 R16$CBB16/CBB4.1 R16$CBB16/CBB5.1 R16$CBB16/CBB6.1 R16$CBB17/CBB1.1 R16$CBB17/CBB2.1 R16$CBB17/CBB3.1 R16$CBB17/CBB4.1 R16$CBB17/CBB5.1 R16$CBB17/CBB6.1 R16$CBB17/CBB7.1 R16$CBB17/CBB8.1 R16$CBB18/CBB1.1 R16$CBB18/CBB2.1 R16$CBB18/CBB3.1 R16$CBB18/CBB4.1 R16$CBB18/CBB5.1 R16$CBB18/CBB6.1 R16$CBB18/CBB7.1 R16$CBB18/CBB8.1 R16$CBB20/CBB1.1 R16$CBB20/CBB2.1 R16$CBB20/CBB3.1 R16$CBB20/CBB4.1 R16$CBB20/CBB5.1 R16$CBB20/CBB6.1 R16$CBB20/CBB7.1 R16$CBB20/CBB8.1 R16.1 R19.1 R22.1 R23$CBB23.1 R24$CBB23.1 R25$CBB23.1 R25.1 R26$CBB23.1 R28.1 R31.1 R32$CBB17.1 R32$CBB18.1 R32$CBB20.1 R34.1 R37.1 R40.1 R43.1 R45.1 R46.2 R48$CBB16.1 R51$CBB23.2 R55.1 R59.1 R63.1 R64$CBB17.1 R64$CBB18.1 R64$CBB20.1 R65.1 R72.1 R73.1 R78.1 R80$CBB16.1 R80.1 R83.1 R86.1 R88$CBB15.1 R89.1 R92$CBB15.1 R92.1 R95.1 R96$CBB15.1 R96$CBB17.1 R96$CBB18.1 R96$CBB20.1 R97$CBB16.1 R99$CBB16.1 R99.1 R100$CBB15.1 R101$CBB16.1 R102.1 R103$CBB16.1 R104$CBB15.1 R105$CBB16.1 R105.1 R107$CBB16.1 R108$CBB15.1 R108.1 R111.1 R114.1 R117.1 R120.1 R123.1 R127.1 R128$CBB17.1 R128$CBB18.1 R128$CBB20.1 R130$CBB17.1 R130$CBB18.1 R130$CBB20.1 R132$CBB17.1 R132$CBB18.1 R132$CBB20.1 R133.1 R134$CBB17.1 R134$CBB18.1 R134$CBB20.1 R134.1 R136$CBB17.1 R136$CBB18.1 R136$CBB20.1 R141.1 R142.1 R147.1 R150.1 R151.1 R158$CBB22.1 R158$CBB23.1 R159$CBB23.1 R165$CBB22/CBB2.1 R167$CBB22/CBB2.1 R169$CBB22/CBB2.2 R173$CBB22/CBB2.2 R181$CBB24.1 R183$CBB22.1 R219$CBB24.1 R251$CBB22.1 U1$CBB1.11 U1$CBB2.11 U1$CBB3.11 U1$CBB4.11 U1$CBB5.11 U1$CBB6.11 U1$CBB7.2 U1$CBB8.11 U1$CBB10.11 U1$CBB11.11 U1$CBB12.11 U1$CBB13.11 U1$CBB14.11 U1$CBB15.11 U1$CBB16.11 U1$CBB17.11 U1$CBB18.11 U1$CBB20.11 U1$CBB21.2 U1$CBB23.A1 U1$CBB23.A5 U1$CBB23.A12 U1$CBB23.A16 U1$CBB23.D2 U1$CBB23.D15 U1$CBB23.G7 U1$CBB23.G8 U1$CBB23.G9 U1$CBB23.G10 U1$CBB23.H8 U1$CBB23.H9 U1$CBB23.H10 U1$CBB23.H11 U1$CBB23.J1 U1$CBB23.J8 U1$CBB23.J9 U1$CBB23.J16 U1$CBB23.K7 U1$CBB23.K8 U1$CBB23.K10 U1$CBB23.L8 U1$CBB23.L9 U1$CBB23.N2 U1$CBB23.N15 U1$CBB23.R7 U1$CBB23.R10 U1$CBB23.T1 U1$CBB23.T4 U1$CBB23.T13 U1$CBB23.T16 U2$CBB7.2 U2$CBB15.11 U2$CBB16.11 U2$CBB17.11 U2$CBB18.11 U2$CBB20.11 U2$CBB21.2 U2$CBB22/CBB1.1 U3$CBB7.2 U3$CBB9.11 U3$CBB15.11 U3$CBB19.11 U3$CBB21.2 U3$CBB49.11 U3.2 U4$CBB7.2 U4$CBB9.11 U4$CBB19.11 U4$CBB21.2 U4$CBB49.11 U5$CBB7.2 U5$CBB9.11 U5$CBB19.11 U5$CBB21.2 U5$CBB49.11 U5.7 U5.9 U6$CBB16/CBB1.8 U6$CBB16/CBB1.13 U6$CBB16/CBB2.8 U6$CBB16/CBB2.13 U6$CBB16/CBB3.8 U6$CBB16/CBB3.13 U6$CBB16/CBB4.8 U6$CBB16/CBB4.13 U6$CBB16/CBB5.8 U6$CBB16/CBB5.13 U6$CBB16/CBB6.8 U6$CBB16/CBB6.13 U6$CBB17/CBB1.8 U6$CBB17/CBB1.13 U6$CBB17/CBB2.8 U6$CBB17/CBB2.13 U6$CBB17/CBB3.8 U6$CBB17/CBB3.13 U6$CBB17/CBB4.8 U6$CBB17/CBB4.13 U6$CBB17/CBB5.8 U6$CBB17/CBB5.13 U6$CBB17/CBB6.8 U6$CBB17/CBB6.13 U6$CBB17/CBB7.8 U6$CBB17/CBB7.13 U6$CBB17/CBB8.8 U6$CBB17/CBB8.13 U6$CBB18/CBB1.8 U6$CBB18/CBB1.13 U6$CBB18/CBB2.8 U6$CBB18/CBB2.13 U6$CBB18/CBB3.8 U6$CBB18/CBB3.13 U6$CBB18/CBB4.8 U6$CBB18/CBB4.13 U6$CBB18/CBB5.8 U6$CBB18/CBB5.13 U6$CBB18/CBB6.8 U6$CBB18/CBB6.13 U6$CBB18/CBB7.8 U6$CBB18/CBB7.13 U6$CBB18/CBB8.8 U6$CBB18/CBB8.13 U6$CBB20/CBB1.8 U6$CBB20/CBB1.13 U6$CBB20/CBB2.8 U6$CBB20/CBB2.13 U6$CBB20/CBB3.8 U6$CBB20/CBB3.13 U6$CBB20/CBB4.8 U6$CBB20/CBB4.13 U6$CBB20/CBB5.8 U6$CBB20/CBB5.13 U6$CBB20/CBB6.8 U6$CBB20/CBB6.13 U6$CBB20/CBB7.8 U6$CBB20/CBB7.13 U6$CBB20/CBB8.8 U6$CBB20/CBB8.13 U6.7 U6.9 U7$CBB7.2 U7$CBB21.2 U7.7 U7.9 U9.4 U10.5 U10.7 U12.4 U14.1 U16.4 U19$CBB23.4 U93$CBB23.7 U93$CBB23.8 U93$CBB24.7 U93$CBB24.8 U95$CBB22/CBB1.1 U98$CBB22/CBB2.41 U98$CBB24.1 U98$CBB24.5 U98$CBB24.10 U98$CBB24.11 U98$CBB24.13 U98$CBB24.15 U98$CBB24.25 U98$CBB24.35 U98$CBB24.47 U98$CBB24.51 U99$CBB22.4 U100$CBB22.A1 U100$CBB22.A18 U100$CBB22.C3 U100$CBB22.C7 U100$CBB22.C8 U100$CBB22.C12 U100$CBB22.C15 U100$CBB22.D10 U100$CBB22.F2 U100$CBB22.F4 U100$CBB22.F17 U100$CBB22.G7 U100$CBB22.G9 U100$CBB22.G11 U100$CBB22.H1 U100$CBB22.H8 U100$CBB22.H10 U100$CBB22.H12 U100$CBB22.J7 U100$CBB22.J9 U100$CBB22.J11 U100$CBB22.J16 U100$CBB22.K8 U100$CBB22.K10 U100$CBB22.K12 U100$CBB22.L7 U100$CBB22.L9 U100$CBB22.L11 U100$CBB22.M1 U100$CBB22.M5 U100$CBB22.M8 U100$CBB22.M10 U100$CBB22.M12 U100$CBB22.N16 U100$CBB22.P7 U100$CBB22.R2 U100$CBB22.R4 U100$CBB22.R10 U100$CBB22.T13 U100$CBB22.V1 U100$CBB22.V4 U100$CBB22.V18 U101$CBB24.2 U101$CBB24.4 U102$CBB24.2 U118$CBB23.1 USB3$CBB24.4 USB3$CBB24.5 USB3$CBB24.6 X1$CBB23.2 X1.2 | length 34355.5
  Top Layer w4.7: v1(3069.1,4112.3) 3071.7,4109.7 C183$CBB24.1@3071.7,4077.1 ; v1(3163.1,4072.3) 3165.7,4074.9 U102$CBB24.2@3165.7,4105.5 ; C223$CBB24.2@3223.7,4187.4 3225.7,4189.4 v1(3225.7,4208.7) ; U19$CBB23.4@3527.9,5164.6 3527.9,5131.5 v1(3537.1,5122.3) ; U98$CBB24.11@3567.1,3933.3 3567.1,3877.4 v1(3577.1,3867.4) ; v1(3645.4,4009.9) 3645.8,4009.5 U98$CBB24.15@3645.8,3933.3 ; D1$CBB24.2@3739.7,3571.3 v1(3739.7,3572.2) ; C56$CBB22/CBB2.2@4197.8,4086.4 4203.5,4080.6 v1(4203.5,4042.1) R45.1@4203.5,3998.9 ; v1(4279.8,5410.4) R10$CBB23.1@4314,5410.4 ; R97$CBB16.1@4665.1,6504.2 4665.1,6480.7 v1(4677.6,6468.3)
  Top Layer w5.5: R1$CBB22/CBB2.2@4798.9,4110.3 4799.4,4110.3 4826,4083.7 v1(4826,4068.1) ; v1(4960.9,4056.9) 4960.9,4055.3 U14.1@4934.1,4028.5 4971.4,4028.5 C63.2@4987.6,4012.3 ; R78.1@5211.5,4908.4 v1(5211.5,4939.6)
  Top Layer w7.9: C224$CBB24.2@3820.8,4062.1 3850.2,4032.8 v1(3850.2,4024) ; v1(4325.6,4462.1) 4360.3,4462.1 C121$CBB22/CBB2.2@4361.4,4463.2 C46.2@4361.4,4508.2 4359.7,4509.9 v1(4326,4509.9) ; R16$CBB16/CBB6.1@4800.8,6539.1 4815.2,6539.1 v1(4822.1,6546) 4867.4,6546 U6$CBB16/CBB6.8@4877.6,6535.8 ; R16$CBB16/CBB5.1@4800.8,6991.8 4821.2,6991.8 v1(4822.1,6992.7) 4873.5,6992.7 U6$CBB16/CBB5.8@4877.6,6988.6 ; R16$CBB16/CBB4.1@4800.8,7444.5 4821.2,7444.5 v1(4822.1,7445.5) 4873.5,7445.5 U6$CBB16/CBB4.8@4877.6,7441.3 ; R16$CBB16/CBB3.1@4800.8,7897.3 4821.2,7897.3 v1(4822.1,7898.2) 4873.5,7898.2 U6$CBB16/CBB3.8@4877.6,7894.1 ; R16$CBB16/CBB1.1@4800.8,8350.1 4818.1,8350.1 v1(4822.1,8354.1) 4870.4,8354.1 U6$CBB16/CBB1.8@4877.6,8346.8 ; R16$CBB16/CBB2.1@4800.8,8802.8 4821.2,8802.8 v1(4822.1,8803.7) 4873.5,8803.7 U6$CBB16/CBB2.8@4877.6,8799.6 ; U6$CBB16/CBB6.13@5095.7,6735.8 5143,6735.8 v1(5158.7,6751.5) 5175.1,6767.9 R107$CBB16.1@5175.1,6785 ; U6$CBB16/CBB5.13@5095.7,7188.6 5143,7188.6 v1(5158.7,7204.3) 5175.1,7220.7 R105$CBB16.1@5175.1,7237.7 ; U6$CBB16/CBB4.13@5095.7,7641.3 5141.4,7641.3 v1(5157.1,7657) 5175.1,7675 R103$CBB16.1@5175.1,7690.5 ; U6$CBB16/CBB3.13@5095.7,8094.1 5143,8094.1 v1(5158.7,8109.8) 5175.1,8126.2 R101$CBB16.1@5175.1,8143.2 ; U6$CBB16/CBB1.13@5095.7,8546.8 5143,8546.8 v1(5158.7,8562.5) 5175.1,8578.9 R99$CBB16.1@5175.1,8596 ; U6$CBB16/CBB2.13@5095.7,8999.6 5143,8999.6 v1(5158.7,9015.3) 5175.1,9031.7 R48$CBB16.1@5175.1,9048.7 ; C193$CBB16/CBB6.1@5110.3,6929.1 5143,6929.1 v1(5150.7,6921.4) ; C193$CBB16/CBB5.1@5110.3,7381.8 5143,7381.8 v1(5150.7,7374.1) ; C193$CBB16/CBB4.1@5110.3,7834.5 5143,7834.5 v1(5150.7,7826.9) ; C193$CBB16/CBB3.1@5110.3,8287.3 5143,8287.3 v1(5150.7,8279.7) ; C193$CBB16/CBB1.1@5110.3,8740.1 5143,8740.1 v1(5150.7,8732.4) ; C193$CBB16/CBB2.1@5110.3,9192.8 5143,9192.8 v1(5150.7,9185.2) ; R16$CBB17/CBB8.1@5425.8,5633.5 5446.2,5633.5 v1(5447.1,5634.4) 5498.5,5634.4 U6$CBB17/CBB8.8@5502.6,5630.3 ; R16$CBB17/CBB7.1@5425.8,6086.3 5446.2,6086.3 v1(5447.1,6087.2) 5498.5,6087.2 U6$CBB17/CBB7.8@5502.6,6083.1 ; R16$CBB17/CBB6.1@5425.8,6539 5446.1,6539 v1(5447.1,6538) 5500.5,6538 U6$CBB17/CBB6.8@5502.6,6535.8 ; R16$CBB17/CBB5.1@5425.8,6991.8 5446.2,6991.8 v1(5447.1,6992.7) 5498.5,6992.7 U6$CBB17/CBB5.8@5502.6,6988.6 ; R16$CBB17/CBB4.1@5425.8,7444.6 5446.2,7444.6 v1(5447.1,7445.5) 5498.5,7445.5 U6$CBB17/CBB4.8@5502.6,7441.3 ; R16$CBB17/CBB3.1@5425.8,7897.3 5446.2,7897.3 v1(5447.1,7898.2) 5498.5,7898.2 U6$CBB17/CBB3.8@5502.6,7894.1 ; R16$CBB17/CBB2.1@5425.8,8350.1 5443.1,8350.1 v1(5447.1,8354.1) 5495.4,8354.1 U6$CBB17/CBB2.8@5502.6,8346.8 ; R16$CBB17/CBB1.1@5425.8,8802.8 5446.2,8802.8 v1(5447.1,8803.7) 5498.5,8803.7 U6$CBB17/CBB1.8@5502.6,8799.6 ; U6$CBB17/CBB8.13@5720.7,5830.3 5768,5830.3 v1(5783.7,5846) 5800.1,5862.4 R136$CBB17.1@5800.1,5879.4 ; U6$CBB17/CBB7.13@5720.7,6283.1 5768,6283.1 v1(5783.7,6298.8) 5800.1,6315.2 R134$CBB17.1@5800.1,6332.2 ; U6$CBB17/CBB6.13@5720.7,6735.8 5768,6735.8 v1(5783.7,6751.5) 5800.1,6767.9 R132$CBB17.1@5800.1,6785 ; U6$CBB17/CBB5.13@5720.7,7188.6 5770,7188.6 v1(5783.7,7202.3) 5800.1,7218.7 R130$CBB17.1@5800.1,7237.7 ; U6$CBB17/CBB4.13@5720.7,7641.3 5768,7641.3 v1(5783.7,7657) 5800.1,7673.4 R128$CBB17.1@5800.1,7690.5 ; U6$CBB17/CBB3.13@5720.7,8094.1 5769.9,8094.1 v1(5783.7,8107.8) 5800.1,8124.2 R96$CBB17.1@5800.1,8143.2 ; U6$CBB17/CBB2.13@5720.7,8546.8 5768,8546.8 v1(5783.7,8562.5) 5800.1,8578.9 R64$CBB17.1@5800.1,8596 ; U6$CBB17/CBB1.13@5720.7,8999.6 5768,8999.6 v1(5783.7,9015.3) 5800.1,9031.7 R32$CBB17.1@5800.1,9048.7 ; C193$CBB17/CBB8.1@5735.3,6023.5 5768.2,6023.5 v1(5775.9,6015.9) ; C193$CBB17/CBB7.1@5735.3,6476.3 5768.2,6476.3 v1(5775.9,6468.6) ; C193$CBB17/CBB6.1@5735.3,6929 5768.2,6929 v1(5775.9,6921.4) ; C193$CBB17/CBB5.1@5735.3,7381.8 5768.2,7381.8 v1(5775.9,7374.1) ; C193$CBB17/CBB4.1@5735.3,7834.6 5768,7834.6 v1(5775.7,7826.9) ; C193$CBB17/CBB3.1@5735.3,8287.3 5768,8287.3 v1(5775.7,8279.7) ; C193$CBB17/CBB2.1@5735.3,8740.1 5768,8740.1 v1(5775.7,8732.4) ; C193$CBB17/CBB1.1@5735.3,9192.8 5768,9192.8 v1(5775.7,9185.2) ; R16$CBB18/CBB8.1@6055.7,5633.5 6076.1,5633.5 v1(6077,5634.4) 6128.4,5634.4 U6$CBB18/CBB8.8@6132.6,5630.3 ; R16$CBB18/CBB7.1@6055.7,6086.3 6076.1,6086.3 v1(6077,6087.2) 6128.4,6087.2 U6$CBB18/CBB7.8@6132.6,6083.1 ; R16$CBB18/CBB6.1@6055.7,6539 6076.1,6539 v1(6077,6540) 6128.4,6540 U6$CBB18/CBB6.8@6132.6,6535.8 ; R16$CBB18/CBB5.1@6055.7,6991.8 6076.1,6991.8 v1(6077,6992.7) 6128.4,6992.7 U6$CBB18/CBB5.8@6132.6,6988.6 ; R16$CBB18/CBB4.1@6055.7,7444.6 6076.1,7444.6 v1(6077,7445.5) 6128.4,7445.5 U6$CBB18/CBB4.8@6132.6,7441.3 ; R16$CBB18/CBB3.1@6055.7,7897.3 6076.1,7897.3 v1(6077,7898.2) 6128.4,7898.2 U6$CBB18/CBB3.8@6132.6,7894.1 ; R16$CBB18/CBB2.1@6055.7,8350.1 6066.3,8350.1 v1(6077,8360.8) 6118.6,8360.8 U6$CBB18/CBB2.8@6132.6,8346.8 ; R16$CBB18/CBB1.1@6055.7,8802.8 6076.1,8802.8 v1(6077,8803.7) 6128.4,8803.7 U6$CBB18/CBB1.8@6132.6,8799.6 ; U6$CBB18/CBB8.13@6350.6,5830.3 6397.9,5830.3 v1(6413.6,5846) 6430,5862.4 R136$CBB18.1@6430,5879.4 ; U6$CBB18/CBB7.13@6350.6,6283.1 6397.9,6283.1 v1(6413.6,6298.7) 6430,6315.2 R134$CBB18.1@6430,6332.2 ; U6$CBB18/CBB6.13@6350.6,6735.8 6397.9,6735.8 v1(6413.6,6751.5) 6430,6767.9 R132$CBB18.1@6430,6785 ; U6$CBB18/CBB5.13@6350.6,7188.6 6397.9,7188.6 v1(6413.6,7204.3) 6430,7220.7 R130$CBB18.1@6430,7237.7 ; U6$CBB18/CBB4.13@6350.6,7641.3 6397.9,7641.3 v1(6413.6,7657) 6430,7673.4 R128$CBB18.1@6430,7690.5 ; U6$CBB18/CBB3.13@6350.6,8094.1 6395.8,8094.1 v1(6413.6,8111.9) 6430,8128.3 R96$CBB18.1@6430,8143.2 ; U6$CBB18/CBB2.13@6350.6,8546.8 6397.9,8546.8 v1(6413.6,8562.5) 6430,8578.9 R64$CBB18.1@6430,8596 ; U6$CBB18/CBB1.13@6350.6,8999.6 6397.9,8999.6 v1(6413.6,9015.3) 6430,9031.7 R32$CBB18.1@6430,9048.7 ; C193$CBB18/CBB8.1@6365.2,6023.5 6397.9,6023.5 v1(6405.6,6015.9) ; C193$CBB18/CBB7.1@6365.2,6476.3 6397.9,6476.3 v1(6405.6,6468.6) ; C193$CBB18/CBB6.1@6365.2,6929 6397.6,6929 v1(6405.4,6921.2) ; C193$CBB18/CBB5.1@6365.2,7381.8 6397.9,7381.8 v1(6405.6,7374.1) ; C193$CBB18/CBB4.1@6365.2,7834.6 6397.9,7834.6 v1(6405.6,7826.9) ; C193$CBB18/CBB3.1@6365.2,8287.3 6397.9,8287.3 v1(6405.6,8279.7) ; C193$CBB18/CBB2.1@6365.2,8740.1 6397.9,8740.1 v1(6405.6,8732.4) ; C193$CBB18/CBB1.1@6365.2,9192.8 6397.9,9192.8 v1(6405.6,9185.2) ; R16$CBB20/CBB8.1@6685.7,5633.5 6706.1,5633.5 v1(6707,5634.4) 6758.3,5634.4 U6$CBB20/CBB8.8@6762.5,5630.3 ; R16$CBB20/CBB7.1@6685.7,6086.3 6704.5,6086.3 v1(6707,6088.7) 6756.8,6088.7 U6$CBB20/CBB7.8@6762.5,6083.1 ; R16$CBB20/CBB6.1@6685.7,6539 6706.1,6539 v1(6707,6540) 6758.3,6540 U6$CBB20/CBB6.8@6762.5,6535.8 ; R16$CBB20/CBB5.1@6685.7,6991.8 6706.1,6991.8 v1(6707,6992.7) 6758.3,6992.7 U6$CBB20/CBB5.8@6762.5,6988.6 ; R16$CBB20/CBB4.1@6685.7,7444.6 6706.1,7444.6 v1(6707,7445.5) 6758.3,7445.5 U6$CBB20/CBB4.8@6762.5,7441.3 ; R16$CBB20/CBB3.1@6685.7,7897.3 6706.1,7897.3 v1(6707,7898.2) 6758.3,7898.2 U6$CBB20/CBB3.8@6762.5,7894.1 ; R16$CBB20/CBB2.1@6685.7,8350.1 6696.2,8350.1 v1(6707,8360.8) 6748.5,8360.8 U6$CBB20/CBB2.8@6762.5,8346.8 ; R16$CBB20/CBB1.1@6685.7,8802.8 6706.1,8802.8 v1(6707,8803.7) 6758.3,8803.7 U6$CBB20/CBB1.8@6762.5,8799.6 ; U7$CBB7.2@6886.6,4904.5 6886.6,4864.1 v1(6883.1,4860.7) C5$CBB7.1@6925,4860.7 ; U4$CBB7.2@6887.1,3907.5 6887.1,3867.2 v1(6883.7,3863.7) C11$CBB7.1@6925.6,3863.7 ; U5$CBB7.2@6887.1,4107.5 6887.1,4067.2 v1(6883.7,4063.7) C10$CBB7.1@6925.6,4063.7 ; U2$CBB7.2@6887.1,4307.5 6887.1,4267.2 v1(6883.7,4263.7) C9$CBB7.1@6925.6,4263.7 ; U3$CBB7.2@6887.1,4507.5 6887.1,4467.2 v1(6883.7,4463.7) C8$CBB7.1@6925.6,4463.7 ; U1$CBB7.2@6887.1,4702.5 6887.1,4662.2 v1(6883.7,4658.7) C6$CBB7.1@6925.6,4658.7 ; U6$CBB20/CBB8.13@6980.5,5830.3 7027.8,5830.3 v1(7043.5,5846) 7059.9,5862.4 R136$CBB20.1@7059.9,5879.4 ; U6$CBB20/CBB7.13@6980.5,6283.1 7027.8,6283.1 v1(7043.5,6298.7) 7059.9,6315.2 R134$CBB20.1@7059.9,6332.2 ; U6$CBB20/CBB6.13@6980.5,6735.8 7027.8,6735.8 v1(7043.5,6751.5) 7059.9,6767.9 R132$CBB20.1@7059.9,6785 ; U6$CBB20/CBB5.13@6980.5,7188.6 7027.8,7188.6 v1(7043.5,7204.3) 7059.9,7220.7 R130$CBB20.1@7059.9,7237.7 ; U6$CBB20/CBB4.13@6980.5,7641.3 7027.8,7641.3 v1(7043.5,7657) 7059.9,7673.4 R128$CBB20.1@7059.9,7690.5 ; U6$CBB20/CBB3.13@6980.5,8094.1 7025.4,8094.1 v1(7043.5,8112.2) 7059.9,8128.6 R96$CBB20.1@7059.9,8143.2 ; U6$CBB20/CBB2.13@6980.5,8546.8 7027.8,8546.8 v1(7043.5,8562.5) 7059.9,8578.9 R64$CBB20.1@7059.9,8596 ; U6$CBB20/CBB1.13@6980.5,8999.6 7027.8,8999.6 v1(7043.5,9015.3) 7059.9,9031.7 R32$CBB20.1@7059.9,9048.7 ; C193$CBB20/CBB8.1@6995.2,6023.5 7027.8,6023.5 v1(7035.5,6015.9) ; C193$CBB20/CBB7.1@6995.2,6476.3 7027.8,6476.3 v1(7035.5,6468.6) ; C193$CBB20/CBB6.1@6995.2,6929 7027.8,6929 v1(7035.5,6921.4) ; C193$CBB20/CBB5.1@6995.2,7381.8 7027.8,7381.8 v1(7035.5,7374.1) ; C193$CBB20/CBB4.1@6995.2,7834.6 7027.8,7834.6 v1(7035.5,7826.9) ; C193$CBB20/CBB3.1@6995.2,8287.3 7027.8,8287.3 v1(7035.5,8279.7) ; C193$CBB20/CBB2.1@6995.2,8740.1 7027.8,8740.1 v1(7035.5,8732.4) ; C193$CBB20/CBB1.1@6995.2,9192.8 7027.8,9192.8 v1(7035.5,9185.2) ; U4$CBB21.2@7105.9,3908.3 7105.9,3863.9 v1(7104.4,3862.5) 7142.4,3862.5 C11$CBB21.1@7144.4,3864.5 ; U5$CBB21.2@7105.9,4111.5 7105.9,4067.2 v1(7104.4,4065.7) 7142.4,4065.7 C10$CBB21.1@7144.4,4067.7 ; U2$CBB21.2@7105.9,4309.8 7105.9,4265.4 v1(7104.4,4263.9) 7142.4,4263.9 C9$CBB21.1@7144.4,4266 ; U7$CBB21.2@7105.9,4904.5 7105.9,4863.1 v1(7103.5,4860.7) C5$CBB21.1@7144.4,4860.7 ; U3$CBB21.2@7107.1,4507.5 7107.1,4467.2 v1(7103.7,4463.7) C8$CBB21.1@7145.6,4463.7 ; U1$CBB21.2@7107.1,4702.5 7107.1,4662.2 v1(7103.7,4658.7) C6$CBB21.1@7145.6,4658.7 ; C193$CBB1.1@7467.1,4805.6 7480.6,4805.6 7492.1,4817.2 v1(7597.1,4817.2) ; R5$CBB1.1@7467.1,4994.2 7467.1,5024.3 v1(7470,5027.2) ; v1(7517.7,7298.7) 7522.7,7303.8 C1$CBB49/CBB43.1@7522.7,7338.7 ; v1(7517.7,7338.7) C1$CBB49/CBB43.1@7522.7,7338.7 ; R3$CBB49/CBB43.1@7523.2,7298.7 R1$CBB49/CBB43.1@7569.1,7298.7 7569.1,7338.2 C3$CBB49/CBB43.1@7569.6,7338.7 C1$CBB49/CBB43.1@7522.7,7338.7 ; v1(7657.1,4295) v1@7657.4,4295 ; v1(7689.9,4839) 7693.1,4842.2 U1$CBB1.11@7756.1,4842.2 ; v1(7888,4058.1) 7888.6,4058.7 R92$CBB15.1@7925.1,4058.7 ; v1(7892,4158.5) 7892.2,4158.7 R88$CBB15.1@7925.1,4158.7 ; C193$CBB2.1@7975.8,4805.6 7989.3,4805.6 8000.8,4817.2 v1(8105.8,4817.2) ; R5$CBB2.1@7975.8,4994.2 v1(7975.8,5027.2) ; v1(8026.4,7298.7) 8031.4,7303.8 C1$CBB49/CBB44.1@8031.4,7338.7 ; v1(8026.4,7338.7) C1$CBB49/CBB44.1@8031.4,7338.7 ; R3$CBB49/CBB44.1@8031.9,7298.7 8077.8,7298.7 8077.8,7338.2 C3$CBB49/CBB44.1@8078.3,7338.7 C1$CBB49/CBB44.1@8031.4,7338.7 ; v1(8198.6,4839) 8201.8,4842.2 U1$CBB2.11@8264.8,4842.2 ; v1(8351.8,4109.2) v1@8354.2,4109.2 ; R96$CBB15.1@8354.2,4058.7 v1@8354.2,4109.2 ; R100$CBB15.1@8354.2,4158.7 v1@8354.2,4109.2 ; v1(8458.2,4053.7) R108$CBB15.1@8495.1,4053.7 ; v1(8458.2,4154.5) 8459,4153.7 R104$CBB15.1@8495.1,4153.7 ; C193$CBB3.1@8484.5,4805.6 8498,4805.6 8509.5,4817.2 v1(8614.5,4817.2) ; R5$CBB3.1@8484.5,4994.2 v1(8484.5,5027.2) ; v1(8535.1,7298.7) 8540.1,7303.8 C1$CBB49/CBB45.1@8540.1,7338.7 ; v1(8535.1,7338.7) C1$CBB49/CBB45.1@8540.1,7338.7 ; R3$CBB49/CBB45.1@8540.6,7298.7 8586.5,7298.7 8586.5,7338.2 C3$CBB49/CBB45.1@8587,7338.7 C1$CBB49/CBB45.1@8540.1,7338.7 ; v1(8707.3,4839) 8710.5,4842.2 U1$CBB3.11@8773.5,4842.2 ; v1@8917.6,4109.2 v1(8918,4109.2) ; C193$CBB4.1@8993.2,4805.6 9006.7,4805.6 9018.2,4817.2 v1(9123.2,4817.2) ; R5$CBB4.1@8993.2,4994.2 v1(8993.2,5027.2) ; v1(9043.8,7298.7) 9048.8,7303.8 C1$CBB49/CBB46.1@9048.8,7338.7 ; v1(9043.8,7338.7) C1$CBB49/CBB46.1@9048.8,7338.7 ; R3$CBB49/CBB46.1@9049.3,7298.7 9095.2,7298.7 9095.2,7338.2 C3$CBB49/CBB46.1@9095.7,7338.7 C1$CBB49/CBB46.1@9048.8,7338.7 ; v1(9216,4839) 9219.2,4842.2 U1$CBB4.11@9282.3,4842.2 ; C193$CBB5.1@9501.9,4805.6 9515.4,4805.6 9526.9,4817.2 v1(9631.9,4817.2) ; R5$CBB5.1@9501.9,4994.2 v1(9501.9,5027.2) ; v1(9552.5,7298.7) 9557.5,7303.8 C1$CBB49/CBB47.1@9557.5,7338.7 ; v1(9552.5,7338.7) C1$CBB49/CBB47.1@9557.5,7338.7 ; R3$CBB49/CBB47.1@9558,7298.7 9603.9,7298.7 9603.9,7338.2 C3$CBB49/CBB47.1@9604.4,7338.7 C1$CBB49/CBB47.1@9557.5,7338.7 ; v1(9724.7,4839) 9727.9,4842.2 U1$CBB5.11@9791,4842.2 ; C193$CBB6.1@10010.6,4805.6 10024.1,4805.6 10035.6,4817.2 v1(10140.6,4817.2) ; R5$CBB6.1@10010.6,4994.2 v1(10010.6,5027.2) ; v1(10061.2,7298.7) 10066.2,7303.8 C1$CBB49/CBB48.1@10066.2,7338.7 ; v1(10061.2,7338.7) C1$CBB49/CBB48.1@10066.2,7338.7 ; R3$CBB49/CBB48.1@10066.7,7298.7 10112.6,7298.7 10112.6,7338.2 C3$CBB49/CBB48.1@10113.1,7338.7 C1$CBB49/CBB48.1@10066.2,7338.7 ; v1(10233.4,4839) 10236.6,4842.2 U1$CBB6.11@10299.7,4842.2 ; v1(7517.7,5728.7) v1(7517.7,5768.7) C3$CBB49/CBB6.1@7569.6,5768.7 7569.1,5768.2 R2$CBB49/CBB6.1@7569.1,5728.7 v1(7517.7,5728.7) ; v1(7517.7,5993.7) v1(7517.7,6033.7) C3$CBB49/CBB37.1@7569.6,6033.7 7569.1,6033.2 R2$CBB49/CBB37.1@7569.1,5993.7 v1(7517.7,5993.7) ; v1(7517.7,6513.7) v1(7517.7,6553.7) C3$CBB49/CBB5.1@7569.6,6553.7 7569.1,6553.2 R2$CBB49/CBB5.1@7569.1,6513.7 v1(7517.7,6513.7) ; v1(7517.7,7033.7) v1(7517.7,7073.7) C3$CBB49/CBB4.1@7569.6,7073.7 7569.1,7073.2 R2$CBB49/CBB4.1@7569.1,7033.7 v1(7517.7,7033.7) ; v1(7517.7,7818.7) v1(7517.7,7858.7) C3$CBB49/CBB3.1@7569.6,7858.7 7569.1,7858.2 R2$CBB49/CBB3.1@7569.1,7818.7 v1(7517.7,7818.7) ; v1(7517.7,8603.7) v1(7517.7,8643.7) C3$CBB49/CBB2.1@7569.6,8643.7 7569.1,8643.2 R2$CBB49/CBB2.1@7569.1,8603.7 v1(7517.7,8603.7) ; v1(7517.7,9123.7) v1(7517.7,9163.7) C3$CBB49/CBB1.1@7569.6,9163.7 7569.1,9163.2 R2$CBB49/CBB1.1@7569.1,9123.7 v1(7517.7,9123.7) ; R1$CBB9/CBB6.1@7522.7,5473.9 v1(7522.7,5513.7) C3$CBB9/CBB6.1@7564.6,5513.7 7564.6,5474.2 R2$CBB9/CBB6.1@7564.1,5473.7 v1(7522.9,5473.7) R1$CBB9/CBB6.1@7522.7,5473.9 ; R1$CBB9/CBB5.1@7522.7,6258.9 v1(7522.7,6298.7) C3$CBB9/CBB5.1@7564.6,6298.7 7564.6,6259.2 R2$CBB9/CBB5.1@7564.1,6258.7 v1(7522.9,6258.7) R1$CBB9/CBB5.1@7522.7,6258.9 ; R1$CBB9/CBB4.1@7522.7,6778.9 v1(7522.7,6818.7) C3$CBB9/CBB4.1@7564.6,6818.7 7564.6,6779.2 R2$CBB9/CBB4.1@7564.1,6778.7 v1(7522.9,6778.7) R1$CBB9/CBB4.1@7522.7,6778.9 ; R1$CBB9/CBB3.1@7522.7,7563.9 v1(7522.7,7603.7) C3$CBB9/CBB3.1@7564.6,7603.7 7564.6,7564.2 R2$CBB9/CBB3.1@7564.1,7563.7 v1(7522.9,7563.7) R1$CBB9/CBB3.1@7522.7,7563.9 ; R1$CBB9/CBB37.1@7522.7,8083.9 v1(7522.7,8123.7) C3$CBB9/CBB37.1@7564.6,8123.7 7564.6,8084.2 R2$CBB9/CBB37.1@7564.1,8083.7 v1(7522.9,8083.7) R1$CBB9/CBB37.1@7522.7,8083.9 ; R1$CBB9/CBB2.1@7522.7,8348.9 v1(7522.7,8388.7) C3$CBB9/CBB2.1@7564.6,8388.7 7564.6,8349.2 R2$CBB9/CBB2.1@7564.1,8348.7 v1(7522.9,8348.7) R1$CBB9/CBB2.1@7522.7,8348.9 ; R1$CBB9/CBB1.1@7522.7,8868.9 v1(7522.7,8908.7) C3$CBB9/CBB1.1@7564.6,8908.7 7564.6,8869.2 R2$CBB9/CBB1.1@7564.1,8868.7 v1(7522.9,8868.7) R1$CBB9/CBB1.1@7522.7,8868.9 ; v1(7772.7,5768.7) C3$CBB19/CBB6.1@7814.6,5768.7 7814.6,5729.2 R2$CBB19/CBB6.1@7814.1,5728.7 v1(7773.2,5728.7) 7773.2,5768.2 v1(7772.7,5768.7) ; v1(7772.7,6553.7) C3$CBB19/CBB5.1@7814.6,6553.7 7814.6,6514.2 R2$CBB19/CBB5.1@7814.1,6513.7 v1(7773.2,6513.7) 7773.2,6553.2 v1(7772.7,6553.7) ; v1(7772.7,7073.7) C3$CBB19/CBB4.1@7814.6,7073.7 7814.6,7034.2 R2$CBB19/CBB4.1@7814.1,7033.7 v1(7773.2,7033.7) 7773.2,7073.2 v1(7772.7,7073.7) ; v1(7772.7,7858.7) C3$CBB19/CBB3.1@7814.6,7858.7 7814.6,7819.2 R2$CBB19/CBB3.1@7814.1,7818.7 v1(7773.2,7818.7) 7773.2,7858.2 v1(7772.7,7858.7) ; v1(7772.7,8643.7) C3$CBB19/CBB2.1@7814.6,8643.7 7814.6,8604.2 R2$CBB19/CBB2.1@7814.1,8603.7 v1(7773.2,8603.7) 7773.2,8643.2 v1(7772.7,8643.7) ; v1(7772.7,9163.7) C3$CBB19/CBB1.1@7814.6,9163.7 7814.6,9124.2 R2$CBB19/CBB1.1@7814.1,9123.7 v1(7773.2,9123.7) 7773.2,9163.2 v1(7772.7,9163.7) ; v1(8026.4,5728.7) v1(8026.4,5768.7) C3$CBB49/CBB12.1@8078.3,5768.7 8077.8,5768.2 R2$CBB49/CBB12.1@8077.8,5728.7 v1(8026.4,5728.7) ; v1(8026.4,5993.7) v1(8026.4,6033.7) C3$CBB49/CBB38.1@8078.3,6033.7 8077.8,6033.2 R2$CBB49/CBB38.1@8077.8,5993.7 v1(8026.4,5993.7) ; v1(8026.4,6513.7) v1(8026.4,6553.7) C3$CBB49/CBB11.1@8078.3,6553.7 8077.8,6553.2 R2$CBB49/CBB11.1@8077.8,6513.7 v1(8026.4,6513.7) ; v1(8026.4,7033.7) v1(8026.4,7073.7) C3$CBB49/CBB10.1@8078.3,7073.7 8077.8,7073.2 R2$CBB49/CBB10.1@8077.8,7033.7 v1(8026.4,7033.7) ; v1(8026.4,7818.7) v1(8026.4,7858.7) C3$CBB49/CBB9.1@8078.3,7858.7 8077.8,7858.2 R2$CBB49/CBB9.1@8077.8,7818.7 v1(8026.4,7818.7) ; v1(8026.4,8603.7) v1(8026.4,8643.7) C3$CBB49/CBB8.1@8078.3,8643.7 8077.8,8643.2 R2$CBB49/CBB8.1@8077.8,8603.7 v1(8026.4,8603.7) ; v1(8026.4,9123.7) v1(8026.4,9163.7) C3$CBB49/CBB7.1@8078.3,9163.7 8077.8,9163.2 R2$CBB49/CBB7.1@8077.8,9123.7 v1(8026.4,9123.7) ; R1$CBB9/CBB12.1@8031.4,5473.9 v1(8031.4,5513.7) C3$CBB9/CBB12.1@8073.3,5513.7 8073.3,5474.2 R2$CBB9/CBB12.1@8072.8,5473.7 v1(8031.6,5473.7) R1$CBB9/CBB12.1@8031.4,5473.9 ; R1$CBB9/CBB11.1@8031.4,6258.9 v1(8031.4,6298.7) C3$CBB9/CBB11.1@8073.3,6298.7 8073.3,6259.2 R2$CBB9/CBB11.1@8072.8,6258.7 v1(8031.6,6258.7) R1$CBB9/CBB11.1@8031.4,6258.9 ; R1$CBB9/CBB10.1@8031.4,6778.9 v1(8031.4,6818.7) C3$CBB9/CBB10.1@8073.3,6818.7 8073.3,6779.2 R2$CBB9/CBB10.1@8072.8,6778.7 v1(8031.6,6778.7) R1$CBB9/CBB10.1@8031.4,6778.9 ; R1$CBB9/CBB9.1@8031.4,7563.9 v1(8031.4,7603.7) C3$CBB9/CBB9.1@8073.3,7603.7 8073.3,7564.2 R2$CBB9/CBB9.1@8072.8,7563.7 v1(8031.6,7563.7) R1$CBB9/CBB9.1@8031.4,7563.9 ; R1$CBB9/CBB38.1@8031.4,8083.9 v1(8031.4,8123.7) C3$CBB9/CBB38.1@8073.3,8123.7 8073.3,8084.2 R2$CBB9/CBB38.1@8072.8,8083.7 v1(8031.6,8083.7) R1$CBB9/CBB38.1@8031.4,8083.9 ; R1$CBB9/CBB8.1@8031.4,8348.9 v1(8031.4,8388.7) C3$CBB9/CBB8.1@8073.3,8388.7 8073.3,8349.2 R2$CBB9/CBB8.1@8072.8,8348.7 v1(8031.6,8348.7) R1$CBB9/CBB8.1@8031.4,8348.9 ; R1$CBB9/CBB7.1@8031.4,8868.9 v1(8031.4,8908.7) C3$CBB9/CBB7.1@8073.3,8908.7 8073.3,8869.2 R2$CBB9/CBB7.1@8072.8,8868.7 v1(8031.6,8868.7) R1$CBB9/CBB7.1@8031.4,8868.9 ; v1(8281.4,5768.7) 8281.9,5768.2 v1(8281.9,5728.7) R2$CBB19/CBB12.1@8322.8,5728.7 8323.3,5729.2 C3$CBB19/CBB12.1@8323.3,5768.7 v1(8281.4,5768.7) ; v1(8281.4,6553.7) 8281.9,6553.2 v1(8281.9,6513.7) R2$CBB19/CBB11.1@8322.8,6513.7 8323.3,6514.2 C3$CBB19/CBB11.1@8323.3,6553.7 v1(8281.4,6553.7) ; v1(8281.4,7073.7) 8281.9,7073.2 v1(8281.9,7033.7) R2$CBB19/CBB10.1@8322.8,7033.7 8323.3,7034.2 C3$CBB19/CBB10.1@8323.3,7073.7 v1(8281.4,7073.7) ; v1(8281.4,7858.7) 8281.9,7858.2 v1(8281.9,7818.7) R2$CBB19/CBB9.1@8322.8,7818.7 8323.3,7819.2 C3$CBB19/CBB9.1@8323.3,7858.7 v1(8281.4,7858.7) ; v1(8281.4,8643.7) 8281.9,8643.2 v1(8281.9,8603.7) R2$CBB19/CBB8.1@8322.8,8603.7 8323.3,8604.2 C3$CBB19/CBB8.1@8323.3,8643.7 v1(8281.4,8643.7) ; v1(8281.4,9163.7) 8281.9,9163.2 v1(8281.9,9123.7) R2$CBB19/CBB7.1@8322.8,9123.7 8323.3,9124.2 C3$CBB19/CBB7.1@8323.3,9163.7 v1(8281.4,9163.7) ; v1(8535.1,5728.7) v1(8535.1,5768.7) C3$CBB49/CBB18.1@8587,5768.7 8586.5,5768.2 R2$CBB49/CBB18.1@8586.5,5728.7 v1(8535.1,5728.7) ; v1(8535.1,5993.7) v1(8535.1,6033.7) C3$CBB49/CBB39.1@8587,6033.7 8586.5,6033.2 R2$CBB49/CBB39.1@8586.5,5993.7 v1(8535.1,5993.7) ; v1(8535.1,6513.7) v1(8535.1,6553.7) C3$CBB49/CBB17.1@8587,6553.7 8586.5,6553.2 R2$CBB49/CBB17.1@8586.5,6513.7 v1(8535.1,6513.7) ; v1(8535.1,7033.7) v1(8535.1,7073.7) C3$CBB49/CBB16.1@8587,7073.7 8586.5,7073.2 R2$CBB49/CBB16.1@8586.5,7033.7 v1(8535.1,7033.7) ; v1(8535.1,7818.7) v1(8535.1,7858.7) C3$CBB49/CBB15.1@8587,7858.7 8586.5,7858.2 R2$CBB49/CBB15.1@8586.5,7818.7 v1(8535.1,7818.7) ; v1(8535.1,8603.7) v1(8535.1,8643.7) C3$CBB49/CBB14.1@8587,8643.7 8586.5,8643.2 R2$CBB49/CBB14.1@8586.5,8603.7 v1(8535.1,8603.7) ; v1(8535.1,9123.7) v1(8535.1,9163.7) C3$CBB49/CBB13.1@8587,9163.7 8586.5,9163.2 R2$CBB49/CBB13.1@8586.5,9123.7 v1(8535.1,9123.7) ; R1$CBB9/CBB18.1@8540.1,5473.9 v1(8540.1,5513.7) C3$CBB9/CBB18.1@8582,5513.7 8582,5474.2 R2$CBB9/CBB18.1@8581.5,5473.7 8540.3,5473.7 R1$CBB9/CBB18.1@8540.1,5473.9 ; R1$CBB9/CBB17.1@8540.1,6258.9 v1(8540.1,6298.7) C3$CBB9/CBB17.1@8582,6298.7 8582,6259.2 R2$CBB9/CBB17.1@8581.5,6258.7 8540.3,6258.7 R1$CBB9/CBB17.1@8540.1,6258.9 ; R1$CBB9/CBB16.1@8540.1,6778.9 v1(8540.1,6818.7) C3$CBB9/CBB16.1@8582,6818.7 8582,6779.2 R2$CBB9/CBB16.1@8581.5,6778.7 8540.3,6778.7 R1$CBB9/CBB16.1@8540.1,6778.9 ; R1$CBB9/CBB15.1@8540.1,7563.9 v1(8540.1,7603.7) C3$CBB9/CBB15.1@8582,7603.7 8582,7564.2 R2$CBB9/CBB15.1@8581.5,7563.7 8540.3,7563.7 R1$CBB9/CBB15.1@8540.1,7563.9 ; R1$CBB9/CBB39.1@8540.1,8083.9 8540.3,8083.7 R2$CBB9/CBB39.1@8581.5,8083.7 8582,8084.2 C3$CBB9/CBB39.1@8582,8123.7 v1(8540.1,8123.7) R1$CBB9/CBB39.1@8540.1,8083.9 ; R1$CBB9/CBB14.1@8540.1,8348.9 v1(8540.1,8388.7) C3$CBB9/CBB14.1@8582,8388.7 8582,8349.2 R2$CBB9/CBB14.1@8581.5,8348.7 8540.3,8348.7 R1$CBB9/CBB14.1@8540.1,8348.9 ; R1$CBB9/CBB13.1@8540.1,8868.9 v1(8540.1,8908.7) C3$CBB9/CBB13.1@8582,8908.7 8582,8869.2 R2$CBB9/CBB13.1@8581.5,8868.7 8540.3,8868.7 R1$CBB9/CBB13.1@8540.1,8868.9 ; v1(8790.1,5768.7) 8790.6,5768.2 v1(8790.6,5728.7) R2$CBB19/CBB18.1@8831.5,5728.7 8832,5729.2 C3$CBB19/CBB18.1@8832,5768.7 v1(8790.1,5768.7) ; v1(8790.1,6553.7) 8790.6,6553.2 v1(8790.6,6513.7) R2$CBB19/CBB17.1@8831.5,6513.7 8832,6514.2 C3$CBB19/CBB17.1@8832,6553.7 v1(8790.1,6553.7) ; v1(8790.1,7073.7) 8790.6,7073.2 v1(8790.6,7033.7) R2$CBB19/CBB16.1@8831.5,7033.7 8832,7034.2 C3$CBB19/CBB16.1@8832,7073.7 v1(8790.1,7073.7) ; v1(8790.1,7858.7) 8790.6,7858.2 v1(8790.6,7818.7) R2$CBB19/CBB15.1@8831.5,7818.7 8832,7819.2 C3$CBB19/CBB15.1@8832,7858.7 v1(8790.1,7858.7) ; v1(8790.1,8643.7) 8790.6,8643.2 v1(8790.6,8603.7) R2$CBB19/CBB14.1@8831.5,8603.7 8832,8604.2 C3$CBB19/CBB14.1@8832,8643.7 v1(8790.1,8643.7) ; v1(8790.1,9163.7) 8790.6,9163.2 v1(8790.6,9123.7) R2$CBB19/CBB13.1@8831.5,9123.7 8832,9124.2 C3$CBB19/CBB13.1@8832,9163.7 v1(8790.1,9163.7) ; v1(9043.8,5728.7) v1(9043.8,5768.7) C3$CBB49/CBB24.1@9095.7,5768.7 9095.2,5768.2 R2$CBB49/CBB24.1@9095.2,5728.7 v1(9043.8,5728.7) ; v1(9043.8,5993.7) v1(9043.8,6033.7) C3$CBB49/CBB40.1@9095.7,6033.7 9095.2,6033.2 R2$CBB49/CBB40.1@9095.2,5993.7 v1(9043.8,5993.7) ; v1(9043.8,6513.7) v1(9043.8,6553.7) C3$CBB49/CBB23.1@9095.7,6553.7 9095.2,6553.2 R2$CBB49/CBB23.1@9095.2,6513.7 v1(9043.8,6513.7) ; v1(9043.8,7033.7) v1(9043.8,7073.7) C3$CBB49/CBB22.1@9095.7,7073.7 9095.2,7073.2 R2$CBB49/CBB22.1@9095.2,7033.7 v1(9043.8,7033.7) ; v1(9043.8,7818.7) v1(9043.8,7858.7) C3$CBB49/CBB21.1@9095.7,7858.7 9095.2,7858.2 R2$CBB49/CBB21.1@9095.2,7818.7 v1(9043.8,7818.7) ; v1(9043.8,8603.7) v1(9043.8,8643.7) C3$CBB49/CBB20.1@9095.7,8643.7 9095.2,8643.2 R2$CBB49/CBB20.1@9095.2,8603.7 v1(9043.8,8603.7) ; v1(9043.8,9123.7) v1(9043.8,9163.7) C3$CBB49/CBB19.1@9095.7,9163.7 9095.2,9163.2 R2$CBB49/CBB19.1@9095.2,9123.7 v1(9043.8,9123.7) ; R1$CBB9/CBB24.1@9048.8,5473.9 v1(9048.8,5513.7) C3$CBB9/CBB24.1@9090.7,5513.7 9090.7,5474.2 R2$CBB9/CBB24.1@9090.2,5473.7 9049,5473.7 R1$CBB9/CBB24.1@9048.8,5473.9 ; R1$CBB9/CBB23.1@9048.8,6258.9 v1(9048.8,6298.7) C3$CBB9/CBB23.1@9090.7,6298.7 9090.7,6259.2 R2$CBB9/CBB23.1@9090.2,6258.7 9049,6258.7 R1$CBB9/CBB23.1@9048.8,6258.9 ; R1$CBB9/CBB22.1@9048.8,6778.9 v1(9048.8,6818.7) C3$CBB9/CBB22.1@9090.7,6818.7 9090.7,6779.2 R2$CBB9/CBB22.1@9090.2,6778.7 9049,6778.7 R1$CBB9/CBB22.1@9048.8,6778.9 ; R1$CBB9/CBB21.1@9048.8,7563.9 v1(9048.8,7603.7) C3$CBB9/CBB21.1@9090.7,7603.7 9090.7,7564.2 R2$CBB9/CBB21.1@9090.2,7563.7 9049,7563.7 R1$CBB9/CBB21.1@9048.8,7563.9 ; R1$CBB9/CBB40.1@9048.8,8083.9 9049,8083.7 R2$CBB9/CBB40.1@9090.2,8083.7 9090.7,8084.2 C3$CBB9/CBB40.1@9090.7,8123.7 v1(9048.8,8123.7) R1$CBB9/CBB40.1@9048.8,8083.9 ; R1$CBB9/CBB20.1@9048.8,8348.9 v1(9048.8,8388.7) C3$CBB9/CBB20.1@9090.7,8388.7 9090.7,8349.2 R2$CBB9/CBB20.1@9090.2,8348.7 9049,8348.7 R1$CBB9/CBB20.1@9048.8,8348.9 ; R1$CBB9/CBB19.1@9048.8,8868.9 v1(9048.8,8908.7) C3$CBB9/CBB19.1@9090.7,8908.7 9090.7,8869.2 R2$CBB9/CBB19.1@9090.2,8868.7 9049,8868.7 R1$CBB9/CBB19.1@9048.8,8868.9 ; v1(9298.8,5768.7) 9299.3,5768.2 v1(9299.3,5728.7) R2$CBB19/CBB24.1@9340.2,5728.7 9340.7,5729.2 C3$CBB19/CBB24.1@9340.7,5768.7 v1(9298.8,5768.7) ; v1(9298.8,6553.7) 9299.3,6553.2 v1(9299.3,6513.7) R2$CBB19/CBB23.1@9340.2,6513.7 9340.7,6514.2 C3$CBB19/CBB23.1@9340.7,6553.7 v1(9298.8,6553.7) ; v1(9298.8,7073.7) 9299.3,7073.2 v1(9299.3,7033.7) R2$CBB19/CBB22.1@9340.2,7033.7 9340.7,7034.2 C3$CBB19/CBB22.1@9340.7,7073.7 v1(9298.8,7073.7) ; v1(9298.8,7858.7) 9299.3,7858.2 v1(9299.3,7818.7) R2$CBB19/CBB21.1@9340.2,7818.7 9340.7,7819.2 C3$CBB19/CBB21.1@9340.7,7858.7 v1(9298.8,7858.7) ; v1(9298.8,8643.7) 9299.3,8643.2 v1(9299.3,8603.7) R2$CBB19/CBB20.1@9340.2,8603.7 9340.7,8604.2 C3$CBB19/CBB20.1@9340.7,8643.7 v1(9298.8,8643.7) ; v1(9298.8,9163.7) 9299.3,9163.2 v1(9299.3,9123.7) R2$CBB19/CBB19.1@9340.2,9123.7 9340.7,9124.2 C3$CBB19/CBB19.1@9340.7,9163.7 v1(9298.8,9163.7) ; v1(9552.5,5728.7) R2$CBB49/CBB30.1@9603.9,5728.7 9603.9,5768.2 C3$CBB49/CBB30.1@9604.4,5768.7 v1(9552.5,5768.7) v1(9552.5,5728.7) ; v1(9552.5,5993.7) v1(9552.5,6033.7) C3$CBB49/CBB41.1@9604.4,6033.7 9603.9,6033.2 R2$CBB49/CBB41.1@9603.9,5993.7 v1(9552.5,5993.7) ; v1(9552.5,6513.7) R2$CBB49/CBB29.1@9603.9,6513.7 9603.9,6553.2 C3$CBB49/CBB29.1@9604.4,6553.7 v1(9552.5,6553.7) v1(9552.5,6513.7) ; v1(9552.5,7033.7) R2$CBB49/CBB28.1@9603.9,7033.7 9603.9,7073.2 C3$CBB49/CBB28.1@9604.4,7073.7 v1(9552.5,7073.7) v1(9552.5,7033.7) ; v1(9552.5,7818.7) R2$CBB49/CBB27.1@9603.9,7818.7 9603.9,7858.2 C3$CBB49/CBB27.1@9604.4,7858.7 v1(9552.5,7858.7) v1(9552.5,7818.7) ; v1(9552.5,8603.7) R2$CBB49/CBB26.1@9603.9,8603.7 9603.9,8643.2 C3$CBB49/CBB26.1@9604.4,8643.7 v1(9552.5,8643.7) v1(9552.5,8603.7) ; v1(9552.5,9123.7) v1(9552.5,9163.7) C3$CBB49/CBB25.1@9604.4,9163.7 9603.9,9163.2 R2$CBB49/CBB25.1@9603.9,9123.7 v1(9552.5,9123.7) ; R1$CBB9/CBB30.1@9557.5,5473.9 v1(9557.5,5513.7) C3$CBB9/CBB30.1@9599.4,5513.7 9599.4,5474.2 R2$CBB9/CBB30.1@9598.9,5473.7 9557.7,5473.7 R1$CBB9/CBB30.1@9557.5,5473.9 ; R1$CBB9/CBB29.1@9557.5,6258.9 v1(9557.5,6298.7) C3$CBB9/CBB29.1@9599.4,6298.7 9599.4,6259.2 R2$CBB9/CBB29.1@9598.9,6258.7 9557.7,6258.7 R1$CBB9/CBB29.1@9557.5,6258.9 ; R1$CBB9/CBB28.1@9557.5,6778.9 v1(9557.5,6818.7) C3$CBB9/CBB28.1@9599.4,6818.7 9599.4,6779.2 R2$CBB9/CBB28.1@9598.9,6778.7 9557.7,6778.7 R1$CBB9/CBB28.1@9557.5,6778.9 ; R1$CBB9/CBB27.1@9557.5,7563.9 v1(9557.5,7603.7) C3$CBB9/CBB27.1@9599.4,7603.7 9599.4,7564.2 R2$CBB9/CBB27.1@9598.9,7563.7 9557.7,7563.7 R1$CBB9/CBB27.1@9557.5,7563.9 ; R1$CBB9/CBB41.1@9557.5,8083.9 v1(9557.5,8123.7) C3$CBB9/CBB41.1@9599.4,8123.7 9599.4,8084.2 R2$CBB9/CBB41.1@9598.9,8083.7 9557.7,8083.7 R1$CBB9/CBB41.1@9557.5,8083.9 ; R1$CBB9/CBB26.1@9557.5,8348.9 v1(9557.5,8388.7) C3$CBB9/CBB26.1@9599.4,8388.7 9599.4,8349.2 R2$CBB9/CBB26.1@9598.9,8348.7 9557.7,8348.7 R1$CBB9/CBB26.1@9557.5,8348.9 ; R1$CBB9/CBB25.1@9557.5,8868.9 v1(9557.5,8908.7) C3$CBB9/CBB25.1@9599.4,8908.7 9599.4,8869.2 R2$CBB9/CBB25.1@9598.9,8868.7 9557.7,8868.7 R1$CBB9/CBB25.1@9557.5,8868.9 ; v1(9807.5,5768.7) 9808,5768.2 v1(9808,5728.7) R2$CBB19/CBB30.1@9848.9,5728.7 9849.4,5729.2 C3$CBB19/CBB30.1@9849.4,5768.7 v1(9807.5,5768.7) ; v1(9807.5,6553.7) 9808,6553.2 v1(9808,6513.7) R2$CBB19/CBB29.1@9848.9,6513.7 9849.4,6514.2 C3$CBB19/CBB29.1@9849.4,6553.7 v1(9807.5,6553.7) ; v1(9807.5,7073.7) 9808,7073.2 v1(9808,7033.7) R2$CBB19/CBB28.1@9848.9,7033.7 9849.4,7034.2 C3$CBB19/CBB28.1@9849.4,7073.7 v1(9807.5,7073.7) ; v1(9807.5,7858.7) 9808,7858.2 v1(9808,7818.7) R2$CBB19/CBB27.1@9848.9,7818.7 9849.4,7819.2 C3$CBB19/CBB27.1@9849.4,7858.7 v1(9807.5,7858.7) ; v1(9807.5,8643.7) 9808,8643.2 v1(9808,8603.7) R2$CBB19/CBB26.1@9848.9,8603.7 9849.4,8604.2 C3$CBB19/CBB26.1@9849.4,8643.7 v1(9807.5,8643.7) ; v1(9807.5,9163.7) 9808,9163.2 v1(9808,9123.7) R2$CBB19/CBB25.1@9848.9,9123.7 9849.4,9124.2 C3$CBB19/CBB25.1@9849.4,9163.7 v1(9807.5,9163.7) ; v1(10061.2,5728.7) v1(10061.2,5768.7) C3$CBB49/CBB36.1@10113.1,5768.7 10112.6,5768.2 R2$CBB49/CBB36.1@10112.6,5728.7 v1(10061.2,5728.7) ; v1(10061.2,5993.7) v1(10061.2,6033.7) C3$CBB49/CBB42.1@10113.1,6033.7 10112.6,6033.2 R2$CBB49/CBB42.1@10112.6,5993.7 v1(10061.2,5993.7) ; v1(10061.2,6513.7) v1(10061.2,6553.7) C3$CBB49/CBB35.1@10113.1,6553.7 10112.6,6553.2 R2$CBB49/CBB35.1@10112.6,6513.7 v1(10061.2,6513.7) ; v1(10061.2,7033.7) v1(10061.2,7073.7) C3$CBB49/CBB34.1@10113.1,7073.7 10112.6,7073.2 R2$CBB49/CBB34.1@10112.6,7033.7 v1(10061.2,7033.7) ; v1(10061.2,7818.7) v1(10061.2,7858.7) C3$CBB49/CBB33.1@10113.1,7858.7 10112.6,7858.2 R2$CBB49/CBB33.1@10112.6,7818.7 v1(10061.2,7818.7) ; v1(10061.2,8603.7) v1(10061.2,8643.7) C3$CBB49/CBB32.1@10113.1,8643.7 10112.6,8643.2 R2$CBB49/CBB32.1@10112.6,8603.7 v1(10061.2,8603.7) ; v1(10061.2,9123.7) v1(10061.2,9163.7) C3$CBB49/CBB31.1@10113.1,9163.7 10112.6,9163.2 R2$CBB49/CBB31.1@10112.6,9123.7 v1(10061.2,9123.7) ; R1$CBB9/CBB36.1@10066.2,5473.9 10066.4,5473.7 R2$CBB9/CBB36.1@10107.6,5473.7 10108.1,5474.2 C3$CBB9/CBB36.1@10108.1,5513.7 v1(10066.2,5513.7) R1$CBB9/CBB36.1@10066.2,5473.9 ; R1$CBB9/CBB35.1@10066.2,6258.9 10066.4,6258.7 R2$CBB9/CBB35.1@10107.6,6258.7 10108.1,6259.2 C3$CBB9/CBB35.1@10108.1,6298.7 v1(10066.2,6298.7) R1$CBB9/CBB35.1@10066.2,6258.9 ; R1$CBB9/CBB34.1@10066.2,6778.9 10066.4,6778.7 R2$CBB9/CBB34.1@10107.6,6778.7 10108.1,6779.2 C3$CBB9/CBB34.1@10108.1,6818.7 v1(10066.2,6818.7) R1$CBB9/CBB34.1@10066.2,6778.9 ; R1$CBB9/CBB33.1@10066.2,7563.9 10066.4,7563.7 R2$CBB9/CBB33.1@10107.6,7563.7 10108.1,7564.2 C3$CBB9/CBB33.1@10108.1,7603.7 v1(10066.2,7603.7) R1$CBB9/CBB33.1@10066.2,7563.9 ; R1$CBB9/CBB42.1@10066.2,8083.9 10066.4,8083.7 R2$CBB9/CBB42.1@10107.6,8083.7 10108.1,8084.2 C3$CBB9/CBB42.1@10108.1,8123.7 v1(10066.2,8123.7) R1$CBB9/CBB42.1@10066.2,8083.9 ; R1$CBB9/CBB32.1@10066.2,8348.9 10066.4,8348.7 R2$CBB9/CBB32.1@10107.6,8348.7 10108.1,8349.2 C3$CBB9/CBB32.1@10108.1,8388.7 v1(10066.2,8388.7) R1$CBB9/CBB32.1@10066.2,8348.9 ; R1$CBB9/CBB31.1@10066.2,8868.9 v1(10066.2,8908.7) C3$CBB9/CBB31.1@10108.1,8908.7 10108.1,8869.2 R2$CBB9/CBB31.1@10107.6,8868.7 10066.4,8868.7 R1$CBB9/CBB31.1@10066.2,8868.9 ; v1(10316.2,5768.7) 10316.7,5768.2 v1(10316.7,5728.7) R2$CBB19/CBB36.1@10357.6,5728.7 10358.1,5729.2 C3$CBB19/CBB36.1@10358.1,5768.7 v1(10316.2,5768.7) ; v1(10316.2,6553.7) 10316.7,6553.2 v1(10316.7,6513.7) R2$CBB19/CBB35.1@10357.6,6513.7 10358.1,6514.2 C3$CBB19/CBB35.1@10358.1,6553.7 v1(10316.2,6553.7) ; v1(10316.2,7073.7) 10316.7,7073.2 v1(10316.7,7033.7) R2$CBB19/CBB34.1@10357.6,7033.7 10358.1,7034.2 C3$CBB19/CBB34.1@10358.1,7073.7 v1(10316.2,7073.7) ; v1(10316.2,7858.7) 10316.7,7858.2 v1(10316.7,7818.7) R2$CBB19/CBB33.1@10357.6,7818.7 10358.1,7819.2 C3$CBB19/CBB33.1@10358.1,7858.7 v1(10316.2,7858.7) ; v1(10316.2,8643.7) 10316.7,8643.2 v1(10316.7,8603.7) R2$CBB19/CBB32.1@10357.6,8603.7 10358.1,8604.2 C3$CBB19/CBB32.1@10358.1,8643.7 v1(10316.2,8643.7) ; v1(10316.2,9163.7) 10316.7,9163.2 v1(10316.7,9123.7) R2$CBB19/CBB31.1@10357.6,9123.7 10358.1,9124.2 C3$CBB19/CBB31.1@10358.1,9163.7 v1(10316.2,9163.7)
  Top Layer w11.8: v1(6426.3,3512) 6426.3,3493.9 6464.4,3455.7 D17.1@6464.4,3431.3 ; v1(8444.2,5240.7) 8444.2,5214.2 C194$CBB9.1@8449.7,5208.6 ; v1(9424,5208.6) C197$CBB9.1@9465.7,5208.6 ; Q1$CBB23.2@9761.8,9657.3 v1(9809.5,9657.3) ; v1(9918,9657.3) Q3$CBB23.2@9962.6,9657.3
  Bottom Layer w4.7: v1(4259.8,4176.6) 4266.4,4183.2 R46.2@4330.8,4183.2 ; R80$CBB16.1@4669.6,6423.7 4669.6,6460.3 v1(4677.6,6468.3) ; C12.2@5679.3,4356.5 5679.5,4356.5 v2(5695.4,4340.7)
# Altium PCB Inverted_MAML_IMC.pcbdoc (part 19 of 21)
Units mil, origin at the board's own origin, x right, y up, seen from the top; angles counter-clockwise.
Board outline 7677.1 x 6771.6 mil, 6 copper layers (Top Layer, Inner1, Inner2, Inner3, Inner4, Bottom Layer), stack 60.7 mil thick; 2732 components, 1531 nets, 7765 pads, 3699 vias.

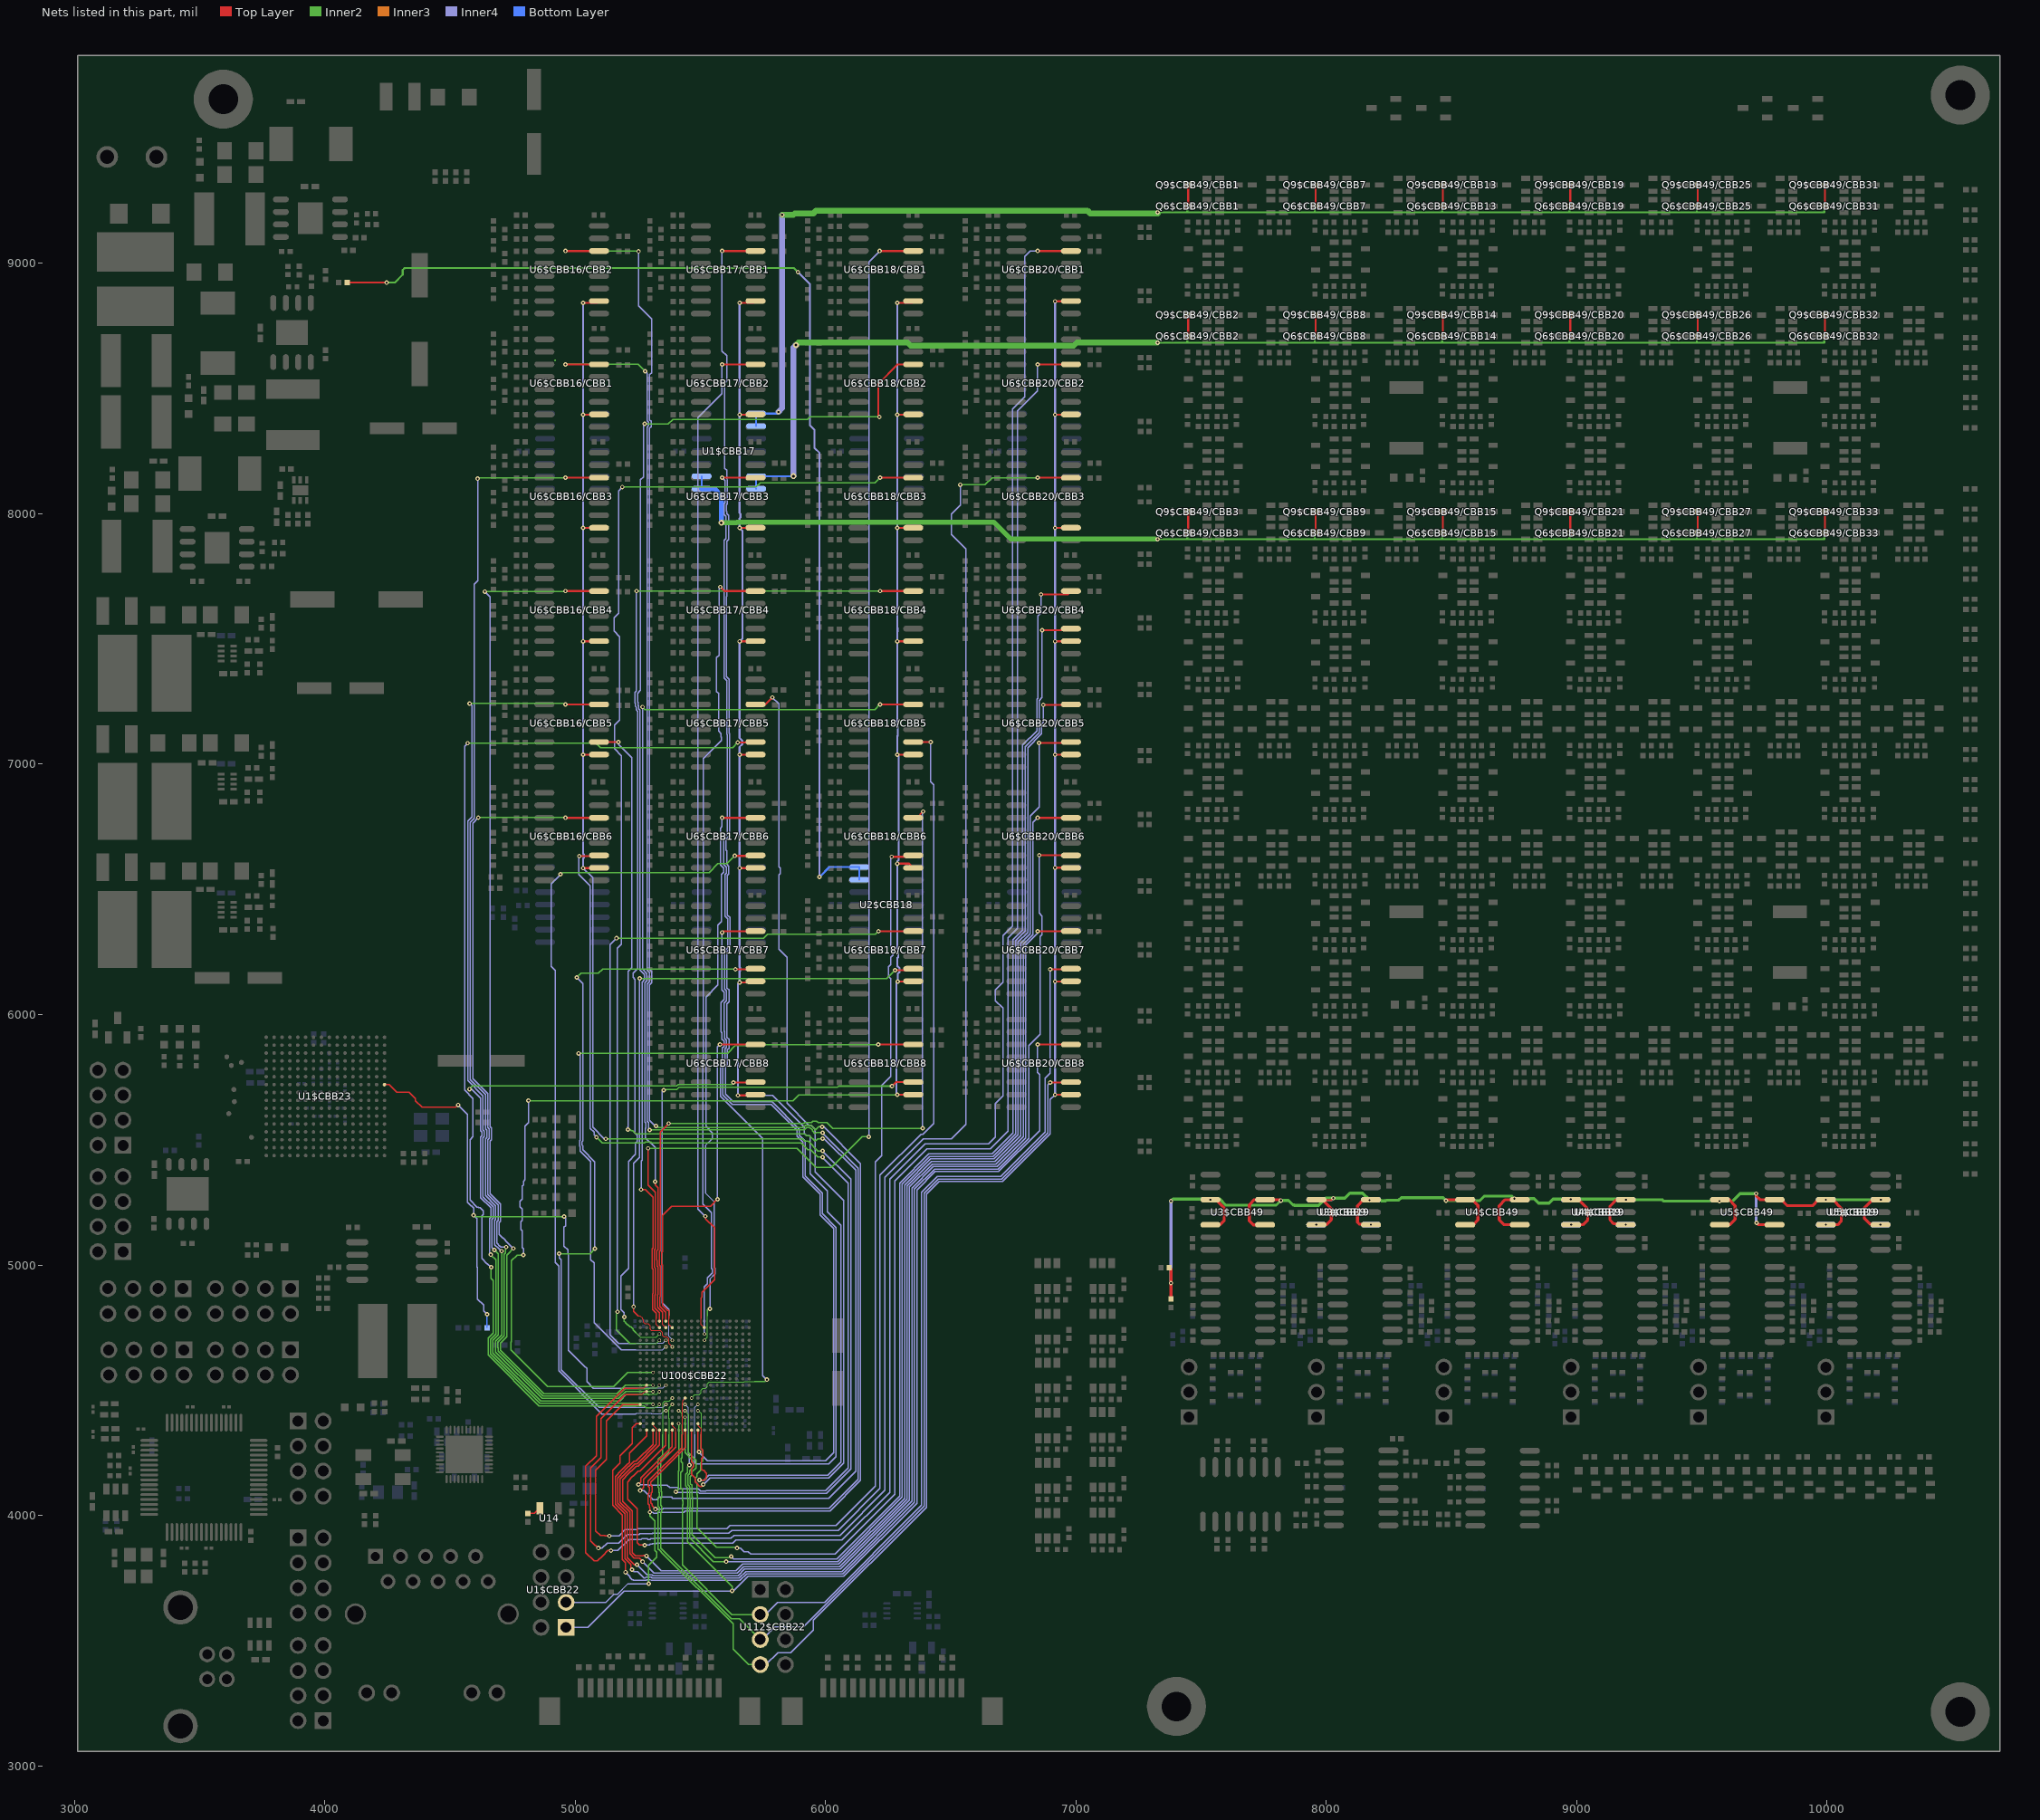
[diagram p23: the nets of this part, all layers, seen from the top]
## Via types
v1: diameter 17.7, hole 7.9, Top Layer to Bottom Layer, 3367 vias
v2: diameter 13.8, hole 7.9, Top Layer to Bottom Layer, 287 vias
v3: diameter 23.6, hole 11.8, Top Layer to Bottom Layer, 45 vias

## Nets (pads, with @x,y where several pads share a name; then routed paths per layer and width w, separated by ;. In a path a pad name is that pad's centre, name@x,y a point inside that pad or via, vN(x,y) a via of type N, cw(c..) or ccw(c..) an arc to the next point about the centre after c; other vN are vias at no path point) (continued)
SCK_DAC4_W(34): U6$CBB20/CBB4.11 U100$CBB22.C11 | length 5463.8
  Top Layer w7.9: v1(6865.4,7535.4) 6974.6,7535.4 U6$CBB20/CBB4.11@6980.5,7541.3
  Inner2 w4.7: v2(5439.5,4391.9) 5439.5,4249.8 5471.5,4217.8 5471.5,4208.6 5472.7,4207.4 5472.7,4194 5457.8,4179.1 5457.8,4166.6 5450.9,4159.6 5450.9,4122 5456.9,4116 5456.9,4115.6 5457.6,4114.9 5457.6,4114.7 5457.8,4114.4 5457.8,4070.7 5459.7,4068.9 5459.7,4031.3 5457.8,4029.4 5457.8,3910.2 5552.8,3815.2 v1(5603,3815.2)
  Inner4 w4.7: v1(5603,3815.2) 6049.1,3815.2 6306.6,4072.7 6306.6,5323.3 6416.9,5433.5 6670.2,5433.5 6759.6,5522.8 6759.6,6295 6797.7,6333.2 6797.7,7069.9 6853.9,7126.1 6853.9,7254.6 6865.4,7266.1 v1(6865.4,7535.4)
SCK_DAC5_DAC(2): U6$CBB16/CBB5.11 U100$CBB22.B13 | length 5100.6
  Top Layer w4.3: U100$CBB22.B13@5388.3,4366.3 5388.3,4358.5 5400.9,4345.9 5400.9,4331.5 5401.3,4331.2
  Top Layer w4.7: v1(5260.5,4099) 5273,4111.5 5273,4144.5 5401.3,4272.8 5401.3,4331.2
  Top Layer w7.9: U6$CBB16/CBB5.11@5095.7,7088.6 5095.8,7088.7 v1(5173.5,7088.7)
  Inner2 w4.7: v1(5210.7,5540.7) 5220.8,5540.7 5225.4,5536.1 5230.1,5536.1 5243.1,5523.1 5918,5523.1 5924.5,5516.6 5936.2,5516.6 5958.8,5493.9 5969.4,5504.4 v1(5988.5,5504.4)
  Inner4 w4.7: v1(5173.5,7088.7) 5173.5,7077.9 5225.9,7025.5 5225.9,6186.2 5212.4,6172.7 5212.4,5552.3 5210.7,5550.6 v1(5210.7,5540.7) ; v1(5260.5,4099) 5274.7,4099 5311.6,4062.1 5325.9,4062.1 5336.9,4073 5384.8,4073 5389.5,4068.3 5487.9,4068.3 5488.3,4067.8 5582.1,4067.8 5583,4068.7 6013.2,4068.7 6120.8,4176.3 6120.8,5379.1 5995.5,5504.4 v1(5988.5,5504.4)
SCK_DAC5_W(12): U6$CBB18/CBB5.11 U100$CBB22.G17 | length 5147.2
  Top Layer w4.3: 5250.9,4481.3 5251.2,4481.6 5265.6,4481.6 5278.2,4494.2 U100$CBB22.G17@5285.9,4494.2
  Top Layer w4.7: v1(5093,3869.4) 5082.8,3879.6 5080.3,3879.6 5062,3897.9 5062,4188.6 5104.1,4230.8 5104.1,4386.6 5198.8,4481.3 5250.9,4481.3
  Top Layer w7.9: U6$CBB18/CBB5.11@6350.6,7088.6 6350.7,7088.7 v1(6420.2,7088.7)
  Inner4 w4.7: v1(5093,3869.4) 5107.9,3869.4 5128.3,3889.8 5174.4,3889.8 5208.1,3923.5 5255.6,3923.5 5259,3926.8 5308.1,3926.8 5309.4,3928 5614.2,3928 5626.2,3940.1 6050.2,3940.1 6218.1,4107.9 6218.1,5358.5 6382.2,5522.6 6388.9,5522.6 6432.3,5566 6432.3,6917.3 6420.2,6929.4 v1(6420.2,7088.7)
SCK_DAC5_W(15): U6$CBB17/CBB5.11 U100$CBB22.E15 | length 4470.9
  Top Layer w7.9: v1(5649.8,7086.7) 5718.8,7086.7 U6$CBB17/CBB5.11@5720.7,7088.6
  Inner2 w3.9: 5295.8,4429.2 5296.9,4430.2 5316.8,4430.2 5318.2,4431.6 5325.7,4431.6 v2(5337.1,4443)
  Inner2 w4.7: v1(4571.5,7084) 5083,7084 5101.1,7065.9 5629,7065.9 v1(5649.8,7086.7) ; v1(4664.8,4991.2) 4664.8,4946.2 4673.4,4937.6 4673.4,4728.1 4652.9,4707.6 4652.9,4640.3 4855.6,4437.6 5275.7,4437.6 5283.8,4429.6 5295.4,4429.6 5295.8,4429.2
  Inner4 w4.7: v1(4571.5,7084) 4558.9,7071.4 4558.9,5698.5 4592.8,5664.7 4592.8,5513.1 4580.3,5500.6 4580.3,5259.6 4609,5230.9 4613.8,5230.9 4615.9,5228.9 4621.3,5228.9 4634.2,5215.9 4634.2,5202.5 4628.3,5196.6 4628.3,5056.2 4627.9,5055.7 4627.9,5026.2 4648.8,5005.3 4649.6,5005.3 4663.7,4991.2 v1(4664.8,4991.2)
SCK_DAC5_W(34): U6$CBB20/CBB5.11 U100$CBB22.B16 | length 5383.8
  Top Layer w4.3: U100$CBB22.B16@5311.5,4366.3 5311.5,4358.5 5324.1,4345.9 5324.1,4331.5 5324.5,4331.2
  Top Layer w4.7: v1(5269.7,3815.2) 5263.7,3821.2 5263.7,3821.8 5256.5,3829 5236.4,3829 5218.5,3846.9 5218.5,4013.9 5180.3,4052 5180.3,4146 5192.1,4157.8 5192.1,4159.2 5218.7,4185.8 5220.1,4185.8 5239.9,4205.6 5247.7,4205.6 5324.5,4282.4 5324.5,4331.2
  Top Layer w7.9: v1(6853.4,7084.7) 6976.6,7084.7 U6$CBB20/CBB5.11@6980.5,7088.6
  Inner4 w4.7: v1(5269.7,3815.2) 5315.6,3769.3 5647.2,3769.3 5673.2,3795.3 6056.7,3795.3 6326.1,4064.6 6326.1,5315.2 6423.3,5412.5 6676.7,5412.5 6779.6,5515.4 6779.6,6284.2 6818.1,6322.7 6818.1,6793.1 6853.4,6828.4 v1(6853.4,7084.7)
SCK_DAC6_DAC(2): U6$CBB16/CBB6.11 U100$CBB22.A13 | length 4616.9
  Top Layer w4.7: v1(5253.4,4122.7) 5263.3,4132.6 5263.3,4148.5 5388.3,4273.6 U100$CBB22.A13@5388.3,4340.7
  Top Layer w7.9: v1(5016.9,6632.6) 5092.5,6632.6 U6$CBB16/CBB6.11@5095.7,6635.8
  Inner2 w4.7: v1(5085.4,5510.3) 5108.3,5487.4 5276.9,5487.4 5281.1,5491.6 5302.6,5491.6 5306.7,5487.4 5902.4,5487.4 5929.8,5459.9 5940.7,5459.9 5969.7,5430.9 v1(5988.5,5430.9)
  Inner4 w4.7: v1(5016.9,6632.6) 5015.9,6631.6 5015.9,6558.7 5060.6,6514.1 5060.6,5546 5076.4,5530.2 5076.4,5519.3 v1(5085.4,5510.3) ; v1(5253.4,4122.7) 5289.5,4122.7 5291.8,4120.4 5368,4120.4 5377.6,4110.8 5408.6,4110.8 5413.7,4105.7 5492.5,4105.7 5501.2,4097 5522.7,4097 5523.5,4097.9 6000.8,4097.9 6091.7,4188.7 6091.7,5326.4 5988.5,5429.5 v1(5988.5,5430.9)
SCK_DAC6_W(12): U6$CBB18/CBB6.11 U100$CBB22.E18 | length 4469.9
  Top Layer w4.7: v1(5137.3,3918) 5120.5,3918 5118.8,3919.7 5100.9,3919.7 5082.8,3937.8 5082.8,4180.9 5124.9,4223 5124.9,4377.9 5190,4443 U100$CBB22.E18@5260.4,4443
  Top Layer w7.9: v1(6264.5,6630.2) 6345,6630.2 U6$CBB18/CBB6.11@6350.6,6635.8
  Inner4 w4.7: v1(5137.3,3918) 5175.1,3918 5200,3942.9 5247.6,3942.9 5250.9,3946.3 5300.1,3946.2 5301.3,3947.5 5606.1,3947.5 5618.2,3959.5 6042.2,3959.5 6198.6,4116 6198.6,5411.3 6223.8,5436.4 6223.8,5717.2 6259.9,5753.4 6259.9,6144 6252.1,6151.8 6252.1,6191.3 6260.4,6199.6 6260.4,6229 6269.3,6237.9 6269.3,6250.7 6260.4,6259.6 6260.4,6626.2 v1(6264.5,6630.2)
SCK_DAC6_W(15): U6$CBB17/CBB6.11 U100$CBB22.D14 | length 3325.8
  Top Layer w7.9: v1(5637.7,6633.9) 5718.8,6633.9 U6$CBB17/CBB6.11@5720.7,6635.8
  Inner2 w4.7: v1(4942.2,6560.1) 4949.7,6567.6 5536.4,6567.6 5570.9,6602.1 5605.9,6602.1 v1(5637.7,6633.9)
  Inner4 w3.9: 5242,4405.1 5242.4,4405.5 5305.4,4405.5 5306.2,4404.6 5342.4,4404.6 5355.2,4417.4 v2(5362.7,4417.4)
  Inner4 w4.7: v1(4942.2,6560.1) 4904.3,6522.2 4904.3,6192.5 4920.4,6176.4 4920.4,5009.8 4935.4,4994.8 4935.4,4577.2 5107.5,4405.1 5242,4405.1
SCK_DAC6_W(34): U6$CBB20/CBB6.11 U100$CBB22.B18 | length 5045
  Top Layer w4.7: v1(5201.5,3773) 5201.5,3811.7 5189.3,3823.9 5189.3,4001.8 5151.1,4040 5151.1,4180.5 5179.2,4208.5 5179.2,4238.7 5227.7,4287.2 5227.7,4349.4 5244.6,4366.3 U100$CBB22.B18@5260.4,4366.3
  Top Layer w7.9: v1@6853.4,6635.9 6980.4,6635.9 U6$CBB20/CBB6.11@6980.5,6635.8
  Inner4 w4.7: v1(5201.5,3773) 5219.4,3755.1 5219.4,3752.2 5228.9,3742.7 5231.7,3742.7 5234.3,3740.1 5284.2,3740.1 5287.1,3743 5300.5,3743 5303.5,3740.1 5659.3,3740.1 5685.3,3766.1 6068.8,3766.1 6355.2,4052.5 6355.2,5303.1 6435.4,5383.3 6688.8,5383.3 6811.8,5506.3 6811.8,5875.2 6858,5921.4 6858,6311.4 6865.5,6319 6865.5,6393.8 6853.9,6405.3 v1(6853.9,6636.2)
SCK_DAC7_W(12): U6$CBB18/CBB7.11 U100$CBB22.P13 | length 2693.5
  Top Layer w3.9: 5252.4,4796.2 5253.7,4795 5261.7,4795 5269.7,4787 5269.7,4784.4 5273.1,4781 5273.1,4771 5280.8,4763.3 5293.4,4763.3 5298.7,4758 5298.7,4745.4 5306.8,4737.3 5316.8,4737.3 5317.4,4736.8 5331.3,4736.8 5331.8,4737.3 5342.4,4737.3 5349.9,4729.8 5349.9,4719.2 5357.4,4711.7 5368,4711.7 5375.5,4704.2 5375.5,4686.1 v2(5388.3,4673.3)
  Top Layer w4.7: v1(5233.6,4833.1) 5233.6,4815.1 5252.4,4796.2
  Top Layer w7.9: v1(6278,6177.4) 6345,6177.4 U6$CBB18/CBB7.11@6350.6,6183.1
  Inner2 w4.7: v1(5257.7,6144.1) 6244.7,6144.1 v1(6278,6177.4)
  Inner4 w4.7: 5233.6,5333.1 5233.6,5405.4 5257.7,5429.5 v1(5257.7,6144.1)
  Inner4 w5.5: v1(5233.6,4833.1) 5233.6,5333.1
SCK_DAC7_W(15): U6$CBB17/CBB7.11 U100$CBB22.E14 | length 2949.3
  Top Layer w7.9: v1(5640.6,6181.2) 5718.8,6181.2 U6$CBB17/CBB7.11@5720.7,6183.1
  Inner2 w4.7: v1(4936.6,5045) 5059.4,5045 v1(5079.1,5064.8) ; v1(5006.7,6148.3) 5023.8,6165.4 5093.6,6165.4 5110.6,6182.4 5155.3,6182.4 5156.6,6181.2 v1(5640.6,6181.2)
  Inner4 w3.9: 5242,4430.7 5243.1,4429.6 5305.6,4429.6 5306.2,4430.2 5342.4,4430.2 5343.1,4429.6 5349.3,4429.6 v2(5362.7,4443)
  Inner4 w4.7: v1(4936.6,5045) 4936.6,5028.8 4945.1,5020.3 4945.1,4581.5 5095.9,4430.7 5242,4430.7 ; v1(5006.7,6148.3) 5030.5,6124.5 5030.5,5852.2 5030.8,5851.8 5030.8,5838.4 5030.5,5838.1 5030.5,5494.3 5028.2,5492 5028.2,5478.6 5030.5,5476.3 5030.5,5459.6 5079.1,5411 v1(5079.1,5064.8)
SCK_DAC7_W(34): U6$CBB20/CBB7.11 U100$CBB22.D12 U112$CBB22.3 | length 4436.2
  Top Layer w7.9: v1(6897.5,6181.1) 6978.6,6181.1 U6$CBB20/CBB7.11@6980.5,6183.1
  Inner2 w3.9: v2(5413.9,4417.4) 5416.3,4417.4 5426.3,4407.5 5426.3,4397.5 5426.7,4397.2 5426.7,4361 5426.3,4360.6 5426.3,4322.6 5426.7,4322.3
  Inner2 w4.7: 5426.9,4322.1 5426.9,4230.2 5424.2,4227.5 5424.2,4214 5428.3,4209.9 5428.3,4178.3 5421.7,4171.7 5421.7,4110 5427.8,4103.9 5427.8,4103.5 5428.3,4102.9 5428.3,4059 5430.5,4056.8 5430.5,4043.4 5428.3,4041.2 5428.3,3802.8 5627,3604.1 U112$CBB22.3@5739.8,3604.1
  Inner4 w4.7: U112$CBB22.3@5739.8,3604.1 5759.4,3604.1 5808.1,3652.8 5996.8,3652.8 6384.4,4040.5 6384.4,5291 6446.6,5353.2 6699.9,5353.2 6878,5531.3 6878,5746.7 6897.5,5766.2 v1(6897.5,6181.1)
SCK_DAC8_W(12): U6$CBB18/CBB8.11 U100$CBB22.R13 | length 2031.1
  Top Layer w7.9: v1(6265.9,5714.3) 6282.3,5730.7 6350.2,5730.7 U6$CBB18/CBB8.11@6350.6,5730.3
  Inner2 w5.5: v1(5354.4,5698.4) 5356.5,5700.6 5406.3,5700.6 5416.3,5710.6 6048.8,5710.6 6052.4,5714.3 v1(6265.9,5714.3)
  Inner4 w3.9: 5375.5,4796.2 5375.5,4715.3 5388.3,4702.5 v2(5388.3,4698.9)
  Inner4 w4.7: v1(5354.4,5698.4) 5348.2,5692.2 5348.2,5050.7 5346.2,5048.7 5346.2,5027.2 5347.7,5025.7 5346.6,5024.6 5346.6,5003.1 5348.2,5001.5 5348.2,4849 5375.5,4821.7 5375.5,4796.2
SCK_DAC8_W(15): U6$CBB17/CBB8.11 U100$CBB22.E16 | length 3010.6
  Top Layer w7.9: v1(5633,5728.4) 5718.8,5728.4 U6$CBB17/CBB8.11@5720.7,5730.3
  Inner2 w4.7: v1(4578.2,5702.2) 4590.5,5714.6 5406,5714.6 5412.1,5720.7 5625.3,5720.7 v1(5633,5728.4) ; v1(4663.6,5041) 4663.6,5039.7 4683.3,5020 4683.3,4724.2 4662.6,4703.5 4662.6,4644.4 4859.6,4447.3 5307.2,4447.3 v2(5311.5,4443)
  Inner4 w4.7: v1(4578.2,5702.2) 4587.4,5702.2 4622.4,5667.2 4622.4,5536 4628,5530.5 4628,5517 4622.4,5511.5 4622.4,5268.9 4663.4,5228 4663.4,5190.4 4658.6,5185.6 4658.6,5045.9 v1(4663.6,5041)
SCK_DAC8_W(34): U6$CBB20/CBB8.11 U100$CBB22.E13 U112$CBB22.5 | length 4157.3
  Top Layer w7.9: v1(6897.5,5728.4) 6978.6,5728.4 U6$CBB20/CBB8.11@6980.5,5730.3
  Inner2 w3.9: 5375.5,4322.1 5376.1,4322.7 5376.1,4385.9 5375.5,4386.6 5375.5,4422.7 5376.1,4423.4 5376.1,4430.9 v2(5388.3,4443)
  Inner2 w4.7: 5375.5,4322.1 5375.5,4252.2 5342,4218.7 5342,4115.4 5344.3,4113 5344.3,4095.5 5346.3,4093.5 5346.3,4072 5342,4067.7 5342,4040.3 5346.7,4035.6 5346.7,4014.1 5342,4009.4 5342,3869.9 5353.9,3858 5353.9,3857.5 5625.1,3586.3 5657.6,3586.3 U112$CBB22.5@5739.8,3504.1
  Inner4 w4.7: U112$CBB22.5@5739.8,3504.1 5747.8,3504.1 5797.8,3554.1 5911.8,3554.1 6394.1,4036.4 6394.1,5287 6450.5,5343.4 6703.9,5343.4 6887.8,5527.3 6887.8,5718.7 v1(6897.5,5728.4)
SCLR#_DAC(2): U6$CBB16/CBB1.10 U6$CBB16/CBB2.10 U6$CBB16/CBB3.10 U6$CBB16/CBB4.10 U6$CBB16/CBB5.10 U6$CBB16/CBB6.10 U100$CBB22.B12 | length 6991.9
  Top Layer w7.9: v1(5032.1,6585) 5094.8,6585 U6$CBB16/CBB6.10@5095.7,6585.8 ; v1(5032.1,7037.7) 5094.8,7037.7 U6$CBB16/CBB5.10@5095.7,7038.6 ; v1(5032.1,7490.5) 5094.8,7490.5 U6$CBB16/CBB4.10@5095.7,7491.3 ; v1(5032.1,7943.2) 5094.8,7943.2 U6$CBB16/CBB3.10@5095.7,7944.1 ; v1(5032.1,8396) 5094.8,8396 U6$CBB16/CBB1.10@5095.7,8396.8 ; v1(5032.1,8842.7) 5088.8,8842.7 U6$CBB16/CBB2.10@5095.7,8849.6
  Inner2 w4.7: v1(5123,5503.6) 5907.8,5503.6 5917.6,5493.9 5931.3,5493.9 5969.7,5455.5 v1(5988.5,5455.5) ; v1(5402.2,4094.3) 5412,4104 5412,4175.8 5414.3,4178 5414.3,4365.9 v2(5413.9,4366.3)
  Inner4 w4.7: v1(5032.1,6585) 5070.3,6546.8 5070.3,5550 5116.7,5503.6 v1(5123,5503.6) ; v1(5402.2,4094.3) 5405,4091.5 5492.9,4091.5 5497.2,4087.3 5526.7,4087.3 5527.6,4088.1 6004.8,4088.1 6101.4,4184.7 6101.4,5342.7 v1(5988.5,5455.5)
  Inner4 w7.9: v1(5032.1,6585) 5032.1,6622.7 5034.7,6625.2 5034.7,6640 5032.1,6642.5 v1(5032.1,7037.7) v1(5032.1,7490.5) v1(5032.1,7943.2) 5032.1,7984.3 5032.7,7984.8 5032.7,7999.6 5032.1,8000.1 v1(5032.1,8396) v1(5032.1,8842.7)
SCLR#_DAC_W(12): U6$CBB18/CBB1.10 U6$CBB18/CBB2.10 U6$CBB18/CBB3.10 U6$CBB18/CBB4.10 U6$CBB18/CBB5.10 U6$CBB18/CBB6.10 U6$CBB18/CBB7.10 U6$CBB18/CBB8.10 U100$CBB22.K16 | length 6890
  Top Layer w7.9: v1(6287,5679.4) 6349.7,5679.4 U6$CBB18/CBB8.10@6350.6,5680.3 ; v1(6287,6602.7) 6333.7,6602.7 U6$CBB18/CBB6.10@6350.6,6585.8 ; v1(6287,7038) 6350,7038 U6$CBB18/CBB5.10@6350.6,7038.6 ; v1(6287,7490.5) 6349.7,7490.5 U6$CBB18/CBB4.10@6350.6,7491.3 ; v1(6287,7943.2) 6349.7,7943.2 U6$CBB18/CBB3.10@6350.6,7944.1 ; v1(6287,8396) 6349.7,8396 U6$CBB18/CBB2.10@6350.6,8396.8 ; v1(6287,8842.7) 6343.7,8842.7 U6$CBB18/CBB1.10@6350.6,8849.6 ; v1(6289.3,6132.2) 6349.7,6132.2 U6$CBB18/CBB7.10@6350.6,6133.1
  Inner2 w4.7: v1(4793.9,5039.6) 4768.5,5039.6 4746.4,5017.5 4746.4,4694.2 4744,4691.8 4744.4,4691.5 4744.4,4670 4743.7,4669.2 4743.7,4661.4 4889.7,4515.4 5154.8,4515.4 5210.4,4571 v2(5311.5,4571) ; v1(4814.1,5656.4) 5870.1,5656.4 5893.1,5679.4 v1(6287,5679.4)
  Inner4 w4.7: v1(4793.9,5039.6) 4793.9,5065 4788.5,5070.4 4788.5,5136.9 4782.8,5142.6 4782.8,5172.1 4788.5,5177.8 4788.5,5224.2 4780,5232.7 4780,5254.2 4788.5,5262.7 4788.5,5314.8 4793.7,5320.1 4793.7,5333.8 4800.2,5340.3 4800.2,5554.6 4814.1,5568.5 v1(4814.1,5656.4)
  Inner4 w7.9: v1(6287,5679.4) 6283.7,5682.8 6283.7,6126.6 v1(6289.3,6132.2) 6289.3,6163.5 6295.8,6170.1 6295.8,6184.8 6287,6193.6 6287,6225.9 6290.4,6229.2 6290.4,6259.4 6287,6262.7 v1(6287,6602.7) 6287,6612.5 6292,6617.5 6292,7033 v1(6287,7038) 6287,7111.8 6288.7,7113.4 6288.7,7158.9 6287,7160.6 v1(6287,7490.5) 6287,7529.1 6287.7,7529.8 6287.7,7544.5 6287,7545.1 v1(6287,7943.2) v1(6287,8396) v1(6287,8842.7)
SCLR#_DAC_W(15): U6$CBB17/CBB1.10 U6$CBB17/CBB2.10 U6$CBB17/CBB3.10 U6$CBB17/CBB4.10 U6$CBB17/CBB5.10 U6$CBB17/CBB6.10 U6$CBB17/CBB7.10 U6$CBB17/CBB8.10 U100$CBB22.B9 | length 6304.1
  Top Layer w4.3: U100$CBB22.B9@5490.7,4366.3 5490.7,4358.5 5503.3,4345.9 5503.3,4331.5 5503.6,4331.2
  Top Layer w4.7: v1(5496.3,4140.8) 5516.1,4140.8 5523.7,4148.4 5523.7,4152.5 5525.7,4154.5 5525.7,4167.9 5514.2,4179.4 5509.8,4179.4 5504.6,4184.6 5504.6,4226.8 5510.8,4233 5510.8,4259.6 5503.6,4266.8 5503.6,4331.2
  Top Layer w7.9: v1(5650.8,5677.1) 5717.5,5677.1 U6$CBB17/CBB8.10@5720.7,5680.3 ; v1(5657.1,6127.9) 5715.5,6127.9 U6$CBB17/CBB7.10@5720.7,6133.1 ; v1(5657.1,6585) 5719.8,6585 U6$CBB17/CBB6.10@5720.7,6585.8 ; v1(5657.1,7037.7) 5719.8,7037.7 U6$CBB17/CBB5.10@5720.7,7038.6 ; v1(5657.1,7490.5) 5719.8,7490.5 U6$CBB17/CBB4.10@5720.7,7491.3 ; v1(5657.1,7943.2) 5719.8,7943.2 U6$CBB17/CBB3.10@5720.7,7944.1 ; v1(5657.1,8396) 5719.8,8396 U6$CBB17/CBB2.10@5720.7,8396.8 ; v1(5657.1,8842.7) 5713.8,8842.7 U6$CBB17/CBB1.10@5720.7,8849.6
  Inner4 w4.7: v1(5496.3,4140.8) 5516.1,4140.8 5534.7,4159.5 6008.7,4159.5 6062.5,4213.3 6062.5,5157.9 6007.7,5212.7 6007.7,5295 5938.7,5364 5938.7,5515.9 5937.9,5516.6 5924.5,5516.6 5915,5526.1 5915,5550.3 5788.2,5677.1 v1(5650.8,5677.1)
  Inner4 w7.9: v1(5650.8,5677.1) 5650.8,6121.6 v1(5657.1,6127.9) 5657.1,6172.5 5658.4,6173.8 5658.4,6188.5 5657.1,6189.8 v1(5657.1,6585) v1(5657.1,7037.7) 5657.1,7068.9 5667.6,7079.3 5667.6,7094 5657.1,7104.5 v1(5657.1,7490.5) 5668.7,7502.1 5668.7,7931.6 v1(5657.1,7943.2) 5657.1,7981.4 5660.6,7984.8 5660.6,7999.5 5657.1,8003 v1(5657.1,8396) v1(5657.1,8842.7)
SCLR#_DAC_W(34): U6$CBB20/CBB1.10 U6$CBB20/CBB2.10 U6$CBB20/CBB3.10 U6$CBB20/CBB4.10 U6$CBB20/CBB5.10 U6$CBB20/CBB6.10 U6$CBB20/CBB7.10 U6$CBB20/CBB8.10 U100$CBB22.F13 U112$CBB22.7 | length 7937.6
  Top Layer w7.9: v1(6917,5679.4) 6979.7,5679.4 U6$CBB20/CBB8.10@6980.5,5680.3 ; v1(6917,6132.2) 6979.7,6132.2 U6$CBB20/CBB7.10@6980.5,6133.1 ; v1(6917,6586.4) 6980,6586.4 U6$CBB20/CBB6.10@6980.5,6585.8 ; v1(6917,7038) 6979.9,7038 U6$CBB20/CBB5.10@6980.5,7038.6 ; v1(6917,7490.5) 6979.7,7490.5 U6$CBB20/CBB4.10@6980.5,7491.3 ; v1(6917,7943.2) 6979.7,7943.2 U6$CBB20/CBB3.10@6980.5,7944.1 ; v1(6917,8396) 6979.7,8396 U6$CBB20/CBB2.10@6980.5,8396.8 ; v1(6917,8848.7) 6979.7,8848.7 U6$CBB20/CBB1.10@6980.5,8849.6
  Inner2 w3.9: 5350,4322.1 5350,4386.4 5349.9,4386.6 5349.9,4448.3 5357.4,4455.8 5375.5,4455.8 v2(5388.3,4468.6)
  Inner2 w4.7: 5350,4322.1 5350,4240.5 5332.3,4222.8 5332.3,4111.3 5334.6,4109 5334.6,4091.5 5336.6,4089.5 5336.6,4076.1 5332.3,4071.7 5332.3,4036.3 5337,4031.6 5337,4018.2 5332.3,4013.5 5332.3,3865.3 5334.1,3863.5 5334.7,3863.5 5344.2,3854 5344.2,3853.5 5631.1,3566.5 5631.1,3465.8 5692.8,3404.1 U112$CBB22.7@5739.8,3404.1
  Inner4 w4.7: U112$CBB22.7@5739.8,3404.1 5762.2,3404.1 5809.8,3451.7 5862,3451.7 5952.4,3542.1 5952.4,3581 6404.2,4032.7 6404.2,5283.3 6454,5333.1 6707.4,5333.1 6898.1,5523.9 6898.1,5660.6 v1(6917,5679.4)
  Inner4 w7.9: v1(6917,5679.4) v1(6917,6132.2) v1(6917,6586.4) v1(6917,7038) v1(6917,7490.5) v1(6917,7943.2) v1(6917,8396) v1(6917,8848.7)
SI_DAC1_DAC(2): U6$CBB16/CBB1.14 U100$CBB22.A11 | length 6906.5
  Top Layer w4.7: v1(5320.8,4024.9) 5307.4,4038.2 5307.4,4044.5 5302.2,4049.8 5302.2,4081 5304.2,4083 5304.2,4089.5 5307.4,4092.7 5307.4,4115.8 5302.2,4121 5302.2,4132.4 5439.5,4269.7 U100$CBB22.A11@5439.5,4340.7
  Top Layer w7.9: v1(4962.1,8596.8) U6$CBB16/CBB1.14@5095.7,8596.8
  Inner2 w4.7: v1(4962.1,8596.8) 5252.7,8596.8 v1(5279.8,8569.8) ; v1(5297.8,5539.3) 5914.8,5539.3 5924.5,5549 5937.9,5549 5947.4,5539.5 5947.4,5535.7 5957.1,5526 5961.1,5526 5963.3,5528.1 v1(5988.5,5528.1)
  Inner4 w4.7: v1(5279.8,8569.8) 5287.8,8561.8 5287.8,8371.9 5294,8365.7 5294,8352.3 5287.8,8346.1 5287.8,6177 5296.3,6168.4 5296.3,6131.4 5287.8,6122.8 5287.8,5574.1 5293.8,5568 5293.8,5543.3 v1(5297.8,5539.3) ; v1(5320.8,4024.9) 5350.4,4024.9 5353.4,4027.8 6014.2,4027.8 6130.6,4144.2 6130.6,5385.9 5988.5,5527.9 v1(5988.5,5528.1)
SI_DAC1_W(12): U6$CBB18/CBB1.14 U100$CBB22.V15 | length 5366.4
  Top Layer w4.7: v1(5291.8,5465.6) 5291.8,5319.1 5320.9,5290 5320.9,5064.6 5317,5060.8 5317,5015.1 5317.5,5014.7 5317.5,4991 5320.9,4987.6 5320.9,4885.6 5320.6,4885.4 5320.6,4881.5 5319.6,4880.5 5319.6,4826.8 5337.1,4809.2 U100$CBB22.V15@5337.1,4775.7
  Top Layer w7.9: v1(6217,9049.6) U6$CBB18/CBB1.14@6350.6,9049.6
  Inner2 w4.7: v1(5291.8,5465.6) 5886.1,5465.6 5962.4,5389.3 6024.7,5389.3 6147.2,5511.8 v1(6173.3,5511.8)
  Inner4 w4.7: v1(6173.3,5511.8) 6173.3,9005.8 v1(6217,9049.6)
SI_DAC1_W(15): U6$CBB17/CBB1.14 U100$CBB22.E9 | length 6108
  Top Layer w7.9: v1(5587.1,9049.6) U6$CBB17/CBB1.14@5720.7,9049.6
  Inner4 w3.9: 5478.5,4322.1 5478.5,4385.9 5477.9,4386.6 5477.9,4422.7 5478.5,4423.4 5478.5,4430.9 v2(5490.7,4443)
  Inner4 w4.7: 5478.5,4322.1 5478.5,4259.8 5478.4,4259.6 5478.4,4246.2 5478.5,4246 5478.5,4209.4 5483.3,4204.7 6012.6,4204.7 6042.8,4234.8 6042.8,5150.1 5988.2,5204.6 5988.2,5286.9 5919.2,5356 5919.2,5494.4 5895.6,5518 5895.6,5542.3 5786.6,5651.2 5631.7,5651.2 5600.4,5682.5 5600.4,5790.9 5608.4,5798.9 5608.4,5859.1 5614.4,5865.2 5614.4,5901.4 5606.4,5909.4 5606.4,5935.5 5605.7,5936.3 5605.7,6043.1 5614.4,6051.9 5614.4,6098.1 5606.6,6106 5606.6,6250.5 5618.8,6262.7 5618.8,6387.3 5608.7,6397.3 5608.7,6556.3 5613.5,6561 5613.5,6593 5605.7,6600.9 5605.7,6653.7 5602.7,6656.6 5602.7,6700.2 5617.3,6714.7 5617.3,7121.5 5615.8,7123 5615.8,7338.3 5604.7,7349.3 5604.7,7669.3 5605.7,7670.3 5605.7,7890.1 5612.8,7897.2 5612.8,7993.6 5605.7,8000.7 5605.7,8009 5604.7,8009.9 5604.7,8035.7 5608.7,8039.7 5608.7,8136.2 5605.7,8139.3 5605.7,8173.6 5597,8182.3 5597,8521 5605.7,8529.6 5605.7,8631.4 5587.1,8650 v1(5587.1,9049.6)
SI_DAC1_W(34): U6$CBB20/CBB1.14 U100$CBB22.A14 | length 7160.7
  Top Layer w4.7: v1(5277.8,3881.4) 5257.7,3881.4 5247.6,3891.5 5247.6,4026 5209.5,4064.1 5209.5,4133.9 5221.3,4145.7 5221.3,4147.1 5230.8,4156.6 5232.1,4156.6 5252,4176.5 5259.8,4176.5 5362.7,4279.3 U100$CBB22.A14@5362.7,4340.7
  Top Layer w7.9: v1(6847,9049.6) U6$CBB20/CBB1.14@6980.5,9049.6
  Inner4 w4.7: v1(5277.8,3881.4) 5296.8,3881.4 5300,3884.6 5307.3,3884.6 5310.6,3887.9 5324.2,3887.9 5325.5,3889.1 5630.3,3889.1 5642.3,3901.2 6066.3,3901.2 6257.6,4092.4 6257.6,5343 6398.3,5483.7 6651.7,5483.7 6679.3,5511.3 6679.3,5644.5 6709.4,5674.6 6709.4,6025.7 6679.3,6055.8 6679.3,6098.3 6709.4,6128.4 6709.4,6315.2 6747.5,6353.4 6747.5,8418.6 6796,8467.1 6796,9027.9 6817.7,9049.6 v1(6847,9049.6)
SI_DAC2_DAC(2): U1$CBB22.3 U6$CBB16/CBB2.14 U100$CBB22.F11 | length 8226.5
  Top Layer w3.9: 5426.7,4322.1 5428.3,4323.7 5428.3,4334.3 5427.1,4335.5 5427.1,4371.4 5426.7,4371.8 5426.7,4448.3 5428.3,4450 5428.3,4457.5 U100$CBB22.F11@5439.5,4468.6
  Top Layer w4.7: v1(5299,4013.1) 5299,4030 5297.7,4031.3 5297.7,4040.5 5292.4,4045.7 5292.4,4085 5294.4,4087 5294.4,4093.5 5297.7,4096.8 5297.7,4111.8 5292.4,4117 5292.4,4136.4 5426.7,4270.7 5426.7,4322.1
  Top Layer w7.9: v1(4962.1,9049.6) U6$CBB16/CBB2.14@5095.7,9049.6
  Inner2 w4.7: v1(4962.1,9049.6) 5251.7,9049.6 v1(5253.7,9047.7) ; v1(5293.8,3726.8) 5293.8,3801.1 5325.9,3833.2 5325.9,3852.2 5317.9,3860.2 5317.9,3977.8 5299,3996.7 v1(5299,4013.1) ; v1(5323.6,5555.5) 5327,5555.5 5333.5,5549 5910.7,5549 5920.5,5558.7 5942,5558.7 5957.2,5543.5 5957.2,5539.7 5959.1,5537.7 5973.2,5551.8 v1(5986.4,5551.8)
  Inner4 w4.7: v1(5253.7,9047.7) 5253.7,8830.8 5305.9,8778.6 5305.9,8563.8 5297.8,8555.7 5297.8,8375.6 5303.7,8369.7 5303.7,8348.2 5297.8,8342.4 5297.8,6180.7 5306.1,6172.4 5306.1,6127.3 5297.8,6119.1 5297.8,5578.2 5315.9,5560.1 5319,5560.1 v1(5323.6,5555.5) ; v1(5299,4013.1) 5300.5,4011.6 5311.1,4011.6 5314,4008.7 5327.5,4008.7 5330.4,4011.6 5434,4011.6 5440.5,4018.1 6018.2,4018.1 6140.3,4140.1 6140.3,5404.7 5993.1,5551.8 v1(5986.4,5551.8)
  Inner4 w5.5: U1$CBB22.3@4964.3,3652.7 5123.3,3652.7 5155.3,3684.6 5169.3,3684.6 5211.5,3726.8 v1(5293.8,3726.8)
SI_DAC2_W(12): U6$CBB18/CBB2.14 U100$CBB22.U15 | length 4936.6
  Top Layer w4.3: 5324.2,4785.2 5324.5,4784.8 5324.5,4762.7 U100$CBB22.U15@5337.1,4750.1
  Top Layer w4.7: v1(5263.7,5301) 5281,5301 5311.1,5270.9 5311.1,5068.7 5307.3,5064.8 5307.3,5011.1 5307.7,5010.6 5307.7,4987 5311.1,4983.6 5311.1,4889.7 5310.9,4889.4 5310.9,4885.6 5309.8,4884.5 5309.8,4822.7 5324.2,4808.4 5324.2,4785.2
  Top Layer w7.9: v1(6215.4,8387.1) 6211.5,8391 6211.5,8519.7 6288.7,8596.8 U6$CBB18/CBB2.14@6350.6,8596.8
  Inner2 w4.7: v1(5277.8,8359) 5372.1,8359 5390.2,8377 5928.3,8377 5938.3,8387.1 v1(6215.4,8387.1)
  Inner4 w4.7: v1(5263.7,5301) 5263.7,5415.4 5267.4,5419.1 5267.4,6129.9 5276.9,6139.4 5276.9,6160.4 5260,6177.3 5260,7215.3 5253.5,7221.8 5253.5,7231.9 5251.5,7233.9 5251.5,7246.8 5249.6,7248.6 5249.6,7282.8 5261.7,7294.8 5261.7,8136.1 5272.8,8147.2 5272.8,8354.1 v1(5277.8,8359)
SI_DAC2_W(15): U6$CBB17/CBB2.14 U100$CBB22.U8 | length 4076.4
  Top Layer w4.3: 5503.3,4785.2 5503.7,4784.8 5503.7,4762.7 U100$CBB22.U8@5516.3,4750.1
  Top Layer w4.7: 5503.3,4785.2 5503.3,4868.6 5506.4,4871.7 5506.4,4891.1 5556.9,4941.6 5556.9,5148.4 5520.7,5184.5 v1(5520.7,5194.4)
  Top Layer w7.9: v1(5587.1,8596.8) U6$CBB17/CBB2.14@5720.7,8596.8
  Inner4 w4.7: v1(5520.7,5194.4) 5518.9,5194.4 5490.6,5222.7 5490.6,8383.4 5587.1,8479.9 v1(5587.1,8596.8)
SI_DAC2_W(34): U6$CBB20/CBB2.14 U100$CBB22.D9 | length 6457.4
  Top Layer w7.9: v1(6847,8596.8) U6$CBB20/CBB2.14@6980.5,8596.8
  Inner2 w3.9: v2(5490.7,4417.4) 5492.7,4417.4 5502.6,4407.5 5502.6,4398 5503.5,4397.2 5503.5,4386.6 5502.6,4385.7 5502.6,4323.1 5503.7,4322.1
  Inner2 w4.7: 5503.7,4322.1 5503.7,4266.8 5510.8,4259.6 5510.8,4217.7 5501.9,4208.7 5501.9,4179.8 5501.5,4179.4 5500.8,4179.4 5491.3,4169.9 5491.3,4169.2 5487,4165 5487,4154.5 5480.1,4147.6 5480.1,4134.1 5486.8,4127.4 5486.8,4126.8 5487,4126.5 5487,4082.8 5488.9,4081 5488.9,4019.2 5487,4017.3 5487,3951.3 5564.9,3873.4 5643.2,3873.4 v1(5647.2,3869.4)
  Inner4 w4.7: v1(5647.2,3869.4) 5660.1,3869.4 5674.3,3855.2 5691.4,3855.2 5701.3,3845.2 6037.9,3845.2 6277.4,4084.8 6277.4,5335.3 6405.7,5463.6 6659.1,5463.6 6729.4,5534 6729.4,6306.9 6767.6,6345.1 6767.6,8411.2 6847,8490.6 v1(6847,8596.8)
SI_DAC3_DAC(2): U6$CBB16/CBB3.14 U100$CBB22.G16 | length 4776.2
  Top Layer w7.9: v1(4962.1,8144.1) U6$CBB16/CBB3.14@5095.7,8144.1
  Inner2 w4.7: v1(4611.1,8140.1) 4615.1,8144.1 v1(4962.1,8144.1) ; v1(4706.8,5055.1) 4707.5,5054.4 4707.5,4721 4682,4695.5 4682,4652.4 4867.7,4466.8 5174.9,4466.8 5202.3,4494.2 v2(5311.5,4494.2)
  Inner4 w4.7: v1(4611.1,8140.1) 4611.1,7732.5 4597.1,7718.5 4597.1,7662.2 4597.4,7661.9 4597.4,6784.3 4581.3,6768.3 4581.3,5740.7 4641.9,5680.1 4641.9,5544.1 4647.5,5538.5 4647.5,5509 4641.9,5503.4 4641.9,5277 4682.8,5236.1 4682.8,5182.4 4678,5177.6 4678,5083.8 4679.6,5082.3 4679.6,5081.4 4694.8,5066.2 4695.6,5066.2 v1@4706.7,5055.1
SI_DAC3_W(12): U6$CBB18/CBB3.14 U100$CBB22.R15 | length 4794.8
  Top Layer w7.9: v1(6218.1,8144.1) U6$CBB18/CBB3.14@6350.6,8144.1
  Inner2 w3.9: 5242,4686.1 5324.3,4686.1 v2(5337.1,4698.9)
  Inner2 w4.7: v1(5169.3,4812.9) 5165.3,4808.9 5165.3,4740.8 5220,4686.1 5242,4686.1 ; v1(5188.4,8107) 5722.5,8107 5739.6,8124.1 6198.1,8124.1 v1(6218.1,8144.1)
  Inner4 w4.7: v1(5169.3,4812.9) 5169.3,5328.2 5169.2,5328.4 5169.2,5341.8 5169.3,5342 5169.3,6264.8 5185.4,6280.8 5185.4,7033.8 5157.3,7061.9 5157.3,7156.3 5177.4,7176.3 5177.4,7509.6 5155.3,7531.7 5155.3,7583.9 5173.3,7602 5173.3,8091.9 v1(5188.4,8107)
SI_DAC3_W(15): U6$CBB17/CBB3.14 U100$CBB22.A9 | length 5013.1
  Top Layer w4.7: U100$CBB22.A9@5490.7,4340.7 5490.7,4256.8 v1(5494.6,4252.9)
  Top Layer w7.9: v1(5587.1,8144.1) U6$CBB17/CBB3.14@5720.7,8144.1
  Inner4 w4.7: v1(5494.6,4252.9) 5528.7,4218.7 6000.6,4218.7 6033,4251.2 6033,5146.1 5978.5,5200.6 5978.5,5282.9 5909.5,5351.9 5909.5,5490.3 5885.8,5514 5885.8,5538.2 5782.6,5641.5 5627.7,5641.5 5590.7,5678.5 5590.7,5794.9 5598.7,5802.9 5598.7,5863.2 5604.7,5869.2 5604.7,5897.3 5596.7,5905.4 5596.7,5931.5 5595,5933.2 5595,6046.2 5604.7,6055.9 5604.7,6094.1 5596.9,6102 5596.9,6254.6 5609.1,6266.8 5609.1,6383.2 5599,6393.3 5599,6560.3 5603.8,6565.1 5603.8,6589 5593,6599.8 5593,6708.5 5607.6,6723.1 5607.6,7117.4 5606,7119 5606,7334 5595,7345 5595,7674.3 5595.9,7675.2 5595.9,7894.1 5603,7901.2 5603,7989.5 5595,7997.6 5595,8039.7 5599,8043.7 5599,8132.2 v1(5587.1,8144.1)
SI_DAC3_W(34): U6$CBB20/CBB3.14 U100$CBB22.H17 | length 6850.6
  Top Layer w4.3: 5250.9,4506.9 5251.2,4507.2 5273.3,4507.2 U100$CBB22.H17@5285.9,4519.8
  Top Layer w4.7: v1(5143.2,3859.3) 5131.2,3859.3 5111.1,3839.3 5111,3839.3 5089.7,3818 5076.3,3818 5042.5,3851.7 5042.5,4196.6 5084.7,4238.8 5084.7,4394.6 5196.9,4506.9 5250.9,4506.9
  Top Layer w7.9: v1(6847,8144.3) 6847.2,8144.1 U6$CBB20/CBB3.14@6980.5,8144.1
  Inner2 w4.7: v1(6538.7,8116) 6637.4,8116 6665.7,8144.3 v1(6847,8144.3)
  Inner4 w4.7: v1(5143.2,3859.3) 5171.4,3859.3 5216.1,3904 5263.7,3904 5267,3907.4 5288.5,3907.4 5291.8,3904 5299.3,3904 5302.6,3907.3 5316.2,3907.3 5317.4,3908.6 5622.2,3908.6 5634.3,3920.6 6058.3,3920.6 6237.5,4099.9 6237.5,5350.4 6390.2,5503.1 6502.2,5503.1 6561.1,5562 6561.1,7858.7 6502.6,7917.2 6502.6,7999.6 6538.7,8035.7 v1(6538.7,8116)
SI_DAC4_DAC(2): U6$CBB16/CBB4.14 U100$CBB22.H16 | length 4260
  Top Layer w7.9: v1(4962.1,7691.3) U6$CBB16/CBB4.14@5095.7,7691.3
  Inner2 w4.7: v1(4639.3,7689.3) 4960.1,7689.3 v1(4962.1,7691.3) ; v1(4753.2,5066.2) 4753.2,5065.7 4732.7,5045.2 4732.7,5044.4 4727,5038.6 4727,4712.9 4701.5,4687.4 4701.5,4674 4702.2,4673.2 4702.2,4659.7 4875.7,4486.2 5166.8,4486.2 5200.4,4519.8 v2(5311.5,4519.8)
  Inner4 w4.7: v1(4639.3,7689.3) 4661.3,7667.2 4661.3,5552.2 4666.9,5546.6 4666.9,5500.9 4661.3,5495.4 4661.3,5285.1 4702.3,5244.1 4702.3,5174.3 4697.5,5169.5 4697.5,5122 4711.1,5108.4 4712.2,5108.4 4721.7,5098.9 4721.7,5097.7 v1(4753.2,5066.2)
SI_DAC4_W(12): U6$CBB18/CBB4.14 U100$CBB22.T15 | length 4249.7
  Top Layer w7.9: v1(6218.1,7691.3) U6$CBB18/CBB4.14@6350.6,7691.3
  Inner2 w3.9: 5242,4730.4 5260.6,4711.7 5324.3,4711.7 v2(5337.1,4724.5)
  Inner2 w4.7: v1(5196.7,4791.7) 5196.7,4775.6 5201.3,4771.1 5201.3,4770.2 5210.8,4760.7 5211.7,4760.7 5219.4,4753 5222.2,4753 5231.7,4743.5 5231.7,4740.6 5242,4730.4 ; v1(5245.5,7691.3) v1(6218.1,7691.3)
  Inner4 w4.7: v1(5196.7,4791.7) 5196.7,4808.6 5182.8,4822.5 5182.8,4955.1 5213.5,4985.7 5213.5,5348.3 5214.4,5349.2 5214.4,5362.6 5213.5,5363.5 5213.5,5413.4 5241.6,5441.5 5241.6,5487 5248,5493.3 5248,5517.5 5247.7,5517.8 5247.7,5518.5 5239.6,5526.6 5239.6,6140.6 5231.9,6148.3 5231.9,6164.7 5250.3,6183.1 5250.3,7211.3 5243.8,7217.8 5243.8,7227.8 5241.8,7229.8 5241.8,7242.7 5239.9,7244.6 5239.9,7286.8 5245.5,7292.3 v1(5245.5,7691.3)
SI_DAC4_W(15): U6$CBB17/CBB4.14 U100$CBB22.T8 | length 3205.6
  Top Layer w7.9: v1(5579.7,7707.6) 5595.9,7691.3 U6$CBB17/CBB4.14@5720.7,7691.3
  Inner4 w4.7: v2(5516.3,4724.5) 5516.3,4913 5528.7,4925.4 5528.7,4948.7 5549,4969 5549,4982.4 5544.7,4986.7 5544.7,5208.7 5510.6,5242.8 5510.6,5813.2 5513,5815.6 5513,7022 5585,7094 5585,7108.1 5583.4,7109.6 5583.4,7121.6 5572.9,7132.2 5572.9,7282.8 5564.9,7290.8 5564.9,7425.3 5574.9,7435.4 5574.9,7702.8 v1(5579.7,7707.6)
SI_DAC4_W(34): U6$CBB20/CBB4.14 U100$CBB22.D11 | length 5611.8
  Top Layer w7.9: v1(6861,7677.3) 6966.5,7677.3 U6$CBB20/CBB4.14@6980.5,7691.3
  Inner2 w3.9: v2(5439.5,4417.4) 5439.5,4416.4 5452.5,4403.4 5452.5,4397.3 5452.3,4397.2 5452.3,4386.6 5452.5,4386.4 5452.5,4322.1
  Inner2 w4.7: 5452.5,4322.1 5452.5,4250.5 5482.4,4220.6 5482.4,4189.9 5467.6,4175.1 5467.6,4162.5 5460.6,4155.6 5460.6,4126.1 5466.7,4120.1 5466.7,4119.6 5467.3,4119 5467.3,4118.7 5467.6,4118.5 5467.6,4074.8 5469.4,4072.9 5469.4,4027.2 5467.6,4025.4 5467.6,3922.5 5558.9,3831.2 5596.2,3831.2 5596.3,3831.4 5609.7,3831.4 5609.9,3831.2 5619.1,3831.2 v1(5623.1,3835.2)
  Inner4 w4.7: v1(5623.1,3835.2) 5633.5,3824.9 6045.1,3824.9 6296.9,4076.7 6296.9,5327.3 6413.1,5443.5 6666.5,5443.5 6749.5,5526.6 6749.5,6299.2 6787.7,6337.3 6787.7,7075.9 6843.9,7132.2 6843.9,7258.7 6847.9,7262.7 6847.9,7592 6861,7605.1 v1(6861,7677.3)
SI_DAC5_DAC(2): U6$CBB16/CBB5.14 U100$CBB22.G15 | length 3952.5
  Top Layer w7.9: v1(4962.1,7238.6) U6$CBB16/CBB5.14@5095.7,7238.6
  Inner2 w3.9: 5295.8,4480.4 5296.9,4481.4 5324.3,4481.4 v2(5337.1,4494.2)
  Inner2 w4.7: v1(4579,7242.6) 4958.1,7242.6 v1(4962.1,7238.6) ; v1(4678,5060) 4693,5045 4693,4720.2 4672.3,4699.5 4672.3,4648.4 4863.7,4457 5178.9,4457 5205.7,4483.8 5292.4,4483.8 5295.8,4480.4
  Inner4 w4.7: v1(4579,7242.6) 4587.7,7233.9 4587.7,6788.4 4571.6,6772.3 4571.6,5736.7 4632.2,5676.1 4632.2,5540.1 4637.7,5534.5 4637.7,5513 4632.2,5507.5 4632.2,5273 4673.1,5232.1 4673.1,5186.4 4668.3,5181.6 4668.3,5069.7 v1(4678,5060)
SI_DAC5_W(12): U6$CBB18/CBB5.14 U100$CBB22.U14 | length 3621.7
  Top Layer w4.3: 5349.8,4785.2 5350.1,4784.8 5350.1,4762.7 U100$CBB22.U14@5362.7,4750.1
  Top Layer w4.7: v1(5319.9,5333.1) 5319.9,5319.1 5330.6,5308.4 5330.6,5060.6 5326.7,5056.8 5326.7,5019.2 5327.2,5018.7 5327.2,4995.1 5330.6,4991.6 5330.6,4881.6 5330.4,4881.4 5330.4,4877.5 5329.3,4876.4 5329.3,4830.8 5349.8,4810.3 5349.8,4785.2
  Top Layer w7.9: v1(6218.1,7238.6) U6$CBB18/CBB5.14@6350.6,7238.6
  Inner2 w4.7: v1(5269.7,7228.5) 5279.8,7218.5 6198,7218.5 v1(6218.1,7238.6)
  Inner4 w4.7: v1(5269.7,7228.5) 5269.7,6181.3 5286.6,6164.4 5286.6,6135.4 5278.1,6126.8 5278.1,5570 5281.8,5566.3 5281.8,5546.2 5281.6,5546 5281.6,5507.1 5319.9,5468.8 v1(5319.9,5333.1)
SI_DAC5_W(15): U6$CBB17/CBB5.14 U100$CBB22.A10 | length 4122.5
  Top Layer w4.7: U100$CBB22.A10@5465.1,4340.7 5465.1,4215 5472.7,4207.4 5472.7,4194 5465.1,4186.4 5465.1,4163.9 5480.8,4148.2 5480.1,4147.6 5480.1,4134.1 5486.8,4127.4 5486.8,4126.8 5496.3,4117.3 5498.3,4117.3 5500.3,4115.3 5504.2,4115.3 v1(5512,4123)
  Top Layer w7.9: U6$CBB17/CBB5.14@5720.7,7238.6 5759.8,7238.6 v1(5787.9,7266.7)
  Inner4 w4.7: v1(5512,4123) 5538.8,4149.8 6012.8,4149.8 6072.2,4209.2 6072.2,5258 5958.4,5371.8 5958.4,5407.9 5958.1,5408.2 5958.1,5534.7 5957.2,5535.7 5957.2,5543.5 5942,5558.7 5934.1,5558.7 5846,5646.8 5846,6228.6 5813.9,6260.7 5813.9,6557.9 5819.9,6563.9 5819.9,6585 5813.9,6591 5813.9,7240.7 v1(5787.9,7266.7)
SI_DAC5_W(34): U6$CBB20/CBB5.14 U100$CBB22.A15 | length 5467.5
  Top Layer w4.7: v1(5284.8,3838.2) 5283.5,3839.6 5272.6,3839.6 5271.7,3838.7 5240.4,3838.7 5228.2,3851 5228.2,4017.9 5190,4056.1 5190,4142 5201.8,4153.7 5201.8,4155.1 5222.7,4176 5224.1,4176 5244,4195.9 5251.8,4195.9 5337.1,4281.3 U100$CBB22.A15@5337.1,4340.7
  Top Layer w7.9: v1(6870.2,7236.6) 6978.5,7236.6 U6$CBB20/CBB5.14@6980.5,7238.6
  Inner4 w4.7: v1(5284.8,3838.2) 5344,3779 5643.2,3779 5669.3,3805.1 6052.8,3805.1 6316.3,4068.7 6316.3,5319.2 6420.6,5423.5 6673.9,5423.5 6769.6,5519.1 6769.6,6290.9 6807.8,6329 6807.8,7065.9 6860,7118.1 6860,7118.4 6863.7,7122.1 6863.7,7160 6870.2,7166.5 v1(6870.2,7236.6)
SI_DAC6_DAC(2): U6$CBB16/CBB6.14 U100$CBB22.H15 | length 3451
  Top Layer w7.9: v1(4962.1,6785.8) U6$CBB16/CBB6.14@5095.7,6785.8
  Inner2 w3.9: 5295.8,4505.9 5296.9,4507 5324.3,4507 v2(5337.1,4519.8)
  Inner2 w4.7: v1(4613.6,6786.8) 4961.1,6786.8 v1(4962.1,6785.8) ; v1(4725.2,5071.4) 4722.7,5068.9 4722.7,5062.3 4723,5062 4723,5048.4 4717.2,5042.6 4717.2,4716.9 4691.8,4691.5 4691.8,4670 4692.5,4669.2 4692.5,4655.7 4871.7,4476.5 5170.9,4476.5 5200.3,4505.9 5295.8,4505.9
  Inner4 w4.7: v1(4613.6,6786.8) 4591.1,6764.3 4591.1,5744.7 4651.6,5684.2 4651.6,5548.1 4657.2,5542.6 4657.2,5505 4651.6,5499.4 4651.6,5281 4692.5,5240.1 4692.5,5178.3 4687.8,5173.6 4687.8,5087.8 4689.3,5086.3 4689.3,5085.4 4698.8,5075.9 4699.6,5075.9 4704.2,5071.4 v1(4725.2,5071.4)
SI_DAC6_W(12): U6$CBB18/CBB6.14 U100$CBB22.V14 | length 3162.1
  Top Layer w4.7: U100$CBB22.V14@5362.7,4775.7 5362.7,4811.1 5339,4834.8 5339,4872.4 5340.1,4873.5 5340.1,4877.4 5340.3,4877.6 5340.3,4995.7 5336.9,4999.1 5336.9,5022.7 5336.5,5023.2 5336.5,5052.7 5340.3,5056.6 5340.3,5531.4 v1(5374.1,5565.2) ; U6$CBB18/CBB6.14@6350.6,6785.8 6365,6785.8 v1(6389.8,6810.7)
  Inner2 w4.7: v1(5374.1,5565.2) 5913.2,5565.2 5916.4,5568.5 5944,5568.5 5950.4,5574.9 5963.8,5574.9 5970.6,5568.1 6006.6,5568.1 6028.7,5545.9 v1(6388.1,5545.9)
  Inner4 w4.7: v1(6388.1,5545.9) 6388.1,6808.9 v1(6389.8,6810.7)
SI_DAC6_W(15): U6$CBB17/CBB6.14 U100$CBB22.R8 | length 2316.8
  Top Layer w7.9: v1(5587.1,6785.8) U6$CBB17/CBB6.14@5720.7,6785.8
  Inner2 w3.9: v2(5516.3,4698.9) 5529.1,4711.7 5529.1,4796.2
  Inner2 w4.7: 5529.1,4796.2 5529.1,4819.4 5534.2,4824.5 v1(5538.8,4824.5)
  Inner4 w4.7: 5540.8,5497.8 5548.8,5505.8 5548.8,5527.9 5522.7,5554 5522.7,6070 5570.9,6118.2 5570.9,6357.1 5585,6371.2 5585,6560 5594,6569.1 5594,6585 5580.9,6598.1 5580.9,6744.6 5587.1,6750.8 v1(5587.1,6785.8)
  Inner4 w5.5: v1(5538.8,4824.5) 5538.8,4944.5 5559.1,4964.8 5559.1,4986.6 5554.8,4990.9 5554.8,5253.4 5520.7,5287.5 5520.7,5477.7 5540.8,5497.8
SI_DAC6_W(34): U6$CBB20/CBB6.14 U100$CBB22.A16 | length 5088.7
  Top Layer w4.7: v1(5247.6,3803.1) 5237.6,3803.1 5208.7,3832 5208.7,4009.9 5170.6,4048 5170.6,4150 5182.4,4161.8 5182.4,4163.2 5214.7,4195.5 5216,4195.5 5235.9,4215.4 5243.7,4215.4 5311.5,4283.2 U100$CBB22.A16@5311.5,4340.7
  Top Layer w7.9: v1(6847,6785.8) U6$CBB20/CBB6.14@6980.5,6785.8
  Inner4 w4.7: v1(5247.6,3803.1) 5288.3,3762.5 5308.6,3762.5 5311.5,3759.6 5651.2,3759.6 5677.2,3785.6 6060.7,3785.6 6335.8,4060.6 6335.8,5311.2 6427.4,5402.8 6680.7,5402.8 6790,5512 6790,6280.8 6827.8,6318.7 6827.8,6766.7 v1(6847,6785.8)
SI_DAC7_W(12): U6$CBB18/CBB7.14 U100$CBB22.R14 | length 3035
  Top Layer w7.9: v1(6211.8,6333.1) U6$CBB18/CBB7.14@6350.6,6333.1
  Inner2 w4.7: v1(5165.3,6304.9) 5753.6,6304.9 5769.7,6321 6199.7,6321 v1(6211.8,6333.1)
  Inner4 w3.9: 5242,4686.6 5305.8,4686.6 5306.2,4686.1 5349.9,4686.1 v2(5362.7,4698.9)
  Inner4 w4.7: v1(5165.3,6304.9) 5139.2,6278.8 5139.2,4721 5173.6,4686.6 5242,4686.6
SI_DAC7_W(15): U6$CBB17/CBB7.14 U100$CBB22.F10 | length 2360.7
  Top Layer w7.9: v1(5587.1,6327.9) 5592.3,6333.1 U6$CBB17/CBB7.14@5720.7,6333.1
  Inner2 w3.9: v2(5465.1,4468.6) 5477.9,4481.4 5496,4481.4 5503.5,4488.9 5503.5,4499.5 5511,4507 5521.6,4507 5529.1,4514.5 5529.1,4525.1 5536.5,4532.6 5675.1,4532.6 5676.4,4533.9 5716,4533.9
  Inner2 w4.7: 5716,4533.9 5757.6,4533.9 v1(5765.7,4542)
  Inner4 w4.7: v1(5587.1,6327.9) 5587.1,6098 5595,6090.1 5595,6060 5583,6047.9 5583,5931.5 5587,5927.4 5587,5901.3 5595,5893.3 5595,5873.2 5589,5867.2 5589,5807 5580.9,5798.9 5580.9,5674.4 5749.6,5505.8 5749.6,4558.1 v1(5765.7,4542)
SI_DAC7_W(34): U6$CBB20/CBB7.14 U100$CBB22.A17 | length 4665.4
  Top Layer w4.7: v1(5227.6,3783) 5223.5,3787 5223.5,3803.4 5199,3827.9 5199,4005.8 5160.9,4044 5160.9,4154.1 5172.6,4165.8 5172.6,4167.2 5210.6,4205.2 5212,4205.2 5217.5,4210.7 5217.5,4248.9 5285.9,4317.3 U100$CBB22.A17@5285.9,4340.7
  Top Layer w7.9: v1(6847,6333.1) U6$CBB20/CBB7.14@6980.5,6333.1
  Inner4 w4.7: v1(5227.6,3783) 5235.4,3775.2 5250.3,3775.2 5275.7,3749.8 5280.2,3749.8 5283.1,3752.8 5304.6,3752.8 5307.5,3749.8 5655.3,3749.8 5681.3,3775.8 6064.8,3775.8 6345.5,4056.6 6345.5,5307.2 6431.4,5393 6684.8,5393 6799.7,5508 6799.7,6276.8 6847,6324.1 v1(6847,6333.1)
SI_DAC8_W(12): U6$CBB18/CBB8.14 U100$CBB22.P14 | length 2789.9
  Top Layer w7.9: v1(6211.4,5880.3) U6$CBB18/CBB8.14@6350.6,5880.3
  Inner2 w4.7: v1(5014.6,5845.1) 5609.1,5845.1 5639.2,5875.2 5755.6,5875.2 5760.7,5880.3 v1(6211.4,5880.3)
  Inner4 w3.9: 5242,4661 5242.4,4660.6 5349.9,4660.6 v2(5362.7,4673.3)
  Inner4 w4.7: v1(5014.6,5845.1) 5020.7,5838.9 5020.7,5498.3 5018.5,5496 5018.5,5474.5 5020.7,5472.3 5020.7,5455.6 5062.9,5413.4 5062.9,5021.6 5076.7,5007.8 5076.7,4769.8 5185.4,4661 5242,4661
SI_DAC8_W(15): U6$CBB17/CBB8.14 U100$CBB22.U13 | length 1481.8
  Top Layer w4.3: 5375.4,4785.2 5375.7,4784.8 5375.7,4762.7 U100$CBB22.U13@5388.3,4750.1
  Top Layer w4.7: 5375.4,4785.2 5375.4,4817.9 5369.6,4817.9 5348.7,4838.8 5348.7,4868.4 5349.8,4869.5 5349.8,4873.3 5350,4873.6 5350,4999.7 5346.6,5003.1 5346.6,5024.6 5347.7,5025.7 5346.2,5027.2 5346.2,5048.7 5350,5052.6 5350,5198.6 5386.2,5234.7 5540.8,5234.7 v1(5568.9,5262.8)
  Top Layer w7.9: v1(5578.8,5880.3) U6$CBB17/CBB8.14@5720.7,5880.3
  Inner4 w4.7: v1(5568.9,5262.8) 5568.9,5870.4 v1(5578.8,5880.3)
SI_DAC8_W(34): U1$CBB22.1 U6$CBB20/CBB8.14 U100$CBB22.E11 | length 4763.1
  Top Layer w7.9: v1(6847,5880.3) U6$CBB20/CBB8.14@6980.5,5880.3
  Inner2 w4.7: v1(5456.5,4200.7) 5448.1,4192.3 5448.1,4170.6 5441.2,4163.7 5441.2,4118 5447.2,4112 5447.2,4111.6 5447.9,4110.9 5447.9,4110.6 5448.1,4110.4 5448.1,4066.7 5450,4064.9 5450,4035.3 5448.1,4033.5 5448.1,3893.8 5627.1,3714.8 v1(5627.1,3698.9)
  Inner4 w3.9: v2(5439.5,4443) 5452.4,4430.1 5452.4,4422.9 5452.3,4422.7 5452.3,4386.6 5452.4,4386.4 5452.4,4322.2 5452.3,4322.1
  Inner4 w4.7: U1$CBB22.1@4964.3,3552.7 5051.7,3552.7 5195.7,3696.7 5625,3696.7 v1(5627.1,3698.9) 5633.8,3698.9 5691.3,3756.4 6072.8,3756.4 6365,4048.5 6365,5299.1 6438.5,5372.6 6691.9,5372.6 6855.9,5536.7 6855.9,5760.8 6847,5769.8 v1(6847,5880.3) ; 5452.3,4322.1 5452.3,4245 5456.5,4240.8 5456.5,4227.6 5456.6,4227.5 5456.6,4214 5456.5,4213.9 v1(5456.5,4200.7)
T20_CLK9: R77.1 U1$CBB23.G16 U100$CBB22.H14 | length 2680.3
  Top Layer w4.7: U1$CBB23.G16@4239.1,5720.4 4258,5720.4 4287.9,5690.5 4336.1,5690.5 4362.2,5664.4 4362.2,5656.4 4388.6,5630 4523.8,5630 v1(4532.8,5639)
  Inner2 w4.7: v1(4595.2,5198.4) 4596.3,5198.4 4602.8,5191.9 4802.6,5191.9 4803.7,5193 4833.2,5193 4834.3,5191.9 4954.6,5191.9 v1(4956.3,5193.7)
  Inner4 w3.9: 5242,4507.4 5242.4,4507 5349.9,4507 v2(5362.7,4519.8)
  Inner4 w4.7: v1(4532.8,5639) 4570.6,5601.3 4570.6,5251.2 4584.9,5236.9 4585.7,5236.9 4595.2,5227.4 v1(4595.2,5198.4) 4608.9,5184.8 4608.9,5064.2 4608.4,5063.8 4608.4,5018.1 4608.9,5017.7 4608.9,4992.1 4610.8,4990.1 4610.8,4863.3 4634.9,4839.2 4634.9,4817.4 v1(4649.3,4803) ; v1(4956.3,5193.7) 4962.5,5187.5 4962.5,5156.8 4956,5150.3 4956,5076 4972.2,5059.8 4972.2,5043.5 4974.3,5041.5 4974.3,4658.8 5036.7,4596.4 5037.5,4596.4 5047,4586.9 5047,4533.8 5073.4,4507.4 5242,4507.4
  Bottom Layer w4.7: R77.1@4648.3,4748.8 4648.3,4802 v1(4649.3,4803)
T120_CRESET_N: R139.1 U14.2 | length 56.9
  Top Layer w4.7: R139.1@4810.9,4007.9 4838.7,4007.9 U14.2@4859.3,4028.5
TRIM_DAC: R144.2 U2$CBB18.13 U2$CBB18.14 | length 4517.8
  Top Layer w7.9: R144.2@4090.1,8923.2 4247.7,8923.2 v1(4247.9,8923)
  Inner2 w7.9: v1(4247.9,8923) 4249.6,8923 4249.7,8923.2 4279.8,8923.2 4312,8955.3 4312,8973.4 4320,8981.4 5874.1,8981.4 v1(5890.2,8965.4)
  Inner4 w7.9: v1(5890.2,8965.4) 5938.3,8917.2 5938.3,8353 5956.4,8334.9 5956.4,8262.6 5976.5,8242.5 v1(5976.5,6549.9)
  Bottom Layer w7.9: v1(5976.5,6549.9) 6015.7,6589.1 U2$CBB18.14@6135.3,6589.1 U2$CBB18.13@6135.3,6539.1
VR: C84.2 R148.2 U3$CBB9.3 U3$CBB9.5 U3$CBB9.10 U3$CBB9.12 U3$CBB19.3 U3$CBB19.5 U3$CBB19.10 U3$CBB19.12 U3$CBB49.3 U3$CBB49.5 U3$CBB49.10 U3$CBB49.12 U4$CBB9.3 U4$CBB9.5 U4$CBB9.10 U4$CBB9.12 U4$CBB19.3 U4$CBB19.5 U4$CBB19.10 U4$CBB19.12 U4$CBB49.3 U4$CBB49.5 U4$CBB49.10 U4$CBB49.12 U5$CBB9.3 U5$CBB9.5 U5$CBB9.10 U5$CBB9.12 U5$CBB19.3 U5$CBB19.5 U5$CBB19.10 U5$CBB19.12 U5$CBB49.3 U5$CBB49.5 U5$CBB49.10 U5$CBB49.12 | length 6091.7
  Top Layer w7.9: U3$CBB9.3@7959,5259 U3$CBB9.3@7960.6,5260.6 ; U3$CBB9.3@7986.2,5259 8021,5259 v1(8028.6,5266.6)
  Top Layer w11.8: C84.2@7372.4,4989.8 7380,4982.2 v1(7380,4927.8) R148.2@7380,4864.2 ; U3$CBB49.5@7537.6,5160.6 7574.9,5160.6 7592.8,5178.5 7592.8,5226.7 7558.9,5260.6 v1(7537.6,5260.6) ; U3$CBB49.10@7755.6,5160.6 7755.5,5160.4 7709.3,5160.4 7692.9,5176.8 7692.9,5240.4 7713.1,5260.6 U3$CBB49.12@7755.6,5260.6 7816,5260.6 v1(7819.1,5257.5) ; v1(7960.6,5160.6) 8000.6,5160.6 8020.5,5180.5 8020.5,5224.7 7986.2,5259 7984.6,5260.6 U3$CBB9.3@7960.6,5260.6 ; v1(8178.6,5160.6) 8176.8,5162.4 8133,5162.4 8124.6,5170.8 8124.6,5236.4 8148.8,5260.6 U3$CBB9.12@8178.6,5260.6 ; v1(8478.3,5256.8) 8482.1,5260.6 U4$CBB49.3@8520.2,5260.6 ; U4$CBB49.5@8555,5160.6 8586.9,5160.6 8606,5179.7 8606,5237.6 8580.7,5262.8 8522.5,5262.8 U4$CBB49.3@8520.2,5260.6 ; U4$CBB49.3@8555,5260.6 U4$CBB49.3@8520.2,5260.6 ; U4$CBB49.10@8773,5160.6 8711.2,5160.6 8691.1,5180.7 8691.1,5236.7 8715,5260.6 U4$CBB49.12@8773,5260.6 ; v1(8978,5160.6) 9024.6,5160.6 9044.5,5180.5 9044.5,5222.7 9006.6,5260.6 U4$CBB9.3@8978,5260.6 ; U4$CBB9.10@9196,5160.6 9192.2,5164.4 9148.9,5164.4 9132.9,5180.5 9132.9,5234.7 9159,5260.8 v1(9197.1,5260.8) ; U5$CBB49.5@9572.4,5160.6 9610.9,5160.6 9632.8,5182.5 9632.8,5236.7 9609,5260.6 U5$CBB49.3@9572.4,5260.6 ; v1(9717.2,5284.9) 9717.2,5274.9 9731.5,5260.6 U5$CBB49.12@9790.4,5260.6 9817.8,5260.6 9841.7,5236.7 9942,5236.7 9965.9,5260.6 v1(9995.4,5260.6) 10022.6,5260.6 10056.5,5226.7 10056.5,5174.5 10042.6,5160.6 v1(9995.4,5160.6) ; v1(9719.2,5168.5) 9727,5160.6 U5$CBB49.10@9790.4,5160.6 ; v1(10213.4,5160.6) 10211.6,5162.4 10173,5162.4 10148.9,5186.5 10148.9,5226.7 10182.8,5260.6 U5$CBB9.12@10213.4,5260.6
  Inner2 w11.8: v1(7380,5254.8) 7388,5262.8 7574.8,5262.8 7598.9,5238.7 7800.3,5238.7 v1(7819.1,5257.5) 7849.1,5257.5 7867.2,5239.5 7872.2,5239.5 7873.9,5237.7 7969.3,5237.7 7998.2,5266.6 v1(8028.6,5266.6) 8074.5,5266.6 8094.8,5286.9 8145,5286.9 v1(8173.1,5258.8) 8217.7,5258.8 8220.4,5256.1 8236.8,5256.1 8239.5,5258.8 8289.6,5258.8 8299.6,5268.9 8466.3,5268.9 v1(8478.3,5256.8) 8612.8,5256.8 8630.9,5274.9 8741.3,5274.9 v1(8751.4,5264.8) 8829.7,5264.8 8847.8,5246.8 8889.9,5246.8 8906,5262.8 v1(8976.3,5262.8) 9195.1,5262.8 v1(9197.1,5260.8) 9341.7,5260.8 9347.7,5254.8 v1(9570.6,5254.8) 9622.8,5254.8 9652.9,5284.9 v1(9717.2,5284.9) ; v1(9995.4,5260.6) 10214.9,5260.6 v1(10215.1,5260.8)
  Inner3 w11.8: v1(8173.1,5258.8) v1@8175.1,5260.8
  Inner4 w11.8: v1(7380,4927.8) v1(7380,5254.8) ; v1@9196.3,5261.7 v1(9197.1,5260.8) ; v1(9717.2,5284.9) 9717.2,5170.5 v1(9719.2,5168.5) ; v1(10215.1,5260.8) v1@10215.5,5261.2
  Bottom Layer w11.8: U3$CBB19.5@7960.6,5260.6 8022.6,5260.6 v1(8028.6,5266.6)
  other v1: 9196.1,5160.6
W_M1_ROW1: Q6$CBB49/CBB1.3 Q6$CBB49/CBB7.3 Q6$CBB49/CBB13.3 Q6$CBB49/CBB19.3 Q6$CBB49/CBB25.3 Q6$CBB49/CBB31.3 Q9$CBB49/CBB1.3 Q9$CBB49/CBB7.3 Q9$CBB49/CBB13.3 Q9$CBB49/CBB19.3 Q9$CBB49/CBB25.3 Q9$CBB49/CBB31.3 U1$CBB17.1 U1$CBB17.2 | length 5782.2
  Top Layer w7.9: v1(7445.3,9228.7) 7448.8,9232.2 7448.8,9274 7448.4,9274.4 7448.4,9289.2 7448.8,9289.6 Q9$CBB49/CBB1.3@7448.8,9313.7 ; v1(7954,9228.7) 7957.5,9232.2 7957.5,9274 7957.1,9274.4 7957.1,9289.2 7957.5,9289.6 Q9$CBB49/CBB7.3@7957.5,9313.7 ; v1(8462.7,9228.7) 8466.2,9232.2 8466.2,9274 8465.8,9274.4 8465.8,9289.1 8466.2,9289.5 Q9$CBB49/CBB13.3@8466.2,9313.7 ; v1(8971.4,9228.7) 8974.9,9232.2 8974.9,9274 8974.5,9274.4 8974.5,9289.2 8974.9,9289.6 Q9$CBB49/CBB19.3@8974.9,9313.7 ; v1(9480.1,9228.7) 9483.6,9232.2 9483.6,9274 9483.2,9274.4 9483.2,9289.2 9483.6,9289.6 Q9$CBB49/CBB25.3@9483.6,9313.7 ; v1(9988.8,9228.7) 9992.3,9232.2 9992.3,9274 9991.9,9274.4 9991.9,9289.2 9992.3,9289.6 Q9$CBB49/CBB31.3@9992.3,9313.7
  Inner2 w7.9: 4919.9,8613.2 4920,8613.1 ; v1(7326.2,9203.7) 7445.9,9203.7 ; v1(7445.3,9228.7) 7445.3,9204.3 7445.9,9203.7 ; v1(7954,9228.7) 7954,9204.3 7954.6,9203.7 ; v1(8462.7,9228.7) 8462.7,9204.3 8463.2,9203.7 ; v1(8971.4,9228.7) 8971.4,9204.3 8972,9203.7 ; v1(9480.1,9228.7) 9480.1,9204.3 9480.7,9203.7 ; v1(9988.8,9228.7) 9988.8,9204.3 9989.4,9203.7 9480.7,9203.7 ; 7445.9,9203.7 7954.6,9203.7 ; 7954.6,9203.7 8463.2,9203.7 ; 8463.2,9203.7 8972,9203.7 ; 8972,9203.7 9480.7,9203.7
  Inner2 w23.6: v1(5827.1,9193.7) 5872.1,9193.7 5877.1,9198.7 5950.8,9198.7 5962.8,9210.8 7046.1,9210.8 7058.2,9198.7 v1@7327.1,9198.7
  Inner4 w23.6: v1(5812.2,8406.7) 5827.1,8421.7 v1(5827.1,9193.7)
  Bottom Layer w7.9: U1$CBB17.2@5723.4,8350.1 U1$CBB17.1@5723.4,8400.1 5805.5,8400.1 v1(5812.2,8406.7)
W_M1_ROW2: Q6$CBB49/CBB2.3 Q6$CBB49/CBB8.3 Q6$CBB49/CBB14.3 Q6$CBB49/CBB20.3 Q6$CBB49/CBB26.3 Q6$CBB49/CBB32.3 Q9$CBB49/CBB2.3 Q9$CBB49/CBB8.3 Q9$CBB49/CBB14.3 Q9$CBB49/CBB20.3 Q9$CBB49/CBB26.3 Q9$CBB49/CBB32.3 U1$CBB17.6 U1$CBB17.7 | length 5520.3
  Top Layer w7.9: v1(7445.3,8708.7) 7448.8,8712.2 7448.8,8754 7448.4,8754.4 7448.4,8769.2 7448.8,8769.6 Q9$CBB49/CBB2.3@7448.8,8793.7 ; v1(7954,8708.7) 7957.5,8712.2 7957.5,8754 7957.1,8754.4 7957.1,8769.2 7957.5,8769.6 Q9$CBB49/CBB8.3@7957.5,8793.7 ; v1(8462.7,8708.7) 8466.2,8712.2 8466.2,8754 8465.8,8754.4 8465.8,8769.1 8466.2,8769.5 Q9$CBB49/CBB14.3@8466.2,8793.7 ; v1(8971.4,8708.7) 8974.9,8712.2 8974.9,8754 8974.5,8754.4 8974.5,8769.2 8974.9,8769.6 Q9$CBB49/CBB20.3@8974.9,8793.7 ; v1(9480.1,8708.7) 9483.6,8712.2 9483.6,8754 9483.2,8754.4 9483.2,8769.2 9483.6,8769.6 Q9$CBB49/CBB26.3@9483.6,8793.7 ; v1(9988.8,8708.7) 9992.3,8712.2 9992.3,8754 9991.9,8754.4 9991.9,8769.2 9992.3,8769.6 Q9$CBB49/CBB32.3@9992.3,8793.7
  Inner2 w7.9: v1(7326.2,8683.7) 7445.9,8683.7 ; v1(7445.3,8708.7) 7445.3,8684.3 7445.9,8683.7 ; v1(7954,8708.7) 7954,8684.3 7954.6,8683.7 ; v1(8462.7,8708.7) 8462.7,8684.3 8463.2,8683.7 ; v1(8971.4,8708.7) 8971.4,8684.3 8972,8683.7 ; v1(9480.1,8708.7) 9480.1,8684.3 9480.7,8683.7 ; v1(9988.8,8708.7) 9988.8,8684.3 9989.4,8683.7 9480.7,8683.7 ; 7445.9,8683.7 7954.6,8683.7 ; 7954.6,8683.7 8463.2,8683.7 ; 8463.2,8683.7 8972,8683.7 ; 8972,8683.7 9480.7,8683.7
  Inner2 w23.6: v3(5882.1,8673.7) 5892.1,8683.7 6327.4,8683.7 6340,8671.2 6991.2,8671.2 7003.7,8683.7 v1(7326.2,8683.7)
  Inner4 w23.6: v3(5872.1,8150.1) 5872.1,8663.7 v3(5882.1,8673.7)
  Bottom Layer w7.9: U1$CBB17.7@5723.4,8100.1 U1$CBB17.6@5723.4,8150.1 v3(5872.1,8150.1)
W_M1_ROW3: Q6$CBB49/CBB3.3 Q6$CBB49/CBB9.3 Q6$CBB49/CBB15.3 Q6$CBB49/CBB21.3 Q6$CBB49/CBB27.3 Q6$CBB49/CBB33.3 Q9$CBB49/CBB3.3 Q9$CBB49/CBB9.3 Q9$CBB49/CBB15.3 Q9$CBB49/CBB21.3 Q9$CBB49/CBB27.3 Q9$CBB49/CBB33.3 U1$CBB17.8 U1$CBB17.9 | length 5355.6
  Top Layer w7.9: v1(7445.3,7923.7) 7448.8,7927.2 7448.8,7969 7448.4,7969.4 7448.4,7984.2 7448.8,7984.6 Q9$CBB49/CBB3.3@7448.8,8008.7 ; v1(7954,7923.7) 7957.5,7927.2 7957.5,7969 7957.1,7969.4 7957.1,7984.2 7957.5,7984.6 Q9$CBB49/CBB9.3@7957.5,8008.7 ; v1(8462.7,7923.7) 8466.2,7927.2 8466.2,7969 8465.8,7969.4 8465.8,7984.1 8466.2,7984.5 Q9$CBB49/CBB15.3@8466.2,8008.7 ; v1(8971.4,7923.7) 8974.9,7927.2 8974.9,7969 8974.5,7969.4 8974.5,7984.2 8974.9,7984.6 Q9$CBB49/CBB21.3@8974.9,8008.7 ; v1(9480.1,7923.7) 9483.6,7927.2 9483.6,7969 9483.2,7969.4 9483.2,7984.2 9483.6,7984.6 Q9$CBB49/CBB27.3@9483.6,8008.7 ; v1(9988.8,7923.7) 9992.3,7927.2 9992.3,7969 9991.9,7969.4 9991.9,7984.2 9992.3,7984.6 Q9$CBB49/CBB33.3@9992.3,8008.7
  Inner2 w7.9: v1(7326.2,7898.7) 7445.9,7898.7 ; v1(7445.3,7923.7) 7445.3,7899.3 7445.9,7898.7 ; v1(7954,7923.7) 7954,7899.3 7954.6,7898.7 ; v1(8462.7,7923.7) 8462.7,7899.3 8463.2,7898.7 ; v1(8971.4,7923.7) 8971.4,7899.3 8972,7898.7 ; v1(9480.1,7923.7) 9480.1,7899.3 9480.7,7898.7 ; v1(9988.8,7923.7) 9988.8,7899.3 9989.4,7898.7 9480.7,7898.7 ; 7445.9,7898.7 7954.6,7898.7 ; 7954.6,7898.7 8463.2,7898.7 ; 8463.2,7898.7 8972,7898.7 ; 8972,7898.7 9480.7,7898.7
  Inner2 w19.7: v3(5583.9,7963.7) 5644.1,7963.7 5647.3,7966.9 6671.8,7966.9 6740,7898.7 v1(7326.2,7898.7)
  Bottom Layer w7.9: U1$CBB17.8@5505.4,8100.1 U1$CBB17.9@5505.4,8150.1
  Bottom Layer w19.7: U1$CBB17.8@5505.4,8100.1 5555.8,8100.1 5583.9,8072 v3(5583.9,7963.7)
